VERSION 5.8 ;
BUSBITCHARS "[]" ;
DIVIDERCHAR "/" ;
UNITS
    DATABASE MICRONS 1000 ;
END UNITS

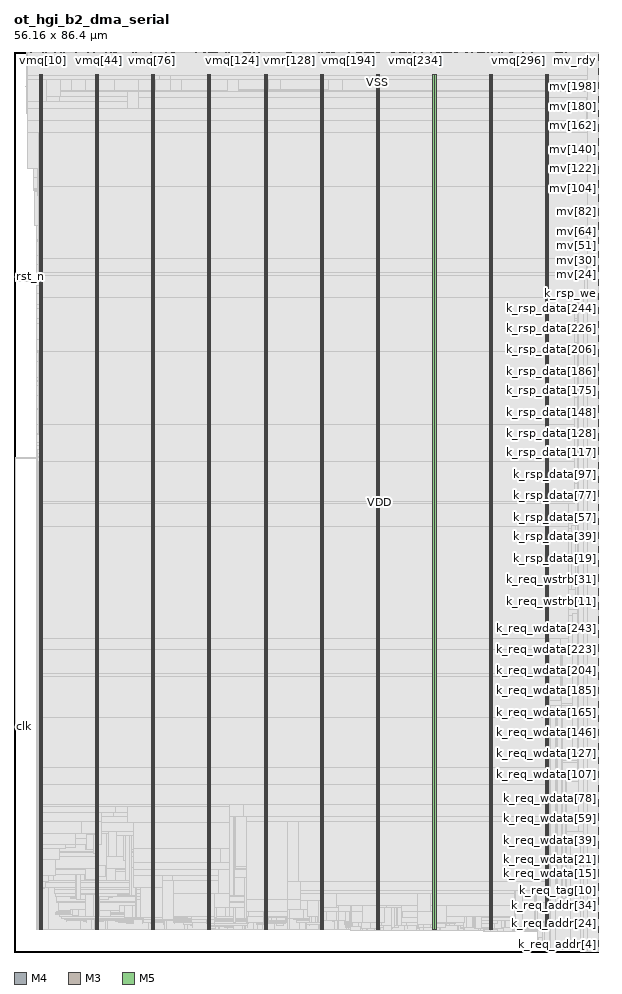
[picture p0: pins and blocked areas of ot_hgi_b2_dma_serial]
MACRO ot_hgi_b2_dma_serial
  FOREIGN ot_hgi_b2_dma_serial 0 0 ;
  CLASS BLOCK ;
  SIZE 56.16 BY 86.4 ;
  PIN clk
    DIRECTION INPUT ;
    USE SIGNAL ;
    PORT
      LAYER M4 ;
        RECT  0 21.6 0.084 21.624 ;
    END
    PORT
      LAYER M4 ;
        RECT  0.06 21.6 0.179 21.624 ;
    END
  END clk
  PIN fence_rdy
    DIRECTION OUTPUT ;
    USE SIGNAL ;
    PORT
      LAYER M4 ;
        RECT  56.076 0.048 56.16 0.072 ;
    END
  END fence_rdy
  PIN k_fault
    DIRECTION INPUT ;
    USE SIGNAL ;
    PORT
      LAYER M4 ;
        RECT  56.076 0.144 56.16 0.168 ;
    END
  END k_fault
  PIN k_req_addr[0]
    DIRECTION OUTPUT ;
    USE SIGNAL ;
    PORT
      LAYER M4 ;
        RECT  56.076 0.24 56.16 0.264 ;
    END
  END k_req_addr[0]
  PIN k_req_addr[10]
    DIRECTION OUTPUT ;
    USE SIGNAL ;
    PORT
      LAYER M4 ;
        RECT  56.076 1.296 56.16 1.32 ;
    END
  END k_req_addr[10]
  PIN k_req_addr[11]
    DIRECTION OUTPUT ;
    USE SIGNAL ;
    PORT
      LAYER M4 ;
        RECT  56.076 1.392 56.16 1.416 ;
    END
  END k_req_addr[11]
  PIN k_req_addr[12]
    DIRECTION OUTPUT ;
    USE SIGNAL ;
    PORT
      LAYER M4 ;
        RECT  56.076 1.488 56.16 1.512 ;
    END
  END k_req_addr[12]
  PIN k_req_addr[13]
    DIRECTION OUTPUT ;
    USE SIGNAL ;
    PORT
      LAYER M4 ;
        RECT  56.076 1.584 56.16 1.608 ;
    END
  END k_req_addr[13]
  PIN k_req_addr[14]
    DIRECTION OUTPUT ;
    USE SIGNAL ;
    PORT
      LAYER M4 ;
        RECT  56.076 1.68 56.16 1.704 ;
    END
  END k_req_addr[14]
  PIN k_req_addr[15]
    DIRECTION OUTPUT ;
    USE SIGNAL ;
    PORT
      LAYER M4 ;
        RECT  56.076 1.776 56.16 1.8 ;
    END
  END k_req_addr[15]
  PIN k_req_addr[16]
    DIRECTION OUTPUT ;
    USE SIGNAL ;
    PORT
      LAYER M4 ;
        RECT  56.076 1.92 56.16 1.944 ;
    END
  END k_req_addr[16]
  PIN k_req_addr[17]
    DIRECTION OUTPUT ;
    USE SIGNAL ;
    PORT
      LAYER M4 ;
        RECT  56.076 2.016 56.16 2.04 ;
    END
  END k_req_addr[17]
  PIN k_req_addr[18]
    DIRECTION OUTPUT ;
    USE SIGNAL ;
    PORT
      LAYER M4 ;
        RECT  56.076 2.112 56.16 2.136 ;
    END
  END k_req_addr[18]
  PIN k_req_addr[19]
    DIRECTION OUTPUT ;
    USE SIGNAL ;
    PORT
      LAYER M4 ;
        RECT  56.076 2.208 56.16 2.232 ;
    END
  END k_req_addr[19]
  PIN k_req_addr[1]
    DIRECTION OUTPUT ;
    USE SIGNAL ;
    PORT
      LAYER M4 ;
        RECT  56.076 0.336 56.16 0.36 ;
    END
  END k_req_addr[1]
  PIN k_req_addr[20]
    DIRECTION OUTPUT ;
    USE SIGNAL ;
    PORT
      LAYER M4 ;
        RECT  56.076 2.304 56.16 2.328 ;
    END
  END k_req_addr[20]
  PIN k_req_addr[21]
    DIRECTION OUTPUT ;
    USE SIGNAL ;
    PORT
      LAYER M4 ;
        RECT  56.076 2.4 56.16 2.424 ;
    END
  END k_req_addr[21]
  PIN k_req_addr[22]
    DIRECTION OUTPUT ;
    USE SIGNAL ;
    PORT
      LAYER M4 ;
        RECT  56.076 2.544 56.16 2.568 ;
    END
  END k_req_addr[22]
  PIN k_req_addr[23]
    DIRECTION OUTPUT ;
    USE SIGNAL ;
    PORT
      LAYER M4 ;
        RECT  56.076 2.64 56.16 2.664 ;
    END
  END k_req_addr[23]
  PIN k_req_addr[24]
    DIRECTION OUTPUT ;
    USE SIGNAL ;
    PORT
      LAYER M4 ;
        RECT  56.076 2.736 56.16 2.76 ;
    END
  END k_req_addr[24]
  PIN k_req_addr[25]
    DIRECTION OUTPUT ;
    USE SIGNAL ;
    PORT
      LAYER M4 ;
        RECT  56.076 2.832 56.16 2.856 ;
    END
  END k_req_addr[25]
  PIN k_req_addr[26]
    DIRECTION OUTPUT ;
    USE SIGNAL ;
    PORT
      LAYER M4 ;
        RECT  56.076 2.928 56.16 2.952 ;
    END
  END k_req_addr[26]
  PIN k_req_addr[27]
    DIRECTION OUTPUT ;
    USE SIGNAL ;
    PORT
      LAYER M4 ;
        RECT  56.076 3.024 56.16 3.048 ;
    END
  END k_req_addr[27]
  PIN k_req_addr[28]
    DIRECTION OUTPUT ;
    USE SIGNAL ;
    PORT
      LAYER M4 ;
        RECT  56.076 3.12 56.16 3.144 ;
    END
  END k_req_addr[28]
  PIN k_req_addr[29]
    DIRECTION OUTPUT ;
    USE SIGNAL ;
    PORT
      LAYER M4 ;
        RECT  56.076 3.264 56.16 3.288 ;
    END
  END k_req_addr[29]
  PIN k_req_addr[2]
    DIRECTION OUTPUT ;
    USE SIGNAL ;
    PORT
      LAYER M4 ;
        RECT  56.076 0.432 56.16 0.456 ;
    END
  END k_req_addr[2]
  PIN k_req_addr[30]
    DIRECTION OUTPUT ;
    USE SIGNAL ;
    PORT
      LAYER M4 ;
        RECT  56.076 3.36 56.16 3.384 ;
    END
  END k_req_addr[30]
  PIN k_req_addr[31]
    DIRECTION OUTPUT ;
    USE SIGNAL ;
    PORT
      LAYER M4 ;
        RECT  56.076 3.456 56.16 3.48 ;
    END
  END k_req_addr[31]
  PIN k_req_addr[32]
    DIRECTION OUTPUT ;
    USE SIGNAL ;
    PORT
      LAYER M4 ;
        RECT  56.076 3.552 56.16 3.576 ;
    END
  END k_req_addr[32]
  PIN k_req_addr[33]
    DIRECTION OUTPUT ;
    USE SIGNAL ;
    PORT
      LAYER M4 ;
        RECT  56.076 3.648 56.16 3.672 ;
    END
  END k_req_addr[33]
  PIN k_req_addr[34]
    DIRECTION OUTPUT ;
    USE SIGNAL ;
    PORT
      LAYER M4 ;
        RECT  56.076 3.744 56.16 3.768 ;
    END
  END k_req_addr[34]
  PIN k_req_addr[35]
    DIRECTION OUTPUT ;
    USE SIGNAL ;
    PORT
      LAYER M4 ;
        RECT  56.076 3.888 56.16 3.912 ;
    END
  END k_req_addr[35]
  PIN k_req_addr[36]
    DIRECTION OUTPUT ;
    USE SIGNAL ;
    PORT
      LAYER M4 ;
        RECT  56.076 3.984 56.16 4.008 ;
    END
  END k_req_addr[36]
  PIN k_req_addr[3]
    DIRECTION OUTPUT ;
    USE SIGNAL ;
    PORT
      LAYER M4 ;
        RECT  56.076 0.576 56.16 0.6 ;
    END
  END k_req_addr[3]
  PIN k_req_addr[4]
    DIRECTION OUTPUT ;
    USE SIGNAL ;
    PORT
      LAYER M4 ;
        RECT  56.076 0.672 56.16 0.696 ;
    END
  END k_req_addr[4]
  PIN k_req_addr[5]
    DIRECTION OUTPUT ;
    USE SIGNAL ;
    PORT
      LAYER M4 ;
        RECT  56.076 0.768 56.16 0.792 ;
    END
  END k_req_addr[5]
  PIN k_req_addr[6]
    DIRECTION OUTPUT ;
    USE SIGNAL ;
    PORT
      LAYER M4 ;
        RECT  56.076 0.864 56.16 0.888 ;
    END
  END k_req_addr[6]
  PIN k_req_addr[7]
    DIRECTION OUTPUT ;
    USE SIGNAL ;
    PORT
      LAYER M4 ;
        RECT  56.076 0.96 56.16 0.984 ;
    END
  END k_req_addr[7]
  PIN k_req_addr[8]
    DIRECTION OUTPUT ;
    USE SIGNAL ;
    PORT
      LAYER M4 ;
        RECT  56.076 1.056 56.16 1.08 ;
    END
  END k_req_addr[8]
  PIN k_req_addr[9]
    DIRECTION OUTPUT ;
    USE SIGNAL ;
    PORT
      LAYER M4 ;
        RECT  56.076 1.2 56.16 1.224 ;
    END
  END k_req_addr[9]
  PIN k_req_rdy
    DIRECTION INPUT ;
    USE SIGNAL ;
    PORT
      LAYER M4 ;
        RECT  56.076 4.08 56.16 4.104 ;
    END
  END k_req_rdy
  PIN k_req_tag[0]
    DIRECTION OUTPUT ;
    USE SIGNAL ;
    PORT
      LAYER M4 ;
        RECT  56.076 4.176 56.16 4.2 ;
    END
  END k_req_tag[0]
  PIN k_req_tag[10]
    DIRECTION OUTPUT ;
    USE SIGNAL ;
    PORT
      LAYER M4 ;
        RECT  56.076 5.184 56.16 5.208 ;
    END
  END k_req_tag[10]
  PIN k_req_tag[11]
    DIRECTION OUTPUT ;
    USE SIGNAL ;
    PORT
      LAYER M4 ;
        RECT  56.076 5.328 56.16 5.352 ;
    END
  END k_req_tag[11]
  PIN k_req_tag[12]
    DIRECTION OUTPUT ;
    USE SIGNAL ;
    PORT
      LAYER M4 ;
        RECT  56.076 5.424 56.16 5.448 ;
    END
  END k_req_tag[12]
  PIN k_req_tag[13]
    DIRECTION OUTPUT ;
    USE SIGNAL ;
    PORT
      LAYER M4 ;
        RECT  56.076 5.52 56.16 5.544 ;
    END
  END k_req_tag[13]
  PIN k_req_tag[14]
    DIRECTION OUTPUT ;
    USE SIGNAL ;
    PORT
      LAYER M4 ;
        RECT  56.076 5.616 56.16 5.64 ;
    END
  END k_req_tag[14]
  PIN k_req_tag[15]
    DIRECTION OUTPUT ;
    USE SIGNAL ;
    PORT
      LAYER M4 ;
        RECT  56.076 5.712 56.16 5.736 ;
    END
  END k_req_tag[15]
  PIN k_req_tag[1]
    DIRECTION OUTPUT ;
    USE SIGNAL ;
    PORT
      LAYER M4 ;
        RECT  56.076 4.272 56.16 4.296 ;
    END
  END k_req_tag[1]
  PIN k_req_tag[2]
    DIRECTION OUTPUT ;
    USE SIGNAL ;
    PORT
      LAYER M4 ;
        RECT  56.076 4.368 56.16 4.392 ;
    END
  END k_req_tag[2]
  PIN k_req_tag[3]
    DIRECTION OUTPUT ;
    USE SIGNAL ;
    PORT
      LAYER M4 ;
        RECT  56.076 4.464 56.16 4.488 ;
    END
  END k_req_tag[3]
  PIN k_req_tag[4]
    DIRECTION OUTPUT ;
    USE SIGNAL ;
    PORT
      LAYER M4 ;
        RECT  56.076 4.608 56.16 4.632 ;
    END
  END k_req_tag[4]
  PIN k_req_tag[5]
    DIRECTION OUTPUT ;
    USE SIGNAL ;
    PORT
      LAYER M4 ;
        RECT  56.076 4.704 56.16 4.728 ;
    END
  END k_req_tag[5]
  PIN k_req_tag[6]
    DIRECTION OUTPUT ;
    USE SIGNAL ;
    PORT
      LAYER M4 ;
        RECT  56.076 4.8 56.16 4.824 ;
    END
  END k_req_tag[6]
  PIN k_req_tag[7]
    DIRECTION OUTPUT ;
    USE SIGNAL ;
    PORT
      LAYER M4 ;
        RECT  56.076 4.896 56.16 4.92 ;
    END
  END k_req_tag[7]
  PIN k_req_tag[8]
    DIRECTION OUTPUT ;
    USE SIGNAL ;
    PORT
      LAYER M4 ;
        RECT  56.076 4.992 56.16 5.016 ;
    END
  END k_req_tag[8]
  PIN k_req_tag[9]
    DIRECTION OUTPUT ;
    USE SIGNAL ;
    PORT
      LAYER M4 ;
        RECT  56.076 5.088 56.16 5.112 ;
    END
  END k_req_tag[9]
  PIN k_req_v
    DIRECTION OUTPUT ;
    USE SIGNAL ;
    PORT
      LAYER M4 ;
        RECT  56.076 5.808 56.16 5.832 ;
    END
  END k_req_v
  PIN k_req_wdata[0]
    DIRECTION OUTPUT ;
    USE SIGNAL ;
    PORT
      LAYER M4 ;
        RECT  56.076 5.952 56.16 5.976 ;
    END
  END k_req_wdata[0]
  PIN k_req_wdata[100]
    DIRECTION OUTPUT ;
    USE SIGNAL ;
    PORT
      LAYER M4 ;
        RECT  56.076 16.272 56.16 16.296 ;
    END
  END k_req_wdata[100]
  PIN k_req_wdata[101]
    DIRECTION OUTPUT ;
    USE SIGNAL ;
    PORT
      LAYER M4 ;
        RECT  56.076 16.368 56.16 16.392 ;
    END
  END k_req_wdata[101]
  PIN k_req_wdata[102]
    DIRECTION OUTPUT ;
    USE SIGNAL ;
    PORT
      LAYER M4 ;
        RECT  56.076 16.464 56.16 16.488 ;
    END
  END k_req_wdata[102]
  PIN k_req_wdata[103]
    DIRECTION OUTPUT ;
    USE SIGNAL ;
    PORT
      LAYER M4 ;
        RECT  56.076 16.56 56.16 16.584 ;
    END
  END k_req_wdata[103]
  PIN k_req_wdata[104]
    DIRECTION OUTPUT ;
    USE SIGNAL ;
    PORT
      LAYER M4 ;
        RECT  56.076 16.656 56.16 16.68 ;
    END
  END k_req_wdata[104]
  PIN k_req_wdata[105]
    DIRECTION OUTPUT ;
    USE SIGNAL ;
    PORT
      LAYER M4 ;
        RECT  56.076 16.8 56.16 16.824 ;
    END
  END k_req_wdata[105]
  PIN k_req_wdata[106]
    DIRECTION OUTPUT ;
    USE SIGNAL ;
    PORT
      LAYER M4 ;
        RECT  56.076 16.896 56.16 16.92 ;
    END
  END k_req_wdata[106]
  PIN k_req_wdata[107]
    DIRECTION OUTPUT ;
    USE SIGNAL ;
    PORT
      LAYER M4 ;
        RECT  56.076 16.992 56.16 17.016 ;
    END
  END k_req_wdata[107]
  PIN k_req_wdata[108]
    DIRECTION OUTPUT ;
    USE SIGNAL ;
    PORT
      LAYER M4 ;
        RECT  56.076 17.088 56.16 17.112 ;
    END
  END k_req_wdata[108]
  PIN k_req_wdata[109]
    DIRECTION OUTPUT ;
    USE SIGNAL ;
    PORT
      LAYER M4 ;
        RECT  56.076 17.184 56.16 17.208 ;
    END
  END k_req_wdata[109]
  PIN k_req_wdata[10]
    DIRECTION OUTPUT ;
    USE SIGNAL ;
    PORT
      LAYER M4 ;
        RECT  56.076 6.96 56.16 6.984 ;
    END
  END k_req_wdata[10]
  PIN k_req_wdata[110]
    DIRECTION OUTPUT ;
    USE SIGNAL ;
    PORT
      LAYER M4 ;
        RECT  56.076 17.28 56.16 17.304 ;
    END
  END k_req_wdata[110]
  PIN k_req_wdata[111]
    DIRECTION OUTPUT ;
    USE SIGNAL ;
    PORT
      LAYER M4 ;
        RECT  56.076 17.424 56.16 17.448 ;
    END
  END k_req_wdata[111]
  PIN k_req_wdata[112]
    DIRECTION OUTPUT ;
    USE SIGNAL ;
    PORT
      LAYER M4 ;
        RECT  56.076 17.52 56.16 17.544 ;
    END
  END k_req_wdata[112]
  PIN k_req_wdata[113]
    DIRECTION OUTPUT ;
    USE SIGNAL ;
    PORT
      LAYER M4 ;
        RECT  56.076 17.616 56.16 17.64 ;
    END
  END k_req_wdata[113]
  PIN k_req_wdata[114]
    DIRECTION OUTPUT ;
    USE SIGNAL ;
    PORT
      LAYER M4 ;
        RECT  56.076 17.712 56.16 17.736 ;
    END
  END k_req_wdata[114]
  PIN k_req_wdata[115]
    DIRECTION OUTPUT ;
    USE SIGNAL ;
    PORT
      LAYER M4 ;
        RECT  56.076 17.808 56.16 17.832 ;
    END
  END k_req_wdata[115]
  PIN k_req_wdata[116]
    DIRECTION OUTPUT ;
    USE SIGNAL ;
    PORT
      LAYER M4 ;
        RECT  56.076 17.904 56.16 17.928 ;
    END
  END k_req_wdata[116]
  PIN k_req_wdata[117]
    DIRECTION OUTPUT ;
    USE SIGNAL ;
    PORT
      LAYER M4 ;
        RECT  56.076 18 56.16 18.024 ;
    END
  END k_req_wdata[117]
  PIN k_req_wdata[118]
    DIRECTION OUTPUT ;
    USE SIGNAL ;
    PORT
      LAYER M4 ;
        RECT  56.076 18.144 56.16 18.168 ;
    END
  END k_req_wdata[118]
  PIN k_req_wdata[119]
    DIRECTION OUTPUT ;
    USE SIGNAL ;
    PORT
      LAYER M4 ;
        RECT  56.076 18.24 56.16 18.264 ;
    END
  END k_req_wdata[119]
  PIN k_req_wdata[11]
    DIRECTION OUTPUT ;
    USE SIGNAL ;
    PORT
      LAYER M4 ;
        RECT  56.076 7.056 56.16 7.08 ;
    END
  END k_req_wdata[11]
  PIN k_req_wdata[120]
    DIRECTION OUTPUT ;
    USE SIGNAL ;
    PORT
      LAYER M4 ;
        RECT  56.076 18.336 56.16 18.36 ;
    END
  END k_req_wdata[120]
  PIN k_req_wdata[121]
    DIRECTION OUTPUT ;
    USE SIGNAL ;
    PORT
      LAYER M4 ;
        RECT  56.076 18.432 56.16 18.456 ;
    END
  END k_req_wdata[121]
  PIN k_req_wdata[122]
    DIRECTION OUTPUT ;
    USE SIGNAL ;
    PORT
      LAYER M4 ;
        RECT  56.076 18.528 56.16 18.552 ;
    END
  END k_req_wdata[122]
  PIN k_req_wdata[123]
    DIRECTION OUTPUT ;
    USE SIGNAL ;
    PORT
      LAYER M4 ;
        RECT  56.076 18.624 56.16 18.648 ;
    END
  END k_req_wdata[123]
  PIN k_req_wdata[124]
    DIRECTION OUTPUT ;
    USE SIGNAL ;
    PORT
      LAYER M4 ;
        RECT  56.076 18.768 56.16 18.792 ;
    END
  END k_req_wdata[124]
  PIN k_req_wdata[125]
    DIRECTION OUTPUT ;
    USE SIGNAL ;
    PORT
      LAYER M4 ;
        RECT  56.076 18.864 56.16 18.888 ;
    END
  END k_req_wdata[125]
  PIN k_req_wdata[126]
    DIRECTION OUTPUT ;
    USE SIGNAL ;
    PORT
      LAYER M4 ;
        RECT  56.076 18.96 56.16 18.984 ;
    END
  END k_req_wdata[126]
  PIN k_req_wdata[127]
    DIRECTION OUTPUT ;
    USE SIGNAL ;
    PORT
      LAYER M4 ;
        RECT  56.076 19.056 56.16 19.08 ;
    END
  END k_req_wdata[127]
  PIN k_req_wdata[128]
    DIRECTION OUTPUT ;
    USE SIGNAL ;
    PORT
      LAYER M4 ;
        RECT  56.076 19.152 56.16 19.176 ;
    END
  END k_req_wdata[128]
  PIN k_req_wdata[129]
    DIRECTION OUTPUT ;
    USE SIGNAL ;
    PORT
      LAYER M4 ;
        RECT  56.076 19.248 56.16 19.272 ;
    END
  END k_req_wdata[129]
  PIN k_req_wdata[12]
    DIRECTION OUTPUT ;
    USE SIGNAL ;
    PORT
      LAYER M4 ;
        RECT  56.076 7.152 56.16 7.176 ;
    END
  END k_req_wdata[12]
  PIN k_req_wdata[130]
    DIRECTION OUTPUT ;
    USE SIGNAL ;
    PORT
      LAYER M4 ;
        RECT  56.076 19.344 56.16 19.368 ;
    END
  END k_req_wdata[130]
  PIN k_req_wdata[131]
    DIRECTION OUTPUT ;
    USE SIGNAL ;
    PORT
      LAYER M4 ;
        RECT  56.076 19.488 56.16 19.512 ;
    END
  END k_req_wdata[131]
  PIN k_req_wdata[132]
    DIRECTION OUTPUT ;
    USE SIGNAL ;
    PORT
      LAYER M4 ;
        RECT  56.076 19.584 56.16 19.608 ;
    END
  END k_req_wdata[132]
  PIN k_req_wdata[133]
    DIRECTION OUTPUT ;
    USE SIGNAL ;
    PORT
      LAYER M4 ;
        RECT  56.076 19.68 56.16 19.704 ;
    END
  END k_req_wdata[133]
  PIN k_req_wdata[134]
    DIRECTION OUTPUT ;
    USE SIGNAL ;
    PORT
      LAYER M4 ;
        RECT  56.076 19.776 56.16 19.8 ;
    END
  END k_req_wdata[134]
  PIN k_req_wdata[135]
    DIRECTION OUTPUT ;
    USE SIGNAL ;
    PORT
      LAYER M4 ;
        RECT  56.076 19.872 56.16 19.896 ;
    END
  END k_req_wdata[135]
  PIN k_req_wdata[136]
    DIRECTION OUTPUT ;
    USE SIGNAL ;
    PORT
      LAYER M4 ;
        RECT  56.076 19.968 56.16 19.992 ;
    END
  END k_req_wdata[136]
  PIN k_req_wdata[137]
    DIRECTION OUTPUT ;
    USE SIGNAL ;
    PORT
      LAYER M4 ;
        RECT  56.076 20.112 56.16 20.136 ;
    END
  END k_req_wdata[137]
  PIN k_req_wdata[138]
    DIRECTION OUTPUT ;
    USE SIGNAL ;
    PORT
      LAYER M4 ;
        RECT  56.076 20.208 56.16 20.232 ;
    END
  END k_req_wdata[138]
  PIN k_req_wdata[139]
    DIRECTION OUTPUT ;
    USE SIGNAL ;
    PORT
      LAYER M4 ;
        RECT  56.076 20.304 56.16 20.328 ;
    END
  END k_req_wdata[139]
  PIN k_req_wdata[13]
    DIRECTION OUTPUT ;
    USE SIGNAL ;
    PORT
      LAYER M4 ;
        RECT  56.076 7.296 56.16 7.32 ;
    END
  END k_req_wdata[13]
  PIN k_req_wdata[140]
    DIRECTION OUTPUT ;
    USE SIGNAL ;
    PORT
      LAYER M4 ;
        RECT  56.076 20.4 56.16 20.424 ;
    END
  END k_req_wdata[140]
  PIN k_req_wdata[141]
    DIRECTION OUTPUT ;
    USE SIGNAL ;
    PORT
      LAYER M4 ;
        RECT  56.076 20.496 56.16 20.52 ;
    END
  END k_req_wdata[141]
  PIN k_req_wdata[142]
    DIRECTION OUTPUT ;
    USE SIGNAL ;
    PORT
      LAYER M4 ;
        RECT  56.076 20.592 56.16 20.616 ;
    END
  END k_req_wdata[142]
  PIN k_req_wdata[143]
    DIRECTION OUTPUT ;
    USE SIGNAL ;
    PORT
      LAYER M4 ;
        RECT  56.076 20.688 56.16 20.712 ;
    END
  END k_req_wdata[143]
  PIN k_req_wdata[144]
    DIRECTION OUTPUT ;
    USE SIGNAL ;
    PORT
      LAYER M4 ;
        RECT  56.076 20.832 56.16 20.856 ;
    END
  END k_req_wdata[144]
  PIN k_req_wdata[145]
    DIRECTION OUTPUT ;
    USE SIGNAL ;
    PORT
      LAYER M4 ;
        RECT  56.076 20.928 56.16 20.952 ;
    END
  END k_req_wdata[145]
  PIN k_req_wdata[146]
    DIRECTION OUTPUT ;
    USE SIGNAL ;
    PORT
      LAYER M4 ;
        RECT  56.076 21.024 56.16 21.048 ;
    END
  END k_req_wdata[146]
  PIN k_req_wdata[147]
    DIRECTION OUTPUT ;
    USE SIGNAL ;
    PORT
      LAYER M4 ;
        RECT  56.076 21.12 56.16 21.144 ;
    END
  END k_req_wdata[147]
  PIN k_req_wdata[148]
    DIRECTION OUTPUT ;
    USE SIGNAL ;
    PORT
      LAYER M4 ;
        RECT  56.076 21.216 56.16 21.24 ;
    END
  END k_req_wdata[148]
  PIN k_req_wdata[149]
    DIRECTION OUTPUT ;
    USE SIGNAL ;
    PORT
      LAYER M4 ;
        RECT  56.076 21.312 56.16 21.336 ;
    END
  END k_req_wdata[149]
  PIN k_req_wdata[14]
    DIRECTION OUTPUT ;
    USE SIGNAL ;
    PORT
      LAYER M4 ;
        RECT  56.076 7.392 56.16 7.416 ;
    END
  END k_req_wdata[14]
  PIN k_req_wdata[150]
    DIRECTION OUTPUT ;
    USE SIGNAL ;
    PORT
      LAYER M4 ;
        RECT  56.076 21.456 56.16 21.48 ;
    END
  END k_req_wdata[150]
  PIN k_req_wdata[151]
    DIRECTION OUTPUT ;
    USE SIGNAL ;
    PORT
      LAYER M4 ;
        RECT  56.076 21.552 56.16 21.576 ;
    END
  END k_req_wdata[151]
  PIN k_req_wdata[152]
    DIRECTION OUTPUT ;
    USE SIGNAL ;
    PORT
      LAYER M4 ;
        RECT  56.076 21.648 56.16 21.672 ;
    END
  END k_req_wdata[152]
  PIN k_req_wdata[153]
    DIRECTION OUTPUT ;
    USE SIGNAL ;
    PORT
      LAYER M4 ;
        RECT  56.076 21.744 56.16 21.768 ;
    END
  END k_req_wdata[153]
  PIN k_req_wdata[154]
    DIRECTION OUTPUT ;
    USE SIGNAL ;
    PORT
      LAYER M4 ;
        RECT  56.076 21.84 56.16 21.864 ;
    END
  END k_req_wdata[154]
  PIN k_req_wdata[155]
    DIRECTION OUTPUT ;
    USE SIGNAL ;
    PORT
      LAYER M4 ;
        RECT  56.076 21.936 56.16 21.96 ;
    END
  END k_req_wdata[155]
  PIN k_req_wdata[156]
    DIRECTION OUTPUT ;
    USE SIGNAL ;
    PORT
      LAYER M4 ;
        RECT  56.076 22.032 56.16 22.056 ;
    END
  END k_req_wdata[156]
  PIN k_req_wdata[157]
    DIRECTION OUTPUT ;
    USE SIGNAL ;
    PORT
      LAYER M4 ;
        RECT  56.076 22.176 56.16 22.2 ;
    END
  END k_req_wdata[157]
  PIN k_req_wdata[158]
    DIRECTION OUTPUT ;
    USE SIGNAL ;
    PORT
      LAYER M4 ;
        RECT  56.076 22.272 56.16 22.296 ;
    END
  END k_req_wdata[158]
  PIN k_req_wdata[159]
    DIRECTION OUTPUT ;
    USE SIGNAL ;
    PORT
      LAYER M4 ;
        RECT  56.076 22.368 56.16 22.392 ;
    END
  END k_req_wdata[159]
  PIN k_req_wdata[15]
    DIRECTION OUTPUT ;
    USE SIGNAL ;
    PORT
      LAYER M4 ;
        RECT  56.076 7.488 56.16 7.512 ;
    END
  END k_req_wdata[15]
  PIN k_req_wdata[160]
    DIRECTION OUTPUT ;
    USE SIGNAL ;
    PORT
      LAYER M4 ;
        RECT  56.076 22.464 56.16 22.488 ;
    END
  END k_req_wdata[160]
  PIN k_req_wdata[161]
    DIRECTION OUTPUT ;
    USE SIGNAL ;
    PORT
      LAYER M4 ;
        RECT  56.076 22.56 56.16 22.584 ;
    END
  END k_req_wdata[161]
  PIN k_req_wdata[162]
    DIRECTION OUTPUT ;
    USE SIGNAL ;
    PORT
      LAYER M4 ;
        RECT  56.076 22.656 56.16 22.68 ;
    END
  END k_req_wdata[162]
  PIN k_req_wdata[163]
    DIRECTION OUTPUT ;
    USE SIGNAL ;
    PORT
      LAYER M4 ;
        RECT  56.076 22.8 56.16 22.824 ;
    END
  END k_req_wdata[163]
  PIN k_req_wdata[164]
    DIRECTION OUTPUT ;
    USE SIGNAL ;
    PORT
      LAYER M4 ;
        RECT  56.076 22.896 56.16 22.92 ;
    END
  END k_req_wdata[164]
  PIN k_req_wdata[165]
    DIRECTION OUTPUT ;
    USE SIGNAL ;
    PORT
      LAYER M4 ;
        RECT  56.076 22.992 56.16 23.016 ;
    END
  END k_req_wdata[165]
  PIN k_req_wdata[166]
    DIRECTION OUTPUT ;
    USE SIGNAL ;
    PORT
      LAYER M4 ;
        RECT  56.076 23.088 56.16 23.112 ;
    END
  END k_req_wdata[166]
  PIN k_req_wdata[167]
    DIRECTION OUTPUT ;
    USE SIGNAL ;
    PORT
      LAYER M4 ;
        RECT  56.076 23.184 56.16 23.208 ;
    END
  END k_req_wdata[167]
  PIN k_req_wdata[168]
    DIRECTION OUTPUT ;
    USE SIGNAL ;
    PORT
      LAYER M4 ;
        RECT  56.076 23.28 56.16 23.304 ;
    END
  END k_req_wdata[168]
  PIN k_req_wdata[169]
    DIRECTION OUTPUT ;
    USE SIGNAL ;
    PORT
      LAYER M4 ;
        RECT  56.076 23.376 56.16 23.4 ;
    END
  END k_req_wdata[169]
  PIN k_req_wdata[16]
    DIRECTION OUTPUT ;
    USE SIGNAL ;
    PORT
      LAYER M4 ;
        RECT  56.076 7.584 56.16 7.608 ;
    END
  END k_req_wdata[16]
  PIN k_req_wdata[170]
    DIRECTION OUTPUT ;
    USE SIGNAL ;
    PORT
      LAYER M4 ;
        RECT  56.076 23.52 56.16 23.544 ;
    END
  END k_req_wdata[170]
  PIN k_req_wdata[171]
    DIRECTION OUTPUT ;
    USE SIGNAL ;
    PORT
      LAYER M4 ;
        RECT  56.076 23.616 56.16 23.64 ;
    END
  END k_req_wdata[171]
  PIN k_req_wdata[172]
    DIRECTION OUTPUT ;
    USE SIGNAL ;
    PORT
      LAYER M4 ;
        RECT  56.076 23.712 56.16 23.736 ;
    END
  END k_req_wdata[172]
  PIN k_req_wdata[173]
    DIRECTION OUTPUT ;
    USE SIGNAL ;
    PORT
      LAYER M4 ;
        RECT  56.076 23.808 56.16 23.832 ;
    END
  END k_req_wdata[173]
  PIN k_req_wdata[174]
    DIRECTION OUTPUT ;
    USE SIGNAL ;
    PORT
      LAYER M4 ;
        RECT  56.076 23.904 56.16 23.928 ;
    END
  END k_req_wdata[174]
  PIN k_req_wdata[175]
    DIRECTION OUTPUT ;
    USE SIGNAL ;
    PORT
      LAYER M4 ;
        RECT  56.076 24 56.16 24.024 ;
    END
  END k_req_wdata[175]
  PIN k_req_wdata[176]
    DIRECTION OUTPUT ;
    USE SIGNAL ;
    PORT
      LAYER M4 ;
        RECT  56.076 24.144 56.16 24.168 ;
    END
  END k_req_wdata[176]
  PIN k_req_wdata[177]
    DIRECTION OUTPUT ;
    USE SIGNAL ;
    PORT
      LAYER M4 ;
        RECT  56.076 24.24 56.16 24.264 ;
    END
  END k_req_wdata[177]
  PIN k_req_wdata[178]
    DIRECTION OUTPUT ;
    USE SIGNAL ;
    PORT
      LAYER M4 ;
        RECT  56.076 24.336 56.16 24.36 ;
    END
  END k_req_wdata[178]
  PIN k_req_wdata[179]
    DIRECTION OUTPUT ;
    USE SIGNAL ;
    PORT
      LAYER M4 ;
        RECT  56.076 24.432 56.16 24.456 ;
    END
  END k_req_wdata[179]
  PIN k_req_wdata[17]
    DIRECTION OUTPUT ;
    USE SIGNAL ;
    PORT
      LAYER M4 ;
        RECT  56.076 7.68 56.16 7.704 ;
    END
  END k_req_wdata[17]
  PIN k_req_wdata[180]
    DIRECTION OUTPUT ;
    USE SIGNAL ;
    PORT
      LAYER M4 ;
        RECT  56.076 24.528 56.16 24.552 ;
    END
  END k_req_wdata[180]
  PIN k_req_wdata[181]
    DIRECTION OUTPUT ;
    USE SIGNAL ;
    PORT
      LAYER M4 ;
        RECT  56.076 24.624 56.16 24.648 ;
    END
  END k_req_wdata[181]
  PIN k_req_wdata[182]
    DIRECTION OUTPUT ;
    USE SIGNAL ;
    PORT
      LAYER M4 ;
        RECT  56.076 24.72 56.16 24.744 ;
    END
  END k_req_wdata[182]
  PIN k_req_wdata[183]
    DIRECTION OUTPUT ;
    USE SIGNAL ;
    PORT
      LAYER M4 ;
        RECT  56.076 24.864 56.16 24.888 ;
    END
  END k_req_wdata[183]
  PIN k_req_wdata[184]
    DIRECTION OUTPUT ;
    USE SIGNAL ;
    PORT
      LAYER M4 ;
        RECT  56.076 24.96 56.16 24.984 ;
    END
  END k_req_wdata[184]
  PIN k_req_wdata[185]
    DIRECTION OUTPUT ;
    USE SIGNAL ;
    PORT
      LAYER M4 ;
        RECT  56.076 25.056 56.16 25.08 ;
    END
  END k_req_wdata[185]
  PIN k_req_wdata[186]
    DIRECTION OUTPUT ;
    USE SIGNAL ;
    PORT
      LAYER M4 ;
        RECT  56.076 25.152 56.16 25.176 ;
    END
  END k_req_wdata[186]
  PIN k_req_wdata[187]
    DIRECTION OUTPUT ;
    USE SIGNAL ;
    PORT
      LAYER M4 ;
        RECT  56.076 25.248 56.16 25.272 ;
    END
  END k_req_wdata[187]
  PIN k_req_wdata[188]
    DIRECTION OUTPUT ;
    USE SIGNAL ;
    PORT
      LAYER M4 ;
        RECT  56.076 25.344 56.16 25.368 ;
    END
  END k_req_wdata[188]
  PIN k_req_wdata[189]
    DIRECTION OUTPUT ;
    USE SIGNAL ;
    PORT
      LAYER M4 ;
        RECT  56.076 25.488 56.16 25.512 ;
    END
  END k_req_wdata[189]
  PIN k_req_wdata[18]
    DIRECTION OUTPUT ;
    USE SIGNAL ;
    PORT
      LAYER M4 ;
        RECT  56.076 7.776 56.16 7.8 ;
    END
  END k_req_wdata[18]
  PIN k_req_wdata[190]
    DIRECTION OUTPUT ;
    USE SIGNAL ;
    PORT
      LAYER M4 ;
        RECT  56.076 25.584 56.16 25.608 ;
    END
  END k_req_wdata[190]
  PIN k_req_wdata[191]
    DIRECTION OUTPUT ;
    USE SIGNAL ;
    PORT
      LAYER M4 ;
        RECT  56.076 25.68 56.16 25.704 ;
    END
  END k_req_wdata[191]
  PIN k_req_wdata[192]
    DIRECTION OUTPUT ;
    USE SIGNAL ;
    PORT
      LAYER M4 ;
        RECT  56.076 25.776 56.16 25.8 ;
    END
  END k_req_wdata[192]
  PIN k_req_wdata[193]
    DIRECTION OUTPUT ;
    USE SIGNAL ;
    PORT
      LAYER M4 ;
        RECT  56.076 25.872 56.16 25.896 ;
    END
  END k_req_wdata[193]
  PIN k_req_wdata[194]
    DIRECTION OUTPUT ;
    USE SIGNAL ;
    PORT
      LAYER M4 ;
        RECT  56.076 25.968 56.16 25.992 ;
    END
  END k_req_wdata[194]
  PIN k_req_wdata[195]
    DIRECTION OUTPUT ;
    USE SIGNAL ;
    PORT
      LAYER M4 ;
        RECT  56.076 26.064 56.16 26.088 ;
    END
  END k_req_wdata[195]
  PIN k_req_wdata[196]
    DIRECTION OUTPUT ;
    USE SIGNAL ;
    PORT
      LAYER M4 ;
        RECT  56.076 26.208 56.16 26.232 ;
    END
  END k_req_wdata[196]
  PIN k_req_wdata[197]
    DIRECTION OUTPUT ;
    USE SIGNAL ;
    PORT
      LAYER M4 ;
        RECT  56.076 26.304 56.16 26.328 ;
    END
  END k_req_wdata[197]
  PIN k_req_wdata[198]
    DIRECTION OUTPUT ;
    USE SIGNAL ;
    PORT
      LAYER M4 ;
        RECT  56.076 26.4 56.16 26.424 ;
    END
  END k_req_wdata[198]
  PIN k_req_wdata[199]
    DIRECTION OUTPUT ;
    USE SIGNAL ;
    PORT
      LAYER M4 ;
        RECT  56.076 26.496 56.16 26.52 ;
    END
  END k_req_wdata[199]
  PIN k_req_wdata[19]
    DIRECTION OUTPUT ;
    USE SIGNAL ;
    PORT
      LAYER M4 ;
        RECT  56.076 7.872 56.16 7.896 ;
    END
  END k_req_wdata[19]
  PIN k_req_wdata[1]
    DIRECTION OUTPUT ;
    USE SIGNAL ;
    PORT
      LAYER M4 ;
        RECT  56.076 6.048 56.16 6.072 ;
    END
  END k_req_wdata[1]
  PIN k_req_wdata[200]
    DIRECTION OUTPUT ;
    USE SIGNAL ;
    PORT
      LAYER M4 ;
        RECT  56.076 26.592 56.16 26.616 ;
    END
  END k_req_wdata[200]
  PIN k_req_wdata[201]
    DIRECTION OUTPUT ;
    USE SIGNAL ;
    PORT
      LAYER M4 ;
        RECT  56.076 26.688 56.16 26.712 ;
    END
  END k_req_wdata[201]
  PIN k_req_wdata[202]
    DIRECTION OUTPUT ;
    USE SIGNAL ;
    PORT
      LAYER M4 ;
        RECT  56.076 26.784 56.16 26.808 ;
    END
  END k_req_wdata[202]
  PIN k_req_wdata[203]
    DIRECTION OUTPUT ;
    USE SIGNAL ;
    PORT
      LAYER M4 ;
        RECT  56.076 26.928 56.16 26.952 ;
    END
  END k_req_wdata[203]
  PIN k_req_wdata[204]
    DIRECTION OUTPUT ;
    USE SIGNAL ;
    PORT
      LAYER M4 ;
        RECT  56.076 27.024 56.16 27.048 ;
    END
  END k_req_wdata[204]
  PIN k_req_wdata[205]
    DIRECTION OUTPUT ;
    USE SIGNAL ;
    PORT
      LAYER M4 ;
        RECT  56.076 27.12 56.16 27.144 ;
    END
  END k_req_wdata[205]
  PIN k_req_wdata[206]
    DIRECTION OUTPUT ;
    USE SIGNAL ;
    PORT
      LAYER M4 ;
        RECT  56.076 27.216 56.16 27.24 ;
    END
  END k_req_wdata[206]
  PIN k_req_wdata[207]
    DIRECTION OUTPUT ;
    USE SIGNAL ;
    PORT
      LAYER M4 ;
        RECT  56.076 27.312 56.16 27.336 ;
    END
  END k_req_wdata[207]
  PIN k_req_wdata[208]
    DIRECTION OUTPUT ;
    USE SIGNAL ;
    PORT
      LAYER M4 ;
        RECT  56.076 27.408 56.16 27.432 ;
    END
  END k_req_wdata[208]
  PIN k_req_wdata[209]
    DIRECTION OUTPUT ;
    USE SIGNAL ;
    PORT
      LAYER M4 ;
        RECT  56.076 27.552 56.16 27.576 ;
    END
  END k_req_wdata[209]
  PIN k_req_wdata[20]
    DIRECTION OUTPUT ;
    USE SIGNAL ;
    PORT
      LAYER M4 ;
        RECT  56.076 8.016 56.16 8.04 ;
    END
  END k_req_wdata[20]
  PIN k_req_wdata[210]
    DIRECTION OUTPUT ;
    USE SIGNAL ;
    PORT
      LAYER M4 ;
        RECT  56.076 27.648 56.16 27.672 ;
    END
  END k_req_wdata[210]
  PIN k_req_wdata[211]
    DIRECTION OUTPUT ;
    USE SIGNAL ;
    PORT
      LAYER M4 ;
        RECT  56.076 27.744 56.16 27.768 ;
    END
  END k_req_wdata[211]
  PIN k_req_wdata[212]
    DIRECTION OUTPUT ;
    USE SIGNAL ;
    PORT
      LAYER M4 ;
        RECT  56.076 27.84 56.16 27.864 ;
    END
  END k_req_wdata[212]
  PIN k_req_wdata[213]
    DIRECTION OUTPUT ;
    USE SIGNAL ;
    PORT
      LAYER M4 ;
        RECT  56.076 27.936 56.16 27.96 ;
    END
  END k_req_wdata[213]
  PIN k_req_wdata[214]
    DIRECTION OUTPUT ;
    USE SIGNAL ;
    PORT
      LAYER M4 ;
        RECT  56.076 28.032 56.16 28.056 ;
    END
  END k_req_wdata[214]
  PIN k_req_wdata[215]
    DIRECTION OUTPUT ;
    USE SIGNAL ;
    PORT
      LAYER M4 ;
        RECT  56.076 28.128 56.16 28.152 ;
    END
  END k_req_wdata[215]
  PIN k_req_wdata[216]
    DIRECTION OUTPUT ;
    USE SIGNAL ;
    PORT
      LAYER M4 ;
        RECT  56.076 28.272 56.16 28.296 ;
    END
  END k_req_wdata[216]
  PIN k_req_wdata[217]
    DIRECTION OUTPUT ;
    USE SIGNAL ;
    PORT
      LAYER M4 ;
        RECT  56.076 28.368 56.16 28.392 ;
    END
  END k_req_wdata[217]
  PIN k_req_wdata[218]
    DIRECTION OUTPUT ;
    USE SIGNAL ;
    PORT
      LAYER M4 ;
        RECT  56.076 28.464 56.16 28.488 ;
    END
  END k_req_wdata[218]
  PIN k_req_wdata[219]
    DIRECTION OUTPUT ;
    USE SIGNAL ;
    PORT
      LAYER M4 ;
        RECT  56.076 28.56 56.16 28.584 ;
    END
  END k_req_wdata[219]
  PIN k_req_wdata[21]
    DIRECTION OUTPUT ;
    USE SIGNAL ;
    PORT
      LAYER M4 ;
        RECT  56.076 8.112 56.16 8.136 ;
    END
  END k_req_wdata[21]
  PIN k_req_wdata[220]
    DIRECTION OUTPUT ;
    USE SIGNAL ;
    PORT
      LAYER M4 ;
        RECT  56.076 28.656 56.16 28.68 ;
    END
  END k_req_wdata[220]
  PIN k_req_wdata[221]
    DIRECTION OUTPUT ;
    USE SIGNAL ;
    PORT
      LAYER M4 ;
        RECT  56.076 28.752 56.16 28.776 ;
    END
  END k_req_wdata[221]
  PIN k_req_wdata[222]
    DIRECTION OUTPUT ;
    USE SIGNAL ;
    PORT
      LAYER M4 ;
        RECT  56.076 28.896 56.16 28.92 ;
    END
  END k_req_wdata[222]
  PIN k_req_wdata[223]
    DIRECTION OUTPUT ;
    USE SIGNAL ;
    PORT
      LAYER M4 ;
        RECT  56.076 28.992 56.16 29.016 ;
    END
  END k_req_wdata[223]
  PIN k_req_wdata[224]
    DIRECTION OUTPUT ;
    USE SIGNAL ;
    PORT
      LAYER M4 ;
        RECT  56.076 29.088 56.16 29.112 ;
    END
  END k_req_wdata[224]
  PIN k_req_wdata[225]
    DIRECTION OUTPUT ;
    USE SIGNAL ;
    PORT
      LAYER M4 ;
        RECT  56.076 29.184 56.16 29.208 ;
    END
  END k_req_wdata[225]
  PIN k_req_wdata[226]
    DIRECTION OUTPUT ;
    USE SIGNAL ;
    PORT
      LAYER M4 ;
        RECT  56.076 29.28 56.16 29.304 ;
    END
  END k_req_wdata[226]
  PIN k_req_wdata[227]
    DIRECTION OUTPUT ;
    USE SIGNAL ;
    PORT
      LAYER M4 ;
        RECT  56.076 29.376 56.16 29.4 ;
    END
  END k_req_wdata[227]
  PIN k_req_wdata[228]
    DIRECTION OUTPUT ;
    USE SIGNAL ;
    PORT
      LAYER M4 ;
        RECT  56.076 29.472 56.16 29.496 ;
    END
  END k_req_wdata[228]
  PIN k_req_wdata[229]
    DIRECTION OUTPUT ;
    USE SIGNAL ;
    PORT
      LAYER M4 ;
        RECT  56.076 29.616 56.16 29.64 ;
    END
  END k_req_wdata[229]
  PIN k_req_wdata[22]
    DIRECTION OUTPUT ;
    USE SIGNAL ;
    PORT
      LAYER M4 ;
        RECT  56.076 8.208 56.16 8.232 ;
    END
  END k_req_wdata[22]
  PIN k_req_wdata[230]
    DIRECTION OUTPUT ;
    USE SIGNAL ;
    PORT
      LAYER M4 ;
        RECT  56.076 29.712 56.16 29.736 ;
    END
  END k_req_wdata[230]
  PIN k_req_wdata[231]
    DIRECTION OUTPUT ;
    USE SIGNAL ;
    PORT
      LAYER M4 ;
        RECT  56.076 29.808 56.16 29.832 ;
    END
  END k_req_wdata[231]
  PIN k_req_wdata[232]
    DIRECTION OUTPUT ;
    USE SIGNAL ;
    PORT
      LAYER M4 ;
        RECT  56.076 29.904 56.16 29.928 ;
    END
  END k_req_wdata[232]
  PIN k_req_wdata[233]
    DIRECTION OUTPUT ;
    USE SIGNAL ;
    PORT
      LAYER M4 ;
        RECT  56.076 30 56.16 30.024 ;
    END
  END k_req_wdata[233]
  PIN k_req_wdata[234]
    DIRECTION OUTPUT ;
    USE SIGNAL ;
    PORT
      LAYER M4 ;
        RECT  56.076 30.096 56.16 30.12 ;
    END
  END k_req_wdata[234]
  PIN k_req_wdata[235]
    DIRECTION OUTPUT ;
    USE SIGNAL ;
    PORT
      LAYER M4 ;
        RECT  56.076 30.24 56.16 30.264 ;
    END
  END k_req_wdata[235]
  PIN k_req_wdata[236]
    DIRECTION OUTPUT ;
    USE SIGNAL ;
    PORT
      LAYER M4 ;
        RECT  56.076 30.336 56.16 30.36 ;
    END
  END k_req_wdata[236]
  PIN k_req_wdata[237]
    DIRECTION OUTPUT ;
    USE SIGNAL ;
    PORT
      LAYER M4 ;
        RECT  56.076 30.432 56.16 30.456 ;
    END
  END k_req_wdata[237]
  PIN k_req_wdata[238]
    DIRECTION OUTPUT ;
    USE SIGNAL ;
    PORT
      LAYER M4 ;
        RECT  56.076 30.528 56.16 30.552 ;
    END
  END k_req_wdata[238]
  PIN k_req_wdata[239]
    DIRECTION OUTPUT ;
    USE SIGNAL ;
    PORT
      LAYER M4 ;
        RECT  56.076 30.624 56.16 30.648 ;
    END
  END k_req_wdata[239]
  PIN k_req_wdata[23]
    DIRECTION OUTPUT ;
    USE SIGNAL ;
    PORT
      LAYER M4 ;
        RECT  56.076 8.304 56.16 8.328 ;
    END
  END k_req_wdata[23]
  PIN k_req_wdata[240]
    DIRECTION OUTPUT ;
    USE SIGNAL ;
    PORT
      LAYER M4 ;
        RECT  56.076 30.72 56.16 30.744 ;
    END
  END k_req_wdata[240]
  PIN k_req_wdata[241]
    DIRECTION OUTPUT ;
    USE SIGNAL ;
    PORT
      LAYER M4 ;
        RECT  56.076 30.816 56.16 30.84 ;
    END
  END k_req_wdata[241]
  PIN k_req_wdata[242]
    DIRECTION OUTPUT ;
    USE SIGNAL ;
    PORT
      LAYER M4 ;
        RECT  56.076 30.96 56.16 30.984 ;
    END
  END k_req_wdata[242]
  PIN k_req_wdata[243]
    DIRECTION OUTPUT ;
    USE SIGNAL ;
    PORT
      LAYER M4 ;
        RECT  56.076 31.056 56.16 31.08 ;
    END
  END k_req_wdata[243]
  PIN k_req_wdata[244]
    DIRECTION OUTPUT ;
    USE SIGNAL ;
    PORT
      LAYER M4 ;
        RECT  56.076 31.152 56.16 31.176 ;
    END
  END k_req_wdata[244]
  PIN k_req_wdata[245]
    DIRECTION OUTPUT ;
    USE SIGNAL ;
    PORT
      LAYER M4 ;
        RECT  56.076 31.248 56.16 31.272 ;
    END
  END k_req_wdata[245]
  PIN k_req_wdata[246]
    DIRECTION OUTPUT ;
    USE SIGNAL ;
    PORT
      LAYER M4 ;
        RECT  56.076 31.344 56.16 31.368 ;
    END
  END k_req_wdata[246]
  PIN k_req_wdata[247]
    DIRECTION OUTPUT ;
    USE SIGNAL ;
    PORT
      LAYER M4 ;
        RECT  56.076 31.44 56.16 31.464 ;
    END
  END k_req_wdata[247]
  PIN k_req_wdata[248]
    DIRECTION OUTPUT ;
    USE SIGNAL ;
    PORT
      LAYER M4 ;
        RECT  56.076 31.584 56.16 31.608 ;
    END
  END k_req_wdata[248]
  PIN k_req_wdata[249]
    DIRECTION OUTPUT ;
    USE SIGNAL ;
    PORT
      LAYER M4 ;
        RECT  56.076 31.68 56.16 31.704 ;
    END
  END k_req_wdata[249]
  PIN k_req_wdata[24]
    DIRECTION OUTPUT ;
    USE SIGNAL ;
    PORT
      LAYER M4 ;
        RECT  56.076 8.4 56.16 8.424 ;
    END
  END k_req_wdata[24]
  PIN k_req_wdata[250]
    DIRECTION OUTPUT ;
    USE SIGNAL ;
    PORT
      LAYER M4 ;
        RECT  56.076 31.776 56.16 31.8 ;
    END
  END k_req_wdata[250]
  PIN k_req_wdata[251]
    DIRECTION OUTPUT ;
    USE SIGNAL ;
    PORT
      LAYER M4 ;
        RECT  56.076 31.872 56.16 31.896 ;
    END
  END k_req_wdata[251]
  PIN k_req_wdata[252]
    DIRECTION OUTPUT ;
    USE SIGNAL ;
    PORT
      LAYER M4 ;
        RECT  56.076 31.968 56.16 31.992 ;
    END
  END k_req_wdata[252]
  PIN k_req_wdata[253]
    DIRECTION OUTPUT ;
    USE SIGNAL ;
    PORT
      LAYER M4 ;
        RECT  56.076 32.064 56.16 32.088 ;
    END
  END k_req_wdata[253]
  PIN k_req_wdata[254]
    DIRECTION OUTPUT ;
    USE SIGNAL ;
    PORT
      LAYER M4 ;
        RECT  56.076 32.16 56.16 32.184 ;
    END
  END k_req_wdata[254]
  PIN k_req_wdata[255]
    DIRECTION OUTPUT ;
    USE SIGNAL ;
    PORT
      LAYER M4 ;
        RECT  56.076 32.304 56.16 32.328 ;
    END
  END k_req_wdata[255]
  PIN k_req_wdata[25]
    DIRECTION OUTPUT ;
    USE SIGNAL ;
    PORT
      LAYER M4 ;
        RECT  56.076 8.496 56.16 8.52 ;
    END
  END k_req_wdata[25]
  PIN k_req_wdata[26]
    DIRECTION OUTPUT ;
    USE SIGNAL ;
    PORT
      LAYER M4 ;
        RECT  56.076 8.64 56.16 8.664 ;
    END
  END k_req_wdata[26]
  PIN k_req_wdata[27]
    DIRECTION OUTPUT ;
    USE SIGNAL ;
    PORT
      LAYER M4 ;
        RECT  56.076 8.736 56.16 8.76 ;
    END
  END k_req_wdata[27]
  PIN k_req_wdata[28]
    DIRECTION OUTPUT ;
    USE SIGNAL ;
    PORT
      LAYER M4 ;
        RECT  56.076 8.832 56.16 8.856 ;
    END
  END k_req_wdata[28]
  PIN k_req_wdata[29]
    DIRECTION OUTPUT ;
    USE SIGNAL ;
    PORT
      LAYER M4 ;
        RECT  56.076 8.928 56.16 8.952 ;
    END
  END k_req_wdata[29]
  PIN k_req_wdata[2]
    DIRECTION OUTPUT ;
    USE SIGNAL ;
    PORT
      LAYER M4 ;
        RECT  56.076 6.144 56.16 6.168 ;
    END
  END k_req_wdata[2]
  PIN k_req_wdata[30]
    DIRECTION OUTPUT ;
    USE SIGNAL ;
    PORT
      LAYER M4 ;
        RECT  56.076 9.024 56.16 9.048 ;
    END
  END k_req_wdata[30]
  PIN k_req_wdata[31]
    DIRECTION OUTPUT ;
    USE SIGNAL ;
    PORT
      LAYER M4 ;
        RECT  56.076 9.12 56.16 9.144 ;
    END
  END k_req_wdata[31]
  PIN k_req_wdata[32]
    DIRECTION OUTPUT ;
    USE SIGNAL ;
    PORT
      LAYER M4 ;
        RECT  56.076 9.216 56.16 9.24 ;
    END
  END k_req_wdata[32]
  PIN k_req_wdata[33]
    DIRECTION OUTPUT ;
    USE SIGNAL ;
    PORT
      LAYER M4 ;
        RECT  56.076 9.36 56.16 9.384 ;
    END
  END k_req_wdata[33]
  PIN k_req_wdata[34]
    DIRECTION OUTPUT ;
    USE SIGNAL ;
    PORT
      LAYER M4 ;
        RECT  56.076 9.456 56.16 9.48 ;
    END
  END k_req_wdata[34]
  PIN k_req_wdata[35]
    DIRECTION OUTPUT ;
    USE SIGNAL ;
    PORT
      LAYER M4 ;
        RECT  56.076 9.552 56.16 9.576 ;
    END
  END k_req_wdata[35]
  PIN k_req_wdata[36]
    DIRECTION OUTPUT ;
    USE SIGNAL ;
    PORT
      LAYER M4 ;
        RECT  56.076 9.648 56.16 9.672 ;
    END
  END k_req_wdata[36]
  PIN k_req_wdata[37]
    DIRECTION OUTPUT ;
    USE SIGNAL ;
    PORT
      LAYER M4 ;
        RECT  56.076 9.744 56.16 9.768 ;
    END
  END k_req_wdata[37]
  PIN k_req_wdata[38]
    DIRECTION OUTPUT ;
    USE SIGNAL ;
    PORT
      LAYER M4 ;
        RECT  56.076 9.84 56.16 9.864 ;
    END
  END k_req_wdata[38]
  PIN k_req_wdata[39]
    DIRECTION OUTPUT ;
    USE SIGNAL ;
    PORT
      LAYER M4 ;
        RECT  56.076 9.984 56.16 10.008 ;
    END
  END k_req_wdata[39]
  PIN k_req_wdata[3]
    DIRECTION OUTPUT ;
    USE SIGNAL ;
    PORT
      LAYER M4 ;
        RECT  56.076 6.24 56.16 6.264 ;
    END
  END k_req_wdata[3]
  PIN k_req_wdata[40]
    DIRECTION OUTPUT ;
    USE SIGNAL ;
    PORT
      LAYER M4 ;
        RECT  56.076 10.08 56.16 10.104 ;
    END
  END k_req_wdata[40]
  PIN k_req_wdata[41]
    DIRECTION OUTPUT ;
    USE SIGNAL ;
    PORT
      LAYER M4 ;
        RECT  56.076 10.176 56.16 10.2 ;
    END
  END k_req_wdata[41]
  PIN k_req_wdata[42]
    DIRECTION OUTPUT ;
    USE SIGNAL ;
    PORT
      LAYER M4 ;
        RECT  56.076 10.272 56.16 10.296 ;
    END
  END k_req_wdata[42]
  PIN k_req_wdata[43]
    DIRECTION OUTPUT ;
    USE SIGNAL ;
    PORT
      LAYER M4 ;
        RECT  56.076 10.368 56.16 10.392 ;
    END
  END k_req_wdata[43]
  PIN k_req_wdata[44]
    DIRECTION OUTPUT ;
    USE SIGNAL ;
    PORT
      LAYER M4 ;
        RECT  56.076 10.464 56.16 10.488 ;
    END
  END k_req_wdata[44]
  PIN k_req_wdata[45]
    DIRECTION OUTPUT ;
    USE SIGNAL ;
    PORT
      LAYER M4 ;
        RECT  56.076 10.56 56.16 10.584 ;
    END
  END k_req_wdata[45]
  PIN k_req_wdata[46]
    DIRECTION OUTPUT ;
    USE SIGNAL ;
    PORT
      LAYER M4 ;
        RECT  56.076 10.704 56.16 10.728 ;
    END
  END k_req_wdata[46]
  PIN k_req_wdata[47]
    DIRECTION OUTPUT ;
    USE SIGNAL ;
    PORT
      LAYER M4 ;
        RECT  56.076 10.8 56.16 10.824 ;
    END
  END k_req_wdata[47]
  PIN k_req_wdata[48]
    DIRECTION OUTPUT ;
    USE SIGNAL ;
    PORT
      LAYER M4 ;
        RECT  56.076 10.896 56.16 10.92 ;
    END
  END k_req_wdata[48]
  PIN k_req_wdata[49]
    DIRECTION OUTPUT ;
    USE SIGNAL ;
    PORT
      LAYER M4 ;
        RECT  56.076 10.992 56.16 11.016 ;
    END
  END k_req_wdata[49]
  PIN k_req_wdata[4]
    DIRECTION OUTPUT ;
    USE SIGNAL ;
    PORT
      LAYER M4 ;
        RECT  56.076 6.336 56.16 6.36 ;
    END
  END k_req_wdata[4]
  PIN k_req_wdata[50]
    DIRECTION OUTPUT ;
    USE SIGNAL ;
    PORT
      LAYER M4 ;
        RECT  56.076 11.088 56.16 11.112 ;
    END
  END k_req_wdata[50]
  PIN k_req_wdata[51]
    DIRECTION OUTPUT ;
    USE SIGNAL ;
    PORT
      LAYER M4 ;
        RECT  56.076 11.184 56.16 11.208 ;
    END
  END k_req_wdata[51]
  PIN k_req_wdata[52]
    DIRECTION OUTPUT ;
    USE SIGNAL ;
    PORT
      LAYER M4 ;
        RECT  56.076 11.328 56.16 11.352 ;
    END
  END k_req_wdata[52]
  PIN k_req_wdata[53]
    DIRECTION OUTPUT ;
    USE SIGNAL ;
    PORT
      LAYER M4 ;
        RECT  56.076 11.424 56.16 11.448 ;
    END
  END k_req_wdata[53]
  PIN k_req_wdata[54]
    DIRECTION OUTPUT ;
    USE SIGNAL ;
    PORT
      LAYER M4 ;
        RECT  56.076 11.52 56.16 11.544 ;
    END
  END k_req_wdata[54]
  PIN k_req_wdata[55]
    DIRECTION OUTPUT ;
    USE SIGNAL ;
    PORT
      LAYER M4 ;
        RECT  56.076 11.616 56.16 11.64 ;
    END
  END k_req_wdata[55]
  PIN k_req_wdata[56]
    DIRECTION OUTPUT ;
    USE SIGNAL ;
    PORT
      LAYER M4 ;
        RECT  56.076 11.712 56.16 11.736 ;
    END
  END k_req_wdata[56]
  PIN k_req_wdata[57]
    DIRECTION OUTPUT ;
    USE SIGNAL ;
    PORT
      LAYER M4 ;
        RECT  56.076 11.808 56.16 11.832 ;
    END
  END k_req_wdata[57]
  PIN k_req_wdata[58]
    DIRECTION OUTPUT ;
    USE SIGNAL ;
    PORT
      LAYER M4 ;
        RECT  56.076 11.904 56.16 11.928 ;
    END
  END k_req_wdata[58]
  PIN k_req_wdata[59]
    DIRECTION OUTPUT ;
    USE SIGNAL ;
    PORT
      LAYER M4 ;
        RECT  56.076 12.048 56.16 12.072 ;
    END
  END k_req_wdata[59]
  PIN k_req_wdata[5]
    DIRECTION OUTPUT ;
    USE SIGNAL ;
    PORT
      LAYER M4 ;
        RECT  56.076 6.432 56.16 6.456 ;
    END
  END k_req_wdata[5]
  PIN k_req_wdata[60]
    DIRECTION OUTPUT ;
    USE SIGNAL ;
    PORT
      LAYER M4 ;
        RECT  56.076 12.144 56.16 12.168 ;
    END
  END k_req_wdata[60]
  PIN k_req_wdata[61]
    DIRECTION OUTPUT ;
    USE SIGNAL ;
    PORT
      LAYER M4 ;
        RECT  56.076 12.24 56.16 12.264 ;
    END
  END k_req_wdata[61]
  PIN k_req_wdata[62]
    DIRECTION OUTPUT ;
    USE SIGNAL ;
    PORT
      LAYER M4 ;
        RECT  56.076 12.336 56.16 12.36 ;
    END
  END k_req_wdata[62]
  PIN k_req_wdata[63]
    DIRECTION OUTPUT ;
    USE SIGNAL ;
    PORT
      LAYER M4 ;
        RECT  56.076 12.432 56.16 12.456 ;
    END
  END k_req_wdata[63]
  PIN k_req_wdata[64]
    DIRECTION OUTPUT ;
    USE SIGNAL ;
    PORT
      LAYER M4 ;
        RECT  56.076 12.528 56.16 12.552 ;
    END
  END k_req_wdata[64]
  PIN k_req_wdata[65]
    DIRECTION OUTPUT ;
    USE SIGNAL ;
    PORT
      LAYER M4 ;
        RECT  56.076 12.672 56.16 12.696 ;
    END
  END k_req_wdata[65]
  PIN k_req_wdata[66]
    DIRECTION OUTPUT ;
    USE SIGNAL ;
    PORT
      LAYER M4 ;
        RECT  56.076 12.768 56.16 12.792 ;
    END
  END k_req_wdata[66]
  PIN k_req_wdata[67]
    DIRECTION OUTPUT ;
    USE SIGNAL ;
    PORT
      LAYER M4 ;
        RECT  56.076 12.864 56.16 12.888 ;
    END
  END k_req_wdata[67]
  PIN k_req_wdata[68]
    DIRECTION OUTPUT ;
    USE SIGNAL ;
    PORT
      LAYER M4 ;
        RECT  56.076 12.96 56.16 12.984 ;
    END
  END k_req_wdata[68]
  PIN k_req_wdata[69]
    DIRECTION OUTPUT ;
    USE SIGNAL ;
    PORT
      LAYER M4 ;
        RECT  56.076 13.056 56.16 13.08 ;
    END
  END k_req_wdata[69]
  PIN k_req_wdata[6]
    DIRECTION OUTPUT ;
    USE SIGNAL ;
    PORT
      LAYER M4 ;
        RECT  56.076 6.528 56.16 6.552 ;
    END
  END k_req_wdata[6]
  PIN k_req_wdata[70]
    DIRECTION OUTPUT ;
    USE SIGNAL ;
    PORT
      LAYER M4 ;
        RECT  56.076 13.152 56.16 13.176 ;
    END
  END k_req_wdata[70]
  PIN k_req_wdata[71]
    DIRECTION OUTPUT ;
    USE SIGNAL ;
    PORT
      LAYER M4 ;
        RECT  56.076 13.248 56.16 13.272 ;
    END
  END k_req_wdata[71]
  PIN k_req_wdata[72]
    DIRECTION OUTPUT ;
    USE SIGNAL ;
    PORT
      LAYER M4 ;
        RECT  56.076 13.392 56.16 13.416 ;
    END
  END k_req_wdata[72]
  PIN k_req_wdata[73]
    DIRECTION OUTPUT ;
    USE SIGNAL ;
    PORT
      LAYER M4 ;
        RECT  56.076 13.488 56.16 13.512 ;
    END
  END k_req_wdata[73]
  PIN k_req_wdata[74]
    DIRECTION OUTPUT ;
    USE SIGNAL ;
    PORT
      LAYER M4 ;
        RECT  56.076 13.584 56.16 13.608 ;
    END
  END k_req_wdata[74]
  PIN k_req_wdata[75]
    DIRECTION OUTPUT ;
    USE SIGNAL ;
    PORT
      LAYER M4 ;
        RECT  56.076 13.68 56.16 13.704 ;
    END
  END k_req_wdata[75]
  PIN k_req_wdata[76]
    DIRECTION OUTPUT ;
    USE SIGNAL ;
    PORT
      LAYER M4 ;
        RECT  56.076 13.776 56.16 13.8 ;
    END
  END k_req_wdata[76]
  PIN k_req_wdata[77]
    DIRECTION OUTPUT ;
    USE SIGNAL ;
    PORT
      LAYER M4 ;
        RECT  56.076 13.872 56.16 13.896 ;
    END
  END k_req_wdata[77]
  PIN k_req_wdata[78]
    DIRECTION OUTPUT ;
    USE SIGNAL ;
    PORT
      LAYER M4 ;
        RECT  56.076 14.016 56.16 14.04 ;
    END
  END k_req_wdata[78]
  PIN k_req_wdata[79]
    DIRECTION OUTPUT ;
    USE SIGNAL ;
    PORT
      LAYER M4 ;
        RECT  56.076 14.112 56.16 14.136 ;
    END
  END k_req_wdata[79]
  PIN k_req_wdata[7]
    DIRECTION OUTPUT ;
    USE SIGNAL ;
    PORT
      LAYER M4 ;
        RECT  56.076 6.672 56.16 6.696 ;
    END
  END k_req_wdata[7]
  PIN k_req_wdata[80]
    DIRECTION OUTPUT ;
    USE SIGNAL ;
    PORT
      LAYER M4 ;
        RECT  56.076 14.208 56.16 14.232 ;
    END
  END k_req_wdata[80]
  PIN k_req_wdata[81]
    DIRECTION OUTPUT ;
    USE SIGNAL ;
    PORT
      LAYER M4 ;
        RECT  56.076 14.304 56.16 14.328 ;
    END
  END k_req_wdata[81]
  PIN k_req_wdata[82]
    DIRECTION OUTPUT ;
    USE SIGNAL ;
    PORT
      LAYER M4 ;
        RECT  56.076 14.4 56.16 14.424 ;
    END
  END k_req_wdata[82]
  PIN k_req_wdata[83]
    DIRECTION OUTPUT ;
    USE SIGNAL ;
    PORT
      LAYER M4 ;
        RECT  56.076 14.496 56.16 14.52 ;
    END
  END k_req_wdata[83]
  PIN k_req_wdata[84]
    DIRECTION OUTPUT ;
    USE SIGNAL ;
    PORT
      LAYER M4 ;
        RECT  56.076 14.592 56.16 14.616 ;
    END
  END k_req_wdata[84]
  PIN k_req_wdata[85]
    DIRECTION OUTPUT ;
    USE SIGNAL ;
    PORT
      LAYER M4 ;
        RECT  56.076 14.736 56.16 14.76 ;
    END
  END k_req_wdata[85]
  PIN k_req_wdata[86]
    DIRECTION OUTPUT ;
    USE SIGNAL ;
    PORT
      LAYER M4 ;
        RECT  56.076 14.832 56.16 14.856 ;
    END
  END k_req_wdata[86]
  PIN k_req_wdata[87]
    DIRECTION OUTPUT ;
    USE SIGNAL ;
    PORT
      LAYER M4 ;
        RECT  56.076 14.928 56.16 14.952 ;
    END
  END k_req_wdata[87]
  PIN k_req_wdata[88]
    DIRECTION OUTPUT ;
    USE SIGNAL ;
    PORT
      LAYER M4 ;
        RECT  56.076 15.024 56.16 15.048 ;
    END
  END k_req_wdata[88]
  PIN k_req_wdata[89]
    DIRECTION OUTPUT ;
    USE SIGNAL ;
    PORT
      LAYER M4 ;
        RECT  56.076 15.12 56.16 15.144 ;
    END
  END k_req_wdata[89]
  PIN k_req_wdata[8]
    DIRECTION OUTPUT ;
    USE SIGNAL ;
    PORT
      LAYER M4 ;
        RECT  56.076 6.768 56.16 6.792 ;
    END
  END k_req_wdata[8]
  PIN k_req_wdata[90]
    DIRECTION OUTPUT ;
    USE SIGNAL ;
    PORT
      LAYER M4 ;
        RECT  56.076 15.216 56.16 15.24 ;
    END
  END k_req_wdata[90]
  PIN k_req_wdata[91]
    DIRECTION OUTPUT ;
    USE SIGNAL ;
    PORT
      LAYER M4 ;
        RECT  56.076 15.312 56.16 15.336 ;
    END
  END k_req_wdata[91]
  PIN k_req_wdata[92]
    DIRECTION OUTPUT ;
    USE SIGNAL ;
    PORT
      LAYER M4 ;
        RECT  56.076 15.456 56.16 15.48 ;
    END
  END k_req_wdata[92]
  PIN k_req_wdata[93]
    DIRECTION OUTPUT ;
    USE SIGNAL ;
    PORT
      LAYER M4 ;
        RECT  56.076 15.552 56.16 15.576 ;
    END
  END k_req_wdata[93]
  PIN k_req_wdata[94]
    DIRECTION OUTPUT ;
    USE SIGNAL ;
    PORT
      LAYER M4 ;
        RECT  56.076 15.648 56.16 15.672 ;
    END
  END k_req_wdata[94]
  PIN k_req_wdata[95]
    DIRECTION OUTPUT ;
    USE SIGNAL ;
    PORT
      LAYER M4 ;
        RECT  56.076 15.744 56.16 15.768 ;
    END
  END k_req_wdata[95]
  PIN k_req_wdata[96]
    DIRECTION OUTPUT ;
    USE SIGNAL ;
    PORT
      LAYER M4 ;
        RECT  56.076 15.84 56.16 15.864 ;
    END
  END k_req_wdata[96]
  PIN k_req_wdata[97]
    DIRECTION OUTPUT ;
    USE SIGNAL ;
    PORT
      LAYER M4 ;
        RECT  56.076 15.936 56.16 15.96 ;
    END
  END k_req_wdata[97]
  PIN k_req_wdata[98]
    DIRECTION OUTPUT ;
    USE SIGNAL ;
    PORT
      LAYER M4 ;
        RECT  56.076 16.08 56.16 16.104 ;
    END
  END k_req_wdata[98]
  PIN k_req_wdata[99]
    DIRECTION OUTPUT ;
    USE SIGNAL ;
    PORT
      LAYER M4 ;
        RECT  56.076 16.176 56.16 16.2 ;
    END
  END k_req_wdata[99]
  PIN k_req_wdata[9]
    DIRECTION OUTPUT ;
    USE SIGNAL ;
    PORT
      LAYER M4 ;
        RECT  56.076 6.864 56.16 6.888 ;
    END
  END k_req_wdata[9]
  PIN k_req_we
    DIRECTION OUTPUT ;
    USE SIGNAL ;
    PORT
      LAYER M4 ;
        RECT  56.076 32.4 56.16 32.424 ;
    END
  END k_req_we
  PIN k_req_wstrb[0]
    DIRECTION OUTPUT ;
    USE SIGNAL ;
    PORT
      LAYER M4 ;
        RECT  56.076 32.496 56.16 32.52 ;
    END
  END k_req_wstrb[0]
  PIN k_req_wstrb[10]
    DIRECTION OUTPUT ;
    USE SIGNAL ;
    PORT
      LAYER M4 ;
        RECT  56.076 33.504 56.16 33.528 ;
    END
  END k_req_wstrb[10]
  PIN k_req_wstrb[11]
    DIRECTION OUTPUT ;
    USE SIGNAL ;
    PORT
      LAYER M4 ;
        RECT  56.076 33.648 56.16 33.672 ;
    END
  END k_req_wstrb[11]
  PIN k_req_wstrb[12]
    DIRECTION OUTPUT ;
    USE SIGNAL ;
    PORT
      LAYER M4 ;
        RECT  56.076 33.744 56.16 33.768 ;
    END
  END k_req_wstrb[12]
  PIN k_req_wstrb[13]
    DIRECTION OUTPUT ;
    USE SIGNAL ;
    PORT
      LAYER M4 ;
        RECT  56.076 33.84 56.16 33.864 ;
    END
  END k_req_wstrb[13]
  PIN k_req_wstrb[14]
    DIRECTION OUTPUT ;
    USE SIGNAL ;
    PORT
      LAYER M4 ;
        RECT  56.076 33.936 56.16 33.96 ;
    END
  END k_req_wstrb[14]
  PIN k_req_wstrb[15]
    DIRECTION OUTPUT ;
    USE SIGNAL ;
    PORT
      LAYER M4 ;
        RECT  56.076 34.032 56.16 34.056 ;
    END
  END k_req_wstrb[15]
  PIN k_req_wstrb[16]
    DIRECTION OUTPUT ;
    USE SIGNAL ;
    PORT
      LAYER M4 ;
        RECT  56.076 34.128 56.16 34.152 ;
    END
  END k_req_wstrb[16]
  PIN k_req_wstrb[17]
    DIRECTION OUTPUT ;
    USE SIGNAL ;
    PORT
      LAYER M4 ;
        RECT  56.076 34.272 56.16 34.296 ;
    END
  END k_req_wstrb[17]
  PIN k_req_wstrb[18]
    DIRECTION OUTPUT ;
    USE SIGNAL ;
    PORT
      LAYER M4 ;
        RECT  56.076 34.368 56.16 34.392 ;
    END
  END k_req_wstrb[18]
  PIN k_req_wstrb[19]
    DIRECTION OUTPUT ;
    USE SIGNAL ;
    PORT
      LAYER M4 ;
        RECT  56.076 34.464 56.16 34.488 ;
    END
  END k_req_wstrb[19]
  PIN k_req_wstrb[1]
    DIRECTION OUTPUT ;
    USE SIGNAL ;
    PORT
      LAYER M4 ;
        RECT  56.076 32.592 56.16 32.616 ;
    END
  END k_req_wstrb[1]
  PIN k_req_wstrb[20]
    DIRECTION OUTPUT ;
    USE SIGNAL ;
    PORT
      LAYER M4 ;
        RECT  56.076 34.56 56.16 34.584 ;
    END
  END k_req_wstrb[20]
  PIN k_req_wstrb[21]
    DIRECTION OUTPUT ;
    USE SIGNAL ;
    PORT
      LAYER M4 ;
        RECT  56.076 34.656 56.16 34.68 ;
    END
  END k_req_wstrb[21]
  PIN k_req_wstrb[22]
    DIRECTION OUTPUT ;
    USE SIGNAL ;
    PORT
      LAYER M4 ;
        RECT  56.076 34.752 56.16 34.776 ;
    END
  END k_req_wstrb[22]
  PIN k_req_wstrb[23]
    DIRECTION OUTPUT ;
    USE SIGNAL ;
    PORT
      LAYER M4 ;
        RECT  56.076 34.848 56.16 34.872 ;
    END
  END k_req_wstrb[23]
  PIN k_req_wstrb[24]
    DIRECTION OUTPUT ;
    USE SIGNAL ;
    PORT
      LAYER M4 ;
        RECT  56.076 34.992 56.16 35.016 ;
    END
  END k_req_wstrb[24]
  PIN k_req_wstrb[25]
    DIRECTION OUTPUT ;
    USE SIGNAL ;
    PORT
      LAYER M4 ;
        RECT  56.076 35.088 56.16 35.112 ;
    END
  END k_req_wstrb[25]
  PIN k_req_wstrb[26]
    DIRECTION OUTPUT ;
    USE SIGNAL ;
    PORT
      LAYER M4 ;
        RECT  56.076 35.184 56.16 35.208 ;
    END
  END k_req_wstrb[26]
  PIN k_req_wstrb[27]
    DIRECTION OUTPUT ;
    USE SIGNAL ;
    PORT
      LAYER M4 ;
        RECT  56.076 35.28 56.16 35.304 ;
    END
  END k_req_wstrb[27]
  PIN k_req_wstrb[28]
    DIRECTION OUTPUT ;
    USE SIGNAL ;
    PORT
      LAYER M4 ;
        RECT  56.076 35.376 56.16 35.4 ;
    END
  END k_req_wstrb[28]
  PIN k_req_wstrb[29]
    DIRECTION OUTPUT ;
    USE SIGNAL ;
    PORT
      LAYER M4 ;
        RECT  56.076 35.472 56.16 35.496 ;
    END
  END k_req_wstrb[29]
  PIN k_req_wstrb[2]
    DIRECTION OUTPUT ;
    USE SIGNAL ;
    PORT
      LAYER M4 ;
        RECT  56.076 32.688 56.16 32.712 ;
    END
  END k_req_wstrb[2]
  PIN k_req_wstrb[30]
    DIRECTION OUTPUT ;
    USE SIGNAL ;
    PORT
      LAYER M4 ;
        RECT  56.076 35.616 56.16 35.64 ;
    END
  END k_req_wstrb[30]
  PIN k_req_wstrb[31]
    DIRECTION OUTPUT ;
    USE SIGNAL ;
    PORT
      LAYER M4 ;
        RECT  56.076 35.712 56.16 35.736 ;
    END
  END k_req_wstrb[31]
  PIN k_req_wstrb[3]
    DIRECTION OUTPUT ;
    USE SIGNAL ;
    PORT
      LAYER M4 ;
        RECT  56.076 32.784 56.16 32.808 ;
    END
  END k_req_wstrb[3]
  PIN k_req_wstrb[4]
    DIRECTION OUTPUT ;
    USE SIGNAL ;
    PORT
      LAYER M4 ;
        RECT  56.076 32.928 56.16 32.952 ;
    END
  END k_req_wstrb[4]
  PIN k_req_wstrb[5]
    DIRECTION OUTPUT ;
    USE SIGNAL ;
    PORT
      LAYER M4 ;
        RECT  56.076 33.024 56.16 33.048 ;
    END
  END k_req_wstrb[5]
  PIN k_req_wstrb[6]
    DIRECTION OUTPUT ;
    USE SIGNAL ;
    PORT
      LAYER M4 ;
        RECT  56.076 33.12 56.16 33.144 ;
    END
  END k_req_wstrb[6]
  PIN k_req_wstrb[7]
    DIRECTION OUTPUT ;
    USE SIGNAL ;
    PORT
      LAYER M4 ;
        RECT  56.076 33.216 56.16 33.24 ;
    END
  END k_req_wstrb[7]
  PIN k_req_wstrb[8]
    DIRECTION OUTPUT ;
    USE SIGNAL ;
    PORT
      LAYER M4 ;
        RECT  56.076 33.312 56.16 33.336 ;
    END
  END k_req_wstrb[8]
  PIN k_req_wstrb[9]
    DIRECTION OUTPUT ;
    USE SIGNAL ;
    PORT
      LAYER M4 ;
        RECT  56.076 33.408 56.16 33.432 ;
    END
  END k_req_wstrb[9]
  PIN k_rsp_data[0]
    DIRECTION INPUT ;
    USE SIGNAL ;
    PORT
      LAYER M4 ;
        RECT  56.076 35.808 56.16 35.832 ;
    END
  END k_rsp_data[0]
  PIN k_rsp_data[100]
    DIRECTION INPUT ;
    USE SIGNAL ;
    PORT
      LAYER M4 ;
        RECT  56.076 46.128 56.16 46.152 ;
    END
  END k_rsp_data[100]
  PIN k_rsp_data[101]
    DIRECTION INPUT ;
    USE SIGNAL ;
    PORT
      LAYER M4 ;
        RECT  56.076 46.224 56.16 46.248 ;
    END
  END k_rsp_data[101]
  PIN k_rsp_data[102]
    DIRECTION INPUT ;
    USE SIGNAL ;
    PORT
      LAYER M4 ;
        RECT  56.076 46.32 56.16 46.344 ;
    END
  END k_rsp_data[102]
  PIN k_rsp_data[103]
    DIRECTION INPUT ;
    USE SIGNAL ;
    PORT
      LAYER M4 ;
        RECT  56.076 46.464 56.16 46.488 ;
    END
  END k_rsp_data[103]
  PIN k_rsp_data[104]
    DIRECTION INPUT ;
    USE SIGNAL ;
    PORT
      LAYER M4 ;
        RECT  56.076 46.56 56.16 46.584 ;
    END
  END k_rsp_data[104]
  PIN k_rsp_data[105]
    DIRECTION INPUT ;
    USE SIGNAL ;
    PORT
      LAYER M4 ;
        RECT  56.076 46.656 56.16 46.68 ;
    END
  END k_rsp_data[105]
  PIN k_rsp_data[106]
    DIRECTION INPUT ;
    USE SIGNAL ;
    PORT
      LAYER M4 ;
        RECT  56.076 46.752 56.16 46.776 ;
    END
  END k_rsp_data[106]
  PIN k_rsp_data[107]
    DIRECTION INPUT ;
    USE SIGNAL ;
    PORT
      LAYER M4 ;
        RECT  56.076 46.848 56.16 46.872 ;
    END
  END k_rsp_data[107]
  PIN k_rsp_data[108]
    DIRECTION INPUT ;
    USE SIGNAL ;
    PORT
      LAYER M4 ;
        RECT  56.076 46.944 56.16 46.968 ;
    END
  END k_rsp_data[108]
  PIN k_rsp_data[109]
    DIRECTION INPUT ;
    USE SIGNAL ;
    PORT
      LAYER M4 ;
        RECT  56.076 47.088 56.16 47.112 ;
    END
  END k_rsp_data[109]
  PIN k_rsp_data[10]
    DIRECTION INPUT ;
    USE SIGNAL ;
    PORT
      LAYER M4 ;
        RECT  56.076 36.816 56.16 36.84 ;
    END
  END k_rsp_data[10]
  PIN k_rsp_data[110]
    DIRECTION INPUT ;
    USE SIGNAL ;
    PORT
      LAYER M4 ;
        RECT  56.076 47.184 56.16 47.208 ;
    END
  END k_rsp_data[110]
  PIN k_rsp_data[111]
    DIRECTION INPUT ;
    USE SIGNAL ;
    PORT
      LAYER M4 ;
        RECT  56.076 47.28 56.16 47.304 ;
    END
  END k_rsp_data[111]
  PIN k_rsp_data[112]
    DIRECTION INPUT ;
    USE SIGNAL ;
    PORT
      LAYER M4 ;
        RECT  56.076 47.376 56.16 47.4 ;
    END
  END k_rsp_data[112]
  PIN k_rsp_data[113]
    DIRECTION INPUT ;
    USE SIGNAL ;
    PORT
      LAYER M4 ;
        RECT  56.076 47.472 56.16 47.496 ;
    END
  END k_rsp_data[113]
  PIN k_rsp_data[114]
    DIRECTION INPUT ;
    USE SIGNAL ;
    PORT
      LAYER M4 ;
        RECT  56.076 47.568 56.16 47.592 ;
    END
  END k_rsp_data[114]
  PIN k_rsp_data[115]
    DIRECTION INPUT ;
    USE SIGNAL ;
    PORT
      LAYER M4 ;
        RECT  56.076 47.664 56.16 47.688 ;
    END
  END k_rsp_data[115]
  PIN k_rsp_data[116]
    DIRECTION INPUT ;
    USE SIGNAL ;
    PORT
      LAYER M4 ;
        RECT  56.076 47.808 56.16 47.832 ;
    END
  END k_rsp_data[116]
  PIN k_rsp_data[117]
    DIRECTION INPUT ;
    USE SIGNAL ;
    PORT
      LAYER M4 ;
        RECT  56.076 47.904 56.16 47.928 ;
    END
  END k_rsp_data[117]
  PIN k_rsp_data[118]
    DIRECTION INPUT ;
    USE SIGNAL ;
    PORT
      LAYER M4 ;
        RECT  56.076 48 56.16 48.024 ;
    END
  END k_rsp_data[118]
  PIN k_rsp_data[119]
    DIRECTION INPUT ;
    USE SIGNAL ;
    PORT
      LAYER M4 ;
        RECT  56.076 48.096 56.16 48.12 ;
    END
  END k_rsp_data[119]
  PIN k_rsp_data[11]
    DIRECTION INPUT ;
    USE SIGNAL ;
    PORT
      LAYER M4 ;
        RECT  56.076 36.912 56.16 36.936 ;
    END
  END k_rsp_data[11]
  PIN k_rsp_data[120]
    DIRECTION INPUT ;
    USE SIGNAL ;
    PORT
      LAYER M4 ;
        RECT  56.076 48.192 56.16 48.216 ;
    END
  END k_rsp_data[120]
  PIN k_rsp_data[121]
    DIRECTION INPUT ;
    USE SIGNAL ;
    PORT
      LAYER M4 ;
        RECT  56.076 48.288 56.16 48.312 ;
    END
  END k_rsp_data[121]
  PIN k_rsp_data[122]
    DIRECTION INPUT ;
    USE SIGNAL ;
    PORT
      LAYER M4 ;
        RECT  56.076 48.384 56.16 48.408 ;
    END
  END k_rsp_data[122]
  PIN k_rsp_data[123]
    DIRECTION INPUT ;
    USE SIGNAL ;
    PORT
      LAYER M4 ;
        RECT  56.076 48.528 56.16 48.552 ;
    END
  END k_rsp_data[123]
  PIN k_rsp_data[124]
    DIRECTION INPUT ;
    USE SIGNAL ;
    PORT
      LAYER M4 ;
        RECT  56.076 48.624 56.16 48.648 ;
    END
  END k_rsp_data[124]
  PIN k_rsp_data[125]
    DIRECTION INPUT ;
    USE SIGNAL ;
    PORT
      LAYER M4 ;
        RECT  56.076 48.72 56.16 48.744 ;
    END
  END k_rsp_data[125]
  PIN k_rsp_data[126]
    DIRECTION INPUT ;
    USE SIGNAL ;
    PORT
      LAYER M4 ;
        RECT  56.076 48.816 56.16 48.84 ;
    END
  END k_rsp_data[126]
  PIN k_rsp_data[127]
    DIRECTION INPUT ;
    USE SIGNAL ;
    PORT
      LAYER M4 ;
        RECT  56.076 48.912 56.16 48.936 ;
    END
  END k_rsp_data[127]
  PIN k_rsp_data[128]
    DIRECTION INPUT ;
    USE SIGNAL ;
    PORT
      LAYER M4 ;
        RECT  56.076 49.008 56.16 49.032 ;
    END
  END k_rsp_data[128]
  PIN k_rsp_data[129]
    DIRECTION INPUT ;
    USE SIGNAL ;
    PORT
      LAYER M4 ;
        RECT  56.076 49.152 56.16 49.176 ;
    END
  END k_rsp_data[129]
  PIN k_rsp_data[12]
    DIRECTION INPUT ;
    USE SIGNAL ;
    PORT
      LAYER M4 ;
        RECT  56.076 37.056 56.16 37.08 ;
    END
  END k_rsp_data[12]
  PIN k_rsp_data[130]
    DIRECTION INPUT ;
    USE SIGNAL ;
    PORT
      LAYER M4 ;
        RECT  56.076 49.248 56.16 49.272 ;
    END
  END k_rsp_data[130]
  PIN k_rsp_data[131]
    DIRECTION INPUT ;
    USE SIGNAL ;
    PORT
      LAYER M4 ;
        RECT  56.076 49.344 56.16 49.368 ;
    END
  END k_rsp_data[131]
  PIN k_rsp_data[132]
    DIRECTION INPUT ;
    USE SIGNAL ;
    PORT
      LAYER M4 ;
        RECT  56.076 49.44 56.16 49.464 ;
    END
  END k_rsp_data[132]
  PIN k_rsp_data[133]
    DIRECTION INPUT ;
    USE SIGNAL ;
    PORT
      LAYER M4 ;
        RECT  56.076 49.536 56.16 49.56 ;
    END
  END k_rsp_data[133]
  PIN k_rsp_data[134]
    DIRECTION INPUT ;
    USE SIGNAL ;
    PORT
      LAYER M4 ;
        RECT  56.076 49.632 56.16 49.656 ;
    END
  END k_rsp_data[134]
  PIN k_rsp_data[135]
    DIRECTION INPUT ;
    USE SIGNAL ;
    PORT
      LAYER M4 ;
        RECT  56.076 49.728 56.16 49.752 ;
    END
  END k_rsp_data[135]
  PIN k_rsp_data[136]
    DIRECTION INPUT ;
    USE SIGNAL ;
    PORT
      LAYER M4 ;
        RECT  56.076 49.872 56.16 49.896 ;
    END
  END k_rsp_data[136]
  PIN k_rsp_data[137]
    DIRECTION INPUT ;
    USE SIGNAL ;
    PORT
      LAYER M4 ;
        RECT  56.076 49.968 56.16 49.992 ;
    END
  END k_rsp_data[137]
  PIN k_rsp_data[138]
    DIRECTION INPUT ;
    USE SIGNAL ;
    PORT
      LAYER M4 ;
        RECT  56.076 50.064 56.16 50.088 ;
    END
  END k_rsp_data[138]
  PIN k_rsp_data[139]
    DIRECTION INPUT ;
    USE SIGNAL ;
    PORT
      LAYER M4 ;
        RECT  56.076 50.16 56.16 50.184 ;
    END
  END k_rsp_data[139]
  PIN k_rsp_data[13]
    DIRECTION INPUT ;
    USE SIGNAL ;
    PORT
      LAYER M4 ;
        RECT  56.076 37.152 56.16 37.176 ;
    END
  END k_rsp_data[13]
  PIN k_rsp_data[140]
    DIRECTION INPUT ;
    USE SIGNAL ;
    PORT
      LAYER M4 ;
        RECT  56.076 50.256 56.16 50.28 ;
    END
  END k_rsp_data[140]
  PIN k_rsp_data[141]
    DIRECTION INPUT ;
    USE SIGNAL ;
    PORT
      LAYER M4 ;
        RECT  56.076 50.352 56.16 50.376 ;
    END
  END k_rsp_data[141]
  PIN k_rsp_data[142]
    DIRECTION INPUT ;
    USE SIGNAL ;
    PORT
      LAYER M4 ;
        RECT  56.076 50.496 56.16 50.52 ;
    END
  END k_rsp_data[142]
  PIN k_rsp_data[143]
    DIRECTION INPUT ;
    USE SIGNAL ;
    PORT
      LAYER M4 ;
        RECT  56.076 50.592 56.16 50.616 ;
    END
  END k_rsp_data[143]
  PIN k_rsp_data[144]
    DIRECTION INPUT ;
    USE SIGNAL ;
    PORT
      LAYER M4 ;
        RECT  56.076 50.688 56.16 50.712 ;
    END
  END k_rsp_data[144]
  PIN k_rsp_data[145]
    DIRECTION INPUT ;
    USE SIGNAL ;
    PORT
      LAYER M4 ;
        RECT  56.076 50.784 56.16 50.808 ;
    END
  END k_rsp_data[145]
  PIN k_rsp_data[146]
    DIRECTION INPUT ;
    USE SIGNAL ;
    PORT
      LAYER M4 ;
        RECT  56.076 50.88 56.16 50.904 ;
    END
  END k_rsp_data[146]
  PIN k_rsp_data[147]
    DIRECTION INPUT ;
    USE SIGNAL ;
    PORT
      LAYER M4 ;
        RECT  56.076 50.976 56.16 51 ;
    END
  END k_rsp_data[147]
  PIN k_rsp_data[148]
    DIRECTION INPUT ;
    USE SIGNAL ;
    PORT
      LAYER M4 ;
        RECT  56.076 51.072 56.16 51.096 ;
    END
  END k_rsp_data[148]
  PIN k_rsp_data[149]
    DIRECTION INPUT ;
    USE SIGNAL ;
    PORT
      LAYER M4 ;
        RECT  56.076 51.216 56.16 51.24 ;
    END
  END k_rsp_data[149]
  PIN k_rsp_data[14]
    DIRECTION INPUT ;
    USE SIGNAL ;
    PORT
      LAYER M4 ;
        RECT  56.076 37.248 56.16 37.272 ;
    END
  END k_rsp_data[14]
  PIN k_rsp_data[150]
    DIRECTION INPUT ;
    USE SIGNAL ;
    PORT
      LAYER M4 ;
        RECT  56.076 51.312 56.16 51.336 ;
    END
  END k_rsp_data[150]
  PIN k_rsp_data[151]
    DIRECTION INPUT ;
    USE SIGNAL ;
    PORT
      LAYER M4 ;
        RECT  56.076 51.408 56.16 51.432 ;
    END
  END k_rsp_data[151]
  PIN k_rsp_data[152]
    DIRECTION INPUT ;
    USE SIGNAL ;
    PORT
      LAYER M4 ;
        RECT  56.076 51.504 56.16 51.528 ;
    END
  END k_rsp_data[152]
  PIN k_rsp_data[153]
    DIRECTION INPUT ;
    USE SIGNAL ;
    PORT
      LAYER M4 ;
        RECT  56.076 51.6 56.16 51.624 ;
    END
  END k_rsp_data[153]
  PIN k_rsp_data[154]
    DIRECTION INPUT ;
    USE SIGNAL ;
    PORT
      LAYER M4 ;
        RECT  56.076 51.696 56.16 51.72 ;
    END
  END k_rsp_data[154]
  PIN k_rsp_data[155]
    DIRECTION INPUT ;
    USE SIGNAL ;
    PORT
      LAYER M4 ;
        RECT  56.076 51.84 56.16 51.864 ;
    END
  END k_rsp_data[155]
  PIN k_rsp_data[156]
    DIRECTION INPUT ;
    USE SIGNAL ;
    PORT
      LAYER M4 ;
        RECT  56.076 51.936 56.16 51.96 ;
    END
  END k_rsp_data[156]
  PIN k_rsp_data[157]
    DIRECTION INPUT ;
    USE SIGNAL ;
    PORT
      LAYER M4 ;
        RECT  56.076 52.032 56.16 52.056 ;
    END
  END k_rsp_data[157]
  PIN k_rsp_data[158]
    DIRECTION INPUT ;
    USE SIGNAL ;
    PORT
      LAYER M4 ;
        RECT  56.076 52.128 56.16 52.152 ;
    END
  END k_rsp_data[158]
  PIN k_rsp_data[159]
    DIRECTION INPUT ;
    USE SIGNAL ;
    PORT
      LAYER M4 ;
        RECT  56.076 52.224 56.16 52.248 ;
    END
  END k_rsp_data[159]
  PIN k_rsp_data[15]
    DIRECTION INPUT ;
    USE SIGNAL ;
    PORT
      LAYER M4 ;
        RECT  56.076 37.344 56.16 37.368 ;
    END
  END k_rsp_data[15]
  PIN k_rsp_data[160]
    DIRECTION INPUT ;
    USE SIGNAL ;
    PORT
      LAYER M4 ;
        RECT  56.076 52.32 56.16 52.344 ;
    END
  END k_rsp_data[160]
  PIN k_rsp_data[161]
    DIRECTION INPUT ;
    USE SIGNAL ;
    PORT
      LAYER M4 ;
        RECT  56.076 52.416 56.16 52.44 ;
    END
  END k_rsp_data[161]
  PIN k_rsp_data[162]
    DIRECTION INPUT ;
    USE SIGNAL ;
    PORT
      LAYER M4 ;
        RECT  56.076 52.56 56.16 52.584 ;
    END
  END k_rsp_data[162]
  PIN k_rsp_data[163]
    DIRECTION INPUT ;
    USE SIGNAL ;
    PORT
      LAYER M4 ;
        RECT  56.076 52.656 56.16 52.68 ;
    END
  END k_rsp_data[163]
  PIN k_rsp_data[164]
    DIRECTION INPUT ;
    USE SIGNAL ;
    PORT
      LAYER M4 ;
        RECT  56.076 52.752 56.16 52.776 ;
    END
  END k_rsp_data[164]
  PIN k_rsp_data[165]
    DIRECTION INPUT ;
    USE SIGNAL ;
    PORT
      LAYER M4 ;
        RECT  56.076 52.848 56.16 52.872 ;
    END
  END k_rsp_data[165]
  PIN k_rsp_data[166]
    DIRECTION INPUT ;
    USE SIGNAL ;
    PORT
      LAYER M4 ;
        RECT  56.076 52.944 56.16 52.968 ;
    END
  END k_rsp_data[166]
  PIN k_rsp_data[167]
    DIRECTION INPUT ;
    USE SIGNAL ;
    PORT
      LAYER M4 ;
        RECT  56.076 53.04 56.16 53.064 ;
    END
  END k_rsp_data[167]
  PIN k_rsp_data[168]
    DIRECTION INPUT ;
    USE SIGNAL ;
    PORT
      LAYER M4 ;
        RECT  56.076 53.184 56.16 53.208 ;
    END
  END k_rsp_data[168]
  PIN k_rsp_data[169]
    DIRECTION INPUT ;
    USE SIGNAL ;
    PORT
      LAYER M4 ;
        RECT  56.076 53.28 56.16 53.304 ;
    END
  END k_rsp_data[169]
  PIN k_rsp_data[16]
    DIRECTION INPUT ;
    USE SIGNAL ;
    PORT
      LAYER M4 ;
        RECT  56.076 37.44 56.16 37.464 ;
    END
  END k_rsp_data[16]
  PIN k_rsp_data[170]
    DIRECTION INPUT ;
    USE SIGNAL ;
    PORT
      LAYER M4 ;
        RECT  56.076 53.376 56.16 53.4 ;
    END
  END k_rsp_data[170]
  PIN k_rsp_data[171]
    DIRECTION INPUT ;
    USE SIGNAL ;
    PORT
      LAYER M4 ;
        RECT  56.076 53.472 56.16 53.496 ;
    END
  END k_rsp_data[171]
  PIN k_rsp_data[172]
    DIRECTION INPUT ;
    USE SIGNAL ;
    PORT
      LAYER M4 ;
        RECT  56.076 53.568 56.16 53.592 ;
    END
  END k_rsp_data[172]
  PIN k_rsp_data[173]
    DIRECTION INPUT ;
    USE SIGNAL ;
    PORT
      LAYER M4 ;
        RECT  56.076 53.664 56.16 53.688 ;
    END
  END k_rsp_data[173]
  PIN k_rsp_data[174]
    DIRECTION INPUT ;
    USE SIGNAL ;
    PORT
      LAYER M4 ;
        RECT  56.076 53.76 56.16 53.784 ;
    END
  END k_rsp_data[174]
  PIN k_rsp_data[175]
    DIRECTION INPUT ;
    USE SIGNAL ;
    PORT
      LAYER M4 ;
        RECT  56.076 53.904 56.16 53.928 ;
    END
  END k_rsp_data[175]
  PIN k_rsp_data[176]
    DIRECTION INPUT ;
    USE SIGNAL ;
    PORT
      LAYER M4 ;
        RECT  56.076 54 56.16 54.024 ;
    END
  END k_rsp_data[176]
  PIN k_rsp_data[177]
    DIRECTION INPUT ;
    USE SIGNAL ;
    PORT
      LAYER M4 ;
        RECT  56.076 54.096 56.16 54.12 ;
    END
  END k_rsp_data[177]
  PIN k_rsp_data[178]
    DIRECTION INPUT ;
    USE SIGNAL ;
    PORT
      LAYER M4 ;
        RECT  56.076 54.192 56.16 54.216 ;
    END
  END k_rsp_data[178]
  PIN k_rsp_data[179]
    DIRECTION INPUT ;
    USE SIGNAL ;
    PORT
      LAYER M4 ;
        RECT  56.076 54.288 56.16 54.312 ;
    END
  END k_rsp_data[179]
  PIN k_rsp_data[17]
    DIRECTION INPUT ;
    USE SIGNAL ;
    PORT
      LAYER M4 ;
        RECT  56.076 37.536 56.16 37.56 ;
    END
  END k_rsp_data[17]
  PIN k_rsp_data[180]
    DIRECTION INPUT ;
    USE SIGNAL ;
    PORT
      LAYER M4 ;
        RECT  56.076 54.384 56.16 54.408 ;
    END
  END k_rsp_data[180]
  PIN k_rsp_data[181]
    DIRECTION INPUT ;
    USE SIGNAL ;
    PORT
      LAYER M4 ;
        RECT  56.076 54.528 56.16 54.552 ;
    END
  END k_rsp_data[181]
  PIN k_rsp_data[182]
    DIRECTION INPUT ;
    USE SIGNAL ;
    PORT
      LAYER M4 ;
        RECT  56.076 54.624 56.16 54.648 ;
    END
  END k_rsp_data[182]
  PIN k_rsp_data[183]
    DIRECTION INPUT ;
    USE SIGNAL ;
    PORT
      LAYER M4 ;
        RECT  56.076 54.72 56.16 54.744 ;
    END
  END k_rsp_data[183]
  PIN k_rsp_data[184]
    DIRECTION INPUT ;
    USE SIGNAL ;
    PORT
      LAYER M4 ;
        RECT  56.076 54.816 56.16 54.84 ;
    END
  END k_rsp_data[184]
  PIN k_rsp_data[185]
    DIRECTION INPUT ;
    USE SIGNAL ;
    PORT
      LAYER M4 ;
        RECT  56.076 54.912 56.16 54.936 ;
    END
  END k_rsp_data[185]
  PIN k_rsp_data[186]
    DIRECTION INPUT ;
    USE SIGNAL ;
    PORT
      LAYER M4 ;
        RECT  56.076 55.008 56.16 55.032 ;
    END
  END k_rsp_data[186]
  PIN k_rsp_data[187]
    DIRECTION INPUT ;
    USE SIGNAL ;
    PORT
      LAYER M4 ;
        RECT  56.076 55.104 56.16 55.128 ;
    END
  END k_rsp_data[187]
  PIN k_rsp_data[188]
    DIRECTION INPUT ;
    USE SIGNAL ;
    PORT
      LAYER M4 ;
        RECT  56.076 55.248 56.16 55.272 ;
    END
  END k_rsp_data[188]
  PIN k_rsp_data[189]
    DIRECTION INPUT ;
    USE SIGNAL ;
    PORT
      LAYER M4 ;
        RECT  56.076 55.344 56.16 55.368 ;
    END
  END k_rsp_data[189]
  PIN k_rsp_data[18]
    DIRECTION INPUT ;
    USE SIGNAL ;
    PORT
      LAYER M4 ;
        RECT  56.076 37.68 56.16 37.704 ;
    END
  END k_rsp_data[18]
  PIN k_rsp_data[190]
    DIRECTION INPUT ;
    USE SIGNAL ;
    PORT
      LAYER M4 ;
        RECT  56.076 55.44 56.16 55.464 ;
    END
  END k_rsp_data[190]
  PIN k_rsp_data[191]
    DIRECTION INPUT ;
    USE SIGNAL ;
    PORT
      LAYER M4 ;
        RECT  56.076 55.536 56.16 55.56 ;
    END
  END k_rsp_data[191]
  PIN k_rsp_data[192]
    DIRECTION INPUT ;
    USE SIGNAL ;
    PORT
      LAYER M4 ;
        RECT  56.076 55.632 56.16 55.656 ;
    END
  END k_rsp_data[192]
  PIN k_rsp_data[193]
    DIRECTION INPUT ;
    USE SIGNAL ;
    PORT
      LAYER M4 ;
        RECT  56.076 55.728 56.16 55.752 ;
    END
  END k_rsp_data[193]
  PIN k_rsp_data[194]
    DIRECTION INPUT ;
    USE SIGNAL ;
    PORT
      LAYER M4 ;
        RECT  56.076 55.872 56.16 55.896 ;
    END
  END k_rsp_data[194]
  PIN k_rsp_data[195]
    DIRECTION INPUT ;
    USE SIGNAL ;
    PORT
      LAYER M4 ;
        RECT  56.076 55.968 56.16 55.992 ;
    END
  END k_rsp_data[195]
  PIN k_rsp_data[196]
    DIRECTION INPUT ;
    USE SIGNAL ;
    PORT
      LAYER M4 ;
        RECT  56.076 56.064 56.16 56.088 ;
    END
  END k_rsp_data[196]
  PIN k_rsp_data[197]
    DIRECTION INPUT ;
    USE SIGNAL ;
    PORT
      LAYER M4 ;
        RECT  56.076 56.16 56.16 56.184 ;
    END
  END k_rsp_data[197]
  PIN k_rsp_data[198]
    DIRECTION INPUT ;
    USE SIGNAL ;
    PORT
      LAYER M4 ;
        RECT  56.076 56.256 56.16 56.28 ;
    END
  END k_rsp_data[198]
  PIN k_rsp_data[199]
    DIRECTION INPUT ;
    USE SIGNAL ;
    PORT
      LAYER M4 ;
        RECT  56.076 56.352 56.16 56.376 ;
    END
  END k_rsp_data[199]
  PIN k_rsp_data[19]
    DIRECTION INPUT ;
    USE SIGNAL ;
    PORT
      LAYER M4 ;
        RECT  56.076 37.776 56.16 37.8 ;
    END
  END k_rsp_data[19]
  PIN k_rsp_data[1]
    DIRECTION INPUT ;
    USE SIGNAL ;
    PORT
      LAYER M4 ;
        RECT  56.076 35.904 56.16 35.928 ;
    END
  END k_rsp_data[1]
  PIN k_rsp_data[200]
    DIRECTION INPUT ;
    USE SIGNAL ;
    PORT
      LAYER M4 ;
        RECT  56.076 56.448 56.16 56.472 ;
    END
  END k_rsp_data[200]
  PIN k_rsp_data[201]
    DIRECTION INPUT ;
    USE SIGNAL ;
    PORT
      LAYER M4 ;
        RECT  56.076 56.592 56.16 56.616 ;
    END
  END k_rsp_data[201]
  PIN k_rsp_data[202]
    DIRECTION INPUT ;
    USE SIGNAL ;
    PORT
      LAYER M4 ;
        RECT  56.076 56.688 56.16 56.712 ;
    END
  END k_rsp_data[202]
  PIN k_rsp_data[203]
    DIRECTION INPUT ;
    USE SIGNAL ;
    PORT
      LAYER M4 ;
        RECT  56.076 56.784 56.16 56.808 ;
    END
  END k_rsp_data[203]
  PIN k_rsp_data[204]
    DIRECTION INPUT ;
    USE SIGNAL ;
    PORT
      LAYER M4 ;
        RECT  56.076 56.88 56.16 56.904 ;
    END
  END k_rsp_data[204]
  PIN k_rsp_data[205]
    DIRECTION INPUT ;
    USE SIGNAL ;
    PORT
      LAYER M4 ;
        RECT  56.076 56.976 56.16 57 ;
    END
  END k_rsp_data[205]
  PIN k_rsp_data[206]
    DIRECTION INPUT ;
    USE SIGNAL ;
    PORT
      LAYER M4 ;
        RECT  56.076 57.072 56.16 57.096 ;
    END
  END k_rsp_data[206]
  PIN k_rsp_data[207]
    DIRECTION INPUT ;
    USE SIGNAL ;
    PORT
      LAYER M4 ;
        RECT  56.076 57.216 56.16 57.24 ;
    END
  END k_rsp_data[207]
  PIN k_rsp_data[208]
    DIRECTION INPUT ;
    USE SIGNAL ;
    PORT
      LAYER M4 ;
        RECT  56.076 57.312 56.16 57.336 ;
    END
  END k_rsp_data[208]
  PIN k_rsp_data[209]
    DIRECTION INPUT ;
    USE SIGNAL ;
    PORT
      LAYER M4 ;
        RECT  56.076 57.408 56.16 57.432 ;
    END
  END k_rsp_data[209]
  PIN k_rsp_data[20]
    DIRECTION INPUT ;
    USE SIGNAL ;
    PORT
      LAYER M4 ;
        RECT  56.076 37.872 56.16 37.896 ;
    END
  END k_rsp_data[20]
  PIN k_rsp_data[210]
    DIRECTION INPUT ;
    USE SIGNAL ;
    PORT
      LAYER M4 ;
        RECT  56.076 57.504 56.16 57.528 ;
    END
  END k_rsp_data[210]
  PIN k_rsp_data[211]
    DIRECTION INPUT ;
    USE SIGNAL ;
    PORT
      LAYER M4 ;
        RECT  56.076 57.6 56.16 57.624 ;
    END
  END k_rsp_data[211]
  PIN k_rsp_data[212]
    DIRECTION INPUT ;
    USE SIGNAL ;
    PORT
      LAYER M4 ;
        RECT  56.076 57.696 56.16 57.72 ;
    END
  END k_rsp_data[212]
  PIN k_rsp_data[213]
    DIRECTION INPUT ;
    USE SIGNAL ;
    PORT
      LAYER M4 ;
        RECT  56.076 57.792 56.16 57.816 ;
    END
  END k_rsp_data[213]
  PIN k_rsp_data[214]
    DIRECTION INPUT ;
    USE SIGNAL ;
    PORT
      LAYER M4 ;
        RECT  56.076 57.936 56.16 57.96 ;
    END
  END k_rsp_data[214]
  PIN k_rsp_data[215]
    DIRECTION INPUT ;
    USE SIGNAL ;
    PORT
      LAYER M4 ;
        RECT  56.076 58.032 56.16 58.056 ;
    END
  END k_rsp_data[215]
  PIN k_rsp_data[216]
    DIRECTION INPUT ;
    USE SIGNAL ;
    PORT
      LAYER M4 ;
        RECT  56.076 58.128 56.16 58.152 ;
    END
  END k_rsp_data[216]
  PIN k_rsp_data[217]
    DIRECTION INPUT ;
    USE SIGNAL ;
    PORT
      LAYER M4 ;
        RECT  56.076 58.224 56.16 58.248 ;
    END
  END k_rsp_data[217]
  PIN k_rsp_data[218]
    DIRECTION INPUT ;
    USE SIGNAL ;
    PORT
      LAYER M4 ;
        RECT  56.076 58.32 56.16 58.344 ;
    END
  END k_rsp_data[218]
  PIN k_rsp_data[219]
    DIRECTION INPUT ;
    USE SIGNAL ;
    PORT
      LAYER M4 ;
        RECT  56.076 58.416 56.16 58.44 ;
    END
  END k_rsp_data[219]
  PIN k_rsp_data[21]
    DIRECTION INPUT ;
    USE SIGNAL ;
    PORT
      LAYER M4 ;
        RECT  56.076 37.968 56.16 37.992 ;
    END
  END k_rsp_data[21]
  PIN k_rsp_data[220]
    DIRECTION INPUT ;
    USE SIGNAL ;
    PORT
      LAYER M4 ;
        RECT  56.076 58.512 56.16 58.536 ;
    END
  END k_rsp_data[220]
  PIN k_rsp_data[221]
    DIRECTION INPUT ;
    USE SIGNAL ;
    PORT
      LAYER M4 ;
        RECT  56.076 58.656 56.16 58.68 ;
    END
  END k_rsp_data[221]
  PIN k_rsp_data[222]
    DIRECTION INPUT ;
    USE SIGNAL ;
    PORT
      LAYER M4 ;
        RECT  56.076 58.752 56.16 58.776 ;
    END
  END k_rsp_data[222]
  PIN k_rsp_data[223]
    DIRECTION INPUT ;
    USE SIGNAL ;
    PORT
      LAYER M4 ;
        RECT  56.076 58.848 56.16 58.872 ;
    END
  END k_rsp_data[223]
  PIN k_rsp_data[224]
    DIRECTION INPUT ;
    USE SIGNAL ;
    PORT
      LAYER M4 ;
        RECT  56.076 58.944 56.16 58.968 ;
    END
  END k_rsp_data[224]
  PIN k_rsp_data[225]
    DIRECTION INPUT ;
    USE SIGNAL ;
    PORT
      LAYER M4 ;
        RECT  56.076 59.04 56.16 59.064 ;
    END
  END k_rsp_data[225]
  PIN k_rsp_data[226]
    DIRECTION INPUT ;
    USE SIGNAL ;
    PORT
      LAYER M4 ;
        RECT  56.076 59.136 56.16 59.16 ;
    END
  END k_rsp_data[226]
  PIN k_rsp_data[227]
    DIRECTION INPUT ;
    USE SIGNAL ;
    PORT
      LAYER M4 ;
        RECT  56.076 59.28 56.16 59.304 ;
    END
  END k_rsp_data[227]
  PIN k_rsp_data[228]
    DIRECTION INPUT ;
    USE SIGNAL ;
    PORT
      LAYER M4 ;
        RECT  56.076 59.376 56.16 59.4 ;
    END
  END k_rsp_data[228]
  PIN k_rsp_data[229]
    DIRECTION INPUT ;
    USE SIGNAL ;
    PORT
      LAYER M4 ;
        RECT  56.076 59.472 56.16 59.496 ;
    END
  END k_rsp_data[229]
  PIN k_rsp_data[22]
    DIRECTION INPUT ;
    USE SIGNAL ;
    PORT
      LAYER M4 ;
        RECT  56.076 38.064 56.16 38.088 ;
    END
  END k_rsp_data[22]
  PIN k_rsp_data[230]
    DIRECTION INPUT ;
    USE SIGNAL ;
    PORT
      LAYER M4 ;
        RECT  56.076 59.568 56.16 59.592 ;
    END
  END k_rsp_data[230]
  PIN k_rsp_data[231]
    DIRECTION INPUT ;
    USE SIGNAL ;
    PORT
      LAYER M4 ;
        RECT  56.076 59.664 56.16 59.688 ;
    END
  END k_rsp_data[231]
  PIN k_rsp_data[232]
    DIRECTION INPUT ;
    USE SIGNAL ;
    PORT
      LAYER M4 ;
        RECT  56.076 59.76 56.16 59.784 ;
    END
  END k_rsp_data[232]
  PIN k_rsp_data[233]
    DIRECTION INPUT ;
    USE SIGNAL ;
    PORT
      LAYER M4 ;
        RECT  56.076 59.856 56.16 59.88 ;
    END
  END k_rsp_data[233]
  PIN k_rsp_data[234]
    DIRECTION INPUT ;
    USE SIGNAL ;
    PORT
      LAYER M4 ;
        RECT  56.076 60 56.16 60.024 ;
    END
  END k_rsp_data[234]
  PIN k_rsp_data[235]
    DIRECTION INPUT ;
    USE SIGNAL ;
    PORT
      LAYER M4 ;
        RECT  56.076 60.096 56.16 60.12 ;
    END
  END k_rsp_data[235]
  PIN k_rsp_data[236]
    DIRECTION INPUT ;
    USE SIGNAL ;
    PORT
      LAYER M4 ;
        RECT  56.076 60.192 56.16 60.216 ;
    END
  END k_rsp_data[236]
  PIN k_rsp_data[237]
    DIRECTION INPUT ;
    USE SIGNAL ;
    PORT
      LAYER M4 ;
        RECT  56.076 60.288 56.16 60.312 ;
    END
  END k_rsp_data[237]
  PIN k_rsp_data[238]
    DIRECTION INPUT ;
    USE SIGNAL ;
    PORT
      LAYER M4 ;
        RECT  56.076 60.384 56.16 60.408 ;
    END
  END k_rsp_data[238]
  PIN k_rsp_data[239]
    DIRECTION INPUT ;
    USE SIGNAL ;
    PORT
      LAYER M4 ;
        RECT  56.076 60.48 56.16 60.504 ;
    END
  END k_rsp_data[239]
  PIN k_rsp_data[23]
    DIRECTION INPUT ;
    USE SIGNAL ;
    PORT
      LAYER M4 ;
        RECT  56.076 38.16 56.16 38.184 ;
    END
  END k_rsp_data[23]
  PIN k_rsp_data[240]
    DIRECTION INPUT ;
    USE SIGNAL ;
    PORT
      LAYER M4 ;
        RECT  56.076 60.624 56.16 60.648 ;
    END
  END k_rsp_data[240]
  PIN k_rsp_data[241]
    DIRECTION INPUT ;
    USE SIGNAL ;
    PORT
      LAYER M4 ;
        RECT  56.076 60.72 56.16 60.744 ;
    END
  END k_rsp_data[241]
  PIN k_rsp_data[242]
    DIRECTION INPUT ;
    USE SIGNAL ;
    PORT
      LAYER M4 ;
        RECT  56.076 60.816 56.16 60.84 ;
    END
  END k_rsp_data[242]
  PIN k_rsp_data[243]
    DIRECTION INPUT ;
    USE SIGNAL ;
    PORT
      LAYER M4 ;
        RECT  56.076 60.912 56.16 60.936 ;
    END
  END k_rsp_data[243]
  PIN k_rsp_data[244]
    DIRECTION INPUT ;
    USE SIGNAL ;
    PORT
      LAYER M4 ;
        RECT  56.076 61.008 56.16 61.032 ;
    END
  END k_rsp_data[244]
  PIN k_rsp_data[245]
    DIRECTION INPUT ;
    USE SIGNAL ;
    PORT
      LAYER M4 ;
        RECT  56.076 61.104 56.16 61.128 ;
    END
  END k_rsp_data[245]
  PIN k_rsp_data[246]
    DIRECTION INPUT ;
    USE SIGNAL ;
    PORT
      LAYER M4 ;
        RECT  56.076 61.2 56.16 61.224 ;
    END
  END k_rsp_data[246]
  PIN k_rsp_data[247]
    DIRECTION INPUT ;
    USE SIGNAL ;
    PORT
      LAYER M4 ;
        RECT  56.076 61.344 56.16 61.368 ;
    END
  END k_rsp_data[247]
  PIN k_rsp_data[248]
    DIRECTION INPUT ;
    USE SIGNAL ;
    PORT
      LAYER M4 ;
        RECT  56.076 61.44 56.16 61.464 ;
    END
  END k_rsp_data[248]
  PIN k_rsp_data[249]
    DIRECTION INPUT ;
    USE SIGNAL ;
    PORT
      LAYER M4 ;
        RECT  56.076 61.536 56.16 61.56 ;
    END
  END k_rsp_data[249]
  PIN k_rsp_data[24]
    DIRECTION INPUT ;
    USE SIGNAL ;
    PORT
      LAYER M4 ;
        RECT  56.076 38.256 56.16 38.28 ;
    END
  END k_rsp_data[24]
  PIN k_rsp_data[250]
    DIRECTION INPUT ;
    USE SIGNAL ;
    PORT
      LAYER M4 ;
        RECT  56.076 61.632 56.16 61.656 ;
    END
  END k_rsp_data[250]
  PIN k_rsp_data[251]
    DIRECTION INPUT ;
    USE SIGNAL ;
    PORT
      LAYER M4 ;
        RECT  56.076 61.728 56.16 61.752 ;
    END
  END k_rsp_data[251]
  PIN k_rsp_data[252]
    DIRECTION INPUT ;
    USE SIGNAL ;
    PORT
      LAYER M4 ;
        RECT  56.076 61.824 56.16 61.848 ;
    END
  END k_rsp_data[252]
  PIN k_rsp_data[253]
    DIRECTION INPUT ;
    USE SIGNAL ;
    PORT
      LAYER M4 ;
        RECT  56.076 61.968 56.16 61.992 ;
    END
  END k_rsp_data[253]
  PIN k_rsp_data[254]
    DIRECTION INPUT ;
    USE SIGNAL ;
    PORT
      LAYER M4 ;
        RECT  56.076 62.064 56.16 62.088 ;
    END
  END k_rsp_data[254]
  PIN k_rsp_data[255]
    DIRECTION INPUT ;
    USE SIGNAL ;
    PORT
      LAYER M4 ;
        RECT  56.076 62.16 56.16 62.184 ;
    END
  END k_rsp_data[255]
  PIN k_rsp_data[25]
    DIRECTION INPUT ;
    USE SIGNAL ;
    PORT
      LAYER M4 ;
        RECT  56.076 38.4 56.16 38.424 ;
    END
  END k_rsp_data[25]
  PIN k_rsp_data[26]
    DIRECTION INPUT ;
    USE SIGNAL ;
    PORT
      LAYER M4 ;
        RECT  56.076 38.496 56.16 38.52 ;
    END
  END k_rsp_data[26]
  PIN k_rsp_data[27]
    DIRECTION INPUT ;
    USE SIGNAL ;
    PORT
      LAYER M4 ;
        RECT  56.076 38.592 56.16 38.616 ;
    END
  END k_rsp_data[27]
  PIN k_rsp_data[28]
    DIRECTION INPUT ;
    USE SIGNAL ;
    PORT
      LAYER M4 ;
        RECT  56.076 38.688 56.16 38.712 ;
    END
  END k_rsp_data[28]
  PIN k_rsp_data[29]
    DIRECTION INPUT ;
    USE SIGNAL ;
    PORT
      LAYER M4 ;
        RECT  56.076 38.784 56.16 38.808 ;
    END
  END k_rsp_data[29]
  PIN k_rsp_data[2]
    DIRECTION INPUT ;
    USE SIGNAL ;
    PORT
      LAYER M4 ;
        RECT  56.076 36 56.16 36.024 ;
    END
  END k_rsp_data[2]
  PIN k_rsp_data[30]
    DIRECTION INPUT ;
    USE SIGNAL ;
    PORT
      LAYER M4 ;
        RECT  56.076 38.88 56.16 38.904 ;
    END
  END k_rsp_data[30]
  PIN k_rsp_data[31]
    DIRECTION INPUT ;
    USE SIGNAL ;
    PORT
      LAYER M4 ;
        RECT  56.076 39.024 56.16 39.048 ;
    END
  END k_rsp_data[31]
  PIN k_rsp_data[32]
    DIRECTION INPUT ;
    USE SIGNAL ;
    PORT
      LAYER M4 ;
        RECT  56.076 39.12 56.16 39.144 ;
    END
  END k_rsp_data[32]
  PIN k_rsp_data[33]
    DIRECTION INPUT ;
    USE SIGNAL ;
    PORT
      LAYER M4 ;
        RECT  56.076 39.216 56.16 39.24 ;
    END
  END k_rsp_data[33]
  PIN k_rsp_data[34]
    DIRECTION INPUT ;
    USE SIGNAL ;
    PORT
      LAYER M4 ;
        RECT  56.076 39.312 56.16 39.336 ;
    END
  END k_rsp_data[34]
  PIN k_rsp_data[35]
    DIRECTION INPUT ;
    USE SIGNAL ;
    PORT
      LAYER M4 ;
        RECT  56.076 39.408 56.16 39.432 ;
    END
  END k_rsp_data[35]
  PIN k_rsp_data[36]
    DIRECTION INPUT ;
    USE SIGNAL ;
    PORT
      LAYER M4 ;
        RECT  56.076 39.504 56.16 39.528 ;
    END
  END k_rsp_data[36]
  PIN k_rsp_data[37]
    DIRECTION INPUT ;
    USE SIGNAL ;
    PORT
      LAYER M4 ;
        RECT  56.076 39.6 56.16 39.624 ;
    END
  END k_rsp_data[37]
  PIN k_rsp_data[38]
    DIRECTION INPUT ;
    USE SIGNAL ;
    PORT
      LAYER M4 ;
        RECT  56.076 39.744 56.16 39.768 ;
    END
  END k_rsp_data[38]
  PIN k_rsp_data[39]
    DIRECTION INPUT ;
    USE SIGNAL ;
    PORT
      LAYER M4 ;
        RECT  56.076 39.84 56.16 39.864 ;
    END
  END k_rsp_data[39]
  PIN k_rsp_data[3]
    DIRECTION INPUT ;
    USE SIGNAL ;
    PORT
      LAYER M4 ;
        RECT  56.076 36.096 56.16 36.12 ;
    END
  END k_rsp_data[3]
  PIN k_rsp_data[40]
    DIRECTION INPUT ;
    USE SIGNAL ;
    PORT
      LAYER M4 ;
        RECT  56.076 39.936 56.16 39.96 ;
    END
  END k_rsp_data[40]
  PIN k_rsp_data[41]
    DIRECTION INPUT ;
    USE SIGNAL ;
    PORT
      LAYER M4 ;
        RECT  56.076 40.032 56.16 40.056 ;
    END
  END k_rsp_data[41]
  PIN k_rsp_data[42]
    DIRECTION INPUT ;
    USE SIGNAL ;
    PORT
      LAYER M4 ;
        RECT  56.076 40.128 56.16 40.152 ;
    END
  END k_rsp_data[42]
  PIN k_rsp_data[43]
    DIRECTION INPUT ;
    USE SIGNAL ;
    PORT
      LAYER M4 ;
        RECT  56.076 40.224 56.16 40.248 ;
    END
  END k_rsp_data[43]
  PIN k_rsp_data[44]
    DIRECTION INPUT ;
    USE SIGNAL ;
    PORT
      LAYER M4 ;
        RECT  56.076 40.368 56.16 40.392 ;
    END
  END k_rsp_data[44]
  PIN k_rsp_data[45]
    DIRECTION INPUT ;
    USE SIGNAL ;
    PORT
      LAYER M4 ;
        RECT  56.076 40.464 56.16 40.488 ;
    END
  END k_rsp_data[45]
  PIN k_rsp_data[46]
    DIRECTION INPUT ;
    USE SIGNAL ;
    PORT
      LAYER M4 ;
        RECT  56.076 40.56 56.16 40.584 ;
    END
  END k_rsp_data[46]
  PIN k_rsp_data[47]
    DIRECTION INPUT ;
    USE SIGNAL ;
    PORT
      LAYER M4 ;
        RECT  56.076 40.656 56.16 40.68 ;
    END
  END k_rsp_data[47]
  PIN k_rsp_data[48]
    DIRECTION INPUT ;
    USE SIGNAL ;
    PORT
      LAYER M4 ;
        RECT  56.076 40.752 56.16 40.776 ;
    END
  END k_rsp_data[48]
  PIN k_rsp_data[49]
    DIRECTION INPUT ;
    USE SIGNAL ;
    PORT
      LAYER M4 ;
        RECT  56.076 40.848 56.16 40.872 ;
    END
  END k_rsp_data[49]
  PIN k_rsp_data[4]
    DIRECTION INPUT ;
    USE SIGNAL ;
    PORT
      LAYER M4 ;
        RECT  56.076 36.192 56.16 36.216 ;
    END
  END k_rsp_data[4]
  PIN k_rsp_data[50]
    DIRECTION INPUT ;
    USE SIGNAL ;
    PORT
      LAYER M4 ;
        RECT  56.076 40.944 56.16 40.968 ;
    END
  END k_rsp_data[50]
  PIN k_rsp_data[51]
    DIRECTION INPUT ;
    USE SIGNAL ;
    PORT
      LAYER M4 ;
        RECT  56.076 41.088 56.16 41.112 ;
    END
  END k_rsp_data[51]
  PIN k_rsp_data[52]
    DIRECTION INPUT ;
    USE SIGNAL ;
    PORT
      LAYER M4 ;
        RECT  56.076 41.184 56.16 41.208 ;
    END
  END k_rsp_data[52]
  PIN k_rsp_data[53]
    DIRECTION INPUT ;
    USE SIGNAL ;
    PORT
      LAYER M4 ;
        RECT  56.076 41.28 56.16 41.304 ;
    END
  END k_rsp_data[53]
  PIN k_rsp_data[54]
    DIRECTION INPUT ;
    USE SIGNAL ;
    PORT
      LAYER M4 ;
        RECT  56.076 41.376 56.16 41.4 ;
    END
  END k_rsp_data[54]
  PIN k_rsp_data[55]
    DIRECTION INPUT ;
    USE SIGNAL ;
    PORT
      LAYER M4 ;
        RECT  56.076 41.472 56.16 41.496 ;
    END
  END k_rsp_data[55]
  PIN k_rsp_data[56]
    DIRECTION INPUT ;
    USE SIGNAL ;
    PORT
      LAYER M4 ;
        RECT  56.076 41.568 56.16 41.592 ;
    END
  END k_rsp_data[56]
  PIN k_rsp_data[57]
    DIRECTION INPUT ;
    USE SIGNAL ;
    PORT
      LAYER M4 ;
        RECT  56.076 41.712 56.16 41.736 ;
    END
  END k_rsp_data[57]
  PIN k_rsp_data[58]
    DIRECTION INPUT ;
    USE SIGNAL ;
    PORT
      LAYER M4 ;
        RECT  56.076 41.808 56.16 41.832 ;
    END
  END k_rsp_data[58]
  PIN k_rsp_data[59]
    DIRECTION INPUT ;
    USE SIGNAL ;
    PORT
      LAYER M4 ;
        RECT  56.076 41.904 56.16 41.928 ;
    END
  END k_rsp_data[59]
  PIN k_rsp_data[5]
    DIRECTION INPUT ;
    USE SIGNAL ;
    PORT
      LAYER M4 ;
        RECT  56.076 36.336 56.16 36.36 ;
    END
  END k_rsp_data[5]
  PIN k_rsp_data[60]
    DIRECTION INPUT ;
    USE SIGNAL ;
    PORT
      LAYER M4 ;
        RECT  56.076 42 56.16 42.024 ;
    END
  END k_rsp_data[60]
  PIN k_rsp_data[61]
    DIRECTION INPUT ;
    USE SIGNAL ;
    PORT
      LAYER M4 ;
        RECT  56.076 42.096 56.16 42.12 ;
    END
  END k_rsp_data[61]
  PIN k_rsp_data[62]
    DIRECTION INPUT ;
    USE SIGNAL ;
    PORT
      LAYER M4 ;
        RECT  56.076 42.192 56.16 42.216 ;
    END
  END k_rsp_data[62]
  PIN k_rsp_data[63]
    DIRECTION INPUT ;
    USE SIGNAL ;
    PORT
      LAYER M4 ;
        RECT  56.076 42.288 56.16 42.312 ;
    END
  END k_rsp_data[63]
  PIN k_rsp_data[64]
    DIRECTION INPUT ;
    USE SIGNAL ;
    PORT
      LAYER M4 ;
        RECT  56.076 42.432 56.16 42.456 ;
    END
  END k_rsp_data[64]
  PIN k_rsp_data[65]
    DIRECTION INPUT ;
    USE SIGNAL ;
    PORT
      LAYER M4 ;
        RECT  56.076 42.528 56.16 42.552 ;
    END
  END k_rsp_data[65]
  PIN k_rsp_data[66]
    DIRECTION INPUT ;
    USE SIGNAL ;
    PORT
      LAYER M4 ;
        RECT  56.076 42.624 56.16 42.648 ;
    END
  END k_rsp_data[66]
  PIN k_rsp_data[67]
    DIRECTION INPUT ;
    USE SIGNAL ;
    PORT
      LAYER M4 ;
        RECT  56.076 42.72 56.16 42.744 ;
    END
  END k_rsp_data[67]
  PIN k_rsp_data[68]
    DIRECTION INPUT ;
    USE SIGNAL ;
    PORT
      LAYER M4 ;
        RECT  56.076 42.816 56.16 42.84 ;
    END
  END k_rsp_data[68]
  PIN k_rsp_data[69]
    DIRECTION INPUT ;
    USE SIGNAL ;
    PORT
      LAYER M4 ;
        RECT  56.076 42.912 56.16 42.936 ;
    END
  END k_rsp_data[69]
  PIN k_rsp_data[6]
    DIRECTION INPUT ;
    USE SIGNAL ;
    PORT
      LAYER M4 ;
        RECT  56.076 36.432 56.16 36.456 ;
    END
  END k_rsp_data[6]
  PIN k_rsp_data[70]
    DIRECTION INPUT ;
    USE SIGNAL ;
    PORT
      LAYER M4 ;
        RECT  56.076 43.056 56.16 43.08 ;
    END
  END k_rsp_data[70]
  PIN k_rsp_data[71]
    DIRECTION INPUT ;
    USE SIGNAL ;
    PORT
      LAYER M4 ;
        RECT  56.076 43.152 56.16 43.176 ;
    END
  END k_rsp_data[71]
  PIN k_rsp_data[72]
    DIRECTION INPUT ;
    USE SIGNAL ;
    PORT
      LAYER M4 ;
        RECT  56.076 43.248 56.16 43.272 ;
    END
  END k_rsp_data[72]
  PIN k_rsp_data[73]
    DIRECTION INPUT ;
    USE SIGNAL ;
    PORT
      LAYER M4 ;
        RECT  56.076 43.344 56.16 43.368 ;
    END
  END k_rsp_data[73]
  PIN k_rsp_data[74]
    DIRECTION INPUT ;
    USE SIGNAL ;
    PORT
      LAYER M4 ;
        RECT  56.076 43.44 56.16 43.464 ;
    END
  END k_rsp_data[74]
  PIN k_rsp_data[75]
    DIRECTION INPUT ;
    USE SIGNAL ;
    PORT
      LAYER M4 ;
        RECT  56.076 43.536 56.16 43.56 ;
    END
  END k_rsp_data[75]
  PIN k_rsp_data[76]
    DIRECTION INPUT ;
    USE SIGNAL ;
    PORT
      LAYER M4 ;
        RECT  56.076 43.632 56.16 43.656 ;
    END
  END k_rsp_data[76]
  PIN k_rsp_data[77]
    DIRECTION INPUT ;
    USE SIGNAL ;
    PORT
      LAYER M4 ;
        RECT  56.076 43.776 56.16 43.8 ;
    END
  END k_rsp_data[77]
  PIN k_rsp_data[78]
    DIRECTION INPUT ;
    USE SIGNAL ;
    PORT
      LAYER M4 ;
        RECT  56.076 43.872 56.16 43.896 ;
    END
  END k_rsp_data[78]
  PIN k_rsp_data[79]
    DIRECTION INPUT ;
    USE SIGNAL ;
    PORT
      LAYER M4 ;
        RECT  56.076 43.968 56.16 43.992 ;
    END
  END k_rsp_data[79]
  PIN k_rsp_data[7]
    DIRECTION INPUT ;
    USE SIGNAL ;
    PORT
      LAYER M4 ;
        RECT  56.076 36.528 56.16 36.552 ;
    END
  END k_rsp_data[7]
  PIN k_rsp_data[80]
    DIRECTION INPUT ;
    USE SIGNAL ;
    PORT
      LAYER M4 ;
        RECT  56.076 44.064 56.16 44.088 ;
    END
  END k_rsp_data[80]
  PIN k_rsp_data[81]
    DIRECTION INPUT ;
    USE SIGNAL ;
    PORT
      LAYER M4 ;
        RECT  56.076 44.16 56.16 44.184 ;
    END
  END k_rsp_data[81]
  PIN k_rsp_data[82]
    DIRECTION INPUT ;
    USE SIGNAL ;
    PORT
      LAYER M4 ;
        RECT  56.076 44.256 56.16 44.28 ;
    END
  END k_rsp_data[82]
  PIN k_rsp_data[83]
    DIRECTION INPUT ;
    USE SIGNAL ;
    PORT
      LAYER M4 ;
        RECT  56.076 44.4 56.16 44.424 ;
    END
  END k_rsp_data[83]
  PIN k_rsp_data[84]
    DIRECTION INPUT ;
    USE SIGNAL ;
    PORT
      LAYER M4 ;
        RECT  56.076 44.496 56.16 44.52 ;
    END
  END k_rsp_data[84]
  PIN k_rsp_data[85]
    DIRECTION INPUT ;
    USE SIGNAL ;
    PORT
      LAYER M4 ;
        RECT  56.076 44.592 56.16 44.616 ;
    END
  END k_rsp_data[85]
  PIN k_rsp_data[86]
    DIRECTION INPUT ;
    USE SIGNAL ;
    PORT
      LAYER M4 ;
        RECT  56.076 44.688 56.16 44.712 ;
    END
  END k_rsp_data[86]
  PIN k_rsp_data[87]
    DIRECTION INPUT ;
    USE SIGNAL ;
    PORT
      LAYER M4 ;
        RECT  56.076 44.784 56.16 44.808 ;
    END
  END k_rsp_data[87]
  PIN k_rsp_data[88]
    DIRECTION INPUT ;
    USE SIGNAL ;
    PORT
      LAYER M4 ;
        RECT  56.076 44.88 56.16 44.904 ;
    END
  END k_rsp_data[88]
  PIN k_rsp_data[89]
    DIRECTION INPUT ;
    USE SIGNAL ;
    PORT
      LAYER M4 ;
        RECT  56.076 44.976 56.16 45 ;
    END
  END k_rsp_data[89]
  PIN k_rsp_data[8]
    DIRECTION INPUT ;
    USE SIGNAL ;
    PORT
      LAYER M4 ;
        RECT  56.076 36.624 56.16 36.648 ;
    END
  END k_rsp_data[8]
  PIN k_rsp_data[90]
    DIRECTION INPUT ;
    USE SIGNAL ;
    PORT
      LAYER M4 ;
        RECT  56.076 45.12 56.16 45.144 ;
    END
  END k_rsp_data[90]
  PIN k_rsp_data[91]
    DIRECTION INPUT ;
    USE SIGNAL ;
    PORT
      LAYER M4 ;
        RECT  56.076 45.216 56.16 45.24 ;
    END
  END k_rsp_data[91]
  PIN k_rsp_data[92]
    DIRECTION INPUT ;
    USE SIGNAL ;
    PORT
      LAYER M4 ;
        RECT  56.076 45.312 56.16 45.336 ;
    END
  END k_rsp_data[92]
  PIN k_rsp_data[93]
    DIRECTION INPUT ;
    USE SIGNAL ;
    PORT
      LAYER M4 ;
        RECT  56.076 45.408 56.16 45.432 ;
    END
  END k_rsp_data[93]
  PIN k_rsp_data[94]
    DIRECTION INPUT ;
    USE SIGNAL ;
    PORT
      LAYER M4 ;
        RECT  56.076 45.504 56.16 45.528 ;
    END
  END k_rsp_data[94]
  PIN k_rsp_data[95]
    DIRECTION INPUT ;
    USE SIGNAL ;
    PORT
      LAYER M4 ;
        RECT  56.076 45.6 56.16 45.624 ;
    END
  END k_rsp_data[95]
  PIN k_rsp_data[96]
    DIRECTION INPUT ;
    USE SIGNAL ;
    PORT
      LAYER M4 ;
        RECT  56.076 45.744 56.16 45.768 ;
    END
  END k_rsp_data[96]
  PIN k_rsp_data[97]
    DIRECTION INPUT ;
    USE SIGNAL ;
    PORT
      LAYER M4 ;
        RECT  56.076 45.84 56.16 45.864 ;
    END
  END k_rsp_data[97]
  PIN k_rsp_data[98]
    DIRECTION INPUT ;
    USE SIGNAL ;
    PORT
      LAYER M4 ;
        RECT  56.076 45.936 56.16 45.96 ;
    END
  END k_rsp_data[98]
  PIN k_rsp_data[99]
    DIRECTION INPUT ;
    USE SIGNAL ;
    PORT
      LAYER M4 ;
        RECT  56.076 46.032 56.16 46.056 ;
    END
  END k_rsp_data[99]
  PIN k_rsp_data[9]
    DIRECTION INPUT ;
    USE SIGNAL ;
    PORT
      LAYER M4 ;
        RECT  56.076 36.72 56.16 36.744 ;
    END
  END k_rsp_data[9]
  PIN k_rsp_rdy
    DIRECTION OUTPUT ;
    USE SIGNAL ;
    PORT
      LAYER M4 ;
        RECT  56.076 62.256 56.16 62.28 ;
    END
  END k_rsp_rdy
  PIN k_rsp_v
    DIRECTION INPUT ;
    USE SIGNAL ;
    PORT
      LAYER M4 ;
        RECT  56.076 62.352 56.16 62.376 ;
    END
  END k_rsp_v
  PIN k_rsp_we
    DIRECTION INPUT ;
    USE SIGNAL ;
    PORT
      LAYER M4 ;
        RECT  56.076 62.448 56.16 62.472 ;
    END
  END k_rsp_we
  PIN mv[0]
    DIRECTION INPUT ;
    USE SIGNAL ;
    PORT
      LAYER M4 ;
        RECT  56.076 62.544 56.16 62.568 ;
    END
  END mv[0]
  PIN mv[100]
    DIRECTION INPUT ;
    USE SIGNAL ;
    PORT
      LAYER M4 ;
        RECT  56.076 72.912 56.16 72.936 ;
    END
  END mv[100]
  PIN mv[101]
    DIRECTION INPUT ;
    USE SIGNAL ;
    PORT
      LAYER M4 ;
        RECT  56.076 73.008 56.16 73.032 ;
    END
  END mv[101]
  PIN mv[102]
    DIRECTION INPUT ;
    USE SIGNAL ;
    PORT
      LAYER M4 ;
        RECT  56.076 73.104 56.16 73.128 ;
    END
  END mv[102]
  PIN mv[103]
    DIRECTION INPUT ;
    USE SIGNAL ;
    PORT
      LAYER M4 ;
        RECT  56.076 73.2 56.16 73.224 ;
    END
  END mv[103]
  PIN mv[104]
    DIRECTION INPUT ;
    USE SIGNAL ;
    PORT
      LAYER M4 ;
        RECT  56.076 73.296 56.16 73.32 ;
    END
  END mv[104]
  PIN mv[105]
    DIRECTION INPUT ;
    USE SIGNAL ;
    PORT
      LAYER M4 ;
        RECT  56.076 73.44 56.16 73.464 ;
    END
  END mv[105]
  PIN mv[106]
    DIRECTION INPUT ;
    USE SIGNAL ;
    PORT
      LAYER M4 ;
        RECT  56.076 73.536 56.16 73.56 ;
    END
  END mv[106]
  PIN mv[107]
    DIRECTION INPUT ;
    USE SIGNAL ;
    PORT
      LAYER M4 ;
        RECT  56.076 73.632 56.16 73.656 ;
    END
  END mv[107]
  PIN mv[108]
    DIRECTION INPUT ;
    USE SIGNAL ;
    PORT
      LAYER M4 ;
        RECT  56.076 73.728 56.16 73.752 ;
    END
  END mv[108]
  PIN mv[109]
    DIRECTION INPUT ;
    USE SIGNAL ;
    PORT
      LAYER M4 ;
        RECT  56.076 73.824 56.16 73.848 ;
    END
  END mv[109]
  PIN mv[10]
    DIRECTION INPUT ;
    USE SIGNAL ;
    PORT
      LAYER M4 ;
        RECT  56.076 63.6 56.16 63.624 ;
    END
  END mv[10]
  PIN mv[110]
    DIRECTION INPUT ;
    USE SIGNAL ;
    PORT
      LAYER M4 ;
        RECT  56.076 73.92 56.16 73.944 ;
    END
  END mv[110]
  PIN mv[111]
    DIRECTION INPUT ;
    USE SIGNAL ;
    PORT
      LAYER M4 ;
        RECT  56.076 74.016 56.16 74.04 ;
    END
  END mv[111]
  PIN mv[112]
    DIRECTION INPUT ;
    USE SIGNAL ;
    PORT
      LAYER M4 ;
        RECT  56.076 74.16 56.16 74.184 ;
    END
  END mv[112]
  PIN mv[113]
    DIRECTION INPUT ;
    USE SIGNAL ;
    PORT
      LAYER M4 ;
        RECT  56.076 74.256 56.16 74.28 ;
    END
  END mv[113]
  PIN mv[114]
    DIRECTION INPUT ;
    USE SIGNAL ;
    PORT
      LAYER M4 ;
        RECT  56.076 74.352 56.16 74.376 ;
    END
  END mv[114]
  PIN mv[115]
    DIRECTION INPUT ;
    USE SIGNAL ;
    PORT
      LAYER M4 ;
        RECT  56.076 74.448 56.16 74.472 ;
    END
  END mv[115]
  PIN mv[116]
    DIRECTION INPUT ;
    USE SIGNAL ;
    PORT
      LAYER M4 ;
        RECT  56.076 74.544 56.16 74.568 ;
    END
  END mv[116]
  PIN mv[117]
    DIRECTION INPUT ;
    USE SIGNAL ;
    PORT
      LAYER M4 ;
        RECT  56.076 74.64 56.16 74.664 ;
    END
  END mv[117]
  PIN mv[118]
    DIRECTION INPUT ;
    USE SIGNAL ;
    PORT
      LAYER M4 ;
        RECT  56.076 74.784 56.16 74.808 ;
    END
  END mv[118]
  PIN mv[119]
    DIRECTION INPUT ;
    USE SIGNAL ;
    PORT
      LAYER M4 ;
        RECT  56.076 74.88 56.16 74.904 ;
    END
  END mv[119]
  PIN mv[11]
    DIRECTION INPUT ;
    USE SIGNAL ;
    PORT
      LAYER M4 ;
        RECT  56.076 63.696 56.16 63.72 ;
    END
  END mv[11]
  PIN mv[120]
    DIRECTION INPUT ;
    USE SIGNAL ;
    PORT
      LAYER M4 ;
        RECT  56.076 74.976 56.16 75 ;
    END
  END mv[120]
  PIN mv[121]
    DIRECTION INPUT ;
    USE SIGNAL ;
    PORT
      LAYER M4 ;
        RECT  56.076 75.072 56.16 75.096 ;
    END
  END mv[121]
  PIN mv[122]
    DIRECTION INPUT ;
    USE SIGNAL ;
    PORT
      LAYER M4 ;
        RECT  56.076 75.168 56.16 75.192 ;
    END
  END mv[122]
  PIN mv[123]
    DIRECTION INPUT ;
    USE SIGNAL ;
    PORT
      LAYER M4 ;
        RECT  56.076 75.264 56.16 75.288 ;
    END
  END mv[123]
  PIN mv[124]
    DIRECTION INPUT ;
    USE SIGNAL ;
    PORT
      LAYER M4 ;
        RECT  56.076 75.36 56.16 75.384 ;
    END
  END mv[124]
  PIN mv[125]
    DIRECTION INPUT ;
    USE SIGNAL ;
    PORT
      LAYER M4 ;
        RECT  56.076 75.504 56.16 75.528 ;
    END
  END mv[125]
  PIN mv[126]
    DIRECTION INPUT ;
    USE SIGNAL ;
    PORT
      LAYER M4 ;
        RECT  56.076 75.6 56.16 75.624 ;
    END
  END mv[126]
  PIN mv[127]
    DIRECTION INPUT ;
    USE SIGNAL ;
    PORT
      LAYER M4 ;
        RECT  56.076 75.696 56.16 75.72 ;
    END
  END mv[127]
  PIN mv[128]
    DIRECTION INPUT ;
    USE SIGNAL ;
    PORT
      LAYER M4 ;
        RECT  56.076 75.792 56.16 75.816 ;
    END
  END mv[128]
  PIN mv[129]
    DIRECTION INPUT ;
    USE SIGNAL ;
    PORT
      LAYER M4 ;
        RECT  56.076 75.888 56.16 75.912 ;
    END
  END mv[129]
  PIN mv[12]
    DIRECTION INPUT ;
    USE SIGNAL ;
    PORT
      LAYER M4 ;
        RECT  56.076 63.792 56.16 63.816 ;
    END
  END mv[12]
  PIN mv[130]
    DIRECTION INPUT ;
    USE SIGNAL ;
    PORT
      LAYER M4 ;
        RECT  56.076 75.984 56.16 76.008 ;
    END
  END mv[130]
  PIN mv[131]
    DIRECTION INPUT ;
    USE SIGNAL ;
    PORT
      LAYER M4 ;
        RECT  56.076 76.128 56.16 76.152 ;
    END
  END mv[131]
  PIN mv[132]
    DIRECTION INPUT ;
    USE SIGNAL ;
    PORT
      LAYER M4 ;
        RECT  56.076 76.224 56.16 76.248 ;
    END
  END mv[132]
  PIN mv[133]
    DIRECTION INPUT ;
    USE SIGNAL ;
    PORT
      LAYER M4 ;
        RECT  56.076 76.32 56.16 76.344 ;
    END
  END mv[133]
  PIN mv[134]
    DIRECTION INPUT ;
    USE SIGNAL ;
    PORT
      LAYER M4 ;
        RECT  56.076 76.416 56.16 76.44 ;
    END
  END mv[134]
  PIN mv[135]
    DIRECTION INPUT ;
    USE SIGNAL ;
    PORT
      LAYER M4 ;
        RECT  56.076 76.512 56.16 76.536 ;
    END
  END mv[135]
  PIN mv[136]
    DIRECTION INPUT ;
    USE SIGNAL ;
    PORT
      LAYER M4 ;
        RECT  56.076 76.608 56.16 76.632 ;
    END
  END mv[136]
  PIN mv[137]
    DIRECTION INPUT ;
    USE SIGNAL ;
    PORT
      LAYER M4 ;
        RECT  56.076 76.704 56.16 76.728 ;
    END
  END mv[137]
  PIN mv[138]
    DIRECTION INPUT ;
    USE SIGNAL ;
    PORT
      LAYER M4 ;
        RECT  56.076 76.848 56.16 76.872 ;
    END
  END mv[138]
  PIN mv[139]
    DIRECTION INPUT ;
    USE SIGNAL ;
    PORT
      LAYER M4 ;
        RECT  56.076 76.944 56.16 76.968 ;
    END
  END mv[139]
  PIN mv[13]
    DIRECTION INPUT ;
    USE SIGNAL ;
    PORT
      LAYER M4 ;
        RECT  56.076 63.888 56.16 63.912 ;
    END
  END mv[13]
  PIN mv[140]
    DIRECTION INPUT ;
    USE SIGNAL ;
    PORT
      LAYER M4 ;
        RECT  56.076 77.04 56.16 77.064 ;
    END
  END mv[140]
  PIN mv[141]
    DIRECTION INPUT ;
    USE SIGNAL ;
    PORT
      LAYER M4 ;
        RECT  56.076 77.136 56.16 77.16 ;
    END
  END mv[141]
  PIN mv[142]
    DIRECTION INPUT ;
    USE SIGNAL ;
    PORT
      LAYER M4 ;
        RECT  56.076 77.232 56.16 77.256 ;
    END
  END mv[142]
  PIN mv[143]
    DIRECTION INPUT ;
    USE SIGNAL ;
    PORT
      LAYER M4 ;
        RECT  56.076 77.328 56.16 77.352 ;
    END
  END mv[143]
  PIN mv[144]
    DIRECTION INPUT ;
    USE SIGNAL ;
    PORT
      LAYER M4 ;
        RECT  56.076 77.472 56.16 77.496 ;
    END
  END mv[144]
  PIN mv[145]
    DIRECTION INPUT ;
    USE SIGNAL ;
    PORT
      LAYER M4 ;
        RECT  56.076 77.568 56.16 77.592 ;
    END
  END mv[145]
  PIN mv[146]
    DIRECTION INPUT ;
    USE SIGNAL ;
    PORT
      LAYER M4 ;
        RECT  56.076 77.664 56.16 77.688 ;
    END
  END mv[146]
  PIN mv[147]
    DIRECTION INPUT ;
    USE SIGNAL ;
    PORT
      LAYER M4 ;
        RECT  56.076 77.76 56.16 77.784 ;
    END
  END mv[147]
  PIN mv[148]
    DIRECTION INPUT ;
    USE SIGNAL ;
    PORT
      LAYER M4 ;
        RECT  56.076 77.856 56.16 77.88 ;
    END
  END mv[148]
  PIN mv[149]
    DIRECTION INPUT ;
    USE SIGNAL ;
    PORT
      LAYER M4 ;
        RECT  56.076 77.952 56.16 77.976 ;
    END
  END mv[149]
  PIN mv[14]
    DIRECTION INPUT ;
    USE SIGNAL ;
    PORT
      LAYER M4 ;
        RECT  56.076 64.032 56.16 64.056 ;
    END
  END mv[14]
  PIN mv[150]
    DIRECTION INPUT ;
    USE SIGNAL ;
    PORT
      LAYER M4 ;
        RECT  56.076 78.048 56.16 78.072 ;
    END
  END mv[150]
  PIN mv[151]
    DIRECTION INPUT ;
    USE SIGNAL ;
    PORT
      LAYER M4 ;
        RECT  56.076 78.192 56.16 78.216 ;
    END
  END mv[151]
  PIN mv[152]
    DIRECTION INPUT ;
    USE SIGNAL ;
    PORT
      LAYER M4 ;
        RECT  56.076 78.288 56.16 78.312 ;
    END
  END mv[152]
  PIN mv[153]
    DIRECTION INPUT ;
    USE SIGNAL ;
    PORT
      LAYER M4 ;
        RECT  56.076 78.384 56.16 78.408 ;
    END
  END mv[153]
  PIN mv[154]
    DIRECTION INPUT ;
    USE SIGNAL ;
    PORT
      LAYER M4 ;
        RECT  56.076 78.48 56.16 78.504 ;
    END
  END mv[154]
  PIN mv[155]
    DIRECTION INPUT ;
    USE SIGNAL ;
    PORT
      LAYER M4 ;
        RECT  56.076 78.576 56.16 78.6 ;
    END
  END mv[155]
  PIN mv[156]
    DIRECTION INPUT ;
    USE SIGNAL ;
    PORT
      LAYER M4 ;
        RECT  56.076 78.672 56.16 78.696 ;
    END
  END mv[156]
  PIN mv[157]
    DIRECTION INPUT ;
    USE SIGNAL ;
    PORT
      LAYER M4 ;
        RECT  56.076 78.816 56.16 78.84 ;
    END
  END mv[157]
  PIN mv[158]
    DIRECTION INPUT ;
    USE SIGNAL ;
    PORT
      LAYER M4 ;
        RECT  56.076 78.912 56.16 78.936 ;
    END
  END mv[158]
  PIN mv[159]
    DIRECTION INPUT ;
    USE SIGNAL ;
    PORT
      LAYER M4 ;
        RECT  56.076 79.008 56.16 79.032 ;
    END
  END mv[159]
  PIN mv[15]
    DIRECTION INPUT ;
    USE SIGNAL ;
    PORT
      LAYER M4 ;
        RECT  56.076 64.128 56.16 64.152 ;
    END
  END mv[15]
  PIN mv[160]
    DIRECTION INPUT ;
    USE SIGNAL ;
    PORT
      LAYER M4 ;
        RECT  56.076 79.104 56.16 79.128 ;
    END
  END mv[160]
  PIN mv[161]
    DIRECTION INPUT ;
    USE SIGNAL ;
    PORT
      LAYER M4 ;
        RECT  56.076 79.2 56.16 79.224 ;
    END
  END mv[161]
  PIN mv[162]
    DIRECTION INPUT ;
    USE SIGNAL ;
    PORT
      LAYER M4 ;
        RECT  56.076 79.296 56.16 79.32 ;
    END
  END mv[162]
  PIN mv[163]
    DIRECTION INPUT ;
    USE SIGNAL ;
    PORT
      LAYER M4 ;
        RECT  56.076 79.392 56.16 79.416 ;
    END
  END mv[163]
  PIN mv[164]
    DIRECTION INPUT ;
    USE SIGNAL ;
    PORT
      LAYER M4 ;
        RECT  56.076 79.536 56.16 79.56 ;
    END
  END mv[164]
  PIN mv[165]
    DIRECTION INPUT ;
    USE SIGNAL ;
    PORT
      LAYER M4 ;
        RECT  56.076 79.632 56.16 79.656 ;
    END
  END mv[165]
  PIN mv[166]
    DIRECTION INPUT ;
    USE SIGNAL ;
    PORT
      LAYER M4 ;
        RECT  56.076 79.728 56.16 79.752 ;
    END
  END mv[166]
  PIN mv[167]
    DIRECTION INPUT ;
    USE SIGNAL ;
    PORT
      LAYER M4 ;
        RECT  56.076 79.824 56.16 79.848 ;
    END
  END mv[167]
  PIN mv[168]
    DIRECTION INPUT ;
    USE SIGNAL ;
    PORT
      LAYER M4 ;
        RECT  56.076 79.92 56.16 79.944 ;
    END
  END mv[168]
  PIN mv[169]
    DIRECTION INPUT ;
    USE SIGNAL ;
    PORT
      LAYER M4 ;
        RECT  56.076 80.016 56.16 80.04 ;
    END
  END mv[169]
  PIN mv[16]
    DIRECTION INPUT ;
    USE SIGNAL ;
    PORT
      LAYER M4 ;
        RECT  56.076 64.224 56.16 64.248 ;
    END
  END mv[16]
  PIN mv[170]
    DIRECTION INPUT ;
    USE SIGNAL ;
    PORT
      LAYER M4 ;
        RECT  56.076 80.112 56.16 80.136 ;
    END
  END mv[170]
  PIN mv[171]
    DIRECTION INPUT ;
    USE SIGNAL ;
    PORT
      LAYER M4 ;
        RECT  56.076 80.256 56.16 80.28 ;
    END
  END mv[171]
  PIN mv[172]
    DIRECTION INPUT ;
    USE SIGNAL ;
    PORT
      LAYER M4 ;
        RECT  56.076 80.352 56.16 80.376 ;
    END
  END mv[172]
  PIN mv[173]
    DIRECTION INPUT ;
    USE SIGNAL ;
    PORT
      LAYER M4 ;
        RECT  56.076 80.448 56.16 80.472 ;
    END
  END mv[173]
  PIN mv[174]
    DIRECTION INPUT ;
    USE SIGNAL ;
    PORT
      LAYER M4 ;
        RECT  56.076 80.544 56.16 80.568 ;
    END
  END mv[174]
  PIN mv[175]
    DIRECTION INPUT ;
    USE SIGNAL ;
    PORT
      LAYER M4 ;
        RECT  56.076 80.64 56.16 80.664 ;
    END
  END mv[175]
  PIN mv[176]
    DIRECTION INPUT ;
    USE SIGNAL ;
    PORT
      LAYER M4 ;
        RECT  56.076 80.736 56.16 80.76 ;
    END
  END mv[176]
  PIN mv[177]
    DIRECTION INPUT ;
    USE SIGNAL ;
    PORT
      LAYER M4 ;
        RECT  56.076 80.88 56.16 80.904 ;
    END
  END mv[177]
  PIN mv[178]
    DIRECTION INPUT ;
    USE SIGNAL ;
    PORT
      LAYER M4 ;
        RECT  56.076 80.976 56.16 81 ;
    END
  END mv[178]
  PIN mv[179]
    DIRECTION INPUT ;
    USE SIGNAL ;
    PORT
      LAYER M4 ;
        RECT  56.076 81.072 56.16 81.096 ;
    END
  END mv[179]
  PIN mv[17]
    DIRECTION INPUT ;
    USE SIGNAL ;
    PORT
      LAYER M4 ;
        RECT  56.076 64.32 56.16 64.344 ;
    END
  END mv[17]
  PIN mv[180]
    DIRECTION INPUT ;
    USE SIGNAL ;
    PORT
      LAYER M4 ;
        RECT  56.076 81.168 56.16 81.192 ;
    END
  END mv[180]
  PIN mv[181]
    DIRECTION INPUT ;
    USE SIGNAL ;
    PORT
      LAYER M4 ;
        RECT  56.076 81.264 56.16 81.288 ;
    END
  END mv[181]
  PIN mv[182]
    DIRECTION INPUT ;
    USE SIGNAL ;
    PORT
      LAYER M4 ;
        RECT  56.076 81.36 56.16 81.384 ;
    END
  END mv[182]
  PIN mv[183]
    DIRECTION INPUT ;
    USE SIGNAL ;
    PORT
      LAYER M4 ;
        RECT  56.076 81.456 56.16 81.48 ;
    END
  END mv[183]
  PIN mv[184]
    DIRECTION INPUT ;
    USE SIGNAL ;
    PORT
      LAYER M4 ;
        RECT  56.076 81.6 56.16 81.624 ;
    END
  END mv[184]
  PIN mv[185]
    DIRECTION INPUT ;
    USE SIGNAL ;
    PORT
      LAYER M4 ;
        RECT  56.076 81.696 56.16 81.72 ;
    END
  END mv[185]
  PIN mv[186]
    DIRECTION INPUT ;
    USE SIGNAL ;
    PORT
      LAYER M4 ;
        RECT  56.076 81.792 56.16 81.816 ;
    END
  END mv[186]
  PIN mv[187]
    DIRECTION INPUT ;
    USE SIGNAL ;
    PORT
      LAYER M4 ;
        RECT  56.076 81.888 56.16 81.912 ;
    END
  END mv[187]
  PIN mv[188]
    DIRECTION INPUT ;
    USE SIGNAL ;
    PORT
      LAYER M4 ;
        RECT  56.076 81.984 56.16 82.008 ;
    END
  END mv[188]
  PIN mv[189]
    DIRECTION INPUT ;
    USE SIGNAL ;
    PORT
      LAYER M4 ;
        RECT  56.076 82.08 56.16 82.104 ;
    END
  END mv[189]
  PIN mv[18]
    DIRECTION INPUT ;
    USE SIGNAL ;
    PORT
      LAYER M4 ;
        RECT  56.076 64.416 56.16 64.44 ;
    END
  END mv[18]
  PIN mv[190]
    DIRECTION INPUT ;
    USE SIGNAL ;
    PORT
      LAYER M4 ;
        RECT  56.076 82.224 56.16 82.248 ;
    END
  END mv[190]
  PIN mv[191]
    DIRECTION INPUT ;
    USE SIGNAL ;
    PORT
      LAYER M4 ;
        RECT  56.076 82.32 56.16 82.344 ;
    END
  END mv[191]
  PIN mv[192]
    DIRECTION INPUT ;
    USE SIGNAL ;
    PORT
      LAYER M4 ;
        RECT  56.076 82.416 56.16 82.44 ;
    END
  END mv[192]
  PIN mv[193]
    DIRECTION INPUT ;
    USE SIGNAL ;
    PORT
      LAYER M4 ;
        RECT  56.076 82.512 56.16 82.536 ;
    END
  END mv[193]
  PIN mv[194]
    DIRECTION INPUT ;
    USE SIGNAL ;
    PORT
      LAYER M4 ;
        RECT  56.076 82.608 56.16 82.632 ;
    END
  END mv[194]
  PIN mv[195]
    DIRECTION INPUT ;
    USE SIGNAL ;
    PORT
      LAYER M4 ;
        RECT  56.076 82.704 56.16 82.728 ;
    END
  END mv[195]
  PIN mv[196]
    DIRECTION INPUT ;
    USE SIGNAL ;
    PORT
      LAYER M4 ;
        RECT  56.076 82.8 56.16 82.824 ;
    END
  END mv[196]
  PIN mv[197]
    DIRECTION INPUT ;
    USE SIGNAL ;
    PORT
      LAYER M4 ;
        RECT  56.076 82.944 56.16 82.968 ;
    END
  END mv[197]
  PIN mv[198]
    DIRECTION INPUT ;
    USE SIGNAL ;
    PORT
      LAYER M4 ;
        RECT  56.076 83.04 56.16 83.064 ;
    END
  END mv[198]
  PIN mv[199]
    DIRECTION INPUT ;
    USE SIGNAL ;
    PORT
      LAYER M4 ;
        RECT  56.076 83.136 56.16 83.16 ;
    END
  END mv[199]
  PIN mv[19]
    DIRECTION INPUT ;
    USE SIGNAL ;
    PORT
      LAYER M4 ;
        RECT  56.076 64.512 56.16 64.536 ;
    END
  END mv[19]
  PIN mv[1]
    DIRECTION INPUT ;
    USE SIGNAL ;
    PORT
      LAYER M4 ;
        RECT  56.076 62.688 56.16 62.712 ;
    END
  END mv[1]
  PIN mv[200]
    DIRECTION INPUT ;
    USE SIGNAL ;
    PORT
      LAYER M4 ;
        RECT  56.076 83.232 56.16 83.256 ;
    END
  END mv[200]
  PIN mv[201]
    DIRECTION INPUT ;
    USE SIGNAL ;
    PORT
      LAYER M4 ;
        RECT  56.076 83.328 56.16 83.352 ;
    END
  END mv[201]
  PIN mv[202]
    DIRECTION INPUT ;
    USE SIGNAL ;
    PORT
      LAYER M4 ;
        RECT  56.076 83.424 56.16 83.448 ;
    END
  END mv[202]
  PIN mv[203]
    DIRECTION INPUT ;
    USE SIGNAL ;
    PORT
      LAYER M4 ;
        RECT  56.076 83.568 56.16 83.592 ;
    END
  END mv[203]
  PIN mv[204]
    DIRECTION INPUT ;
    USE SIGNAL ;
    PORT
      LAYER M4 ;
        RECT  56.076 83.664 56.16 83.688 ;
    END
  END mv[204]
  PIN mv[205]
    DIRECTION INPUT ;
    USE SIGNAL ;
    PORT
      LAYER M4 ;
        RECT  56.076 83.76 56.16 83.784 ;
    END
  END mv[205]
  PIN mv[206]
    DIRECTION INPUT ;
    USE SIGNAL ;
    PORT
      LAYER M4 ;
        RECT  56.076 83.856 56.16 83.88 ;
    END
  END mv[206]
  PIN mv[207]
    DIRECTION INPUT ;
    USE SIGNAL ;
    PORT
      LAYER M4 ;
        RECT  56.076 83.952 56.16 83.976 ;
    END
  END mv[207]
  PIN mv[208]
    DIRECTION INPUT ;
    USE SIGNAL ;
    PORT
      LAYER M4 ;
        RECT  56.076 84.048 56.16 84.072 ;
    END
  END mv[208]
  PIN mv[209]
    DIRECTION INPUT ;
    USE SIGNAL ;
    PORT
      LAYER M4 ;
        RECT  56.076 84.144 56.16 84.168 ;
    END
  END mv[209]
  PIN mv[20]
    DIRECTION INPUT ;
    USE SIGNAL ;
    PORT
      LAYER M4 ;
        RECT  56.076 64.656 56.16 64.68 ;
    END
  END mv[20]
  PIN mv[210]
    DIRECTION INPUT ;
    USE SIGNAL ;
    PORT
      LAYER M4 ;
        RECT  56.076 84.288 56.16 84.312 ;
    END
  END mv[210]
  PIN mv[211]
    DIRECTION INPUT ;
    USE SIGNAL ;
    PORT
      LAYER M4 ;
        RECT  56.076 84.384 56.16 84.408 ;
    END
  END mv[211]
  PIN mv[212]
    DIRECTION INPUT ;
    USE SIGNAL ;
    PORT
      LAYER M4 ;
        RECT  56.076 84.48 56.16 84.504 ;
    END
  END mv[212]
  PIN mv[213]
    DIRECTION INPUT ;
    USE SIGNAL ;
    PORT
      LAYER M4 ;
        RECT  56.076 84.576 56.16 84.6 ;
    END
  END mv[213]
  PIN mv[214]
    DIRECTION INPUT ;
    USE SIGNAL ;
    PORT
      LAYER M4 ;
        RECT  56.076 84.672 56.16 84.696 ;
    END
  END mv[214]
  PIN mv[215]
    DIRECTION INPUT ;
    USE SIGNAL ;
    PORT
      LAYER M4 ;
        RECT  56.076 84.768 56.16 84.792 ;
    END
  END mv[215]
  PIN mv[216]
    DIRECTION INPUT ;
    USE SIGNAL ;
    PORT
      LAYER M4 ;
        RECT  56.076 84.912 56.16 84.936 ;
    END
  END mv[216]
  PIN mv[217]
    DIRECTION INPUT ;
    USE SIGNAL ;
    PORT
      LAYER M4 ;
        RECT  56.076 85.008 56.16 85.032 ;
    END
  END mv[217]
  PIN mv[218]
    DIRECTION INPUT ;
    USE SIGNAL ;
    PORT
      LAYER M4 ;
        RECT  56.076 85.104 56.16 85.128 ;
    END
  END mv[218]
  PIN mv[219]
    DIRECTION INPUT ;
    USE SIGNAL ;
    PORT
      LAYER M4 ;
        RECT  56.076 85.2 56.16 85.224 ;
    END
  END mv[219]
  PIN mv[21]
    DIRECTION INPUT ;
    USE SIGNAL ;
    PORT
      LAYER M4 ;
        RECT  56.076 64.752 56.16 64.776 ;
    END
  END mv[21]
  PIN mv[220]
    DIRECTION INPUT ;
    USE SIGNAL ;
    PORT
      LAYER M4 ;
        RECT  56.076 85.296 56.16 85.32 ;
    END
  END mv[220]
  PIN mv[221]
    DIRECTION INPUT ;
    USE SIGNAL ;
    PORT
      LAYER M4 ;
        RECT  56.076 85.392 56.16 85.416 ;
    END
  END mv[221]
  PIN mv[222]
    DIRECTION INPUT ;
    USE SIGNAL ;
    PORT
      LAYER M4 ;
        RECT  56.076 85.488 56.16 85.512 ;
    END
  END mv[222]
  PIN mv[223]
    DIRECTION INPUT ;
    USE SIGNAL ;
    PORT
      LAYER M4 ;
        RECT  56.076 85.632 56.16 85.656 ;
    END
  END mv[223]
  PIN mv[224]
    DIRECTION INPUT ;
    USE SIGNAL ;
    PORT
      LAYER M4 ;
        RECT  56.076 85.728 56.16 85.752 ;
    END
  END mv[224]
  PIN mv[225]
    DIRECTION INPUT ;
    USE SIGNAL ;
    PORT
      LAYER M4 ;
        RECT  56.076 85.824 56.16 85.848 ;
    END
  END mv[225]
  PIN mv[226]
    DIRECTION INPUT ;
    USE SIGNAL ;
    PORT
      LAYER M4 ;
        RECT  56.076 85.92 56.16 85.944 ;
    END
  END mv[226]
  PIN mv[22]
    DIRECTION INPUT ;
    USE SIGNAL ;
    PORT
      LAYER M4 ;
        RECT  56.076 64.848 56.16 64.872 ;
    END
  END mv[22]
  PIN mv[23]
    DIRECTION INPUT ;
    USE SIGNAL ;
    PORT
      LAYER M4 ;
        RECT  56.076 64.944 56.16 64.968 ;
    END
  END mv[23]
  PIN mv[24]
    DIRECTION INPUT ;
    USE SIGNAL ;
    PORT
      LAYER M4 ;
        RECT  56.076 65.04 56.16 65.064 ;
    END
  END mv[24]
  PIN mv[25]
    DIRECTION INPUT ;
    USE SIGNAL ;
    PORT
      LAYER M4 ;
        RECT  56.076 65.136 56.16 65.16 ;
    END
  END mv[25]
  PIN mv[26]
    DIRECTION INPUT ;
    USE SIGNAL ;
    PORT
      LAYER M4 ;
        RECT  56.076 65.232 56.16 65.256 ;
    END
  END mv[26]
  PIN mv[27]
    DIRECTION INPUT ;
    USE SIGNAL ;
    PORT
      LAYER M4 ;
        RECT  56.076 65.376 56.16 65.4 ;
    END
  END mv[27]
  PIN mv[28]
    DIRECTION INPUT ;
    USE SIGNAL ;
    PORT
      LAYER M4 ;
        RECT  56.076 65.472 56.16 65.496 ;
    END
  END mv[28]
  PIN mv[29]
    DIRECTION INPUT ;
    USE SIGNAL ;
    PORT
      LAYER M4 ;
        RECT  56.076 65.568 56.16 65.592 ;
    END
  END mv[29]
  PIN mv[2]
    DIRECTION INPUT ;
    USE SIGNAL ;
    PORT
      LAYER M4 ;
        RECT  56.076 62.784 56.16 62.808 ;
    END
  END mv[2]
  PIN mv[30]
    DIRECTION INPUT ;
    USE SIGNAL ;
    PORT
      LAYER M4 ;
        RECT  56.076 65.664 56.16 65.688 ;
    END
  END mv[30]
  PIN mv[31]
    DIRECTION INPUT ;
    USE SIGNAL ;
    PORT
      LAYER M4 ;
        RECT  56.076 65.76 56.16 65.784 ;
    END
  END mv[31]
  PIN mv[32]
    DIRECTION INPUT ;
    USE SIGNAL ;
    PORT
      LAYER M4 ;
        RECT  56.076 65.856 56.16 65.88 ;
    END
  END mv[32]
  PIN mv[33]
    DIRECTION INPUT ;
    USE SIGNAL ;
    PORT
      LAYER M4 ;
        RECT  56.076 66 56.16 66.024 ;
    END
  END mv[33]
  PIN mv[34]
    DIRECTION INPUT ;
    USE SIGNAL ;
    PORT
      LAYER M4 ;
        RECT  56.076 66.096 56.16 66.12 ;
    END
  END mv[34]
  PIN mv[35]
    DIRECTION INPUT ;
    USE SIGNAL ;
    PORT
      LAYER M4 ;
        RECT  56.076 66.192 56.16 66.216 ;
    END
  END mv[35]
  PIN mv[36]
    DIRECTION INPUT ;
    USE SIGNAL ;
    PORT
      LAYER M4 ;
        RECT  56.076 66.288 56.16 66.312 ;
    END
  END mv[36]
  PIN mv[37]
    DIRECTION INPUT ;
    USE SIGNAL ;
    PORT
      LAYER M4 ;
        RECT  56.076 66.384 56.16 66.408 ;
    END
  END mv[37]
  PIN mv[38]
    DIRECTION INPUT ;
    USE SIGNAL ;
    PORT
      LAYER M4 ;
        RECT  56.076 66.48 56.16 66.504 ;
    END
  END mv[38]
  PIN mv[39]
    DIRECTION INPUT ;
    USE SIGNAL ;
    PORT
      LAYER M4 ;
        RECT  56.076 66.576 56.16 66.6 ;
    END
  END mv[39]
  PIN mv[3]
    DIRECTION INPUT ;
    USE SIGNAL ;
    PORT
      LAYER M4 ;
        RECT  56.076 62.88 56.16 62.904 ;
    END
  END mv[3]
  PIN mv[40]
    DIRECTION INPUT ;
    USE SIGNAL ;
    PORT
      LAYER M4 ;
        RECT  56.076 66.72 56.16 66.744 ;
    END
  END mv[40]
  PIN mv[41]
    DIRECTION INPUT ;
    USE SIGNAL ;
    PORT
      LAYER M4 ;
        RECT  56.076 66.816 56.16 66.84 ;
    END
  END mv[41]
  PIN mv[42]
    DIRECTION INPUT ;
    USE SIGNAL ;
    PORT
      LAYER M4 ;
        RECT  56.076 66.912 56.16 66.936 ;
    END
  END mv[42]
  PIN mv[43]
    DIRECTION INPUT ;
    USE SIGNAL ;
    PORT
      LAYER M4 ;
        RECT  56.076 67.008 56.16 67.032 ;
    END
  END mv[43]
  PIN mv[44]
    DIRECTION INPUT ;
    USE SIGNAL ;
    PORT
      LAYER M4 ;
        RECT  56.076 67.104 56.16 67.128 ;
    END
  END mv[44]
  PIN mv[45]
    DIRECTION INPUT ;
    USE SIGNAL ;
    PORT
      LAYER M4 ;
        RECT  56.076 67.2 56.16 67.224 ;
    END
  END mv[45]
  PIN mv[46]
    DIRECTION INPUT ;
    USE SIGNAL ;
    PORT
      LAYER M4 ;
        RECT  56.076 67.344 56.16 67.368 ;
    END
  END mv[46]
  PIN mv[47]
    DIRECTION INPUT ;
    USE SIGNAL ;
    PORT
      LAYER M4 ;
        RECT  56.076 67.44 56.16 67.464 ;
    END
  END mv[47]
  PIN mv[48]
    DIRECTION INPUT ;
    USE SIGNAL ;
    PORT
      LAYER M4 ;
        RECT  56.076 67.536 56.16 67.56 ;
    END
  END mv[48]
  PIN mv[49]
    DIRECTION INPUT ;
    USE SIGNAL ;
    PORT
      LAYER M4 ;
        RECT  56.076 67.632 56.16 67.656 ;
    END
  END mv[49]
  PIN mv[4]
    DIRECTION INPUT ;
    USE SIGNAL ;
    PORT
      LAYER M4 ;
        RECT  56.076 62.976 56.16 63 ;
    END
  END mv[4]
  PIN mv[50]
    DIRECTION INPUT ;
    USE SIGNAL ;
    PORT
      LAYER M4 ;
        RECT  56.076 67.728 56.16 67.752 ;
    END
  END mv[50]
  PIN mv[51]
    DIRECTION INPUT ;
    USE SIGNAL ;
    PORT
      LAYER M4 ;
        RECT  56.076 67.824 56.16 67.848 ;
    END
  END mv[51]
  PIN mv[52]
    DIRECTION INPUT ;
    USE SIGNAL ;
    PORT
      LAYER M4 ;
        RECT  56.076 67.92 56.16 67.944 ;
    END
  END mv[52]
  PIN mv[53]
    DIRECTION INPUT ;
    USE SIGNAL ;
    PORT
      LAYER M4 ;
        RECT  56.076 68.064 56.16 68.088 ;
    END
  END mv[53]
  PIN mv[54]
    DIRECTION INPUT ;
    USE SIGNAL ;
    PORT
      LAYER M4 ;
        RECT  56.076 68.16 56.16 68.184 ;
    END
  END mv[54]
  PIN mv[55]
    DIRECTION INPUT ;
    USE SIGNAL ;
    PORT
      LAYER M4 ;
        RECT  56.076 68.256 56.16 68.28 ;
    END
  END mv[55]
  PIN mv[56]
    DIRECTION INPUT ;
    USE SIGNAL ;
    PORT
      LAYER M4 ;
        RECT  56.076 68.352 56.16 68.376 ;
    END
  END mv[56]
  PIN mv[57]
    DIRECTION INPUT ;
    USE SIGNAL ;
    PORT
      LAYER M4 ;
        RECT  56.076 68.448 56.16 68.472 ;
    END
  END mv[57]
  PIN mv[58]
    DIRECTION INPUT ;
    USE SIGNAL ;
    PORT
      LAYER M4 ;
        RECT  56.076 68.544 56.16 68.568 ;
    END
  END mv[58]
  PIN mv[59]
    DIRECTION INPUT ;
    USE SIGNAL ;
    PORT
      LAYER M4 ;
        RECT  56.076 68.688 56.16 68.712 ;
    END
  END mv[59]
  PIN mv[5]
    DIRECTION INPUT ;
    USE SIGNAL ;
    PORT
      LAYER M4 ;
        RECT  56.076 63.072 56.16 63.096 ;
    END
  END mv[5]
  PIN mv[60]
    DIRECTION INPUT ;
    USE SIGNAL ;
    PORT
      LAYER M4 ;
        RECT  56.076 68.784 56.16 68.808 ;
    END
  END mv[60]
  PIN mv[61]
    DIRECTION INPUT ;
    USE SIGNAL ;
    PORT
      LAYER M4 ;
        RECT  56.076 68.88 56.16 68.904 ;
    END
  END mv[61]
  PIN mv[62]
    DIRECTION INPUT ;
    USE SIGNAL ;
    PORT
      LAYER M4 ;
        RECT  56.076 68.976 56.16 69 ;
    END
  END mv[62]
  PIN mv[63]
    DIRECTION INPUT ;
    USE SIGNAL ;
    PORT
      LAYER M4 ;
        RECT  56.076 69.072 56.16 69.096 ;
    END
  END mv[63]
  PIN mv[64]
    DIRECTION INPUT ;
    USE SIGNAL ;
    PORT
      LAYER M4 ;
        RECT  56.076 69.168 56.16 69.192 ;
    END
  END mv[64]
  PIN mv[65]
    DIRECTION INPUT ;
    USE SIGNAL ;
    PORT
      LAYER M4 ;
        RECT  56.076 69.264 56.16 69.288 ;
    END
  END mv[65]
  PIN mv[66]
    DIRECTION INPUT ;
    USE SIGNAL ;
    PORT
      LAYER M4 ;
        RECT  56.076 69.408 56.16 69.432 ;
    END
  END mv[66]
  PIN mv[67]
    DIRECTION INPUT ;
    USE SIGNAL ;
    PORT
      LAYER M4 ;
        RECT  56.076 69.504 56.16 69.528 ;
    END
  END mv[67]
  PIN mv[68]
    DIRECTION INPUT ;
    USE SIGNAL ;
    PORT
      LAYER M4 ;
        RECT  56.076 69.6 56.16 69.624 ;
    END
  END mv[68]
  PIN mv[69]
    DIRECTION INPUT ;
    USE SIGNAL ;
    PORT
      LAYER M4 ;
        RECT  56.076 69.696 56.16 69.72 ;
    END
  END mv[69]
  PIN mv[6]
    DIRECTION INPUT ;
    USE SIGNAL ;
    PORT
      LAYER M4 ;
        RECT  56.076 63.168 56.16 63.192 ;
    END
  END mv[6]
  PIN mv[70]
    DIRECTION INPUT ;
    USE SIGNAL ;
    PORT
      LAYER M4 ;
        RECT  56.076 69.792 56.16 69.816 ;
    END
  END mv[70]
  PIN mv[71]
    DIRECTION INPUT ;
    USE SIGNAL ;
    PORT
      LAYER M4 ;
        RECT  56.076 69.888 56.16 69.912 ;
    END
  END mv[71]
  PIN mv[72]
    DIRECTION INPUT ;
    USE SIGNAL ;
    PORT
      LAYER M4 ;
        RECT  56.076 69.984 56.16 70.008 ;
    END
  END mv[72]
  PIN mv[73]
    DIRECTION INPUT ;
    USE SIGNAL ;
    PORT
      LAYER M4 ;
        RECT  56.076 70.128 56.16 70.152 ;
    END
  END mv[73]
  PIN mv[74]
    DIRECTION INPUT ;
    USE SIGNAL ;
    PORT
      LAYER M4 ;
        RECT  56.076 70.224 56.16 70.248 ;
    END
  END mv[74]
  PIN mv[75]
    DIRECTION INPUT ;
    USE SIGNAL ;
    PORT
      LAYER M4 ;
        RECT  56.076 70.32 56.16 70.344 ;
    END
  END mv[75]
  PIN mv[76]
    DIRECTION INPUT ;
    USE SIGNAL ;
    PORT
      LAYER M4 ;
        RECT  56.076 70.416 56.16 70.44 ;
    END
  END mv[76]
  PIN mv[77]
    DIRECTION INPUT ;
    USE SIGNAL ;
    PORT
      LAYER M4 ;
        RECT  56.076 70.512 56.16 70.536 ;
    END
  END mv[77]
  PIN mv[78]
    DIRECTION INPUT ;
    USE SIGNAL ;
    PORT
      LAYER M4 ;
        RECT  56.076 70.608 56.16 70.632 ;
    END
  END mv[78]
  PIN mv[79]
    DIRECTION INPUT ;
    USE SIGNAL ;
    PORT
      LAYER M4 ;
        RECT  56.076 70.752 56.16 70.776 ;
    END
  END mv[79]
  PIN mv[7]
    DIRECTION INPUT ;
    USE SIGNAL ;
    PORT
      LAYER M4 ;
        RECT  56.076 63.312 56.16 63.336 ;
    END
  END mv[7]
  PIN mv[80]
    DIRECTION INPUT ;
    USE SIGNAL ;
    PORT
      LAYER M4 ;
        RECT  56.076 70.848 56.16 70.872 ;
    END
  END mv[80]
  PIN mv[81]
    DIRECTION INPUT ;
    USE SIGNAL ;
    PORT
      LAYER M4 ;
        RECT  56.076 70.944 56.16 70.968 ;
    END
  END mv[81]
  PIN mv[82]
    DIRECTION INPUT ;
    USE SIGNAL ;
    PORT
      LAYER M4 ;
        RECT  56.076 71.04 56.16 71.064 ;
    END
  END mv[82]
  PIN mv[83]
    DIRECTION INPUT ;
    USE SIGNAL ;
    PORT
      LAYER M4 ;
        RECT  56.076 71.136 56.16 71.16 ;
    END
  END mv[83]
  PIN mv[84]
    DIRECTION INPUT ;
    USE SIGNAL ;
    PORT
      LAYER M4 ;
        RECT  56.076 71.232 56.16 71.256 ;
    END
  END mv[84]
  PIN mv[85]
    DIRECTION INPUT ;
    USE SIGNAL ;
    PORT
      LAYER M4 ;
        RECT  56.076 71.328 56.16 71.352 ;
    END
  END mv[85]
  PIN mv[86]
    DIRECTION INPUT ;
    USE SIGNAL ;
    PORT
      LAYER M4 ;
        RECT  56.076 71.472 56.16 71.496 ;
    END
  END mv[86]
  PIN mv[87]
    DIRECTION INPUT ;
    USE SIGNAL ;
    PORT
      LAYER M4 ;
        RECT  56.076 71.568 56.16 71.592 ;
    END
  END mv[87]
  PIN mv[88]
    DIRECTION INPUT ;
    USE SIGNAL ;
    PORT
      LAYER M4 ;
        RECT  56.076 71.664 56.16 71.688 ;
    END
  END mv[88]
  PIN mv[89]
    DIRECTION INPUT ;
    USE SIGNAL ;
    PORT
      LAYER M4 ;
        RECT  56.076 71.76 56.16 71.784 ;
    END
  END mv[89]
  PIN mv[8]
    DIRECTION INPUT ;
    USE SIGNAL ;
    PORT
      LAYER M4 ;
        RECT  56.076 63.408 56.16 63.432 ;
    END
  END mv[8]
  PIN mv[90]
    DIRECTION INPUT ;
    USE SIGNAL ;
    PORT
      LAYER M4 ;
        RECT  56.076 71.856 56.16 71.88 ;
    END
  END mv[90]
  PIN mv[91]
    DIRECTION INPUT ;
    USE SIGNAL ;
    PORT
      LAYER M4 ;
        RECT  56.076 71.952 56.16 71.976 ;
    END
  END mv[91]
  PIN mv[92]
    DIRECTION INPUT ;
    USE SIGNAL ;
    PORT
      LAYER M4 ;
        RECT  56.076 72.096 56.16 72.12 ;
    END
  END mv[92]
  PIN mv[93]
    DIRECTION INPUT ;
    USE SIGNAL ;
    PORT
      LAYER M4 ;
        RECT  56.076 72.192 56.16 72.216 ;
    END
  END mv[93]
  PIN mv[94]
    DIRECTION INPUT ;
    USE SIGNAL ;
    PORT
      LAYER M4 ;
        RECT  56.076 72.288 56.16 72.312 ;
    END
  END mv[94]
  PIN mv[95]
    DIRECTION INPUT ;
    USE SIGNAL ;
    PORT
      LAYER M4 ;
        RECT  56.076 72.384 56.16 72.408 ;
    END
  END mv[95]
  PIN mv[96]
    DIRECTION INPUT ;
    USE SIGNAL ;
    PORT
      LAYER M4 ;
        RECT  56.076 72.48 56.16 72.504 ;
    END
  END mv[96]
  PIN mv[97]
    DIRECTION INPUT ;
    USE SIGNAL ;
    PORT
      LAYER M4 ;
        RECT  56.076 72.576 56.16 72.6 ;
    END
  END mv[97]
  PIN mv[98]
    DIRECTION INPUT ;
    USE SIGNAL ;
    PORT
      LAYER M4 ;
        RECT  56.076 72.672 56.16 72.696 ;
    END
  END mv[98]
  PIN mv[99]
    DIRECTION INPUT ;
    USE SIGNAL ;
    PORT
      LAYER M4 ;
        RECT  56.076 72.816 56.16 72.84 ;
    END
  END mv[99]
  PIN mv[9]
    DIRECTION INPUT ;
    USE SIGNAL ;
    PORT
      LAYER M4 ;
        RECT  56.076 63.504 56.16 63.528 ;
    END
  END mv[9]
  PIN mv_done
    DIRECTION OUTPUT ;
    USE SIGNAL ;
    PORT
      LAYER M4 ;
        RECT  56.076 86.016 56.16 86.04 ;
    END
  END mv_done
  PIN mv_fault
    DIRECTION OUTPUT ;
    USE SIGNAL ;
    PORT
      LAYER M4 ;
        RECT  56.076 86.112 56.16 86.136 ;
    END
  END mv_fault
  PIN mv_rdy
    DIRECTION OUTPUT ;
    USE SIGNAL ;
    PORT
      LAYER M4 ;
        RECT  56.076 86.256 56.16 86.28 ;
    END
  END mv_rdy
  PIN mv_v
    DIRECTION INPUT ;
    USE SIGNAL ;
    PORT
      LAYER M4 ;
        RECT  56.076 86.352 56.16 86.376 ;
    END
  END mv_v
  PIN rst_n
    DIRECTION INPUT ;
    USE SIGNAL ;
    PORT
      LAYER M4 ;
        RECT  0 64.8 0.084 64.824 ;
    END
    PORT
      LAYER M4 ;
        RECT  0.06 64.8 0.137 64.824 ;
    END
  END rst_n
  PIN vmq[0]
    DIRECTION OUTPUT ;
    USE SIGNAL ;
    PORT
      LAYER M3 ;
        RECT  1.152 86.362 1.17 86.4 ;
    END
  END vmq[0]
  PIN vmq[100]
    DIRECTION OUTPUT ;
    USE SIGNAL ;
    PORT
      LAYER M3 ;
        RECT  17.136 86.362 17.154 86.4 ;
    END
  END vmq[100]
  PIN vmq[101]
    DIRECTION OUTPUT ;
    USE SIGNAL ;
    PORT
      LAYER M5 ;
        RECT  17.28 86.316 17.304 86.4 ;
    END
  END vmq[101]
  PIN vmq[102]
    DIRECTION OUTPUT ;
    USE SIGNAL ;
    PORT
      LAYER M3 ;
        RECT  17.46 86.362 17.478 86.4 ;
    END
  END vmq[102]
  PIN vmq[103]
    DIRECTION OUTPUT ;
    USE SIGNAL ;
    PORT
      LAYER M5 ;
        RECT  17.616 86.316 17.64 86.4 ;
    END
  END vmq[103]
  PIN vmq[104]
    DIRECTION OUTPUT ;
    USE SIGNAL ;
    PORT
      LAYER M3 ;
        RECT  17.784 86.362 17.802 86.4 ;
    END
  END vmq[104]
  PIN vmq[105]
    DIRECTION OUTPUT ;
    USE SIGNAL ;
    PORT
      LAYER M5 ;
        RECT  17.904 86.316 17.928 86.4 ;
    END
  END vmq[105]
  PIN vmq[106]
    DIRECTION OUTPUT ;
    USE SIGNAL ;
    PORT
      LAYER M3 ;
        RECT  18.072 86.362 18.09 86.4 ;
    END
  END vmq[106]
  PIN vmq[107]
    DIRECTION OUTPUT ;
    USE SIGNAL ;
    PORT
      LAYER M5 ;
        RECT  18.24 86.316 18.264 86.4 ;
    END
  END vmq[107]
  PIN vmq[108]
    DIRECTION OUTPUT ;
    USE SIGNAL ;
    PORT
      LAYER M3 ;
        RECT  18.396 86.362 18.414 86.4 ;
    END
  END vmq[108]
  PIN vmq[109]
    DIRECTION OUTPUT ;
    USE SIGNAL ;
    PORT
      LAYER M5 ;
        RECT  18.576 86.316 18.6 86.4 ;
    END
  END vmq[109]
  PIN vmq[10]
    DIRECTION OUTPUT ;
    USE SIGNAL ;
    PORT
      LAYER M3 ;
        RECT  2.736 86.362 2.754 86.4 ;
    END
  END vmq[10]
  PIN vmq[110]
    DIRECTION OUTPUT ;
    USE SIGNAL ;
    PORT
      LAYER M3 ;
        RECT  18.72 86.362 18.738 86.4 ;
    END
  END vmq[110]
  PIN vmq[111]
    DIRECTION OUTPUT ;
    USE SIGNAL ;
    PORT
      LAYER M5 ;
        RECT  18.864 86.316 18.888 86.4 ;
    END
  END vmq[111]
  PIN vmq[112]
    DIRECTION OUTPUT ;
    USE SIGNAL ;
    PORT
      LAYER M3 ;
        RECT  19.044 86.362 19.062 86.4 ;
    END
  END vmq[112]
  PIN vmq[113]
    DIRECTION OUTPUT ;
    USE SIGNAL ;
    PORT
      LAYER M5 ;
        RECT  19.2 86.316 19.224 86.4 ;
    END
  END vmq[113]
  PIN vmq[114]
    DIRECTION OUTPUT ;
    USE SIGNAL ;
    PORT
      LAYER M3 ;
        RECT  19.368 86.362 19.386 86.4 ;
    END
  END vmq[114]
  PIN vmq[115]
    DIRECTION OUTPUT ;
    USE SIGNAL ;
    PORT
      LAYER M5 ;
        RECT  19.536 86.316 19.56 86.4 ;
    END
  END vmq[115]
  PIN vmq[116]
    DIRECTION OUTPUT ;
    USE SIGNAL ;
    PORT
      LAYER M3 ;
        RECT  19.692 86.362 19.71 86.4 ;
    END
  END vmq[116]
  PIN vmq[117]
    DIRECTION OUTPUT ;
    USE SIGNAL ;
    PORT
      LAYER M5 ;
        RECT  19.824 86.316 19.848 86.4 ;
    END
  END vmq[117]
  PIN vmq[118]
    DIRECTION OUTPUT ;
    USE SIGNAL ;
    PORT
      LAYER M3 ;
        RECT  20.016 86.362 20.034 86.4 ;
    END
  END vmq[118]
  PIN vmq[119]
    DIRECTION OUTPUT ;
    USE SIGNAL ;
    PORT
      LAYER M5 ;
        RECT  20.16 86.316 20.184 86.4 ;
    END
  END vmq[119]
  PIN vmq[11]
    DIRECTION OUTPUT ;
    USE SIGNAL ;
    PORT
      LAYER M5 ;
        RECT  2.928 86.316 2.952 86.4 ;
    END
  END vmq[11]
  PIN vmq[120]
    DIRECTION OUTPUT ;
    USE SIGNAL ;
    PORT
      LAYER M3 ;
        RECT  20.34 86.362 20.358 86.4 ;
    END
  END vmq[120]
  PIN vmq[121]
    DIRECTION OUTPUT ;
    USE SIGNAL ;
    PORT
      LAYER M5 ;
        RECT  20.496 86.316 20.52 86.4 ;
    END
  END vmq[121]
  PIN vmq[122]
    DIRECTION OUTPUT ;
    USE SIGNAL ;
    PORT
      LAYER M3 ;
        RECT  20.628 86.362 20.646 86.4 ;
    END
  END vmq[122]
  PIN vmq[123]
    DIRECTION OUTPUT ;
    USE SIGNAL ;
    PORT
      LAYER M5 ;
        RECT  20.784 86.316 20.808 86.4 ;
    END
  END vmq[123]
  PIN vmq[124]
    DIRECTION OUTPUT ;
    USE SIGNAL ;
    PORT
      LAYER M3 ;
        RECT  20.952 86.362 20.97 86.4 ;
    END
  END vmq[124]
  PIN vmq[125]
    DIRECTION OUTPUT ;
    USE SIGNAL ;
    PORT
      LAYER M5 ;
        RECT  21.12 86.316 21.144 86.4 ;
    END
  END vmq[125]
  PIN vmq[126]
    DIRECTION OUTPUT ;
    USE SIGNAL ;
    PORT
      LAYER M3 ;
        RECT  21.276 86.362 21.294 86.4 ;
    END
  END vmq[126]
  PIN vmq[127]
    DIRECTION OUTPUT ;
    USE SIGNAL ;
    PORT
      LAYER M5 ;
        RECT  21.456 86.316 21.48 86.4 ;
    END
  END vmq[127]
  PIN vmq[128]
    DIRECTION OUTPUT ;
    USE SIGNAL ;
    PORT
      LAYER M3 ;
        RECT  21.6 86.362 21.618 86.4 ;
    END
  END vmq[128]
  PIN vmq[129]
    DIRECTION OUTPUT ;
    USE SIGNAL ;
    PORT
      LAYER M5 ;
        RECT  21.744 86.316 21.768 86.4 ;
    END
  END vmq[129]
  PIN vmq[12]
    DIRECTION OUTPUT ;
    USE SIGNAL ;
    PORT
      LAYER M3 ;
        RECT  3.06 86.362 3.078 86.4 ;
    END
  END vmq[12]
  PIN vmq[130]
    DIRECTION OUTPUT ;
    USE SIGNAL ;
    PORT
      LAYER M3 ;
        RECT  21.924 86.362 21.942 86.4 ;
    END
  END vmq[130]
  PIN vmq[131]
    DIRECTION OUTPUT ;
    USE SIGNAL ;
    PORT
      LAYER M5 ;
        RECT  22.08 86.316 22.104 86.4 ;
    END
  END vmq[131]
  PIN vmq[132]
    DIRECTION OUTPUT ;
    USE SIGNAL ;
    PORT
      LAYER M3 ;
        RECT  22.248 86.362 22.266 86.4 ;
    END
  END vmq[132]
  PIN vmq[133]
    DIRECTION OUTPUT ;
    USE SIGNAL ;
    PORT
      LAYER M5 ;
        RECT  22.416 86.316 22.44 86.4 ;
    END
  END vmq[133]
  PIN vmq[134]
    DIRECTION OUTPUT ;
    USE SIGNAL ;
    PORT
      LAYER M3 ;
        RECT  22.572 86.362 22.59 86.4 ;
    END
  END vmq[134]
  PIN vmq[135]
    DIRECTION OUTPUT ;
    USE SIGNAL ;
    PORT
      LAYER M5 ;
        RECT  22.704 86.316 22.728 86.4 ;
    END
  END vmq[135]
  PIN vmq[136]
    DIRECTION OUTPUT ;
    USE SIGNAL ;
    PORT
      LAYER M3 ;
        RECT  22.896 86.362 22.914 86.4 ;
    END
  END vmq[136]
  PIN vmq[137]
    DIRECTION OUTPUT ;
    USE SIGNAL ;
    PORT
      LAYER M5 ;
        RECT  23.04 86.316 23.064 86.4 ;
    END
  END vmq[137]
  PIN vmq[138]
    DIRECTION OUTPUT ;
    USE SIGNAL ;
    PORT
      LAYER M3 ;
        RECT  23.184 86.362 23.202 86.4 ;
    END
  END vmq[138]
  PIN vmq[139]
    DIRECTION OUTPUT ;
    USE SIGNAL ;
    PORT
      LAYER M5 ;
        RECT  23.376 86.316 23.4 86.4 ;
    END
  END vmq[139]
  PIN vmq[13]
    DIRECTION OUTPUT ;
    USE SIGNAL ;
    PORT
      LAYER M5 ;
        RECT  3.216 86.316 3.24 86.4 ;
    END
  END vmq[13]
  PIN vmq[140]
    DIRECTION OUTPUT ;
    USE SIGNAL ;
    PORT
      LAYER M3 ;
        RECT  23.508 86.362 23.526 86.4 ;
    END
  END vmq[140]
  PIN vmq[141]
    DIRECTION OUTPUT ;
    USE SIGNAL ;
    PORT
      LAYER M5 ;
        RECT  23.664 86.316 23.688 86.4 ;
    END
  END vmq[141]
  PIN vmq[142]
    DIRECTION OUTPUT ;
    USE SIGNAL ;
    PORT
      LAYER M3 ;
        RECT  23.832 86.362 23.85 86.4 ;
    END
  END vmq[142]
  PIN vmq[143]
    DIRECTION OUTPUT ;
    USE SIGNAL ;
    PORT
      LAYER M5 ;
        RECT  24 86.316 24.024 86.4 ;
    END
  END vmq[143]
  PIN vmq[144]
    DIRECTION OUTPUT ;
    USE SIGNAL ;
    PORT
      LAYER M3 ;
        RECT  24.156 86.362 24.174 86.4 ;
    END
  END vmq[144]
  PIN vmq[145]
    DIRECTION OUTPUT ;
    USE SIGNAL ;
    PORT
      LAYER M5 ;
        RECT  24.336 86.316 24.36 86.4 ;
    END
  END vmq[145]
  PIN vmq[146]
    DIRECTION OUTPUT ;
    USE SIGNAL ;
    PORT
      LAYER M3 ;
        RECT  24.48 86.362 24.498 86.4 ;
    END
  END vmq[146]
  PIN vmq[147]
    DIRECTION OUTPUT ;
    USE SIGNAL ;
    PORT
      LAYER M5 ;
        RECT  24.624 86.316 24.648 86.4 ;
    END
  END vmq[147]
  PIN vmq[148]
    DIRECTION OUTPUT ;
    USE SIGNAL ;
    PORT
      LAYER M3 ;
        RECT  24.804 86.362 24.822 86.4 ;
    END
  END vmq[148]
  PIN vmq[149]
    DIRECTION OUTPUT ;
    USE SIGNAL ;
    PORT
      LAYER M5 ;
        RECT  24.96 86.316 24.984 86.4 ;
    END
  END vmq[149]
  PIN vmq[14]
    DIRECTION OUTPUT ;
    USE SIGNAL ;
    PORT
      LAYER M3 ;
        RECT  3.384 86.362 3.402 86.4 ;
    END
  END vmq[14]
  PIN vmq[150]
    DIRECTION OUTPUT ;
    USE SIGNAL ;
    PORT
      LAYER M3 ;
        RECT  25.128 86.362 25.146 86.4 ;
    END
  END vmq[150]
  PIN vmq[151]
    DIRECTION OUTPUT ;
    USE SIGNAL ;
    PORT
      LAYER M5 ;
        RECT  25.296 86.316 25.32 86.4 ;
    END
  END vmq[151]
  PIN vmq[152]
    DIRECTION OUTPUT ;
    USE SIGNAL ;
    PORT
      LAYER M3 ;
        RECT  25.452 86.362 25.47 86.4 ;
    END
  END vmq[152]
  PIN vmq[153]
    DIRECTION OUTPUT ;
    USE SIGNAL ;
    PORT
      LAYER M5 ;
        RECT  25.584 86.316 25.608 86.4 ;
    END
  END vmq[153]
  PIN vmq[154]
    DIRECTION OUTPUT ;
    USE SIGNAL ;
    PORT
      LAYER M3 ;
        RECT  25.74 86.362 25.758 86.4 ;
    END
  END vmq[154]
  PIN vmq[155]
    DIRECTION OUTPUT ;
    USE SIGNAL ;
    PORT
      LAYER M5 ;
        RECT  25.92 86.316 25.944 86.4 ;
    END
  END vmq[155]
  PIN vmq[156]
    DIRECTION OUTPUT ;
    USE SIGNAL ;
    PORT
      LAYER M3 ;
        RECT  26.064 86.362 26.082 86.4 ;
    END
  END vmq[156]
  PIN vmq[157]
    DIRECTION OUTPUT ;
    USE SIGNAL ;
    PORT
      LAYER M5 ;
        RECT  26.208 86.316 26.232 86.4 ;
    END
  END vmq[157]
  PIN vmq[158]
    DIRECTION OUTPUT ;
    USE SIGNAL ;
    PORT
      LAYER M3 ;
        RECT  26.388 86.362 26.406 86.4 ;
    END
  END vmq[158]
  PIN vmq[159]
    DIRECTION OUTPUT ;
    USE SIGNAL ;
    PORT
      LAYER M5 ;
        RECT  26.544 86.316 26.568 86.4 ;
    END
  END vmq[159]
  PIN vmq[15]
    DIRECTION OUTPUT ;
    USE SIGNAL ;
    PORT
      LAYER M5 ;
        RECT  3.552 86.316 3.576 86.4 ;
    END
  END vmq[15]
  PIN vmq[160]
    DIRECTION OUTPUT ;
    USE SIGNAL ;
    PORT
      LAYER M3 ;
        RECT  26.712 86.362 26.73 86.4 ;
    END
  END vmq[160]
  PIN vmq[161]
    DIRECTION OUTPUT ;
    USE SIGNAL ;
    PORT
      LAYER M5 ;
        RECT  26.88 86.316 26.904 86.4 ;
    END
  END vmq[161]
  PIN vmq[162]
    DIRECTION OUTPUT ;
    USE SIGNAL ;
    PORT
      LAYER M3 ;
        RECT  27.036 86.362 27.054 86.4 ;
    END
  END vmq[162]
  PIN vmq[163]
    DIRECTION OUTPUT ;
    USE SIGNAL ;
    PORT
      LAYER M5 ;
        RECT  27.168 86.316 27.192 86.4 ;
    END
  END vmq[163]
  PIN vmq[164]
    DIRECTION OUTPUT ;
    USE SIGNAL ;
    PORT
      LAYER M3 ;
        RECT  27.36 86.362 27.378 86.4 ;
    END
  END vmq[164]
  PIN vmq[165]
    DIRECTION OUTPUT ;
    USE SIGNAL ;
    PORT
      LAYER M5 ;
        RECT  27.504 86.316 27.528 86.4 ;
    END
  END vmq[165]
  PIN vmq[166]
    DIRECTION OUTPUT ;
    USE SIGNAL ;
    PORT
      LAYER M3 ;
        RECT  27.684 86.362 27.702 86.4 ;
    END
  END vmq[166]
  PIN vmq[167]
    DIRECTION OUTPUT ;
    USE SIGNAL ;
    PORT
      LAYER M5 ;
        RECT  27.84 86.316 27.864 86.4 ;
    END
  END vmq[167]
  PIN vmq[168]
    DIRECTION OUTPUT ;
    USE SIGNAL ;
    PORT
      LAYER M3 ;
        RECT  28.008 86.362 28.026 86.4 ;
    END
  END vmq[168]
  PIN vmq[169]
    DIRECTION OUTPUT ;
    USE SIGNAL ;
    PORT
      LAYER M5 ;
        RECT  28.128 86.316 28.152 86.4 ;
    END
  END vmq[169]
  PIN vmq[16]
    DIRECTION OUTPUT ;
    USE SIGNAL ;
    PORT
      LAYER M3 ;
        RECT  3.708 86.362 3.726 86.4 ;
    END
  END vmq[16]
  PIN vmq[170]
    DIRECTION OUTPUT ;
    USE SIGNAL ;
    PORT
      LAYER M3 ;
        RECT  28.296 86.362 28.314 86.4 ;
    END
  END vmq[170]
  PIN vmq[171]
    DIRECTION OUTPUT ;
    USE SIGNAL ;
    PORT
      LAYER M5 ;
        RECT  28.464 86.316 28.488 86.4 ;
    END
  END vmq[171]
  PIN vmq[172]
    DIRECTION OUTPUT ;
    USE SIGNAL ;
    PORT
      LAYER M3 ;
        RECT  28.62 86.362 28.638 86.4 ;
    END
  END vmq[172]
  PIN vmq[173]
    DIRECTION OUTPUT ;
    USE SIGNAL ;
    PORT
      LAYER M5 ;
        RECT  28.8 86.316 28.824 86.4 ;
    END
  END vmq[173]
  PIN vmq[174]
    DIRECTION OUTPUT ;
    USE SIGNAL ;
    PORT
      LAYER M3 ;
        RECT  28.944 86.362 28.962 86.4 ;
    END
  END vmq[174]
  PIN vmq[175]
    DIRECTION OUTPUT ;
    USE SIGNAL ;
    PORT
      LAYER M5 ;
        RECT  29.088 86.316 29.112 86.4 ;
    END
  END vmq[175]
  PIN vmq[176]
    DIRECTION OUTPUT ;
    USE SIGNAL ;
    PORT
      LAYER M3 ;
        RECT  29.268 86.362 29.286 86.4 ;
    END
  END vmq[176]
  PIN vmq[177]
    DIRECTION OUTPUT ;
    USE SIGNAL ;
    PORT
      LAYER M5 ;
        RECT  29.424 86.316 29.448 86.4 ;
    END
  END vmq[177]
  PIN vmq[178]
    DIRECTION OUTPUT ;
    USE SIGNAL ;
    PORT
      LAYER M3 ;
        RECT  29.592 86.362 29.61 86.4 ;
    END
  END vmq[178]
  PIN vmq[179]
    DIRECTION OUTPUT ;
    USE SIGNAL ;
    PORT
      LAYER M5 ;
        RECT  29.76 86.316 29.784 86.4 ;
    END
  END vmq[179]
  PIN vmq[17]
    DIRECTION OUTPUT ;
    USE SIGNAL ;
    PORT
      LAYER M5 ;
        RECT  3.888 86.316 3.912 86.4 ;
    END
  END vmq[17]
  PIN vmq[180]
    DIRECTION OUTPUT ;
    USE SIGNAL ;
    PORT
      LAYER M3 ;
        RECT  29.916 86.362 29.934 86.4 ;
    END
  END vmq[180]
  PIN vmq[181]
    DIRECTION OUTPUT ;
    USE SIGNAL ;
    PORT
      LAYER M5 ;
        RECT  30.048 86.316 30.072 86.4 ;
    END
  END vmq[181]
  PIN vmq[182]
    DIRECTION OUTPUT ;
    USE SIGNAL ;
    PORT
      LAYER M3 ;
        RECT  30.24 86.362 30.258 86.4 ;
    END
  END vmq[182]
  PIN vmq[183]
    DIRECTION OUTPUT ;
    USE SIGNAL ;
    PORT
      LAYER M5 ;
        RECT  30.384 86.316 30.408 86.4 ;
    END
  END vmq[183]
  PIN vmq[184]
    DIRECTION OUTPUT ;
    USE SIGNAL ;
    PORT
      LAYER M3 ;
        RECT  30.564 86.362 30.582 86.4 ;
    END
  END vmq[184]
  PIN vmq[185]
    DIRECTION OUTPUT ;
    USE SIGNAL ;
    PORT
      LAYER M5 ;
        RECT  30.72 86.316 30.744 86.4 ;
    END
  END vmq[185]
  PIN vmq[186]
    DIRECTION OUTPUT ;
    USE SIGNAL ;
    PORT
      LAYER M3 ;
        RECT  30.852 86.362 30.87 86.4 ;
    END
  END vmq[186]
  PIN vmq[187]
    DIRECTION OUTPUT ;
    USE SIGNAL ;
    PORT
      LAYER M5 ;
        RECT  31.008 86.316 31.032 86.4 ;
    END
  END vmq[187]
  PIN vmq[188]
    DIRECTION OUTPUT ;
    USE SIGNAL ;
    PORT
      LAYER M3 ;
        RECT  31.176 86.362 31.194 86.4 ;
    END
  END vmq[188]
  PIN vmq[189]
    DIRECTION OUTPUT ;
    USE SIGNAL ;
    PORT
      LAYER M5 ;
        RECT  31.344 86.316 31.368 86.4 ;
    END
  END vmq[189]
  PIN vmq[18]
    DIRECTION OUTPUT ;
    USE SIGNAL ;
    PORT
      LAYER M3 ;
        RECT  4.032 86.362 4.05 86.4 ;
    END
  END vmq[18]
  PIN vmq[190]
    DIRECTION OUTPUT ;
    USE SIGNAL ;
    PORT
      LAYER M3 ;
        RECT  31.5 86.362 31.518 86.4 ;
    END
  END vmq[190]
  PIN vmq[191]
    DIRECTION OUTPUT ;
    USE SIGNAL ;
    PORT
      LAYER M5 ;
        RECT  31.68 86.316 31.704 86.4 ;
    END
  END vmq[191]
  PIN vmq[192]
    DIRECTION OUTPUT ;
    USE SIGNAL ;
    PORT
      LAYER M3 ;
        RECT  31.824 86.362 31.842 86.4 ;
    END
  END vmq[192]
  PIN vmq[193]
    DIRECTION OUTPUT ;
    USE SIGNAL ;
    PORT
      LAYER M5 ;
        RECT  31.968 86.316 31.992 86.4 ;
    END
  END vmq[193]
  PIN vmq[194]
    DIRECTION OUTPUT ;
    USE SIGNAL ;
    PORT
      LAYER M3 ;
        RECT  32.148 86.362 32.166 86.4 ;
    END
  END vmq[194]
  PIN vmq[195]
    DIRECTION OUTPUT ;
    USE SIGNAL ;
    PORT
      LAYER M5 ;
        RECT  32.304 86.316 32.328 86.4 ;
    END
  END vmq[195]
  PIN vmq[196]
    DIRECTION OUTPUT ;
    USE SIGNAL ;
    PORT
      LAYER M3 ;
        RECT  32.472 86.362 32.49 86.4 ;
    END
  END vmq[196]
  PIN vmq[197]
    DIRECTION OUTPUT ;
    USE SIGNAL ;
    PORT
      LAYER M5 ;
        RECT  32.64 86.316 32.664 86.4 ;
    END
  END vmq[197]
  PIN vmq[198]
    DIRECTION OUTPUT ;
    USE SIGNAL ;
    PORT
      LAYER M3 ;
        RECT  32.796 86.362 32.814 86.4 ;
    END
  END vmq[198]
  PIN vmq[199]
    DIRECTION OUTPUT ;
    USE SIGNAL ;
    PORT
      LAYER M5 ;
        RECT  32.928 86.316 32.952 86.4 ;
    END
  END vmq[199]
  PIN vmq[19]
    DIRECTION OUTPUT ;
    USE SIGNAL ;
    PORT
      LAYER M5 ;
        RECT  4.176 86.316 4.2 86.4 ;
    END
  END vmq[19]
  PIN vmq[1]
    DIRECTION OUTPUT ;
    USE SIGNAL ;
    PORT
      LAYER M5 ;
        RECT  1.296 86.316 1.32 86.4 ;
    END
  END vmq[1]
  PIN vmq[200]
    DIRECTION OUTPUT ;
    USE SIGNAL ;
    PORT
      LAYER M3 ;
        RECT  33.12 86.362 33.138 86.4 ;
    END
  END vmq[200]
  PIN vmq[201]
    DIRECTION OUTPUT ;
    USE SIGNAL ;
    PORT
      LAYER M5 ;
        RECT  33.264 86.316 33.288 86.4 ;
    END
  END vmq[201]
  PIN vmq[202]
    DIRECTION OUTPUT ;
    USE SIGNAL ;
    PORT
      LAYER M3 ;
        RECT  33.408 86.362 33.426 86.4 ;
    END
  END vmq[202]
  PIN vmq[203]
    DIRECTION OUTPUT ;
    USE SIGNAL ;
    PORT
      LAYER M5 ;
        RECT  33.6 86.316 33.624 86.4 ;
    END
  END vmq[203]
  PIN vmq[204]
    DIRECTION OUTPUT ;
    USE SIGNAL ;
    PORT
      LAYER M3 ;
        RECT  33.732 86.362 33.75 86.4 ;
    END
  END vmq[204]
  PIN vmq[205]
    DIRECTION OUTPUT ;
    USE SIGNAL ;
    PORT
      LAYER M5 ;
        RECT  33.888 86.316 33.912 86.4 ;
    END
  END vmq[205]
  PIN vmq[206]
    DIRECTION OUTPUT ;
    USE SIGNAL ;
    PORT
      LAYER M3 ;
        RECT  34.056 86.362 34.074 86.4 ;
    END
  END vmq[206]
  PIN vmq[207]
    DIRECTION OUTPUT ;
    USE SIGNAL ;
    PORT
      LAYER M5 ;
        RECT  34.224 86.316 34.248 86.4 ;
    END
  END vmq[207]
  PIN vmq[208]
    DIRECTION OUTPUT ;
    USE SIGNAL ;
    PORT
      LAYER M3 ;
        RECT  34.38 86.362 34.398 86.4 ;
    END
  END vmq[208]
  PIN vmq[209]
    DIRECTION OUTPUT ;
    USE SIGNAL ;
    PORT
      LAYER M5 ;
        RECT  34.56 86.316 34.584 86.4 ;
    END
  END vmq[209]
  PIN vmq[20]
    DIRECTION OUTPUT ;
    USE SIGNAL ;
    PORT
      LAYER M3 ;
        RECT  4.356 86.362 4.374 86.4 ;
    END
  END vmq[20]
  PIN vmq[210]
    DIRECTION OUTPUT ;
    USE SIGNAL ;
    PORT
      LAYER M3 ;
        RECT  34.704 86.362 34.722 86.4 ;
    END
  END vmq[210]
  PIN vmq[211]
    DIRECTION OUTPUT ;
    USE SIGNAL ;
    PORT
      LAYER M5 ;
        RECT  34.848 86.316 34.872 86.4 ;
    END
  END vmq[211]
  PIN vmq[212]
    DIRECTION OUTPUT ;
    USE SIGNAL ;
    PORT
      LAYER M3 ;
        RECT  35.028 86.362 35.046 86.4 ;
    END
  END vmq[212]
  PIN vmq[213]
    DIRECTION OUTPUT ;
    USE SIGNAL ;
    PORT
      LAYER M5 ;
        RECT  35.184 86.316 35.208 86.4 ;
    END
  END vmq[213]
  PIN vmq[214]
    DIRECTION OUTPUT ;
    USE SIGNAL ;
    PORT
      LAYER M3 ;
        RECT  35.352 86.362 35.37 86.4 ;
    END
  END vmq[214]
  PIN vmq[215]
    DIRECTION OUTPUT ;
    USE SIGNAL ;
    PORT
      LAYER M5 ;
        RECT  35.52 86.316 35.544 86.4 ;
    END
  END vmq[215]
  PIN vmq[216]
    DIRECTION OUTPUT ;
    USE SIGNAL ;
    PORT
      LAYER M3 ;
        RECT  35.676 86.362 35.694 86.4 ;
    END
  END vmq[216]
  PIN vmq[217]
    DIRECTION OUTPUT ;
    USE SIGNAL ;
    PORT
      LAYER M5 ;
        RECT  35.808 86.316 35.832 86.4 ;
    END
  END vmq[217]
  PIN vmq[218]
    DIRECTION OUTPUT ;
    USE SIGNAL ;
    PORT
      LAYER M3 ;
        RECT  35.964 86.362 35.982 86.4 ;
    END
  END vmq[218]
  PIN vmq[219]
    DIRECTION OUTPUT ;
    USE SIGNAL ;
    PORT
      LAYER M5 ;
        RECT  36.144 86.316 36.168 86.4 ;
    END
  END vmq[219]
  PIN vmq[21]
    DIRECTION OUTPUT ;
    USE SIGNAL ;
    PORT
      LAYER M5 ;
        RECT  4.512 86.316 4.536 86.4 ;
    END
  END vmq[21]
  PIN vmq[220]
    DIRECTION OUTPUT ;
    USE SIGNAL ;
    PORT
      LAYER M3 ;
        RECT  36.288 86.362 36.306 86.4 ;
    END
  END vmq[220]
  PIN vmq[221]
    DIRECTION OUTPUT ;
    USE SIGNAL ;
    PORT
      LAYER M5 ;
        RECT  36.48 86.316 36.504 86.4 ;
    END
  END vmq[221]
  PIN vmq[222]
    DIRECTION OUTPUT ;
    USE SIGNAL ;
    PORT
      LAYER M3 ;
        RECT  36.612 86.362 36.63 86.4 ;
    END
  END vmq[222]
  PIN vmq[223]
    DIRECTION OUTPUT ;
    USE SIGNAL ;
    PORT
      LAYER M5 ;
        RECT  36.768 86.316 36.792 86.4 ;
    END
  END vmq[223]
  PIN vmq[224]
    DIRECTION OUTPUT ;
    USE SIGNAL ;
    PORT
      LAYER M3 ;
        RECT  36.936 86.362 36.954 86.4 ;
    END
  END vmq[224]
  PIN vmq[225]
    DIRECTION OUTPUT ;
    USE SIGNAL ;
    PORT
      LAYER M5 ;
        RECT  37.104 86.316 37.128 86.4 ;
    END
  END vmq[225]
  PIN vmq[226]
    DIRECTION OUTPUT ;
    USE SIGNAL ;
    PORT
      LAYER M3 ;
        RECT  37.26 86.362 37.278 86.4 ;
    END
  END vmq[226]
  PIN vmq[227]
    DIRECTION OUTPUT ;
    USE SIGNAL ;
    PORT
      LAYER M5 ;
        RECT  37.392 86.316 37.416 86.4 ;
    END
  END vmq[227]
  PIN vmq[228]
    DIRECTION OUTPUT ;
    USE SIGNAL ;
    PORT
      LAYER M3 ;
        RECT  37.584 86.362 37.602 86.4 ;
    END
  END vmq[228]
  PIN vmq[229]
    DIRECTION OUTPUT ;
    USE SIGNAL ;
    PORT
      LAYER M5 ;
        RECT  37.728 86.316 37.752 86.4 ;
    END
  END vmq[229]
  PIN vmq[22]
    DIRECTION OUTPUT ;
    USE SIGNAL ;
    PORT
      LAYER M3 ;
        RECT  4.68 86.362 4.698 86.4 ;
    END
  END vmq[22]
  PIN vmq[230]
    DIRECTION OUTPUT ;
    USE SIGNAL ;
    PORT
      LAYER M3 ;
        RECT  37.908 86.362 37.926 86.4 ;
    END
  END vmq[230]
  PIN vmq[231]
    DIRECTION OUTPUT ;
    USE SIGNAL ;
    PORT
      LAYER M5 ;
        RECT  38.064 86.316 38.088 86.4 ;
    END
  END vmq[231]
  PIN vmq[232]
    DIRECTION OUTPUT ;
    USE SIGNAL ;
    PORT
      LAYER M3 ;
        RECT  38.232 86.362 38.25 86.4 ;
    END
  END vmq[232]
  PIN vmq[233]
    DIRECTION OUTPUT ;
    USE SIGNAL ;
    PORT
      LAYER M5 ;
        RECT  38.352 86.316 38.376 86.4 ;
    END
  END vmq[233]
  PIN vmq[234]
    DIRECTION OUTPUT ;
    USE SIGNAL ;
    PORT
      LAYER M3 ;
        RECT  38.52 86.362 38.538 86.4 ;
    END
  END vmq[234]
  PIN vmq[235]
    DIRECTION OUTPUT ;
    USE SIGNAL ;
    PORT
      LAYER M5 ;
        RECT  38.688 86.316 38.712 86.4 ;
    END
  END vmq[235]
  PIN vmq[236]
    DIRECTION OUTPUT ;
    USE SIGNAL ;
    PORT
      LAYER M3 ;
        RECT  38.844 86.362 38.862 86.4 ;
    END
  END vmq[236]
  PIN vmq[237]
    DIRECTION OUTPUT ;
    USE SIGNAL ;
    PORT
      LAYER M5 ;
        RECT  39.024 86.316 39.048 86.4 ;
    END
  END vmq[237]
  PIN vmq[238]
    DIRECTION OUTPUT ;
    USE SIGNAL ;
    PORT
      LAYER M3 ;
        RECT  39.168 86.362 39.186 86.4 ;
    END
  END vmq[238]
  PIN vmq[239]
    DIRECTION OUTPUT ;
    USE SIGNAL ;
    PORT
      LAYER M5 ;
        RECT  39.312 86.316 39.336 86.4 ;
    END
  END vmq[239]
  PIN vmq[23]
    DIRECTION OUTPUT ;
    USE SIGNAL ;
    PORT
      LAYER M5 ;
        RECT  4.8 86.316 4.824 86.4 ;
    END
  END vmq[23]
  PIN vmq[240]
    DIRECTION OUTPUT ;
    USE SIGNAL ;
    PORT
      LAYER M3 ;
        RECT  39.492 86.362 39.51 86.4 ;
    END
  END vmq[240]
  PIN vmq[241]
    DIRECTION OUTPUT ;
    USE SIGNAL ;
    PORT
      LAYER M5 ;
        RECT  39.648 86.316 39.672 86.4 ;
    END
  END vmq[241]
  PIN vmq[242]
    DIRECTION OUTPUT ;
    USE SIGNAL ;
    PORT
      LAYER M3 ;
        RECT  39.816 86.362 39.834 86.4 ;
    END
  END vmq[242]
  PIN vmq[243]
    DIRECTION OUTPUT ;
    USE SIGNAL ;
    PORT
      LAYER M5 ;
        RECT  39.984 86.316 40.008 86.4 ;
    END
  END vmq[243]
  PIN vmq[244]
    DIRECTION OUTPUT ;
    USE SIGNAL ;
    PORT
      LAYER M3 ;
        RECT  40.14 86.362 40.158 86.4 ;
    END
  END vmq[244]
  PIN vmq[245]
    DIRECTION OUTPUT ;
    USE SIGNAL ;
    PORT
      LAYER M5 ;
        RECT  40.272 86.316 40.296 86.4 ;
    END
  END vmq[245]
  PIN vmq[246]
    DIRECTION OUTPUT ;
    USE SIGNAL ;
    PORT
      LAYER M3 ;
        RECT  40.464 86.362 40.482 86.4 ;
    END
  END vmq[246]
  PIN vmq[247]
    DIRECTION OUTPUT ;
    USE SIGNAL ;
    PORT
      LAYER M5 ;
        RECT  40.608 86.316 40.632 86.4 ;
    END
  END vmq[247]
  PIN vmq[248]
    DIRECTION OUTPUT ;
    USE SIGNAL ;
    PORT
      LAYER M3 ;
        RECT  40.788 86.362 40.806 86.4 ;
    END
  END vmq[248]
  PIN vmq[249]
    DIRECTION OUTPUT ;
    USE SIGNAL ;
    PORT
      LAYER M5 ;
        RECT  40.944 86.316 40.968 86.4 ;
    END
  END vmq[249]
  PIN vmq[24]
    DIRECTION OUTPUT ;
    USE SIGNAL ;
    PORT
      LAYER M3 ;
        RECT  4.968 86.362 4.986 86.4 ;
    END
  END vmq[24]
  PIN vmq[250]
    DIRECTION OUTPUT ;
    USE SIGNAL ;
    PORT
      LAYER M3 ;
        RECT  41.076 86.362 41.094 86.4 ;
    END
  END vmq[250]
  PIN vmq[251]
    DIRECTION OUTPUT ;
    USE SIGNAL ;
    PORT
      LAYER M5 ;
        RECT  41.232 86.316 41.256 86.4 ;
    END
  END vmq[251]
  PIN vmq[252]
    DIRECTION OUTPUT ;
    USE SIGNAL ;
    PORT
      LAYER M3 ;
        RECT  41.4 86.362 41.418 86.4 ;
    END
  END vmq[252]
  PIN vmq[253]
    DIRECTION OUTPUT ;
    USE SIGNAL ;
    PORT
      LAYER M5 ;
        RECT  41.568 86.316 41.592 86.4 ;
    END
  END vmq[253]
  PIN vmq[254]
    DIRECTION OUTPUT ;
    USE SIGNAL ;
    PORT
      LAYER M3 ;
        RECT  41.724 86.362 41.742 86.4 ;
    END
  END vmq[254]
  PIN vmq[255]
    DIRECTION OUTPUT ;
    USE SIGNAL ;
    PORT
      LAYER M5 ;
        RECT  41.904 86.316 41.928 86.4 ;
    END
  END vmq[255]
  PIN vmq[256]
    DIRECTION OUTPUT ;
    USE SIGNAL ;
    PORT
      LAYER M3 ;
        RECT  42.048 86.362 42.066 86.4 ;
    END
  END vmq[256]
  PIN vmq[257]
    DIRECTION OUTPUT ;
    USE SIGNAL ;
    PORT
      LAYER M5 ;
        RECT  42.192 86.316 42.216 86.4 ;
    END
  END vmq[257]
  PIN vmq[258]
    DIRECTION OUTPUT ;
    USE SIGNAL ;
    PORT
      LAYER M3 ;
        RECT  42.372 86.362 42.39 86.4 ;
    END
  END vmq[258]
  PIN vmq[259]
    DIRECTION OUTPUT ;
    USE SIGNAL ;
    PORT
      LAYER M5 ;
        RECT  42.528 86.316 42.552 86.4 ;
    END
  END vmq[259]
  PIN vmq[25]
    DIRECTION OUTPUT ;
    USE SIGNAL ;
    PORT
      LAYER M5 ;
        RECT  5.136 86.316 5.16 86.4 ;
    END
  END vmq[25]
  PIN vmq[260]
    DIRECTION OUTPUT ;
    USE SIGNAL ;
    PORT
      LAYER M3 ;
        RECT  42.696 86.362 42.714 86.4 ;
    END
  END vmq[260]
  PIN vmq[261]
    DIRECTION OUTPUT ;
    USE SIGNAL ;
    PORT
      LAYER M5 ;
        RECT  42.864 86.316 42.888 86.4 ;
    END
  END vmq[261]
  PIN vmq[262]
    DIRECTION OUTPUT ;
    USE SIGNAL ;
    PORT
      LAYER M3 ;
        RECT  43.02 86.362 43.038 86.4 ;
    END
  END vmq[262]
  PIN vmq[263]
    DIRECTION OUTPUT ;
    USE SIGNAL ;
    PORT
      LAYER M5 ;
        RECT  43.152 86.316 43.176 86.4 ;
    END
  END vmq[263]
  PIN vmq[264]
    DIRECTION OUTPUT ;
    USE SIGNAL ;
    PORT
      LAYER M3 ;
        RECT  43.344 86.362 43.362 86.4 ;
    END
  END vmq[264]
  PIN vmq[265]
    DIRECTION OUTPUT ;
    USE SIGNAL ;
    PORT
      LAYER M5 ;
        RECT  43.488 86.316 43.512 86.4 ;
    END
  END vmq[265]
  PIN vmq[266]
    DIRECTION OUTPUT ;
    USE SIGNAL ;
    PORT
      LAYER M3 ;
        RECT  43.632 86.362 43.65 86.4 ;
    END
  END vmq[266]
  PIN vmq[267]
    DIRECTION OUTPUT ;
    USE SIGNAL ;
    PORT
      LAYER M5 ;
        RECT  43.824 86.316 43.848 86.4 ;
    END
  END vmq[267]
  PIN vmq[268]
    DIRECTION OUTPUT ;
    USE SIGNAL ;
    PORT
      LAYER M3 ;
        RECT  43.956 86.362 43.974 86.4 ;
    END
  END vmq[268]
  PIN vmq[269]
    DIRECTION OUTPUT ;
    USE SIGNAL ;
    PORT
      LAYER M5 ;
        RECT  44.112 86.316 44.136 86.4 ;
    END
  END vmq[269]
  PIN vmq[26]
    DIRECTION OUTPUT ;
    USE SIGNAL ;
    PORT
      LAYER M3 ;
        RECT  5.292 86.362 5.31 86.4 ;
    END
  END vmq[26]
  PIN vmq[270]
    DIRECTION OUTPUT ;
    USE SIGNAL ;
    PORT
      LAYER M3 ;
        RECT  44.28 86.362 44.298 86.4 ;
    END
  END vmq[270]
  PIN vmq[271]
    DIRECTION OUTPUT ;
    USE SIGNAL ;
    PORT
      LAYER M5 ;
        RECT  44.448 86.316 44.472 86.4 ;
    END
  END vmq[271]
  PIN vmq[272]
    DIRECTION OUTPUT ;
    USE SIGNAL ;
    PORT
      LAYER M3 ;
        RECT  44.604 86.362 44.622 86.4 ;
    END
  END vmq[272]
  PIN vmq[273]
    DIRECTION OUTPUT ;
    USE SIGNAL ;
    PORT
      LAYER M5 ;
        RECT  44.784 86.316 44.808 86.4 ;
    END
  END vmq[273]
  PIN vmq[274]
    DIRECTION OUTPUT ;
    USE SIGNAL ;
    PORT
      LAYER M3 ;
        RECT  44.928 86.362 44.946 86.4 ;
    END
  END vmq[274]
  PIN vmq[275]
    DIRECTION OUTPUT ;
    USE SIGNAL ;
    PORT
      LAYER M5 ;
        RECT  45.072 86.316 45.096 86.4 ;
    END
  END vmq[275]
  PIN vmq[276]
    DIRECTION OUTPUT ;
    USE SIGNAL ;
    PORT
      LAYER M3 ;
        RECT  45.252 86.362 45.27 86.4 ;
    END
  END vmq[276]
  PIN vmq[277]
    DIRECTION OUTPUT ;
    USE SIGNAL ;
    PORT
      LAYER M5 ;
        RECT  45.408 86.316 45.432 86.4 ;
    END
  END vmq[277]
  PIN vmq[278]
    DIRECTION OUTPUT ;
    USE SIGNAL ;
    PORT
      LAYER M3 ;
        RECT  45.576 86.362 45.594 86.4 ;
    END
  END vmq[278]
  PIN vmq[279]
    DIRECTION OUTPUT ;
    USE SIGNAL ;
    PORT
      LAYER M5 ;
        RECT  45.744 86.316 45.768 86.4 ;
    END
  END vmq[279]
  PIN vmq[27]
    DIRECTION OUTPUT ;
    USE SIGNAL ;
    PORT
      LAYER M5 ;
        RECT  5.472 86.316 5.496 86.4 ;
    END
  END vmq[27]
  PIN vmq[280]
    DIRECTION OUTPUT ;
    USE SIGNAL ;
    PORT
      LAYER M3 ;
        RECT  45.9 86.362 45.918 86.4 ;
    END
  END vmq[280]
  PIN vmq[281]
    DIRECTION OUTPUT ;
    USE SIGNAL ;
    PORT
      LAYER M5 ;
        RECT  46.032 86.316 46.056 86.4 ;
    END
  END vmq[281]
  PIN vmq[282]
    DIRECTION OUTPUT ;
    USE SIGNAL ;
    PORT
      LAYER M3 ;
        RECT  46.188 86.362 46.206 86.4 ;
    END
  END vmq[282]
  PIN vmq[283]
    DIRECTION OUTPUT ;
    USE SIGNAL ;
    PORT
      LAYER M5 ;
        RECT  46.368 86.316 46.392 86.4 ;
    END
  END vmq[283]
  PIN vmq[284]
    DIRECTION OUTPUT ;
    USE SIGNAL ;
    PORT
      LAYER M3 ;
        RECT  46.512 86.362 46.53 86.4 ;
    END
  END vmq[284]
  PIN vmq[285]
    DIRECTION OUTPUT ;
    USE SIGNAL ;
    PORT
      LAYER M5 ;
        RECT  46.704 86.316 46.728 86.4 ;
    END
  END vmq[285]
  PIN vmq[286]
    DIRECTION OUTPUT ;
    USE SIGNAL ;
    PORT
      LAYER M3 ;
        RECT  46.836 86.362 46.854 86.4 ;
    END
  END vmq[286]
  PIN vmq[287]
    DIRECTION OUTPUT ;
    USE SIGNAL ;
    PORT
      LAYER M5 ;
        RECT  46.992 86.316 47.016 86.4 ;
    END
  END vmq[287]
  PIN vmq[288]
    DIRECTION OUTPUT ;
    USE SIGNAL ;
    PORT
      LAYER M3 ;
        RECT  47.16 86.362 47.178 86.4 ;
    END
  END vmq[288]
  PIN vmq[289]
    DIRECTION OUTPUT ;
    USE SIGNAL ;
    PORT
      LAYER M5 ;
        RECT  47.328 86.316 47.352 86.4 ;
    END
  END vmq[289]
  PIN vmq[28]
    DIRECTION OUTPUT ;
    USE SIGNAL ;
    PORT
      LAYER M3 ;
        RECT  5.616 86.362 5.634 86.4 ;
    END
  END vmq[28]
  PIN vmq[290]
    DIRECTION OUTPUT ;
    USE SIGNAL ;
    PORT
      LAYER M3 ;
        RECT  47.484 86.362 47.502 86.4 ;
    END
  END vmq[290]
  PIN vmq[291]
    DIRECTION OUTPUT ;
    USE SIGNAL ;
    PORT
      LAYER M5 ;
        RECT  47.616 86.316 47.64 86.4 ;
    END
  END vmq[291]
  PIN vmq[292]
    DIRECTION OUTPUT ;
    USE SIGNAL ;
    PORT
      LAYER M3 ;
        RECT  47.808 86.362 47.826 86.4 ;
    END
  END vmq[292]
  PIN vmq[293]
    DIRECTION OUTPUT ;
    USE SIGNAL ;
    PORT
      LAYER M5 ;
        RECT  47.952 86.316 47.976 86.4 ;
    END
  END vmq[293]
  PIN vmq[294]
    DIRECTION OUTPUT ;
    USE SIGNAL ;
    PORT
      LAYER M3 ;
        RECT  48.132 86.362 48.15 86.4 ;
    END
  END vmq[294]
  PIN vmq[295]
    DIRECTION OUTPUT ;
    USE SIGNAL ;
    PORT
      LAYER M5 ;
        RECT  48.288 86.316 48.312 86.4 ;
    END
  END vmq[295]
  PIN vmq[296]
    DIRECTION OUTPUT ;
    USE SIGNAL ;
    PORT
      LAYER M3 ;
        RECT  48.456 86.362 48.474 86.4 ;
    END
  END vmq[296]
  PIN vmq[297]
    DIRECTION OUTPUT ;
    USE SIGNAL ;
    PORT
      LAYER M5 ;
        RECT  48.576 86.316 48.6 86.4 ;
    END
  END vmq[297]
  PIN vmq[298]
    DIRECTION OUTPUT ;
    USE SIGNAL ;
    PORT
      LAYER M3 ;
        RECT  48.744 86.362 48.762 86.4 ;
    END
  END vmq[298]
  PIN vmq[299]
    DIRECTION OUTPUT ;
    USE SIGNAL ;
    PORT
      LAYER M5 ;
        RECT  48.912 86.316 48.936 86.4 ;
    END
  END vmq[299]
  PIN vmq[29]
    DIRECTION OUTPUT ;
    USE SIGNAL ;
    PORT
      LAYER M5 ;
        RECT  5.76 86.316 5.784 86.4 ;
    END
  END vmq[29]
  PIN vmq[2]
    DIRECTION OUTPUT ;
    USE SIGNAL ;
    PORT
      LAYER M3 ;
        RECT  1.476 86.362 1.494 86.4 ;
    END
  END vmq[2]
  PIN vmq[300]
    DIRECTION OUTPUT ;
    USE SIGNAL ;
    PORT
      LAYER M3 ;
        RECT  49.068 86.362 49.086 86.4 ;
    END
  END vmq[300]
  PIN vmq[301]
    DIRECTION OUTPUT ;
    USE SIGNAL ;
    PORT
      LAYER M5 ;
        RECT  49.248 86.316 49.272 86.4 ;
    END
  END vmq[301]
  PIN vmq[302]
    DIRECTION OUTPUT ;
    USE SIGNAL ;
    PORT
      LAYER M3 ;
        RECT  49.392 86.362 49.41 86.4 ;
    END
  END vmq[302]
  PIN vmq[303]
    DIRECTION OUTPUT ;
    USE SIGNAL ;
    PORT
      LAYER M5 ;
        RECT  49.536 86.316 49.56 86.4 ;
    END
  END vmq[303]
  PIN vmq[304]
    DIRECTION OUTPUT ;
    USE SIGNAL ;
    PORT
      LAYER M3 ;
        RECT  49.716 86.362 49.734 86.4 ;
    END
  END vmq[304]
  PIN vmq[305]
    DIRECTION OUTPUT ;
    USE SIGNAL ;
    PORT
      LAYER M5 ;
        RECT  49.872 86.316 49.896 86.4 ;
    END
  END vmq[305]
  PIN vmq[306]
    DIRECTION OUTPUT ;
    USE SIGNAL ;
    PORT
      LAYER M3 ;
        RECT  50.04 86.362 50.058 86.4 ;
    END
  END vmq[306]
  PIN vmq[307]
    DIRECTION OUTPUT ;
    USE SIGNAL ;
    PORT
      LAYER M5 ;
        RECT  50.208 86.316 50.232 86.4 ;
    END
  END vmq[307]
  PIN vmq[308]
    DIRECTION OUTPUT ;
    USE SIGNAL ;
    PORT
      LAYER M3 ;
        RECT  50.364 86.362 50.382 86.4 ;
    END
  END vmq[308]
  PIN vmq[309]
    DIRECTION OUTPUT ;
    USE SIGNAL ;
    PORT
      LAYER M5 ;
        RECT  50.496 86.316 50.52 86.4 ;
    END
  END vmq[309]
  PIN vmq[30]
    DIRECTION OUTPUT ;
    USE SIGNAL ;
    PORT
      LAYER M3 ;
        RECT  5.94 86.362 5.958 86.4 ;
    END
  END vmq[30]
  PIN vmq[310]
    DIRECTION OUTPUT ;
    USE SIGNAL ;
    PORT
      LAYER M3 ;
        RECT  50.688 86.362 50.706 86.4 ;
    END
  END vmq[310]
  PIN vmq[311]
    DIRECTION OUTPUT ;
    USE SIGNAL ;
    PORT
      LAYER M5 ;
        RECT  50.832 86.316 50.856 86.4 ;
    END
  END vmq[311]
  PIN vmq[312]
    DIRECTION OUTPUT ;
    USE SIGNAL ;
    PORT
      LAYER M3 ;
        RECT  51.012 86.362 51.03 86.4 ;
    END
  END vmq[312]
  PIN vmq[313]
    DIRECTION OUTPUT ;
    USE SIGNAL ;
    PORT
      LAYER M5 ;
        RECT  51.168 86.316 51.192 86.4 ;
    END
  END vmq[313]
  PIN vmq[314]
    DIRECTION OUTPUT ;
    USE SIGNAL ;
    PORT
      LAYER M3 ;
        RECT  51.3 86.362 51.318 86.4 ;
    END
  END vmq[314]
  PIN vmq[315]
    DIRECTION OUTPUT ;
    USE SIGNAL ;
    PORT
      LAYER M5 ;
        RECT  51.456 86.316 51.48 86.4 ;
    END
  END vmq[315]
  PIN vmq[316]
    DIRECTION OUTPUT ;
    USE SIGNAL ;
    PORT
      LAYER M3 ;
        RECT  51.624 86.362 51.642 86.4 ;
    END
  END vmq[316]
  PIN vmq[317]
    DIRECTION OUTPUT ;
    USE SIGNAL ;
    PORT
      LAYER M5 ;
        RECT  51.792 86.316 51.816 86.4 ;
    END
  END vmq[317]
  PIN vmq[318]
    DIRECTION OUTPUT ;
    USE SIGNAL ;
    PORT
      LAYER M3 ;
        RECT  51.948 86.362 51.966 86.4 ;
    END
  END vmq[318]
  PIN vmq[319]
    DIRECTION OUTPUT ;
    USE SIGNAL ;
    PORT
      LAYER M5 ;
        RECT  52.128 86.316 52.152 86.4 ;
    END
  END vmq[319]
  PIN vmq[31]
    DIRECTION OUTPUT ;
    USE SIGNAL ;
    PORT
      LAYER M5 ;
        RECT  6.096 86.316 6.12 86.4 ;
    END
  END vmq[31]
  PIN vmq[320]
    DIRECTION OUTPUT ;
    USE SIGNAL ;
    PORT
      LAYER M3 ;
        RECT  52.272 86.362 52.29 86.4 ;
    END
  END vmq[320]
  PIN vmq[321]
    DIRECTION OUTPUT ;
    USE SIGNAL ;
    PORT
      LAYER M5 ;
        RECT  52.416 86.316 52.44 86.4 ;
    END
  END vmq[321]
  PIN vmq[322]
    DIRECTION OUTPUT ;
    USE SIGNAL ;
    PORT
      LAYER M3 ;
        RECT  52.596 86.362 52.614 86.4 ;
    END
  END vmq[322]
  PIN vmq[323]
    DIRECTION OUTPUT ;
    USE SIGNAL ;
    PORT
      LAYER M5 ;
        RECT  52.752 86.316 52.776 86.4 ;
    END
  END vmq[323]
  PIN vmq[324]
    DIRECTION OUTPUT ;
    USE SIGNAL ;
    PORT
      LAYER M3 ;
        RECT  52.92 86.362 52.938 86.4 ;
    END
  END vmq[324]
  PIN vmq[325]
    DIRECTION OUTPUT ;
    USE SIGNAL ;
    PORT
      LAYER M5 ;
        RECT  53.088 86.316 53.112 86.4 ;
    END
  END vmq[325]
  PIN vmq[326]
    DIRECTION OUTPUT ;
    USE SIGNAL ;
    PORT
      LAYER M3 ;
        RECT  53.244 86.362 53.262 86.4 ;
    END
  END vmq[326]
  PIN vmq[327]
    DIRECTION OUTPUT ;
    USE SIGNAL ;
    PORT
      LAYER M5 ;
        RECT  53.376 86.316 53.4 86.4 ;
    END
  END vmq[327]
  PIN vmq[328]
    DIRECTION OUTPUT ;
    USE SIGNAL ;
    PORT
      LAYER M3 ;
        RECT  53.568 86.362 53.586 86.4 ;
    END
  END vmq[328]
  PIN vmq[329]
    DIRECTION OUTPUT ;
    USE SIGNAL ;
    PORT
      LAYER M5 ;
        RECT  53.712 86.316 53.736 86.4 ;
    END
  END vmq[329]
  PIN vmq[32]
    DIRECTION OUTPUT ;
    USE SIGNAL ;
    PORT
      LAYER M3 ;
        RECT  6.264 86.362 6.282 86.4 ;
    END
  END vmq[32]
  PIN vmq[330]
    DIRECTION OUTPUT ;
    USE SIGNAL ;
    PORT
      LAYER M3 ;
        RECT  53.856 86.362 53.874 86.4 ;
    END
  END vmq[330]
  PIN vmq[331]
    DIRECTION OUTPUT ;
    USE SIGNAL ;
    PORT
      LAYER M5 ;
        RECT  54.048 86.316 54.072 86.4 ;
    END
  END vmq[331]
  PIN vmq[332]
    DIRECTION OUTPUT ;
    USE SIGNAL ;
    PORT
      LAYER M3 ;
        RECT  54.18 86.362 54.198 86.4 ;
    END
  END vmq[332]
  PIN vmq[333]
    DIRECTION OUTPUT ;
    USE SIGNAL ;
    PORT
      LAYER M5 ;
        RECT  54.336 86.316 54.36 86.4 ;
    END
  END vmq[333]
  PIN vmq[334]
    DIRECTION OUTPUT ;
    USE SIGNAL ;
    PORT
      LAYER M3 ;
        RECT  54.504 86.362 54.522 86.4 ;
    END
  END vmq[334]
  PIN vmq[335]
    DIRECTION OUTPUT ;
    USE SIGNAL ;
    PORT
      LAYER M5 ;
        RECT  54.672 86.316 54.696 86.4 ;
    END
  END vmq[335]
  PIN vmq[336]
    DIRECTION OUTPUT ;
    USE SIGNAL ;
    PORT
      LAYER M3 ;
        RECT  54.828 86.362 54.846 86.4 ;
    END
  END vmq[336]
  PIN vmq[337]
    DIRECTION OUTPUT ;
    USE SIGNAL ;
    PORT
      LAYER M5 ;
        RECT  55.008 86.316 55.032 86.4 ;
    END
  END vmq[337]
  PIN vmq[33]
    DIRECTION OUTPUT ;
    USE SIGNAL ;
    PORT
      LAYER M5 ;
        RECT  6.432 86.316 6.456 86.4 ;
    END
  END vmq[33]
  PIN vmq[34]
    DIRECTION OUTPUT ;
    USE SIGNAL ;
    PORT
      LAYER M3 ;
        RECT  6.588 86.362 6.606 86.4 ;
    END
  END vmq[34]
  PIN vmq[35]
    DIRECTION OUTPUT ;
    USE SIGNAL ;
    PORT
      LAYER M5 ;
        RECT  6.72 86.316 6.744 86.4 ;
    END
  END vmq[35]
  PIN vmq[36]
    DIRECTION OUTPUT ;
    USE SIGNAL ;
    PORT
      LAYER M3 ;
        RECT  6.912 86.362 6.93 86.4 ;
    END
  END vmq[36]
  PIN vmq[37]
    DIRECTION OUTPUT ;
    USE SIGNAL ;
    PORT
      LAYER M5 ;
        RECT  7.056 86.316 7.08 86.4 ;
    END
  END vmq[37]
  PIN vmq[38]
    DIRECTION OUTPUT ;
    USE SIGNAL ;
    PORT
      LAYER M3 ;
        RECT  7.236 86.362 7.254 86.4 ;
    END
  END vmq[38]
  PIN vmq[39]
    DIRECTION OUTPUT ;
    USE SIGNAL ;
    PORT
      LAYER M5 ;
        RECT  7.392 86.316 7.416 86.4 ;
    END
  END vmq[39]
  PIN vmq[3]
    DIRECTION OUTPUT ;
    USE SIGNAL ;
    PORT
      LAYER M5 ;
        RECT  1.632 86.316 1.656 86.4 ;
    END
  END vmq[3]
  PIN vmq[40]
    DIRECTION OUTPUT ;
    USE SIGNAL ;
    PORT
      LAYER M3 ;
        RECT  7.524 86.362 7.542 86.4 ;
    END
  END vmq[40]
  PIN vmq[41]
    DIRECTION OUTPUT ;
    USE SIGNAL ;
    PORT
      LAYER M5 ;
        RECT  7.68 86.316 7.704 86.4 ;
    END
  END vmq[41]
  PIN vmq[42]
    DIRECTION OUTPUT ;
    USE SIGNAL ;
    PORT
      LAYER M3 ;
        RECT  7.848 86.362 7.866 86.4 ;
    END
  END vmq[42]
  PIN vmq[43]
    DIRECTION OUTPUT ;
    USE SIGNAL ;
    PORT
      LAYER M5 ;
        RECT  8.016 86.316 8.04 86.4 ;
    END
  END vmq[43]
  PIN vmq[44]
    DIRECTION OUTPUT ;
    USE SIGNAL ;
    PORT
      LAYER M3 ;
        RECT  8.172 86.362 8.19 86.4 ;
    END
  END vmq[44]
  PIN vmq[45]
    DIRECTION OUTPUT ;
    USE SIGNAL ;
    PORT
      LAYER M5 ;
        RECT  8.352 86.316 8.376 86.4 ;
    END
  END vmq[45]
  PIN vmq[46]
    DIRECTION OUTPUT ;
    USE SIGNAL ;
    PORT
      LAYER M3 ;
        RECT  8.496 86.362 8.514 86.4 ;
    END
  END vmq[46]
  PIN vmq[47]
    DIRECTION OUTPUT ;
    USE SIGNAL ;
    PORT
      LAYER M5 ;
        RECT  8.64 86.316 8.664 86.4 ;
    END
  END vmq[47]
  PIN vmq[48]
    DIRECTION OUTPUT ;
    USE SIGNAL ;
    PORT
      LAYER M3 ;
        RECT  8.82 86.362 8.838 86.4 ;
    END
  END vmq[48]
  PIN vmq[49]
    DIRECTION OUTPUT ;
    USE SIGNAL ;
    PORT
      LAYER M5 ;
        RECT  8.976 86.316 9 86.4 ;
    END
  END vmq[49]
  PIN vmq[4]
    DIRECTION OUTPUT ;
    USE SIGNAL ;
    PORT
      LAYER M3 ;
        RECT  1.8 86.362 1.818 86.4 ;
    END
  END vmq[4]
  PIN vmq[50]
    DIRECTION OUTPUT ;
    USE SIGNAL ;
    PORT
      LAYER M3 ;
        RECT  9.144 86.362 9.162 86.4 ;
    END
  END vmq[50]
  PIN vmq[51]
    DIRECTION OUTPUT ;
    USE SIGNAL ;
    PORT
      LAYER M5 ;
        RECT  9.312 86.316 9.336 86.4 ;
    END
  END vmq[51]
  PIN vmq[52]
    DIRECTION OUTPUT ;
    USE SIGNAL ;
    PORT
      LAYER M3 ;
        RECT  9.468 86.362 9.486 86.4 ;
    END
  END vmq[52]
  PIN vmq[53]
    DIRECTION OUTPUT ;
    USE SIGNAL ;
    PORT
      LAYER M5 ;
        RECT  9.6 86.316 9.624 86.4 ;
    END
  END vmq[53]
  PIN vmq[54]
    DIRECTION OUTPUT ;
    USE SIGNAL ;
    PORT
      LAYER M3 ;
        RECT  9.792 86.362 9.81 86.4 ;
    END
  END vmq[54]
  PIN vmq[55]
    DIRECTION OUTPUT ;
    USE SIGNAL ;
    PORT
      LAYER M5 ;
        RECT  9.936 86.316 9.96 86.4 ;
    END
  END vmq[55]
  PIN vmq[56]
    DIRECTION OUTPUT ;
    USE SIGNAL ;
    PORT
      LAYER M3 ;
        RECT  10.116 86.362 10.134 86.4 ;
    END
  END vmq[56]
  PIN vmq[57]
    DIRECTION OUTPUT ;
    USE SIGNAL ;
    PORT
      LAYER M5 ;
        RECT  10.272 86.316 10.296 86.4 ;
    END
  END vmq[57]
  PIN vmq[58]
    DIRECTION OUTPUT ;
    USE SIGNAL ;
    PORT
      LAYER M3 ;
        RECT  10.404 86.362 10.422 86.4 ;
    END
  END vmq[58]
  PIN vmq[59]
    DIRECTION OUTPUT ;
    USE SIGNAL ;
    PORT
      LAYER M5 ;
        RECT  10.56 86.316 10.584 86.4 ;
    END
  END vmq[59]
  PIN vmq[5]
    DIRECTION OUTPUT ;
    USE SIGNAL ;
    PORT
      LAYER M5 ;
        RECT  1.968 86.316 1.992 86.4 ;
    END
  END vmq[5]
  PIN vmq[60]
    DIRECTION OUTPUT ;
    USE SIGNAL ;
    PORT
      LAYER M3 ;
        RECT  10.728 86.362 10.746 86.4 ;
    END
  END vmq[60]
  PIN vmq[61]
    DIRECTION OUTPUT ;
    USE SIGNAL ;
    PORT
      LAYER M5 ;
        RECT  10.896 86.316 10.92 86.4 ;
    END
  END vmq[61]
  PIN vmq[62]
    DIRECTION OUTPUT ;
    USE SIGNAL ;
    PORT
      LAYER M3 ;
        RECT  11.052 86.362 11.07 86.4 ;
    END
  END vmq[62]
  PIN vmq[63]
    DIRECTION OUTPUT ;
    USE SIGNAL ;
    PORT
      LAYER M5 ;
        RECT  11.232 86.316 11.256 86.4 ;
    END
  END vmq[63]
  PIN vmq[64]
    DIRECTION OUTPUT ;
    USE SIGNAL ;
    PORT
      LAYER M3 ;
        RECT  11.376 86.362 11.394 86.4 ;
    END
  END vmq[64]
  PIN vmq[65]
    DIRECTION OUTPUT ;
    USE SIGNAL ;
    PORT
      LAYER M5 ;
        RECT  11.52 86.316 11.544 86.4 ;
    END
  END vmq[65]
  PIN vmq[66]
    DIRECTION OUTPUT ;
    USE SIGNAL ;
    PORT
      LAYER M3 ;
        RECT  11.7 86.362 11.718 86.4 ;
    END
  END vmq[66]
  PIN vmq[67]
    DIRECTION OUTPUT ;
    USE SIGNAL ;
    PORT
      LAYER M5 ;
        RECT  11.856 86.316 11.88 86.4 ;
    END
  END vmq[67]
  PIN vmq[68]
    DIRECTION OUTPUT ;
    USE SIGNAL ;
    PORT
      LAYER M3 ;
        RECT  12.024 86.362 12.042 86.4 ;
    END
  END vmq[68]
  PIN vmq[69]
    DIRECTION OUTPUT ;
    USE SIGNAL ;
    PORT
      LAYER M5 ;
        RECT  12.192 86.316 12.216 86.4 ;
    END
  END vmq[69]
  PIN vmq[6]
    DIRECTION OUTPUT ;
    USE SIGNAL ;
    PORT
      LAYER M3 ;
        RECT  2.124 86.362 2.142 86.4 ;
    END
  END vmq[6]
  PIN vmq[70]
    DIRECTION OUTPUT ;
    USE SIGNAL ;
    PORT
      LAYER M3 ;
        RECT  12.348 86.362 12.366 86.4 ;
    END
  END vmq[70]
  PIN vmq[71]
    DIRECTION OUTPUT ;
    USE SIGNAL ;
    PORT
      LAYER M5 ;
        RECT  12.48 86.316 12.504 86.4 ;
    END
  END vmq[71]
  PIN vmq[72]
    DIRECTION OUTPUT ;
    USE SIGNAL ;
    PORT
      LAYER M3 ;
        RECT  12.672 86.362 12.69 86.4 ;
    END
  END vmq[72]
  PIN vmq[73]
    DIRECTION OUTPUT ;
    USE SIGNAL ;
    PORT
      LAYER M5 ;
        RECT  12.816 86.316 12.84 86.4 ;
    END
  END vmq[73]
  PIN vmq[74]
    DIRECTION OUTPUT ;
    USE SIGNAL ;
    PORT
      LAYER M3 ;
        RECT  12.96 86.362 12.978 86.4 ;
    END
  END vmq[74]
  PIN vmq[75]
    DIRECTION OUTPUT ;
    USE SIGNAL ;
    PORT
      LAYER M5 ;
        RECT  13.152 86.316 13.176 86.4 ;
    END
  END vmq[75]
  PIN vmq[76]
    DIRECTION OUTPUT ;
    USE SIGNAL ;
    PORT
      LAYER M3 ;
        RECT  13.284 86.362 13.302 86.4 ;
    END
  END vmq[76]
  PIN vmq[77]
    DIRECTION OUTPUT ;
    USE SIGNAL ;
    PORT
      LAYER M5 ;
        RECT  13.44 86.316 13.464 86.4 ;
    END
  END vmq[77]
  PIN vmq[78]
    DIRECTION OUTPUT ;
    USE SIGNAL ;
    PORT
      LAYER M3 ;
        RECT  13.608 86.362 13.626 86.4 ;
    END
  END vmq[78]
  PIN vmq[79]
    DIRECTION OUTPUT ;
    USE SIGNAL ;
    PORT
      LAYER M5 ;
        RECT  13.776 86.316 13.8 86.4 ;
    END
  END vmq[79]
  PIN vmq[7]
    DIRECTION OUTPUT ;
    USE SIGNAL ;
    PORT
      LAYER M5 ;
        RECT  2.256 86.316 2.28 86.4 ;
    END
  END vmq[7]
  PIN vmq[80]
    DIRECTION OUTPUT ;
    USE SIGNAL ;
    PORT
      LAYER M3 ;
        RECT  13.932 86.362 13.95 86.4 ;
    END
  END vmq[80]
  PIN vmq[81]
    DIRECTION OUTPUT ;
    USE SIGNAL ;
    PORT
      LAYER M5 ;
        RECT  14.112 86.316 14.136 86.4 ;
    END
  END vmq[81]
  PIN vmq[82]
    DIRECTION OUTPUT ;
    USE SIGNAL ;
    PORT
      LAYER M3 ;
        RECT  14.256 86.362 14.274 86.4 ;
    END
  END vmq[82]
  PIN vmq[83]
    DIRECTION OUTPUT ;
    USE SIGNAL ;
    PORT
      LAYER M5 ;
        RECT  14.4 86.316 14.424 86.4 ;
    END
  END vmq[83]
  PIN vmq[84]
    DIRECTION OUTPUT ;
    USE SIGNAL ;
    PORT
      LAYER M3 ;
        RECT  14.58 86.362 14.598 86.4 ;
    END
  END vmq[84]
  PIN vmq[85]
    DIRECTION OUTPUT ;
    USE SIGNAL ;
    PORT
      LAYER M5 ;
        RECT  14.736 86.316 14.76 86.4 ;
    END
  END vmq[85]
  PIN vmq[86]
    DIRECTION OUTPUT ;
    USE SIGNAL ;
    PORT
      LAYER M3 ;
        RECT  14.904 86.362 14.922 86.4 ;
    END
  END vmq[86]
  PIN vmq[87]
    DIRECTION OUTPUT ;
    USE SIGNAL ;
    PORT
      LAYER M5 ;
        RECT  15.024 86.316 15.048 86.4 ;
    END
  END vmq[87]
  PIN vmq[88]
    DIRECTION OUTPUT ;
    USE SIGNAL ;
    PORT
      LAYER M3 ;
        RECT  15.228 86.362 15.246 86.4 ;
    END
  END vmq[88]
  PIN vmq[89]
    DIRECTION OUTPUT ;
    USE SIGNAL ;
    PORT
      LAYER M5 ;
        RECT  15.36 86.316 15.384 86.4 ;
    END
  END vmq[89]
  PIN vmq[8]
    DIRECTION OUTPUT ;
    USE SIGNAL ;
    PORT
      LAYER M3 ;
        RECT  2.412 86.362 2.43 86.4 ;
    END
  END vmq[8]
  PIN vmq[90]
    DIRECTION OUTPUT ;
    USE SIGNAL ;
    PORT
      LAYER M3 ;
        RECT  15.516 86.362 15.534 86.4 ;
    END
  END vmq[90]
  PIN vmq[91]
    DIRECTION OUTPUT ;
    USE SIGNAL ;
    PORT
      LAYER M5 ;
        RECT  15.696 86.316 15.72 86.4 ;
    END
  END vmq[91]
  PIN vmq[92]
    DIRECTION OUTPUT ;
    USE SIGNAL ;
    PORT
      LAYER M3 ;
        RECT  15.84 86.362 15.858 86.4 ;
    END
  END vmq[92]
  PIN vmq[93]
    DIRECTION OUTPUT ;
    USE SIGNAL ;
    PORT
      LAYER M5 ;
        RECT  15.984 86.316 16.008 86.4 ;
    END
  END vmq[93]
  PIN vmq[94]
    DIRECTION OUTPUT ;
    USE SIGNAL ;
    PORT
      LAYER M3 ;
        RECT  16.164 86.362 16.182 86.4 ;
    END
  END vmq[94]
  PIN vmq[95]
    DIRECTION OUTPUT ;
    USE SIGNAL ;
    PORT
      LAYER M5 ;
        RECT  16.32 86.316 16.344 86.4 ;
    END
  END vmq[95]
  PIN vmq[96]
    DIRECTION OUTPUT ;
    USE SIGNAL ;
    PORT
      LAYER M3 ;
        RECT  16.488 86.362 16.506 86.4 ;
    END
  END vmq[96]
  PIN vmq[97]
    DIRECTION OUTPUT ;
    USE SIGNAL ;
    PORT
      LAYER M5 ;
        RECT  16.656 86.316 16.68 86.4 ;
    END
  END vmq[97]
  PIN vmq[98]
    DIRECTION OUTPUT ;
    USE SIGNAL ;
    PORT
      LAYER M3 ;
        RECT  16.812 86.362 16.83 86.4 ;
    END
  END vmq[98]
  PIN vmq[99]
    DIRECTION OUTPUT ;
    USE SIGNAL ;
    PORT
      LAYER M5 ;
        RECT  16.944 86.316 16.968 86.4 ;
    END
  END vmq[99]
  PIN vmq[9]
    DIRECTION OUTPUT ;
    USE SIGNAL ;
    PORT
      LAYER M5 ;
        RECT  2.592 86.316 2.616 86.4 ;
    END
  END vmq[9]
  PIN vmr[0]
    DIRECTION INPUT ;
    USE SIGNAL ;
    PORT
      LAYER M3 ;
        RECT  1.188 86.362 1.206 86.4 ;
    END
  END vmr[0]
  PIN vmr[100]
    DIRECTION INPUT ;
    USE SIGNAL ;
    PORT
      LAYER M3 ;
        RECT  20.88 86.362 20.898 86.4 ;
    END
  END vmr[100]
  PIN vmr[101]
    DIRECTION INPUT ;
    USE SIGNAL ;
    PORT
      LAYER M5 ;
        RECT  21.072 86.316 21.096 86.4 ;
    END
  END vmr[101]
  PIN vmr[102]
    DIRECTION INPUT ;
    USE SIGNAL ;
    PORT
      LAYER M3 ;
        RECT  21.312 86.362 21.33 86.4 ;
    END
  END vmr[102]
  PIN vmr[103]
    DIRECTION INPUT ;
    USE SIGNAL ;
    PORT
      LAYER M5 ;
        RECT  21.504 86.316 21.528 86.4 ;
    END
  END vmr[103]
  PIN vmr[104]
    DIRECTION INPUT ;
    USE SIGNAL ;
    PORT
      LAYER M3 ;
        RECT  21.672 86.362 21.69 86.4 ;
    END
  END vmr[104]
  PIN vmr[105]
    DIRECTION INPUT ;
    USE SIGNAL ;
    PORT
      LAYER M5 ;
        RECT  21.84 86.316 21.864 86.4 ;
    END
  END vmr[105]
  PIN vmr[106]
    DIRECTION INPUT ;
    USE SIGNAL ;
    PORT
      LAYER M3 ;
        RECT  22.068 86.362 22.086 86.4 ;
    END
  END vmr[106]
  PIN vmr[107]
    DIRECTION INPUT ;
    USE SIGNAL ;
    PORT
      LAYER M5 ;
        RECT  22.272 86.316 22.296 86.4 ;
    END
  END vmr[107]
  PIN vmr[108]
    DIRECTION INPUT ;
    USE SIGNAL ;
    PORT
      LAYER M3 ;
        RECT  22.464 86.362 22.482 86.4 ;
    END
  END vmr[108]
  PIN vmr[109]
    DIRECTION INPUT ;
    USE SIGNAL ;
    PORT
      LAYER M5 ;
        RECT  22.656 86.316 22.68 86.4 ;
    END
  END vmr[109]
  PIN vmr[10]
    DIRECTION INPUT ;
    USE SIGNAL ;
    PORT
      LAYER M3 ;
        RECT  3.132 86.362 3.15 86.4 ;
    END
  END vmr[10]
  PIN vmr[110]
    DIRECTION INPUT ;
    USE SIGNAL ;
    PORT
      LAYER M3 ;
        RECT  22.86 86.362 22.878 86.4 ;
    END
  END vmr[110]
  PIN vmr[111]
    DIRECTION INPUT ;
    USE SIGNAL ;
    PORT
      LAYER M5 ;
        RECT  23.088 86.316 23.112 86.4 ;
    END
  END vmr[111]
  PIN vmr[112]
    DIRECTION INPUT ;
    USE SIGNAL ;
    PORT
      LAYER M3 ;
        RECT  23.256 86.362 23.274 86.4 ;
    END
  END vmr[112]
  PIN vmr[113]
    DIRECTION INPUT ;
    USE SIGNAL ;
    PORT
      LAYER M5 ;
        RECT  23.424 86.316 23.448 86.4 ;
    END
  END vmr[113]
  PIN vmr[114]
    DIRECTION INPUT ;
    USE SIGNAL ;
    PORT
      LAYER M3 ;
        RECT  23.652 86.362 23.67 86.4 ;
    END
  END vmr[114]
  PIN vmr[115]
    DIRECTION INPUT ;
    USE SIGNAL ;
    PORT
      LAYER M5 ;
        RECT  23.808 86.316 23.832 86.4 ;
    END
  END vmr[115]
  PIN vmr[116]
    DIRECTION INPUT ;
    USE SIGNAL ;
    PORT
      LAYER M3 ;
        RECT  24.048 86.362 24.066 86.4 ;
    END
  END vmr[116]
  PIN vmr[117]
    DIRECTION INPUT ;
    USE SIGNAL ;
    PORT
      LAYER M5 ;
        RECT  24.24 86.316 24.264 86.4 ;
    END
  END vmr[117]
  PIN vmr[118]
    DIRECTION INPUT ;
    USE SIGNAL ;
    PORT
      LAYER M3 ;
        RECT  24.408 86.362 24.426 86.4 ;
    END
  END vmr[118]
  PIN vmr[119]
    DIRECTION INPUT ;
    USE SIGNAL ;
    PORT
      LAYER M5 ;
        RECT  24.672 86.316 24.696 86.4 ;
    END
  END vmr[119]
  PIN vmr[11]
    DIRECTION INPUT ;
    USE SIGNAL ;
    PORT
      LAYER M5 ;
        RECT  3.312 86.316 3.336 86.4 ;
    END
  END vmr[11]
  PIN vmr[120]
    DIRECTION INPUT ;
    USE SIGNAL ;
    PORT
      LAYER M3 ;
        RECT  24.84 86.362 24.858 86.4 ;
    END
  END vmr[120]
  PIN vmr[121]
    DIRECTION INPUT ;
    USE SIGNAL ;
    PORT
      LAYER M5 ;
        RECT  25.008 86.316 25.032 86.4 ;
    END
  END vmr[121]
  PIN vmr[122]
    DIRECTION INPUT ;
    USE SIGNAL ;
    PORT
      LAYER M3 ;
        RECT  25.2 86.362 25.218 86.4 ;
    END
  END vmr[122]
  PIN vmr[123]
    DIRECTION INPUT ;
    USE SIGNAL ;
    PORT
      LAYER M5 ;
        RECT  25.392 86.316 25.416 86.4 ;
    END
  END vmr[123]
  PIN vmr[124]
    DIRECTION INPUT ;
    USE SIGNAL ;
    PORT
      LAYER M3 ;
        RECT  25.596 86.362 25.614 86.4 ;
    END
  END vmr[124]
  PIN vmr[125]
    DIRECTION INPUT ;
    USE SIGNAL ;
    PORT
      LAYER M5 ;
        RECT  25.824 86.316 25.848 86.4 ;
    END
  END vmr[125]
  PIN vmr[126]
    DIRECTION INPUT ;
    USE SIGNAL ;
    PORT
      LAYER M3 ;
        RECT  25.992 86.362 26.01 86.4 ;
    END
  END vmr[126]
  PIN vmr[127]
    DIRECTION INPUT ;
    USE SIGNAL ;
    PORT
      LAYER M5 ;
        RECT  26.256 86.316 26.28 86.4 ;
    END
  END vmr[127]
  PIN vmr[128]
    DIRECTION INPUT ;
    USE SIGNAL ;
    PORT
      LAYER M3 ;
        RECT  26.424 86.362 26.442 86.4 ;
    END
  END vmr[128]
  PIN vmr[129]
    DIRECTION INPUT ;
    USE SIGNAL ;
    PORT
      LAYER M5 ;
        RECT  26.592 86.316 26.616 86.4 ;
    END
  END vmr[129]
  PIN vmr[12]
    DIRECTION INPUT ;
    USE SIGNAL ;
    PORT
      LAYER M3 ;
        RECT  3.528 86.362 3.546 86.4 ;
    END
  END vmr[12]
  PIN vmr[130]
    DIRECTION INPUT ;
    USE SIGNAL ;
    PORT
      LAYER M3 ;
        RECT  26.784 86.362 26.802 86.4 ;
    END
  END vmr[130]
  PIN vmr[131]
    DIRECTION INPUT ;
    USE SIGNAL ;
    PORT
      LAYER M5 ;
        RECT  26.976 86.316 27 86.4 ;
    END
  END vmr[131]
  PIN vmr[132]
    DIRECTION INPUT ;
    USE SIGNAL ;
    PORT
      LAYER M3 ;
        RECT  27.18 86.362 27.198 86.4 ;
    END
  END vmr[132]
  PIN vmr[133]
    DIRECTION INPUT ;
    USE SIGNAL ;
    PORT
      LAYER M5 ;
        RECT  27.36 86.316 27.384 86.4 ;
    END
  END vmr[133]
  PIN vmr[134]
    DIRECTION INPUT ;
    USE SIGNAL ;
    PORT
      LAYER M3 ;
        RECT  27.576 86.362 27.594 86.4 ;
    END
  END vmr[134]
  PIN vmr[135]
    DIRECTION INPUT ;
    USE SIGNAL ;
    PORT
      LAYER M5 ;
        RECT  27.792 86.316 27.816 86.4 ;
    END
  END vmr[135]
  PIN vmr[136]
    DIRECTION INPUT ;
    USE SIGNAL ;
    PORT
      LAYER M3 ;
        RECT  27.972 86.362 27.99 86.4 ;
    END
  END vmr[136]
  PIN vmr[137]
    DIRECTION INPUT ;
    USE SIGNAL ;
    PORT
      LAYER M5 ;
        RECT  28.176 86.316 28.2 86.4 ;
    END
  END vmr[137]
  PIN vmr[138]
    DIRECTION INPUT ;
    USE SIGNAL ;
    PORT
      LAYER M3 ;
        RECT  28.368 86.362 28.386 86.4 ;
    END
  END vmr[138]
  PIN vmr[139]
    DIRECTION INPUT ;
    USE SIGNAL ;
    PORT
      LAYER M5 ;
        RECT  28.56 86.316 28.584 86.4 ;
    END
  END vmr[139]
  PIN vmr[13]
    DIRECTION INPUT ;
    USE SIGNAL ;
    PORT
      LAYER M5 ;
        RECT  3.744 86.316 3.768 86.4 ;
    END
  END vmr[13]
  PIN vmr[140]
    DIRECTION INPUT ;
    USE SIGNAL ;
    PORT
      LAYER M3 ;
        RECT  28.764 86.362 28.782 86.4 ;
    END
  END vmr[140]
  PIN vmr[141]
    DIRECTION INPUT ;
    USE SIGNAL ;
    PORT
      LAYER M5 ;
        RECT  28.944 86.316 28.968 86.4 ;
    END
  END vmr[141]
  PIN vmr[142]
    DIRECTION INPUT ;
    USE SIGNAL ;
    PORT
      LAYER M3 ;
        RECT  29.16 86.362 29.178 86.4 ;
    END
  END vmr[142]
  PIN vmr[143]
    DIRECTION INPUT ;
    USE SIGNAL ;
    PORT
      LAYER M5 ;
        RECT  29.328 86.316 29.352 86.4 ;
    END
  END vmr[143]
  PIN vmr[144]
    DIRECTION INPUT ;
    USE SIGNAL ;
    PORT
      LAYER M3 ;
        RECT  29.556 86.362 29.574 86.4 ;
    END
  END vmr[144]
  PIN vmr[145]
    DIRECTION INPUT ;
    USE SIGNAL ;
    PORT
      LAYER M5 ;
        RECT  29.808 86.316 29.832 86.4 ;
    END
  END vmr[145]
  PIN vmr[146]
    DIRECTION INPUT ;
    USE SIGNAL ;
    PORT
      LAYER M3 ;
        RECT  29.952 86.362 29.97 86.4 ;
    END
  END vmr[146]
  PIN vmr[147]
    DIRECTION INPUT ;
    USE SIGNAL ;
    PORT
      LAYER M5 ;
        RECT  30.144 86.316 30.168 86.4 ;
    END
  END vmr[147]
  PIN vmr[148]
    DIRECTION INPUT ;
    USE SIGNAL ;
    PORT
      LAYER M3 ;
        RECT  30.348 86.362 30.366 86.4 ;
    END
  END vmr[148]
  PIN vmr[149]
    DIRECTION INPUT ;
    USE SIGNAL ;
    PORT
      LAYER M5 ;
        RECT  30.528 86.316 30.552 86.4 ;
    END
  END vmr[149]
  PIN vmr[14]
    DIRECTION INPUT ;
    USE SIGNAL ;
    PORT
      LAYER M3 ;
        RECT  3.924 86.362 3.942 86.4 ;
    END
  END vmr[14]
  PIN vmr[150]
    DIRECTION INPUT ;
    USE SIGNAL ;
    PORT
      LAYER M3 ;
        RECT  30.744 86.362 30.762 86.4 ;
    END
  END vmr[150]
  PIN vmr[151]
    DIRECTION INPUT ;
    USE SIGNAL ;
    PORT
      LAYER M5 ;
        RECT  30.912 86.316 30.936 86.4 ;
    END
  END vmr[151]
  PIN vmr[152]
    DIRECTION INPUT ;
    USE SIGNAL ;
    PORT
      LAYER M3 ;
        RECT  31.14 86.362 31.158 86.4 ;
    END
  END vmr[152]
  PIN vmr[153]
    DIRECTION INPUT ;
    USE SIGNAL ;
    PORT
      LAYER M5 ;
        RECT  31.392 86.316 31.416 86.4 ;
    END
  END vmr[153]
  PIN vmr[154]
    DIRECTION INPUT ;
    USE SIGNAL ;
    PORT
      LAYER M3 ;
        RECT  31.536 86.362 31.554 86.4 ;
    END
  END vmr[154]
  PIN vmr[155]
    DIRECTION INPUT ;
    USE SIGNAL ;
    PORT
      LAYER M5 ;
        RECT  31.728 86.316 31.752 86.4 ;
    END
  END vmr[155]
  PIN vmr[156]
    DIRECTION INPUT ;
    USE SIGNAL ;
    PORT
      LAYER M3 ;
        RECT  31.932 86.362 31.95 86.4 ;
    END
  END vmr[156]
  PIN vmr[157]
    DIRECTION INPUT ;
    USE SIGNAL ;
    PORT
      LAYER M5 ;
        RECT  32.112 86.316 32.136 86.4 ;
    END
  END vmr[157]
  PIN vmr[158]
    DIRECTION INPUT ;
    USE SIGNAL ;
    PORT
      LAYER M3 ;
        RECT  32.292 86.362 32.31 86.4 ;
    END
  END vmr[158]
  PIN vmr[159]
    DIRECTION INPUT ;
    USE SIGNAL ;
    PORT
      LAYER M5 ;
        RECT  32.496 86.316 32.52 86.4 ;
    END
  END vmr[159]
  PIN vmr[15]
    DIRECTION INPUT ;
    USE SIGNAL ;
    PORT
      LAYER M5 ;
        RECT  4.128 86.316 4.152 86.4 ;
    END
  END vmr[15]
  PIN vmr[160]
    DIRECTION INPUT ;
    USE SIGNAL ;
    PORT
      LAYER M3 ;
        RECT  32.688 86.362 32.706 86.4 ;
    END
  END vmr[160]
  PIN vmr[161]
    DIRECTION INPUT ;
    USE SIGNAL ;
    PORT
      LAYER M5 ;
        RECT  32.88 86.316 32.904 86.4 ;
    END
  END vmr[161]
  PIN vmr[162]
    DIRECTION INPUT ;
    USE SIGNAL ;
    PORT
      LAYER M3 ;
        RECT  33.084 86.362 33.102 86.4 ;
    END
  END vmr[162]
  PIN vmr[163]
    DIRECTION INPUT ;
    USE SIGNAL ;
    PORT
      LAYER M5 ;
        RECT  33.312 86.316 33.336 86.4 ;
    END
  END vmr[163]
  PIN vmr[164]
    DIRECTION INPUT ;
    USE SIGNAL ;
    PORT
      LAYER M3 ;
        RECT  33.48 86.362 33.498 86.4 ;
    END
  END vmr[164]
  PIN vmr[165]
    DIRECTION INPUT ;
    USE SIGNAL ;
    PORT
      LAYER M5 ;
        RECT  33.696 86.316 33.72 86.4 ;
    END
  END vmr[165]
  PIN vmr[166]
    DIRECTION INPUT ;
    USE SIGNAL ;
    PORT
      LAYER M3 ;
        RECT  33.876 86.362 33.894 86.4 ;
    END
  END vmr[166]
  PIN vmr[167]
    DIRECTION INPUT ;
    USE SIGNAL ;
    PORT
      LAYER M5 ;
        RECT  34.08 86.316 34.104 86.4 ;
    END
  END vmr[167]
  PIN vmr[168]
    DIRECTION INPUT ;
    USE SIGNAL ;
    PORT
      LAYER M3 ;
        RECT  34.272 86.362 34.29 86.4 ;
    END
  END vmr[168]
  PIN vmr[169]
    DIRECTION INPUT ;
    USE SIGNAL ;
    PORT
      LAYER M5 ;
        RECT  34.464 86.316 34.488 86.4 ;
    END
  END vmr[169]
  PIN vmr[16]
    DIRECTION INPUT ;
    USE SIGNAL ;
    PORT
      LAYER M3 ;
        RECT  4.32 86.362 4.338 86.4 ;
    END
  END vmr[16]
  PIN vmr[170]
    DIRECTION INPUT ;
    USE SIGNAL ;
    PORT
      LAYER M3 ;
        RECT  34.668 86.362 34.686 86.4 ;
    END
  END vmr[170]
  PIN vmr[171]
    DIRECTION INPUT ;
    USE SIGNAL ;
    PORT
      LAYER M5 ;
        RECT  34.896 86.316 34.92 86.4 ;
    END
  END vmr[171]
  PIN vmr[172]
    DIRECTION INPUT ;
    USE SIGNAL ;
    PORT
      LAYER M3 ;
        RECT  35.064 86.362 35.082 86.4 ;
    END
  END vmr[172]
  PIN vmr[173]
    DIRECTION INPUT ;
    USE SIGNAL ;
    PORT
      LAYER M5 ;
        RECT  35.28 86.316 35.304 86.4 ;
    END
  END vmr[173]
  PIN vmr[174]
    DIRECTION INPUT ;
    USE SIGNAL ;
    PORT
      LAYER M3 ;
        RECT  35.46 86.362 35.478 86.4 ;
    END
  END vmr[174]
  PIN vmr[175]
    DIRECTION INPUT ;
    USE SIGNAL ;
    PORT
      LAYER M5 ;
        RECT  35.664 86.316 35.688 86.4 ;
    END
  END vmr[175]
  PIN vmr[176]
    DIRECTION INPUT ;
    USE SIGNAL ;
    PORT
      LAYER M3 ;
        RECT  35.856 86.362 35.874 86.4 ;
    END
  END vmr[176]
  PIN vmr[177]
    DIRECTION INPUT ;
    USE SIGNAL ;
    PORT
      LAYER M5 ;
        RECT  36.048 86.316 36.072 86.4 ;
    END
  END vmr[177]
  PIN vmr[178]
    DIRECTION INPUT ;
    USE SIGNAL ;
    PORT
      LAYER M3 ;
        RECT  36.252 86.362 36.27 86.4 ;
    END
  END vmr[178]
  PIN vmr[179]
    DIRECTION INPUT ;
    USE SIGNAL ;
    PORT
      LAYER M5 ;
        RECT  36.432 86.316 36.456 86.4 ;
    END
  END vmr[179]
  PIN vmr[17]
    DIRECTION INPUT ;
    USE SIGNAL ;
    PORT
      LAYER M5 ;
        RECT  4.56 86.316 4.584 86.4 ;
    END
  END vmr[17]
  PIN vmr[180]
    DIRECTION INPUT ;
    USE SIGNAL ;
    PORT
      LAYER M3 ;
        RECT  36.648 86.362 36.666 86.4 ;
    END
  END vmr[180]
  PIN vmr[181]
    DIRECTION INPUT ;
    USE SIGNAL ;
    PORT
      LAYER M5 ;
        RECT  36.816 86.316 36.84 86.4 ;
    END
  END vmr[181]
  PIN vmr[182]
    DIRECTION INPUT ;
    USE SIGNAL ;
    PORT
      LAYER M3 ;
        RECT  37.044 86.362 37.062 86.4 ;
    END
  END vmr[182]
  PIN vmr[183]
    DIRECTION INPUT ;
    USE SIGNAL ;
    PORT
      LAYER M5 ;
        RECT  37.248 86.316 37.272 86.4 ;
    END
  END vmr[183]
  PIN vmr[184]
    DIRECTION INPUT ;
    USE SIGNAL ;
    PORT
      LAYER M3 ;
        RECT  37.44 86.362 37.458 86.4 ;
    END
  END vmr[184]
  PIN vmr[185]
    DIRECTION INPUT ;
    USE SIGNAL ;
    PORT
      LAYER M5 ;
        RECT  37.632 86.316 37.656 86.4 ;
    END
  END vmr[185]
  PIN vmr[186]
    DIRECTION INPUT ;
    USE SIGNAL ;
    PORT
      LAYER M3 ;
        RECT  37.836 86.362 37.854 86.4 ;
    END
  END vmr[186]
  PIN vmr[187]
    DIRECTION INPUT ;
    USE SIGNAL ;
    PORT
      LAYER M5 ;
        RECT  38.016 86.316 38.04 86.4 ;
    END
  END vmr[187]
  PIN vmr[188]
    DIRECTION INPUT ;
    USE SIGNAL ;
    PORT
      LAYER M3 ;
        RECT  38.268 86.362 38.286 86.4 ;
    END
  END vmr[188]
  PIN vmr[189]
    DIRECTION INPUT ;
    USE SIGNAL ;
    PORT
      LAYER M5 ;
        RECT  38.4 86.316 38.424 86.4 ;
    END
  END vmr[189]
  PIN vmr[18]
    DIRECTION INPUT ;
    USE SIGNAL ;
    PORT
      LAYER M3 ;
        RECT  4.716 86.362 4.734 86.4 ;
    END
  END vmr[18]
  PIN vmr[190]
    DIRECTION INPUT ;
    USE SIGNAL ;
    PORT
      LAYER M3 ;
        RECT  38.628 86.362 38.646 86.4 ;
    END
  END vmr[190]
  PIN vmr[191]
    DIRECTION INPUT ;
    USE SIGNAL ;
    PORT
      LAYER M5 ;
        RECT  38.832 86.316 38.856 86.4 ;
    END
  END vmr[191]
  PIN vmr[192]
    DIRECTION INPUT ;
    USE SIGNAL ;
    PORT
      LAYER M3 ;
        RECT  39.024 86.362 39.042 86.4 ;
    END
  END vmr[192]
  PIN vmr[193]
    DIRECTION INPUT ;
    USE SIGNAL ;
    PORT
      LAYER M5 ;
        RECT  39.216 86.316 39.24 86.4 ;
    END
  END vmr[193]
  PIN vmr[194]
    DIRECTION INPUT ;
    USE SIGNAL ;
    PORT
      LAYER M3 ;
        RECT  39.42 86.362 39.438 86.4 ;
    END
  END vmr[194]
  PIN vmr[195]
    DIRECTION INPUT ;
    USE SIGNAL ;
    PORT
      LAYER M5 ;
        RECT  39.6 86.316 39.624 86.4 ;
    END
  END vmr[195]
  PIN vmr[196]
    DIRECTION INPUT ;
    USE SIGNAL ;
    PORT
      LAYER M3 ;
        RECT  39.78 86.362 39.798 86.4 ;
    END
  END vmr[196]
  PIN vmr[197]
    DIRECTION INPUT ;
    USE SIGNAL ;
    PORT
      LAYER M5 ;
        RECT  40.032 86.316 40.056 86.4 ;
    END
  END vmr[197]
  PIN vmr[198]
    DIRECTION INPUT ;
    USE SIGNAL ;
    PORT
      LAYER M3 ;
        RECT  40.176 86.362 40.194 86.4 ;
    END
  END vmr[198]
  PIN vmr[199]
    DIRECTION INPUT ;
    USE SIGNAL ;
    PORT
      LAYER M5 ;
        RECT  40.368 86.316 40.392 86.4 ;
    END
  END vmr[199]
  PIN vmr[19]
    DIRECTION INPUT ;
    USE SIGNAL ;
    PORT
      LAYER M5 ;
        RECT  4.896 86.316 4.92 86.4 ;
    END
  END vmr[19]
  PIN vmr[1]
    DIRECTION INPUT ;
    USE SIGNAL ;
    PORT
      LAYER M5 ;
        RECT  1.344 86.316 1.368 86.4 ;
    END
  END vmr[1]
  PIN vmr[200]
    DIRECTION INPUT ;
    USE SIGNAL ;
    PORT
      LAYER M3 ;
        RECT  40.572 86.362 40.59 86.4 ;
    END
  END vmr[200]
  PIN vmr[201]
    DIRECTION INPUT ;
    USE SIGNAL ;
    PORT
      LAYER M5 ;
        RECT  40.8 86.316 40.824 86.4 ;
    END
  END vmr[201]
  PIN vmr[202]
    DIRECTION INPUT ;
    USE SIGNAL ;
    PORT
      LAYER M3 ;
        RECT  40.968 86.362 40.986 86.4 ;
    END
  END vmr[202]
  PIN vmr[203]
    DIRECTION INPUT ;
    USE SIGNAL ;
    PORT
      LAYER M5 ;
        RECT  41.184 86.316 41.208 86.4 ;
    END
  END vmr[203]
  PIN vmr[204]
    DIRECTION INPUT ;
    USE SIGNAL ;
    PORT
      LAYER M3 ;
        RECT  41.364 86.362 41.382 86.4 ;
    END
  END vmr[204]
  PIN vmr[205]
    DIRECTION INPUT ;
    USE SIGNAL ;
    PORT
      LAYER M5 ;
        RECT  41.616 86.316 41.64 86.4 ;
    END
  END vmr[205]
  PIN vmr[206]
    DIRECTION INPUT ;
    USE SIGNAL ;
    PORT
      LAYER M3 ;
        RECT  41.76 86.362 41.778 86.4 ;
    END
  END vmr[206]
  PIN vmr[207]
    DIRECTION INPUT ;
    USE SIGNAL ;
    PORT
      LAYER M5 ;
        RECT  41.952 86.316 41.976 86.4 ;
    END
  END vmr[207]
  PIN vmr[208]
    DIRECTION INPUT ;
    USE SIGNAL ;
    PORT
      LAYER M3 ;
        RECT  42.156 86.362 42.174 86.4 ;
    END
  END vmr[208]
  PIN vmr[209]
    DIRECTION INPUT ;
    USE SIGNAL ;
    PORT
      LAYER M5 ;
        RECT  42.336 86.316 42.36 86.4 ;
    END
  END vmr[209]
  PIN vmr[20]
    DIRECTION INPUT ;
    USE SIGNAL ;
    PORT
      LAYER M3 ;
        RECT  5.112 86.362 5.13 86.4 ;
    END
  END vmr[20]
  PIN vmr[210]
    DIRECTION INPUT ;
    USE SIGNAL ;
    PORT
      LAYER M3 ;
        RECT  42.552 86.362 42.57 86.4 ;
    END
  END vmr[210]
  PIN vmr[211]
    DIRECTION INPUT ;
    USE SIGNAL ;
    PORT
      LAYER M5 ;
        RECT  42.768 86.316 42.792 86.4 ;
    END
  END vmr[211]
  PIN vmr[212]
    DIRECTION INPUT ;
    USE SIGNAL ;
    PORT
      LAYER M3 ;
        RECT  42.948 86.362 42.966 86.4 ;
    END
  END vmr[212]
  PIN vmr[213]
    DIRECTION INPUT ;
    USE SIGNAL ;
    PORT
      LAYER M5 ;
        RECT  43.2 86.316 43.224 86.4 ;
    END
  END vmr[213]
  PIN vmr[214]
    DIRECTION INPUT ;
    USE SIGNAL ;
    PORT
      LAYER M3 ;
        RECT  43.38 86.362 43.398 86.4 ;
    END
  END vmr[214]
  PIN vmr[215]
    DIRECTION INPUT ;
    USE SIGNAL ;
    PORT
      LAYER M5 ;
        RECT  43.536 86.316 43.56 86.4 ;
    END
  END vmr[215]
  PIN vmr[216]
    DIRECTION INPUT ;
    USE SIGNAL ;
    PORT
      LAYER M3 ;
        RECT  43.74 86.362 43.758 86.4 ;
    END
  END vmr[216]
  PIN vmr[217]
    DIRECTION INPUT ;
    USE SIGNAL ;
    PORT
      LAYER M5 ;
        RECT  43.92 86.316 43.944 86.4 ;
    END
  END vmr[217]
  PIN vmr[218]
    DIRECTION INPUT ;
    USE SIGNAL ;
    PORT
      LAYER M3 ;
        RECT  44.136 86.362 44.154 86.4 ;
    END
  END vmr[218]
  PIN vmr[219]
    DIRECTION INPUT ;
    USE SIGNAL ;
    PORT
      LAYER M5 ;
        RECT  44.304 86.316 44.328 86.4 ;
    END
  END vmr[219]
  PIN vmr[21]
    DIRECTION INPUT ;
    USE SIGNAL ;
    PORT
      LAYER M5 ;
        RECT  5.328 86.316 5.352 86.4 ;
    END
  END vmr[21]
  PIN vmr[220]
    DIRECTION INPUT ;
    USE SIGNAL ;
    PORT
      LAYER M3 ;
        RECT  44.532 86.362 44.55 86.4 ;
    END
  END vmr[220]
  PIN vmr[221]
    DIRECTION INPUT ;
    USE SIGNAL ;
    PORT
      LAYER M5 ;
        RECT  44.736 86.316 44.76 86.4 ;
    END
  END vmr[221]
  PIN vmr[222]
    DIRECTION INPUT ;
    USE SIGNAL ;
    PORT
      LAYER M3 ;
        RECT  44.964 86.362 44.982 86.4 ;
    END
  END vmr[222]
  PIN vmr[223]
    DIRECTION INPUT ;
    USE SIGNAL ;
    PORT
      LAYER M5 ;
        RECT  45.12 86.316 45.144 86.4 ;
    END
  END vmr[223]
  PIN vmr[224]
    DIRECTION INPUT ;
    USE SIGNAL ;
    PORT
      LAYER M3 ;
        RECT  45.324 86.362 45.342 86.4 ;
    END
  END vmr[224]
  PIN vmr[225]
    DIRECTION INPUT ;
    USE SIGNAL ;
    PORT
      LAYER M5 ;
        RECT  45.504 86.316 45.528 86.4 ;
    END
  END vmr[225]
  PIN vmr[226]
    DIRECTION INPUT ;
    USE SIGNAL ;
    PORT
      LAYER M3 ;
        RECT  45.72 86.362 45.738 86.4 ;
    END
  END vmr[226]
  PIN vmr[227]
    DIRECTION INPUT ;
    USE SIGNAL ;
    PORT
      LAYER M5 ;
        RECT  45.888 86.316 45.912 86.4 ;
    END
  END vmr[227]
  PIN vmr[228]
    DIRECTION INPUT ;
    USE SIGNAL ;
    PORT
      LAYER M3 ;
        RECT  46.116 86.362 46.134 86.4 ;
    END
  END vmr[228]
  PIN vmr[229]
    DIRECTION INPUT ;
    USE SIGNAL ;
    PORT
      LAYER M5 ;
        RECT  46.32 86.316 46.344 86.4 ;
    END
  END vmr[229]
  PIN vmr[22]
    DIRECTION INPUT ;
    USE SIGNAL ;
    PORT
      LAYER M3 ;
        RECT  5.508 86.362 5.526 86.4 ;
    END
  END vmr[22]
  PIN vmr[230]
    DIRECTION INPUT ;
    USE SIGNAL ;
    PORT
      LAYER M3 ;
        RECT  46.548 86.362 46.566 86.4 ;
    END
  END vmr[230]
  PIN vmr[231]
    DIRECTION INPUT ;
    USE SIGNAL ;
    PORT
      LAYER M5 ;
        RECT  46.752 86.316 46.776 86.4 ;
    END
  END vmr[231]
  PIN vmr[232]
    DIRECTION INPUT ;
    USE SIGNAL ;
    PORT
      LAYER M3 ;
        RECT  46.908 86.362 46.926 86.4 ;
    END
  END vmr[232]
  PIN vmr[233]
    DIRECTION INPUT ;
    USE SIGNAL ;
    PORT
      LAYER M5 ;
        RECT  47.088 86.316 47.112 86.4 ;
    END
  END vmr[233]
  PIN vmr[234]
    DIRECTION INPUT ;
    USE SIGNAL ;
    PORT
      LAYER M3 ;
        RECT  47.304 86.362 47.322 86.4 ;
    END
  END vmr[234]
  PIN vmr[235]
    DIRECTION INPUT ;
    USE SIGNAL ;
    PORT
      LAYER M5 ;
        RECT  47.472 86.316 47.496 86.4 ;
    END
  END vmr[235]
  PIN vmr[236]
    DIRECTION INPUT ;
    USE SIGNAL ;
    PORT
      LAYER M3 ;
        RECT  47.664 86.362 47.682 86.4 ;
    END
  END vmr[236]
  PIN vmr[237]
    DIRECTION INPUT ;
    USE SIGNAL ;
    PORT
      LAYER M5 ;
        RECT  47.856 86.316 47.88 86.4 ;
    END
  END vmr[237]
  PIN vmr[238]
    DIRECTION INPUT ;
    USE SIGNAL ;
    PORT
      LAYER M3 ;
        RECT  48.06 86.362 48.078 86.4 ;
    END
  END vmr[238]
  PIN vmr[239]
    DIRECTION INPUT ;
    USE SIGNAL ;
    PORT
      LAYER M5 ;
        RECT  48.336 86.316 48.36 86.4 ;
    END
  END vmr[239]
  PIN vmr[23]
    DIRECTION INPUT ;
    USE SIGNAL ;
    PORT
      LAYER M5 ;
        RECT  5.712 86.316 5.736 86.4 ;
    END
  END vmr[23]
  PIN vmr[240]
    DIRECTION INPUT ;
    USE SIGNAL ;
    PORT
      LAYER M3 ;
        RECT  48.492 86.362 48.51 86.4 ;
    END
  END vmr[240]
  PIN vmr[241]
    DIRECTION INPUT ;
    USE SIGNAL ;
    PORT
      LAYER M5 ;
        RECT  48.672 86.316 48.696 86.4 ;
    END
  END vmr[241]
  PIN vmr[242]
    DIRECTION INPUT ;
    USE SIGNAL ;
    PORT
      LAYER M3 ;
        RECT  48.852 86.362 48.87 86.4 ;
    END
  END vmr[242]
  PIN vmr[243]
    DIRECTION INPUT ;
    USE SIGNAL ;
    PORT
      LAYER M5 ;
        RECT  49.056 86.316 49.08 86.4 ;
    END
  END vmr[243]
  PIN vmr[244]
    DIRECTION INPUT ;
    USE SIGNAL ;
    PORT
      LAYER M3 ;
        RECT  49.248 86.362 49.266 86.4 ;
    END
  END vmr[244]
  PIN vmr[245]
    DIRECTION INPUT ;
    USE SIGNAL ;
    PORT
      LAYER M5 ;
        RECT  49.44 86.316 49.464 86.4 ;
    END
  END vmr[245]
  PIN vmr[246]
    DIRECTION INPUT ;
    USE SIGNAL ;
    PORT
      LAYER M3 ;
        RECT  49.644 86.362 49.662 86.4 ;
    END
  END vmr[246]
  PIN vmr[247]
    DIRECTION INPUT ;
    USE SIGNAL ;
    PORT
      LAYER M5 ;
        RECT  49.824 86.316 49.848 86.4 ;
    END
  END vmr[247]
  PIN vmr[248]
    DIRECTION INPUT ;
    USE SIGNAL ;
    PORT
      LAYER M3 ;
        RECT  50.076 86.362 50.094 86.4 ;
    END
  END vmr[248]
  PIN vmr[249]
    DIRECTION INPUT ;
    USE SIGNAL ;
    PORT
      LAYER M5 ;
        RECT  50.256 86.316 50.28 86.4 ;
    END
  END vmr[249]
  PIN vmr[24]
    DIRECTION INPUT ;
    USE SIGNAL ;
    PORT
      LAYER M3 ;
        RECT  5.904 86.362 5.922 86.4 ;
    END
  END vmr[24]
  PIN vmr[250]
    DIRECTION INPUT ;
    USE SIGNAL ;
    PORT
      LAYER M3 ;
        RECT  50.436 86.362 50.454 86.4 ;
    END
  END vmr[250]
  PIN vmr[251]
    DIRECTION INPUT ;
    USE SIGNAL ;
    PORT
      LAYER M5 ;
        RECT  50.64 86.316 50.664 86.4 ;
    END
  END vmr[251]
  PIN vmr[252]
    DIRECTION INPUT ;
    USE SIGNAL ;
    PORT
      LAYER M3 ;
        RECT  50.832 86.362 50.85 86.4 ;
    END
  END vmr[252]
  PIN vmr[253]
    DIRECTION INPUT ;
    USE SIGNAL ;
    PORT
      LAYER M5 ;
        RECT  51.024 86.316 51.048 86.4 ;
    END
  END vmr[253]
  PIN vmr[254]
    DIRECTION INPUT ;
    USE SIGNAL ;
    PORT
      LAYER M3 ;
        RECT  51.228 86.362 51.246 86.4 ;
    END
  END vmr[254]
  PIN vmr[255]
    DIRECTION INPUT ;
    USE SIGNAL ;
    PORT
      LAYER M5 ;
        RECT  51.408 86.316 51.432 86.4 ;
    END
  END vmr[255]
  PIN vmr[256]
    DIRECTION INPUT ;
    USE SIGNAL ;
    PORT
      LAYER M3 ;
        RECT  51.66 86.362 51.678 86.4 ;
    END
  END vmr[256]
  PIN vmr[257]
    DIRECTION INPUT ;
    USE SIGNAL ;
    PORT
      LAYER M5 ;
        RECT  51.84 86.316 51.864 86.4 ;
    END
  END vmr[257]
  PIN vmr[258]
    DIRECTION INPUT ;
    USE SIGNAL ;
    PORT
      LAYER M3 ;
        RECT  52.02 86.362 52.038 86.4 ;
    END
  END vmr[258]
  PIN vmr[259]
    DIRECTION INPUT ;
    USE SIGNAL ;
    PORT
      LAYER M5 ;
        RECT  52.224 86.316 52.248 86.4 ;
    END
  END vmr[259]
  PIN vmr[25]
    DIRECTION INPUT ;
    USE SIGNAL ;
    PORT
      LAYER M5 ;
        RECT  6.144 86.316 6.168 86.4 ;
    END
  END vmr[25]
  PIN vmr[260]
    DIRECTION INPUT ;
    USE SIGNAL ;
    PORT
      LAYER M3 ;
        RECT  52.416 86.362 52.434 86.4 ;
    END
  END vmr[260]
  PIN vmr[261]
    DIRECTION INPUT ;
    USE SIGNAL ;
    PORT
      LAYER M5 ;
        RECT  52.608 86.316 52.632 86.4 ;
    END
  END vmr[261]
  PIN vmr[262]
    DIRECTION INPUT ;
    USE SIGNAL ;
    PORT
      LAYER M3 ;
        RECT  52.812 86.362 52.83 86.4 ;
    END
  END vmr[262]
  PIN vmr[263]
    DIRECTION INPUT ;
    USE SIGNAL ;
    PORT
      LAYER M5 ;
        RECT  52.992 86.316 53.016 86.4 ;
    END
  END vmr[263]
  PIN vmr[264]
    DIRECTION INPUT ;
    USE SIGNAL ;
    PORT
      LAYER M3 ;
        RECT  53.208 86.362 53.226 86.4 ;
    END
  END vmr[264]
  PIN vmr[265]
    DIRECTION INPUT ;
    USE SIGNAL ;
    PORT
      LAYER M5 ;
        RECT  53.424 86.316 53.448 86.4 ;
    END
  END vmr[265]
  PIN vmr[266]
    DIRECTION INPUT ;
    USE SIGNAL ;
    PORT
      LAYER M3 ;
        RECT  53.604 86.362 53.622 86.4 ;
    END
  END vmr[266]
  PIN vmr[267]
    DIRECTION INPUT ;
    USE SIGNAL ;
    PORT
      LAYER M5 ;
        RECT  53.808 86.316 53.832 86.4 ;
    END
  END vmr[267]
  PIN vmr[268]
    DIRECTION INPUT ;
    USE SIGNAL ;
    PORT
      LAYER M3 ;
        RECT  54 86.362 54.018 86.4 ;
    END
  END vmr[268]
  PIN vmr[269]
    DIRECTION INPUT ;
    USE SIGNAL ;
    PORT
      LAYER M5 ;
        RECT  54.192 86.316 54.216 86.4 ;
    END
  END vmr[269]
  PIN vmr[26]
    DIRECTION INPUT ;
    USE SIGNAL ;
    PORT
      LAYER M3 ;
        RECT  6.3 86.362 6.318 86.4 ;
    END
  END vmr[26]
  PIN vmr[270]
    DIRECTION INPUT ;
    USE SIGNAL ;
    PORT
      LAYER M3 ;
        RECT  54.396 86.362 54.414 86.4 ;
    END
  END vmr[270]
  PIN vmr[271]
    DIRECTION INPUT ;
    USE SIGNAL ;
    PORT
      LAYER M5 ;
        RECT  54.576 86.316 54.6 86.4 ;
    END
  END vmr[271]
  PIN vmr[272]
    DIRECTION INPUT ;
    USE SIGNAL ;
    PORT
      LAYER M3 ;
        RECT  54.792 86.362 54.81 86.4 ;
    END
  END vmr[272]
  PIN vmr[273]
    DIRECTION INPUT ;
    USE SIGNAL ;
    PORT
      LAYER M5 ;
        RECT  54.96 86.316 54.984 86.4 ;
    END
  END vmr[273]
  PIN vmr[27]
    DIRECTION INPUT ;
    USE SIGNAL ;
    PORT
      LAYER M5 ;
        RECT  6.48 86.316 6.504 86.4 ;
    END
  END vmr[27]
  PIN vmr[28]
    DIRECTION INPUT ;
    USE SIGNAL ;
    PORT
      LAYER M3 ;
        RECT  6.696 86.362 6.714 86.4 ;
    END
  END vmr[28]
  PIN vmr[29]
    DIRECTION INPUT ;
    USE SIGNAL ;
    PORT
      LAYER M5 ;
        RECT  6.864 86.316 6.888 86.4 ;
    END
  END vmr[29]
  PIN vmr[2]
    DIRECTION INPUT ;
    USE SIGNAL ;
    PORT
      LAYER M3 ;
        RECT  1.548 86.362 1.566 86.4 ;
    END
  END vmr[2]
  PIN vmr[30]
    DIRECTION INPUT ;
    USE SIGNAL ;
    PORT
      LAYER M3 ;
        RECT  7.092 86.362 7.11 86.4 ;
    END
  END vmr[30]
  PIN vmr[31]
    DIRECTION INPUT ;
    USE SIGNAL ;
    PORT
      LAYER M5 ;
        RECT  7.296 86.316 7.32 86.4 ;
    END
  END vmr[31]
  PIN vmr[32]
    DIRECTION INPUT ;
    USE SIGNAL ;
    PORT
      LAYER M3 ;
        RECT  7.488 86.362 7.506 86.4 ;
    END
  END vmr[32]
  PIN vmr[33]
    DIRECTION INPUT ;
    USE SIGNAL ;
    PORT
      LAYER M5 ;
        RECT  7.728 86.316 7.752 86.4 ;
    END
  END vmr[33]
  PIN vmr[34]
    DIRECTION INPUT ;
    USE SIGNAL ;
    PORT
      LAYER M3 ;
        RECT  7.884 86.362 7.902 86.4 ;
    END
  END vmr[34]
  PIN vmr[35]
    DIRECTION INPUT ;
    USE SIGNAL ;
    PORT
      LAYER M5 ;
        RECT  8.064 86.316 8.088 86.4 ;
    END
  END vmr[35]
  PIN vmr[36]
    DIRECTION INPUT ;
    USE SIGNAL ;
    PORT
      LAYER M3 ;
        RECT  8.28 86.362 8.298 86.4 ;
    END
  END vmr[36]
  PIN vmr[37]
    DIRECTION INPUT ;
    USE SIGNAL ;
    PORT
      LAYER M5 ;
        RECT  8.448 86.316 8.472 86.4 ;
    END
  END vmr[37]
  PIN vmr[38]
    DIRECTION INPUT ;
    USE SIGNAL ;
    PORT
      LAYER M3 ;
        RECT  8.676 86.362 8.694 86.4 ;
    END
  END vmr[38]
  PIN vmr[39]
    DIRECTION INPUT ;
    USE SIGNAL ;
    PORT
      LAYER M5 ;
        RECT  8.832 86.316 8.856 86.4 ;
    END
  END vmr[39]
  PIN vmr[3]
    DIRECTION INPUT ;
    USE SIGNAL ;
    PORT
      LAYER M5 ;
        RECT  1.776 86.316 1.8 86.4 ;
    END
  END vmr[3]
  PIN vmr[40]
    DIRECTION INPUT ;
    USE SIGNAL ;
    PORT
      LAYER M3 ;
        RECT  9.036 86.362 9.054 86.4 ;
    END
  END vmr[40]
  PIN vmr[41]
    DIRECTION INPUT ;
    USE SIGNAL ;
    PORT
      LAYER M5 ;
        RECT  9.264 86.316 9.288 86.4 ;
    END
  END vmr[41]
  PIN vmr[42]
    DIRECTION INPUT ;
    USE SIGNAL ;
    PORT
      LAYER M3 ;
        RECT  9.432 86.362 9.45 86.4 ;
    END
  END vmr[42]
  PIN vmr[43]
    DIRECTION INPUT ;
    USE SIGNAL ;
    PORT
      LAYER M5 ;
        RECT  9.648 86.316 9.672 86.4 ;
    END
  END vmr[43]
  PIN vmr[44]
    DIRECTION INPUT ;
    USE SIGNAL ;
    PORT
      LAYER M3 ;
        RECT  9.828 86.362 9.846 86.4 ;
    END
  END vmr[44]
  PIN vmr[45]
    DIRECTION INPUT ;
    USE SIGNAL ;
    PORT
      LAYER M5 ;
        RECT  10.032 86.316 10.056 86.4 ;
    END
  END vmr[45]
  PIN vmr[46]
    DIRECTION INPUT ;
    USE SIGNAL ;
    PORT
      LAYER M3 ;
        RECT  10.224 86.362 10.242 86.4 ;
    END
  END vmr[46]
  PIN vmr[47]
    DIRECTION INPUT ;
    USE SIGNAL ;
    PORT
      LAYER M5 ;
        RECT  10.416 86.316 10.44 86.4 ;
    END
  END vmr[47]
  PIN vmr[48]
    DIRECTION INPUT ;
    USE SIGNAL ;
    PORT
      LAYER M3 ;
        RECT  10.62 86.362 10.638 86.4 ;
    END
  END vmr[48]
  PIN vmr[49]
    DIRECTION INPUT ;
    USE SIGNAL ;
    PORT
      LAYER M5 ;
        RECT  10.8 86.316 10.824 86.4 ;
    END
  END vmr[49]
  PIN vmr[4]
    DIRECTION INPUT ;
    USE SIGNAL ;
    PORT
      LAYER M3 ;
        RECT  1.944 86.362 1.962 86.4 ;
    END
  END vmr[4]
  PIN vmr[50]
    DIRECTION INPUT ;
    USE SIGNAL ;
    PORT
      LAYER M3 ;
        RECT  11.016 86.362 11.034 86.4 ;
    END
  END vmr[50]
  PIN vmr[51]
    DIRECTION INPUT ;
    USE SIGNAL ;
    PORT
      LAYER M5 ;
        RECT  11.28 86.316 11.304 86.4 ;
    END
  END vmr[51]
  PIN vmr[52]
    DIRECTION INPUT ;
    USE SIGNAL ;
    PORT
      LAYER M3 ;
        RECT  11.412 86.362 11.43 86.4 ;
    END
  END vmr[52]
  PIN vmr[53]
    DIRECTION INPUT ;
    USE SIGNAL ;
    PORT
      LAYER M5 ;
        RECT  11.616 86.316 11.64 86.4 ;
    END
  END vmr[53]
  PIN vmr[54]
    DIRECTION INPUT ;
    USE SIGNAL ;
    PORT
      LAYER M3 ;
        RECT  11.808 86.362 11.826 86.4 ;
    END
  END vmr[54]
  PIN vmr[55]
    DIRECTION INPUT ;
    USE SIGNAL ;
    PORT
      LAYER M5 ;
        RECT  12 86.316 12.024 86.4 ;
    END
  END vmr[55]
  PIN vmr[56]
    DIRECTION INPUT ;
    USE SIGNAL ;
    PORT
      LAYER M3 ;
        RECT  12.204 86.362 12.222 86.4 ;
    END
  END vmr[56]
  PIN vmr[57]
    DIRECTION INPUT ;
    USE SIGNAL ;
    PORT
      LAYER M5 ;
        RECT  12.384 86.316 12.408 86.4 ;
    END
  END vmr[57]
  PIN vmr[58]
    DIRECTION INPUT ;
    USE SIGNAL ;
    PORT
      LAYER M3 ;
        RECT  12.6 86.362 12.618 86.4 ;
    END
  END vmr[58]
  PIN vmr[59]
    DIRECTION INPUT ;
    USE SIGNAL ;
    PORT
      LAYER M5 ;
        RECT  12.864 86.316 12.888 86.4 ;
    END
  END vmr[59]
  PIN vmr[5]
    DIRECTION INPUT ;
    USE SIGNAL ;
    PORT
      LAYER M5 ;
        RECT  2.16 86.316 2.184 86.4 ;
    END
  END vmr[5]
  PIN vmr[60]
    DIRECTION INPUT ;
    USE SIGNAL ;
    PORT
      LAYER M3 ;
        RECT  12.996 86.362 13.014 86.4 ;
    END
  END vmr[60]
  PIN vmr[61]
    DIRECTION INPUT ;
    USE SIGNAL ;
    PORT
      LAYER M5 ;
        RECT  13.2 86.316 13.224 86.4 ;
    END
  END vmr[61]
  PIN vmr[62]
    DIRECTION INPUT ;
    USE SIGNAL ;
    PORT
      LAYER M3 ;
        RECT  13.392 86.362 13.41 86.4 ;
    END
  END vmr[62]
  PIN vmr[63]
    DIRECTION INPUT ;
    USE SIGNAL ;
    PORT
      LAYER M5 ;
        RECT  13.584 86.316 13.608 86.4 ;
    END
  END vmr[63]
  PIN vmr[64]
    DIRECTION INPUT ;
    USE SIGNAL ;
    PORT
      LAYER M3 ;
        RECT  13.788 86.362 13.806 86.4 ;
    END
  END vmr[64]
  PIN vmr[65]
    DIRECTION INPUT ;
    USE SIGNAL ;
    PORT
      LAYER M5 ;
        RECT  13.968 86.316 13.992 86.4 ;
    END
  END vmr[65]
  PIN vmr[66]
    DIRECTION INPUT ;
    USE SIGNAL ;
    PORT
      LAYER M3 ;
        RECT  14.184 86.362 14.202 86.4 ;
    END
  END vmr[66]
  PIN vmr[67]
    DIRECTION INPUT ;
    USE SIGNAL ;
    PORT
      LAYER M5 ;
        RECT  14.352 86.316 14.376 86.4 ;
    END
  END vmr[67]
  PIN vmr[68]
    DIRECTION INPUT ;
    USE SIGNAL ;
    PORT
      LAYER M3 ;
        RECT  14.616 86.362 14.634 86.4 ;
    END
  END vmr[68]
  PIN vmr[69]
    DIRECTION INPUT ;
    USE SIGNAL ;
    PORT
      LAYER M5 ;
        RECT  14.784 86.316 14.808 86.4 ;
    END
  END vmr[69]
  PIN vmr[6]
    DIRECTION INPUT ;
    USE SIGNAL ;
    PORT
      LAYER M3 ;
        RECT  2.34 86.362 2.358 86.4 ;
    END
  END vmr[6]
  PIN vmr[70]
    DIRECTION INPUT ;
    USE SIGNAL ;
    PORT
      LAYER M3 ;
        RECT  14.976 86.362 14.994 86.4 ;
    END
  END vmr[70]
  PIN vmr[71]
    DIRECTION INPUT ;
    USE SIGNAL ;
    PORT
      LAYER M5 ;
        RECT  15.168 86.316 15.192 86.4 ;
    END
  END vmr[71]
  PIN vmr[72]
    DIRECTION INPUT ;
    USE SIGNAL ;
    PORT
      LAYER M3 ;
        RECT  15.372 86.362 15.39 86.4 ;
    END
  END vmr[72]
  PIN vmr[73]
    DIRECTION INPUT ;
    USE SIGNAL ;
    PORT
      LAYER M5 ;
        RECT  15.552 86.316 15.576 86.4 ;
    END
  END vmr[73]
  PIN vmr[74]
    DIRECTION INPUT ;
    USE SIGNAL ;
    PORT
      LAYER M3 ;
        RECT  15.768 86.362 15.786 86.4 ;
    END
  END vmr[74]
  PIN vmr[75]
    DIRECTION INPUT ;
    USE SIGNAL ;
    PORT
      LAYER M5 ;
        RECT  15.936 86.316 15.96 86.4 ;
    END
  END vmr[75]
  PIN vmr[76]
    DIRECTION INPUT ;
    USE SIGNAL ;
    PORT
      LAYER M3 ;
        RECT  16.2 86.362 16.218 86.4 ;
    END
  END vmr[76]
  PIN vmr[77]
    DIRECTION INPUT ;
    USE SIGNAL ;
    PORT
      LAYER M5 ;
        RECT  16.368 86.316 16.392 86.4 ;
    END
  END vmr[77]
  PIN vmr[78]
    DIRECTION INPUT ;
    USE SIGNAL ;
    PORT
      LAYER M3 ;
        RECT  16.56 86.362 16.578 86.4 ;
    END
  END vmr[78]
  PIN vmr[79]
    DIRECTION INPUT ;
    USE SIGNAL ;
    PORT
      LAYER M5 ;
        RECT  16.752 86.316 16.776 86.4 ;
    END
  END vmr[79]
  PIN vmr[7]
    DIRECTION INPUT ;
    USE SIGNAL ;
    PORT
      LAYER M5 ;
        RECT  2.544 86.316 2.568 86.4 ;
    END
  END vmr[7]
  PIN vmr[80]
    DIRECTION INPUT ;
    USE SIGNAL ;
    PORT
      LAYER M3 ;
        RECT  16.92 86.362 16.938 86.4 ;
    END
  END vmr[80]
  PIN vmr[81]
    DIRECTION INPUT ;
    USE SIGNAL ;
    PORT
      LAYER M5 ;
        RECT  17.136 86.316 17.16 86.4 ;
    END
  END vmr[81]
  PIN vmr[82]
    DIRECTION INPUT ;
    USE SIGNAL ;
    PORT
      LAYER M3 ;
        RECT  17.316 86.362 17.334 86.4 ;
    END
  END vmr[82]
  PIN vmr[83]
    DIRECTION INPUT ;
    USE SIGNAL ;
    PORT
      LAYER M5 ;
        RECT  17.52 86.316 17.544 86.4 ;
    END
  END vmr[83]
  PIN vmr[84]
    DIRECTION INPUT ;
    USE SIGNAL ;
    PORT
      LAYER M3 ;
        RECT  17.712 86.362 17.73 86.4 ;
    END
  END vmr[84]
  PIN vmr[85]
    DIRECTION INPUT ;
    USE SIGNAL ;
    PORT
      LAYER M5 ;
        RECT  17.952 86.316 17.976 86.4 ;
    END
  END vmr[85]
  PIN vmr[86]
    DIRECTION INPUT ;
    USE SIGNAL ;
    PORT
      LAYER M3 ;
        RECT  18.108 86.362 18.126 86.4 ;
    END
  END vmr[86]
  PIN vmr[87]
    DIRECTION INPUT ;
    USE SIGNAL ;
    PORT
      LAYER M5 ;
        RECT  18.336 86.316 18.36 86.4 ;
    END
  END vmr[87]
  PIN vmr[88]
    DIRECTION INPUT ;
    USE SIGNAL ;
    PORT
      LAYER M3 ;
        RECT  18.504 86.362 18.522 86.4 ;
    END
  END vmr[88]
  PIN vmr[89]
    DIRECTION INPUT ;
    USE SIGNAL ;
    PORT
      LAYER M5 ;
        RECT  18.72 86.316 18.744 86.4 ;
    END
  END vmr[89]
  PIN vmr[8]
    DIRECTION INPUT ;
    USE SIGNAL ;
    PORT
      LAYER M3 ;
        RECT  2.772 86.362 2.79 86.4 ;
    END
  END vmr[8]
  PIN vmr[90]
    DIRECTION INPUT ;
    USE SIGNAL ;
    PORT
      LAYER M3 ;
        RECT  18.9 86.362 18.918 86.4 ;
    END
  END vmr[90]
  PIN vmr[91]
    DIRECTION INPUT ;
    USE SIGNAL ;
    PORT
      LAYER M5 ;
        RECT  19.104 86.316 19.128 86.4 ;
    END
  END vmr[91]
  PIN vmr[92]
    DIRECTION INPUT ;
    USE SIGNAL ;
    PORT
      LAYER M3 ;
        RECT  19.296 86.362 19.314 86.4 ;
    END
  END vmr[92]
  PIN vmr[93]
    DIRECTION INPUT ;
    USE SIGNAL ;
    PORT
      LAYER M5 ;
        RECT  19.488 86.316 19.512 86.4 ;
    END
  END vmr[93]
  PIN vmr[94]
    DIRECTION INPUT ;
    USE SIGNAL ;
    PORT
      LAYER M3 ;
        RECT  19.728 86.362 19.746 86.4 ;
    END
  END vmr[94]
  PIN vmr[95]
    DIRECTION INPUT ;
    USE SIGNAL ;
    PORT
      LAYER M5 ;
        RECT  19.872 86.316 19.896 86.4 ;
    END
  END vmr[95]
  PIN vmr[96]
    DIRECTION INPUT ;
    USE SIGNAL ;
    PORT
      LAYER M3 ;
        RECT  20.088 86.362 20.106 86.4 ;
    END
  END vmr[96]
  PIN vmr[97]
    DIRECTION INPUT ;
    USE SIGNAL ;
    PORT
      LAYER M5 ;
        RECT  20.304 86.316 20.328 86.4 ;
    END
  END vmr[97]
  PIN vmr[98]
    DIRECTION INPUT ;
    USE SIGNAL ;
    PORT
      LAYER M3 ;
        RECT  20.484 86.362 20.502 86.4 ;
    END
  END vmr[98]
  PIN vmr[99]
    DIRECTION INPUT ;
    USE SIGNAL ;
    PORT
      LAYER M5 ;
        RECT  20.688 86.316 20.712 86.4 ;
    END
  END vmr[99]
  PIN vmr[9]
    DIRECTION INPUT ;
    USE SIGNAL ;
    PORT
      LAYER M5 ;
        RECT  2.976 86.316 3 86.4 ;
    END
  END vmr[9]
  PIN VDD
    DIRECTION INOUT ;
    USE POWER ;
    PORT
      LAYER M5 ;
        RECT  51.192 2.151 51.312 84.249 ;
        RECT  45.792 2.151 45.912 84.249 ;
        RECT  40.392 2.151 40.512 84.249 ;
        RECT  34.992 2.151 35.112 84.249 ;
        RECT  29.592 2.151 29.712 84.249 ;
        RECT  24.192 2.151 24.312 84.249 ;
        RECT  18.792 2.151 18.912 84.249 ;
        RECT  13.392 2.151 13.512 84.249 ;
        RECT  7.992 2.151 8.112 84.249 ;
        RECT  2.592 2.151 2.712 84.249 ;
    END
  END VDD
  PIN VSS
    DIRECTION INOUT ;
    USE GROUND ;
    PORT
      LAYER M5 ;
        RECT  51 2.137 51.12 84.263 ;
        RECT  45.6 2.137 45.72 84.263 ;
        RECT  40.2 2.137 40.32 84.263 ;
        RECT  34.8 2.137 34.92 84.263 ;
        RECT  29.4 2.137 29.52 84.263 ;
        RECT  24 2.137 24.12 84.263 ;
        RECT  18.6 2.137 18.72 84.263 ;
        RECT  13.2 2.137 13.32 84.263 ;
        RECT  7.8 2.137 7.92 84.263 ;
        RECT  2.4 2.137 2.52 84.263 ;
    END
  END VSS
  # OT_OBS_CLOSED layer=M5 d_um=1.536 added=54
  OBS
    LAYER RVTN ;
     RECT  2.16 2.16 54 2.295 ;
     RECT  2.16 2.565 54 2.835 ;
     RECT  2.16 3.105 54 3.375 ;
     RECT  2.16 3.645 54 3.915 ;
     RECT  2.16 4.185 54 4.455 ;
     RECT  2.16 4.725 54 4.995 ;
     RECT  2.16 5.265 54 5.535 ;
     RECT  2.16 5.805 54 6.075 ;
     RECT  2.16 6.345 54 6.615 ;
     RECT  2.16 6.885 54 7.155 ;
     RECT  2.16 7.425 54 7.695 ;
     RECT  2.16 7.965 54 8.235 ;
     RECT  2.16 8.505 54 8.775 ;
     RECT  2.16 9.045 54 9.315 ;
     RECT  2.16 9.585 54 9.855 ;
     RECT  2.16 10.125 54 10.395 ;
     RECT  2.16 10.665 54 10.935 ;
     RECT  2.16 11.205 54 11.475 ;
     RECT  2.16 11.745 54 12.015 ;
     RECT  2.16 12.285 54 12.555 ;
     RECT  2.16 12.825 54 13.095 ;
     RECT  2.16 13.365 54 13.635 ;
     RECT  2.16 13.905 54 14.175 ;
     RECT  2.16 14.445 54 14.715 ;
     RECT  2.16 14.985 54 15.255 ;
     RECT  2.16 15.525 54 15.795 ;
     RECT  2.16 16.065 54 16.335 ;
     RECT  2.16 16.605 54 16.875 ;
     RECT  2.16 17.145 54 17.415 ;
     RECT  2.16 17.685 54 17.955 ;
     RECT  2.16 18.225 54 18.495 ;
     RECT  2.16 18.765 54 19.035 ;
     RECT  2.16 19.305 54 19.575 ;
     RECT  2.16 19.845 54 20.115 ;
     RECT  2.16 20.385 54 20.655 ;
     RECT  2.16 20.925 54 21.195 ;
     RECT  2.16 21.465 54 21.735 ;
     RECT  2.16 22.005 54 22.275 ;
     RECT  2.16 22.545 54 22.815 ;
     RECT  2.16 23.085 54 23.355 ;
     RECT  2.16 23.625 54 23.895 ;
     RECT  2.16 24.165 54 24.435 ;
     RECT  2.16 24.705 54 24.975 ;
     RECT  2.16 25.245 54 25.515 ;
     RECT  2.16 25.785 54 26.055 ;
     RECT  2.16 26.325 54 26.595 ;
     RECT  2.16 26.865 54 27.135 ;
     RECT  2.16 27.405 54 27.675 ;
     RECT  2.16 27.945 54 28.215 ;
     RECT  2.16 28.485 54 28.755 ;
     RECT  2.16 29.025 54 29.295 ;
     RECT  2.16 29.565 54 29.835 ;
     RECT  2.16 30.105 54 30.375 ;
     RECT  2.16 30.645 54 30.915 ;
     RECT  2.16 31.185 54 31.455 ;
     RECT  2.16 31.725 54 31.995 ;
     RECT  2.16 32.265 54 32.535 ;
     RECT  2.16 32.805 54 33.075 ;
     RECT  2.16 33.345 54 33.615 ;
     RECT  2.16 33.885 54 34.155 ;
     RECT  2.16 34.425 54 34.695 ;
     RECT  2.16 34.965 54 35.235 ;
     RECT  2.16 35.505 54 35.775 ;
     RECT  2.16 36.045 54 36.315 ;
     RECT  2.16 36.585 54 36.855 ;
     RECT  2.16 37.125 54 37.395 ;
     RECT  2.16 37.665 54 37.935 ;
     RECT  2.16 38.205 54 38.475 ;
     RECT  2.16 38.745 54 39.015 ;
     RECT  2.16 39.285 54 39.555 ;
     RECT  2.16 39.825 54 40.095 ;
     RECT  2.16 40.365 54 40.635 ;
     RECT  2.16 40.905 54 41.175 ;
     RECT  2.16 41.445 54 41.715 ;
     RECT  2.16 41.985 54 42.255 ;
     RECT  2.16 42.525 54 42.795 ;
     RECT  2.16 43.065 54 43.335 ;
     RECT  2.16 43.605 54 43.875 ;
     RECT  2.16 44.145 54 44.415 ;
     RECT  2.16 44.685 54 44.955 ;
     RECT  2.16 45.225 54 45.495 ;
     RECT  2.16 45.765 54 46.035 ;
     RECT  2.16 46.305 54 46.575 ;
     RECT  2.16 46.845 54 47.115 ;
     RECT  2.16 47.385 54 47.655 ;
     RECT  2.16 47.925 54 48.195 ;
     RECT  2.16 48.465 54 48.735 ;
     RECT  2.16 49.005 54 49.275 ;
     RECT  2.16 49.545 54 49.815 ;
     RECT  2.16 50.085 54 50.355 ;
     RECT  2.16 50.625 54 50.895 ;
     RECT  2.16 51.165 54 51.435 ;
     RECT  2.16 51.705 54 51.975 ;
     RECT  2.16 52.245 54 52.515 ;
     RECT  2.16 52.785 54 53.055 ;
     RECT  2.16 53.325 54 53.595 ;
     RECT  2.16 53.865 54 54.135 ;
     RECT  2.16 54.405 54 54.675 ;
     RECT  2.16 54.945 54 55.215 ;
     RECT  2.16 55.485 54 55.755 ;
     RECT  2.16 56.025 54 56.295 ;
     RECT  2.16 56.565 54 56.835 ;
     RECT  2.16 57.105 54 57.375 ;
     RECT  2.16 57.645 54 57.915 ;
     RECT  2.16 58.185 54 58.455 ;
     RECT  2.16 58.725 54 58.995 ;
     RECT  2.16 59.265 54 59.535 ;
     RECT  2.16 59.805 54 60.075 ;
     RECT  2.16 60.345 54 60.615 ;
     RECT  2.16 60.885 54 61.155 ;
     RECT  2.16 61.425 54 61.695 ;
     RECT  2.16 61.965 54 62.235 ;
     RECT  2.16 62.505 54 62.775 ;
     RECT  2.16 63.045 54 63.315 ;
     RECT  2.16 63.585 54 63.855 ;
     RECT  2.16 64.125 54 64.395 ;
     RECT  2.16 64.665 54 64.935 ;
     RECT  2.16 65.205 54 65.475 ;
     RECT  2.16 65.745 54 66.015 ;
     RECT  2.16 66.285 54 66.555 ;
     RECT  2.16 66.825 54 67.095 ;
     RECT  2.16 67.365 54 67.635 ;
     RECT  2.16 67.905 54 68.175 ;
     RECT  2.16 68.445 54 68.715 ;
     RECT  2.16 68.985 54 69.255 ;
     RECT  2.16 69.525 54 69.795 ;
     RECT  2.16 70.065 54 70.335 ;
     RECT  2.16 70.605 54 70.875 ;
     RECT  2.16 71.145 54 71.415 ;
     RECT  2.16 71.685 54 71.955 ;
     RECT  2.16 72.225 54 72.495 ;
     RECT  2.16 72.765 54 73.035 ;
     RECT  2.16 73.305 54 73.575 ;
     RECT  2.16 73.845 54 74.115 ;
     RECT  2.16 74.385 54 74.655 ;
     RECT  2.16 74.925 54 75.195 ;
     RECT  2.16 75.465 54 75.735 ;
     RECT  2.16 76.005 54 76.275 ;
     RECT  2.16 76.545 54 76.815 ;
     RECT  2.16 77.085 54 77.355 ;
     RECT  2.16 77.625 54 77.895 ;
     RECT  2.16 78.165 54 78.435 ;
     RECT  2.16 78.705 54 78.975 ;
     RECT  2.16 79.245 54 79.515 ;
     RECT  2.16 79.785 54 80.055 ;
     RECT  2.16 80.325 54 80.595 ;
     RECT  2.16 80.865 54 81.135 ;
     RECT  2.16 81.405 54 81.675 ;
     RECT  2.16 81.945 54 82.215 ;
     RECT  2.16 82.485 54 82.755 ;
     RECT  2.16 83.025 54 83.295 ;
     RECT  2.16 83.565 54 83.835 ;
     RECT  2.16 84.105 54 84.24 ;
    LAYER RVTP ;
     RECT  2.16 2.295 54 2.565 ;
     RECT  2.16 2.835 54 3.105 ;
     RECT  2.16 3.375 54 3.645 ;
     RECT  2.16 3.915 54 4.185 ;
     RECT  2.16 4.455 54 4.725 ;
     RECT  2.16 4.995 54 5.265 ;
     RECT  2.16 5.535 54 5.805 ;
     RECT  2.16 6.075 54 6.345 ;
     RECT  2.16 6.615 54 6.885 ;
     RECT  2.16 7.155 54 7.425 ;
     RECT  2.16 7.695 54 7.965 ;
     RECT  2.16 8.235 54 8.505 ;
     RECT  2.16 8.775 54 9.045 ;
     RECT  2.16 9.315 54 9.585 ;
     RECT  2.16 9.855 54 10.125 ;
     RECT  2.16 10.395 54 10.665 ;
     RECT  2.16 10.935 54 11.205 ;
     RECT  2.16 11.475 54 11.745 ;
     RECT  2.16 12.015 54 12.285 ;
     RECT  2.16 12.555 54 12.825 ;
     RECT  2.16 13.095 54 13.365 ;
     RECT  2.16 13.635 54 13.905 ;
     RECT  2.16 14.175 54 14.445 ;
     RECT  2.16 14.715 54 14.985 ;
     RECT  2.16 15.255 54 15.525 ;
     RECT  2.16 15.795 54 16.065 ;
     RECT  2.16 16.335 54 16.605 ;
     RECT  2.16 16.875 54 17.145 ;
     RECT  2.16 17.415 54 17.685 ;
     RECT  2.16 17.955 54 18.225 ;
     RECT  2.16 18.495 54 18.765 ;
     RECT  2.16 19.035 54 19.305 ;
     RECT  2.16 19.575 54 19.845 ;
     RECT  2.16 20.115 54 20.385 ;
     RECT  2.16 20.655 54 20.925 ;
     RECT  2.16 21.195 54 21.465 ;
     RECT  2.16 21.735 54 22.005 ;
     RECT  2.16 22.275 54 22.545 ;
     RECT  2.16 22.815 54 23.085 ;
     RECT  2.16 23.355 54 23.625 ;
     RECT  2.16 23.895 54 24.165 ;
     RECT  2.16 24.435 54 24.705 ;
     RECT  2.16 24.975 54 25.245 ;
     RECT  2.16 25.515 54 25.785 ;
     RECT  2.16 26.055 54 26.325 ;
     RECT  2.16 26.595 54 26.865 ;
     RECT  2.16 27.135 54 27.405 ;
     RECT  2.16 27.675 54 27.945 ;
     RECT  2.16 28.215 54 28.485 ;
     RECT  2.16 28.755 54 29.025 ;
     RECT  2.16 29.295 54 29.565 ;
     RECT  2.16 29.835 54 30.105 ;
     RECT  2.16 30.375 54 30.645 ;
     RECT  2.16 30.915 54 31.185 ;
     RECT  2.16 31.455 54 31.725 ;
     RECT  2.16 31.995 54 32.265 ;
     RECT  2.16 32.535 54 32.805 ;
     RECT  2.16 33.075 54 33.345 ;
     RECT  2.16 33.615 54 33.885 ;
     RECT  2.16 34.155 54 34.425 ;
     RECT  2.16 34.695 54 34.965 ;
     RECT  2.16 35.235 54 35.505 ;
     RECT  2.16 35.775 54 36.045 ;
     RECT  2.16 36.315 54 36.585 ;
     RECT  2.16 36.855 54 37.125 ;
     RECT  2.16 37.395 54 37.665 ;
     RECT  2.16 37.935 54 38.205 ;
     RECT  2.16 38.475 54 38.745 ;
     RECT  2.16 39.015 54 39.285 ;
     RECT  2.16 39.555 54 39.825 ;
     RECT  2.16 40.095 54 40.365 ;
     RECT  2.16 40.635 54 40.905 ;
     RECT  2.16 41.175 54 41.445 ;
     RECT  2.16 41.715 54 41.985 ;
     RECT  2.16 42.255 54 42.525 ;
     RECT  2.16 42.795 54 43.065 ;
     RECT  2.16 43.335 54 43.605 ;
     RECT  2.16 43.875 54 44.145 ;
     RECT  2.16 44.415 54 44.685 ;
     RECT  2.16 44.955 54 45.225 ;
     RECT  2.16 45.495 54 45.765 ;
     RECT  2.16 46.035 54 46.305 ;
     RECT  2.16 46.575 54 46.845 ;
     RECT  2.16 47.115 54 47.385 ;
     RECT  2.16 47.655 54 47.925 ;
     RECT  2.16 48.195 54 48.465 ;
     RECT  2.16 48.735 54 49.005 ;
     RECT  2.16 49.275 54 49.545 ;
     RECT  2.16 49.815 54 50.085 ;
     RECT  2.16 50.355 54 50.625 ;
     RECT  2.16 50.895 54 51.165 ;
     RECT  2.16 51.435 54 51.705 ;
     RECT  2.16 51.975 54 52.245 ;
     RECT  2.16 52.515 54 52.785 ;
     RECT  2.16 53.055 54 53.325 ;
     RECT  2.16 53.595 54 53.865 ;
     RECT  2.16 54.135 54 54.405 ;
     RECT  2.16 54.675 54 54.945 ;
     RECT  2.16 55.215 54 55.485 ;
     RECT  2.16 55.755 54 56.025 ;
     RECT  2.16 56.295 54 56.565 ;
     RECT  2.16 56.835 54 57.105 ;
     RECT  2.16 57.375 54 57.645 ;
     RECT  2.16 57.915 54 58.185 ;
     RECT  2.16 58.455 54 58.725 ;
     RECT  2.16 58.995 54 59.265 ;
     RECT  2.16 59.535 54 59.805 ;
     RECT  2.16 60.075 54 60.345 ;
     RECT  2.16 60.615 54 60.885 ;
     RECT  2.16 61.155 54 61.425 ;
     RECT  2.16 61.695 54 61.965 ;
     RECT  2.16 62.235 54 62.505 ;
     RECT  2.16 62.775 54 63.045 ;
     RECT  2.16 63.315 54 63.585 ;
     RECT  2.16 63.855 54 64.125 ;
     RECT  2.16 64.395 54 64.665 ;
     RECT  2.16 64.935 54 65.205 ;
     RECT  2.16 65.475 54 65.745 ;
     RECT  2.16 66.015 54 66.285 ;
     RECT  2.16 66.555 54 66.825 ;
     RECT  2.16 67.095 54 67.365 ;
     RECT  2.16 67.635 54 67.905 ;
     RECT  2.16 68.175 54 68.445 ;
     RECT  2.16 68.715 54 68.985 ;
     RECT  2.16 69.255 54 69.525 ;
     RECT  2.16 69.795 54 70.065 ;
     RECT  2.16 70.335 54 70.605 ;
     RECT  2.16 70.875 54 71.145 ;
     RECT  2.16 71.415 54 71.685 ;
     RECT  2.16 71.955 54 72.225 ;
     RECT  2.16 72.495 54 72.765 ;
     RECT  2.16 73.035 54 73.305 ;
     RECT  2.16 73.575 54 73.845 ;
     RECT  2.16 74.115 54 74.385 ;
     RECT  2.16 74.655 54 74.925 ;
     RECT  2.16 75.195 54 75.465 ;
     RECT  2.16 75.735 54 76.005 ;
     RECT  2.16 76.275 54 76.545 ;
     RECT  2.16 76.815 54 77.085 ;
     RECT  2.16 77.355 54 77.625 ;
     RECT  2.16 77.895 54 78.165 ;
     RECT  2.16 78.435 54 78.705 ;
     RECT  2.16 78.975 54 79.245 ;
     RECT  2.16 79.515 54 79.785 ;
     RECT  2.16 80.055 54 80.325 ;
     RECT  2.16 80.595 54 80.865 ;
     RECT  2.16 81.135 54 81.405 ;
     RECT  2.16 81.675 54 81.945 ;
     RECT  2.16 82.215 54 82.485 ;
     RECT  2.16 82.755 54 83.025 ;
     RECT  2.16 83.295 54 83.565 ;
     RECT  2.16 83.835 54 84.105 ;
    LAYER M1 ;
     RECT  2.16 2.151 54 84.249 ;
    LAYER M2 ;
     RECT  1.147 83.106 1.471 83.124 ;
     RECT  1.183 80.532 1.543 80.55 ;
     RECT  1.471 82.458 1.687 83.124 ;
     RECT  1.687 78.642 1.759 78.66 ;
     RECT  1.687 82.458 1.759 83.322 ;
     RECT  1.759 82.458 1.831 83.592 ;
     RECT  1.831 73.116 1.867 73.134 ;
     RECT  1.759 78.246 1.867 78.66 ;
     RECT  1.903 75.132 2.011 75.15 ;
     RECT  1.543 79.992 2.047 80.55 ;
     RECT  1.831 81.756 2.047 83.592 ;
     RECT  1.939 77.256 2.083 77.274 ;
     RECT  2.047 79.992 2.083 83.592 ;
     RECT  2.011 75.096 2.119 75.15 ;
     RECT  1.867 78.246 2.155 79.074 ;
     RECT  2.083 79.992 2.155 84.06 ;
     RECT  2.155 48.276 2.16 48.294 ;
     RECT  0.103 64.332 2.16 64.35 ;
     RECT  1.939 69.768 2.16 69.786 ;
     RECT  1.975 71.964 2.16 71.982 ;
     RECT  1.867 73.116 2.16 73.404 ;
     RECT  2.119 75.096 2.16 75.222 ;
     RECT  2.083 76.896 2.16 77.274 ;
     RECT  2.155 78.21 2.16 84.06 ;
     RECT  2.16 2.151 2.299 84.249 ;
     RECT  2.299 2.151 2.335 84.33 ;
     RECT  2.371 86.346 2.795 86.364 ;
     RECT  2.335 2.151 3.307 84.402 ;
     RECT  3.847 86.346 3.947 86.364 ;
     RECT  4.963 86.346 5.531 86.364 ;
     RECT  3.307 2.151 6.395 84.906 ;
     RECT  6.907 86.274 7.159 86.292 ;
     RECT  7.159 86.274 7.259 86.364 ;
     RECT  6.395 2.151 7.483 84.249 ;
     RECT  7.483 2.151 7.763 84.906 ;
     RECT  7.763 2.151 7.907 84.834 ;
     RECT  7.259 86.346 8.167 86.364 ;
     RECT  8.167 86.274 8.303 86.364 ;
     RECT  8.303 86.346 8.447 86.364 ;
     RECT  7.907 2.151 8.815 84.33 ;
     RECT  8.815 2.151 8.951 84.906 ;
     RECT  10.147 86.346 12.227 86.364 ;
     RECT  8.951 2.151 12.883 84.249 ;
     RECT  12.883 2.151 13.171 84.438 ;
     RECT  13.171 2.151 13.415 84.474 ;
     RECT  13.415 2.151 14.467 84.294 ;
     RECT  14.467 2.151 14.639 84.87 ;
     RECT  13.711 86.346 14.819 86.364 ;
     RECT  14.639 2.151 16.411 84.249 ;
     RECT  16.411 2.151 16.655 84.906 ;
     RECT  16.655 2.151 16.691 84.834 ;
     RECT  16.159 86.346 16.979 86.364 ;
     RECT  18.355 85.581 18.527 85.599 ;
     RECT  16.691 2.151 18.715 84.249 ;
     RECT  18.715 2.151 18.895 84.33 ;
     RECT  18.895 2.151 19.615 84.942 ;
     RECT  19.615 2.151 19.751 85.599 ;
     RECT  19.751 2.151 20.507 84.942 ;
     RECT  20.507 2.151 21.919 84.249 ;
     RECT  21.919 2.151 21.955 84.294 ;
     RECT  21.955 85.581 22.091 85.599 ;
     RECT  21.955 2.151 22.163 84.33 ;
     RECT  22.163 2.151 22.235 84.294 ;
     RECT  22.235 2.151 22.963 84.249 ;
     RECT  22.963 2.151 23.359 84.294 ;
     RECT  23.359 2.151 23.855 84.906 ;
     RECT  23.503 86.346 24.935 86.364 ;
     RECT  23.855 2.151 25.015 84.402 ;
     RECT  25.015 2.151 26.239 84.519 ;
     RECT  26.239 2.151 26.411 84.906 ;
     RECT  26.411 2.151 27.427 84.366 ;
     RECT  27.427 2.151 28.003 84.906 ;
     RECT  28.003 2.151 28.103 84.942 ;
     RECT  28.103 2.151 29.227 84.249 ;
     RECT  29.227 2.151 29.327 84.906 ;
     RECT  29.327 2.151 30.811 84.249 ;
     RECT  30.811 2.151 31.099 84.834 ;
     RECT  31.099 2.151 31.199 84.906 ;
     RECT  31.171 86.346 31.307 86.364 ;
     RECT  31.199 2.151 31.927 84.249 ;
     RECT  31.927 2.151 32.135 84.906 ;
     RECT  32.135 2.151 32.287 84.249 ;
     RECT  32.287 2.106 33.295 84.249 ;
     RECT  33.295 2.106 33.431 84.906 ;
     RECT  33.431 2.106 33.871 84.249 ;
     RECT  33.871 2.07 34.591 84.249 ;
     RECT  33.259 86.346 34.691 86.364 ;
     RECT  34.591 2.07 35.231 84.906 ;
     RECT  35.231 2.07 35.447 84.366 ;
     RECT  35.347 86.166 35.483 86.184 ;
     RECT  35.447 2.07 36.247 84.249 ;
     RECT  36.247 86.346 36.347 86.364 ;
     RECT  36.247 2.07 37.463 84.906 ;
     RECT  37.463 2.07 38.623 84.249 ;
     RECT  38.623 2.07 38.939 84.906 ;
     RECT  39.019 86.346 39.263 86.364 ;
     RECT  38.939 2.07 39.335 84.294 ;
     RECT  39.307 85.5 39.443 85.518 ;
     RECT  39.335 2.07 40.819 84.249 ;
     RECT  40.459 86.346 40.847 86.364 ;
     RECT  40.819 2.07 40.955 84.294 ;
     RECT  41.359 86.274 41.459 86.292 ;
     RECT  40.955 2.07 42.547 84.249 ;
     RECT  42.259 84.996 42.547 85.014 ;
     RECT  42.547 2.07 42.575 85.014 ;
     RECT  42.575 2.07 42.719 84.942 ;
     RECT  42.719 2.07 43.195 84.249 ;
     RECT  43.195 2.034 44.599 84.249 ;
     RECT  44.599 2.034 44.771 84.294 ;
     RECT  44.771 2.034 45.103 84.249 ;
     RECT  45.103 1.998 45.715 84.249 ;
     RECT  45.895 86.346 45.995 86.364 ;
     RECT  46.831 86.346 47.003 86.364 ;
     RECT  45.715 1.998 47.039 84.906 ;
     RECT  47.039 1.998 48.451 84.87 ;
     RECT  48.451 1.998 48.775 84.906 ;
     RECT  48.775 1.926 48.839 84.906 ;
     RECT  49.819 85.581 50.099 85.599 ;
     RECT  48.839 1.926 50.467 84.294 ;
     RECT  50.467 1.836 50.719 84.294 ;
     RECT  50.719 1.836 51.295 84.366 ;
     RECT  51.295 1.836 51.431 84.942 ;
     RECT  51.431 1.836 51.655 84.249 ;
     RECT  51.655 1.116 51.899 84.249 ;
     RECT  51.899 1.836 52.591 84.249 ;
     RECT  52.591 1.836 52.871 84.906 ;
     RECT  52.871 1.836 53.339 84.249 ;
     RECT  53.339 2.034 54 84.249 ;
     RECT  54 2.034 54.167 84.168 ;
     RECT  54.167 53.568 54.203 84.168 ;
     RECT  54.167 2.034 54.707 52.776 ;
     RECT  54.203 53.568 54.707 83.214 ;
     RECT  54.707 2.034 54.743 35.154 ;
     RECT  54.707 38.016 54.743 45.288 ;
     RECT  54.707 46.278 54.743 52.344 ;
     RECT  54.707 55.458 54.743 83.214 ;
     RECT  54.203 84.078 54.743 84.168 ;
     RECT  54.743 2.034 54.779 3.834 ;
     RECT  54.743 48.708 54.779 52.344 ;
     RECT  54.743 56.646 54.779 57.636 ;
     RECT  54.743 84.078 54.779 84.096 ;
     RECT  54.743 58.428 54.815 83.214 ;
     RECT  54.743 4.77 55.031 25.164 ;
     RECT  54.815 58.464 55.175 83.214 ;
     RECT  54.743 25.956 55.211 31.644 ;
     RECT  55.211 27.486 55.247 31.644 ;
     RECT  54.743 32.616 55.247 35.154 ;
     RECT  54.743 55.458 55.247 55.818 ;
     RECT  55.175 65.754 55.247 83.214 ;
     RECT  55.031 5.274 55.283 25.164 ;
     RECT  55.211 25.956 55.283 26.694 ;
     RECT  55.247 27.486 55.283 30.474 ;
     RECT  55.247 31.626 55.283 31.644 ;
     RECT  55.247 32.706 55.283 34.074 ;
     RECT  55.247 35.046 55.283 35.154 ;
     RECT  54.707 36.486 55.283 37.188 ;
     RECT  54.743 43.686 55.283 44.982 ;
     RECT  54.743 46.278 55.283 47.718 ;
     RECT  54.779 48.708 55.283 49.806 ;
     RECT  55.247 55.458 55.283 55.746 ;
     RECT  54.779 2.268 55.319 3.834 ;
     RECT  55.283 6.048 55.319 6.984 ;
     RECT  55.283 11.754 55.319 13.392 ;
     RECT  55.283 14.184 55.319 16.254 ;
     RECT  55.283 17.316 55.319 22.23 ;
     RECT  55.283 23.166 55.319 23.184 ;
     RECT  55.283 24.984 55.319 25.002 ;
     RECT  55.283 25.956 55.319 26.154 ;
     RECT  55.283 28.224 55.319 30.474 ;
     RECT  55.283 35.046 55.319 35.064 ;
     RECT  55.283 46.386 55.319 47.718 ;
     RECT  54.779 51.714 55.319 52.344 ;
     RECT  54.707 53.676 55.319 54.549 ;
     RECT  54.779 56.646 55.319 57.366 ;
     RECT  55.175 58.464 55.319 64.962 ;
     RECT  55.247 65.754 55.319 69.318 ;
     RECT  55.247 70.074 55.319 83.214 ;
     RECT  54.535 84.924 55.319 84.942 ;
     RECT  55.319 2.376 55.355 3.834 ;
     RECT  55.319 6.696 55.355 6.714 ;
     RECT  55.283 10.296 55.355 10.422 ;
     RECT  55.319 16.074 55.355 16.209 ;
     RECT  55.319 17.316 55.355 21.96 ;
     RECT  54.743 38.016 55.355 42.858 ;
     RECT  55.319 46.386 55.355 46.638 ;
     RECT  55.319 53.676 55.355 54.198 ;
     RECT  55.319 70.074 55.355 80.739 ;
     RECT  55.355 3.312 55.391 3.834 ;
     RECT  55.283 9.522 55.391 9.54 ;
     RECT  55.355 21.096 55.391 21.96 ;
     RECT  55.319 58.464 55.391 60.876 ;
     RECT  55.355 70.074 55.391 75.996 ;
     RECT  55.319 81.486 55.391 83.214 ;
     RECT  55.355 38.286 55.427 42.858 ;
     RECT  55.355 53.91 55.427 54.198 ;
     RECT  55.391 60.858 55.427 60.876 ;
     RECT  55.319 64.134 55.427 64.926 ;
     RECT  55.319 65.79 55.427 69.318 ;
     RECT  55.391 70.074 55.427 71.604 ;
     RECT  55.355 76.824 55.427 79.704 ;
     RECT  55.391 72.468 55.463 75.996 ;
     RECT  55.427 70.074 55.499 71.514 ;
     RECT  55.463 72.54 55.571 75.996 ;
     RECT  55.571 75.438 55.643 75.996 ;
     RECT  55.427 76.941 55.679 79.704 ;
     RECT  55.643 75.438 55.715 75.798 ;
     RECT  55.355 80.568 55.715 80.739 ;
     RECT  55.715 75.438 55.787 75.726 ;
     RECT  55.571 72.54 55.823 74.376 ;
     RECT  55.679 76.941 55.823 78.732 ;
     RECT  55.715 80.568 55.823 80.586 ;
     RECT  55.823 73.116 55.859 74.376 ;
     RECT  55.823 76.941 55.859 77.616 ;
     RECT  55.391 81.486 55.895 81.504 ;
     RECT  55.499 70.074 55.931 70.866 ;
     RECT  55.679 79.686 55.931 79.704 ;
     RECT  55.283 36.63 55.967 37.188 ;
     RECT  55.427 64.791 55.967 64.926 ;
     RECT  55.823 78.561 55.967 78.732 ;
     RECT  55.319 28.836 56.003 29.664 ;
     RECT  55.319 30.456 56.003 30.474 ;
     RECT  55.283 32.706 56.003 32.904 ;
     RECT  55.967 36.63 56.003 36.846 ;
     RECT  55.427 39.456 56.003 42.858 ;
     RECT  55.391 58.464 56.003 59.832 ;
     RECT  55.319 61.74 56.003 63.189 ;
     RECT  55.427 65.79 56.003 66.816 ;
     RECT  55.427 68.22 56.003 69.318 ;
     RECT  55.931 70.308 56.003 70.866 ;
     RECT  55.355 2.376 56.039 2.52 ;
     RECT  55.319 13.104 56.039 13.392 ;
     RECT  55.355 17.316 56.039 19.944 ;
     RECT  55.283 23.94 56.039 23.994 ;
     RECT  56.003 29.34 56.039 29.664 ;
     RECT  56.003 32.706 56.039 32.724 ;
     RECT  55.427 38.286 56.039 38.574 ;
     RECT  56.003 39.456 56.039 40.626 ;
     RECT  55.319 51.714 56.039 52.002 ;
     RECT  56.003 65.79 56.039 66.744 ;
     RECT  56.003 70.308 56.039 70.794 ;
     RECT  55.859 73.161 56.039 74.376 ;
     RECT  56.039 2.502 56.075 2.52 ;
     RECT  55.391 3.816 56.075 3.834 ;
     RECT  55.283 7.866 56.075 7.884 ;
     RECT  55.355 10.296 56.075 10.314 ;
     RECT  55.319 12.096 56.075 12.204 ;
     RECT  56.039 13.104 56.075 13.122 ;
     RECT  55.319 14.346 56.075 15.012 ;
     RECT  55.355 16.191 56.075 16.209 ;
     RECT  56.039 17.316 56.075 18.594 ;
     RECT  56.039 19.854 56.075 19.872 ;
     RECT  55.391 21.096 56.075 21.654 ;
     RECT  56.039 23.94 56.075 23.958 ;
     RECT  55.319 25.956 56.075 25.974 ;
     RECT  56.039 29.34 56.075 29.358 ;
     RECT  55.283 34.056 56.075 34.074 ;
     RECT  56.003 36.828 56.075 36.846 ;
     RECT  56.039 38.286 56.075 38.304 ;
     RECT  56.039 39.456 56.075 39.582 ;
     RECT  56.003 41.418 56.075 42.858 ;
     RECT  55.283 44.388 56.075 44.982 ;
     RECT  55.355 46.62 56.075 46.638 ;
     RECT  55.319 47.43 56.075 47.448 ;
     RECT  55.283 48.708 56.075 48.726 ;
     RECT  55.283 49.554 56.075 49.572 ;
     RECT  56.039 51.984 56.075 52.002 ;
     RECT  55.427 54.108 56.075 54.126 ;
     RECT  56.003 58.5 56.075 59.832 ;
     RECT  56.003 62.208 56.075 63.189 ;
     RECT  56.039 66.366 56.075 66.744 ;
     RECT  56.039 73.161 56.075 73.332 ;
     RECT  55.787 75.546 56.075 75.726 ;
     RECT  55.859 76.941 56.075 76.959 ;
     RECT  55.967 78.561 56.075 78.696 ;
     RECT  55.391 82.53 56.075 82.629 ;
     RECT  55.967 64.791 56.111 64.809 ;
     RECT  56.075 66.726 56.111 66.744 ;
     RECT  56.003 68.22 56.111 68.778 ;
     RECT  56.039 70.776 56.111 70.794 ;
     RECT  56.039 74.358 56.111 74.376 ;
     RECT  56.075 78.678 56.111 78.696 ;
     RECT  56.047 9.126 56.147 9.144 ;
     RECT  56.075 12.186 56.147 12.204 ;
     RECT  56.047 35.406 56.147 35.424 ;
     RECT  56.075 39.456 56.147 39.474 ;
     RECT  56.111 68.22 56.147 68.238 ;
     RECT  56.075 73.161 56.147 73.179 ;
     RECT  56.075 75.708 56.147 75.726 ;
     RECT  56.047 85.806 56.147 85.824 ;
    LAYER M3 ;
     RECT  54.396 0.043 54.414 0.139 ;
     RECT  51.48 0.235 51.498 0.331 ;
     RECT  51.48 0.331 51.894 0.571 ;
     RECT  50.94 0.571 51.894 0.667 ;
     RECT  50.94 0.667 52.254 0.955 ;
     RECT  50.292 0.955 52.254 1.051 ;
     RECT  56.016 0.859 56.034 1.291 ;
     RECT  54.396 0.139 54.738 1.675 ;
     RECT  54.396 1.675 55.026 1.771 ;
     RECT  53.244 0.427 53.262 1.831 ;
     RECT  54.108 1.771 55.026 1.915 ;
     RECT  48.78 1.921 48.798 1.957 ;
     RECT  48.78 1.957 48.942 1.993 ;
     RECT  48.78 1.993 49.194 2.029 ;
     RECT  53.244 1.831 53.334 2.029 ;
     RECT  54.072 1.915 55.026 2.029 ;
     RECT  48.78 2.029 49.41 2.101 ;
     RECT  50.292 1.051 52.434 2.101 ;
     RECT  56.016 1.291 56.07 2.107 ;
     RECT  45.108 1.993 45.126 2.143 ;
     RECT  46.404 2.101 46.422 2.143 ;
     RECT  47.844 2.101 52.434 2.191 ;
     RECT  53.244 2.029 55.026 2.191 ;
     RECT  47.844 2.191 55.026 2.263 ;
     RECT  55.98 2.107 56.07 2.263 ;
     RECT  33.876 2.065 33.894 2.293 ;
     RECT  45.108 2.143 46.422 2.293 ;
     RECT  18.615 2.143 18.705 2.299 ;
     RECT  33.408 2.293 33.894 2.299 ;
     RECT  43.2 2.029 43.218 2.299 ;
     RECT  45.108 2.293 46.782 2.299 ;
     RECT  21.06 2.299 21.078 2.335 ;
     RECT  33.408 2.299 33.966 2.335 ;
     RECT  34.815 2.143 34.905 2.335 ;
     RECT  36.324 2.299 36.342 2.335 ;
     RECT  37.764 2.299 37.782 2.335 ;
     RECT  42.84 2.299 43.218 2.335 ;
     RECT  44.172 2.293 44.19 2.335 ;
     RECT  45.108 2.299 46.854 2.335 ;
     RECT  47.844 2.263 56.07 2.335 ;
     RECT  20.592 2.335 21.078 2.371 ;
     RECT  32.292 2.101 32.31 2.371 ;
     RECT  36.252 2.335 36.342 2.371 ;
     RECT  38.772 2.299 38.898 2.371 ;
     RECT  41.364 2.347 41.382 2.371 ;
     RECT  42.84 2.335 43.254 2.371 ;
     RECT  44.064 2.335 56.07 2.371 ;
     RECT  2.415 2.143 2.505 2.413 ;
     RECT  7.815 2.143 7.905 2.413 ;
     RECT  13.215 2.143 13.305 2.413 ;
     RECT  24.015 2.143 24.105 2.413 ;
     RECT  29.415 2.143 29.505 2.413 ;
     RECT  40.215 2.143 40.305 2.413 ;
     RECT  18.615 2.299 19.386 2.461 ;
     RECT  20.196 2.371 21.078 2.461 ;
     RECT  31.86 2.371 32.31 2.461 ;
     RECT  40.215 2.413 40.497 2.461 ;
     RECT  39.888 2.461 40.497 2.491 ;
     RECT  41.292 2.371 41.382 2.491 ;
     RECT  18.615 2.461 21.078 2.497 ;
     RECT  31.86 2.461 32.526 2.497 ;
     RECT  33.408 2.335 35.514 2.497 ;
     RECT  36.252 2.371 36.954 2.497 ;
     RECT  37.728 2.335 37.782 2.497 ;
     RECT  42.84 2.371 56.07 2.525 ;
     RECT  18.615 2.497 21.474 2.533 ;
     RECT  22.428 2.335 22.446 2.533 ;
     RECT  17.1 2.371 17.118 2.569 ;
     RECT  25.344 2.533 25.362 2.569 ;
     RECT  38.772 2.371 38.934 2.569 ;
     RECT  24.015 2.413 24.297 2.605 ;
     RECT  28.332 2.497 28.35 2.605 ;
     RECT  31.86 2.497 37.782 2.605 ;
     RECT  42.84 2.525 55.35 2.605 ;
     RECT  16.92 2.569 17.118 2.641 ;
     RECT  28.116 2.605 28.35 2.641 ;
     RECT  29.415 2.413 29.697 2.641 ;
     RECT  38.772 2.569 39.006 2.641 ;
     RECT  39.888 2.491 41.382 2.641 ;
     RECT  13.215 2.413 13.497 2.731 ;
     RECT  18.615 2.533 22.446 2.731 ;
     RECT  25.2 2.569 25.83 2.731 ;
     RECT  31.716 2.605 37.782 2.731 ;
     RECT  38.664 2.641 41.382 2.731 ;
     RECT  18.615 2.731 22.518 2.767 ;
     RECT  23.292 2.605 24.297 2.767 ;
     RECT  25.2 2.731 26.046 2.767 ;
     RECT  13.104 2.731 13.497 2.803 ;
     RECT  14.364 2.605 14.382 2.803 ;
     RECT  15.372 2.767 15.39 2.803 ;
     RECT  16.308 2.641 17.118 2.803 ;
     RECT  31.716 2.731 37.818 2.803 ;
     RECT  38.664 2.731 41.418 2.803 ;
     RECT  27.108 2.803 27.126 2.839 ;
     RECT  28.116 2.641 29.697 2.839 ;
     RECT  23.292 2.767 26.046 2.869 ;
     RECT  7.815 2.413 8.097 2.875 ;
     RECT  10.008 2.839 10.026 2.875 ;
     RECT  10.836 2.731 11.466 2.875 ;
     RECT  42.372 2.605 55.35 2.903 ;
     RECT  6.912 2.839 6.93 2.911 ;
     RECT  7.815 2.875 8.154 2.911 ;
     RECT  10.008 2.875 11.466 2.911 ;
     RECT  12.348 2.767 12.366 2.911 ;
     RECT  13.104 2.803 14.382 2.911 ;
     RECT  15.372 2.803 17.154 2.911 ;
     RECT  18.504 2.767 22.518 2.911 ;
     RECT  23.292 2.869 26.118 2.911 ;
     RECT  30.78 2.299 30.798 2.911 ;
     RECT  31.68 2.803 41.562 2.911 ;
     RECT  6.66 2.911 6.93 3.001 ;
     RECT  9.72 2.911 11.466 3.001 ;
     RECT  12.348 2.911 14.382 3.001 ;
     RECT  15.372 2.911 17.694 3.001 ;
     RECT  18.504 2.911 26.118 3.001 ;
     RECT  27.108 2.839 29.697 3.001 ;
     RECT  30.564 2.911 30.798 3.001 ;
     RECT  5.004 2.911 5.022 3.037 ;
     RECT  6.624 3.001 6.93 3.037 ;
     RECT  7.815 2.911 8.622 3.037 ;
     RECT  9.54 3.001 11.466 3.037 ;
     RECT  27.108 3.001 30.834 3.073 ;
     RECT  5.004 3.037 6.93 3.109 ;
     RECT  7.776 3.037 11.466 3.109 ;
     RECT  12.348 3.001 26.118 3.109 ;
     RECT  26.856 3.073 30.834 3.109 ;
     RECT  31.68 2.911 41.67 3.109 ;
     RECT  4.86 3.109 6.93 3.145 ;
     RECT  7.776 3.109 26.118 3.145 ;
     RECT  4.86 3.145 26.118 3.181 ;
     RECT  26.856 3.109 41.67 3.181 ;
     RECT  42.444 2.903 55.35 3.307 ;
     RECT  4.572 3.181 41.67 3.379 ;
     RECT  42.444 3.307 55.386 3.547 ;
     RECT  4.356 3.379 41.67 3.613 ;
     RECT  3.96 3.613 41.67 3.691 ;
     RECT  42.444 3.547 56.07 3.691 ;
     RECT  3.96 3.691 56.07 3.839 ;
     RECT  4.068 3.839 55.386 3.875 ;
     RECT  4.284 3.875 55.386 4.019 ;
     RECT  27.648 4.019 55.386 4.397 ;
     RECT  4.284 4.019 26.802 4.765 ;
     RECT  4.068 4.765 26.802 4.801 ;
     RECT  27.648 4.397 55.278 4.801 ;
     RECT  4.068 4.801 55.278 5.305 ;
     RECT  3.996 5.305 55.278 5.611 ;
     RECT  3.924 5.611 55.278 6.043 ;
     RECT  2.415 2.413 2.697 6.115 ;
     RECT  2.415 6.115 2.97 6.151 ;
     RECT  3.924 6.043 55.314 6.151 ;
     RECT  2.415 6.151 55.314 6.691 ;
     RECT  56.052 4.795 56.07 6.691 ;
     RECT  2.415 6.691 56.07 7.889 ;
     RECT  2.415 7.889 55.35 7.901 ;
     RECT  2.415 7.901 55.278 8.045 ;
     RECT  55.224 8.045 55.278 9.019 ;
     RECT  2.415 8.045 54.234 9.121 ;
     RECT  55.188 9.019 55.278 9.121 ;
     RECT  56.052 9.112 56.07 9.121 ;
     RECT  56.052 9.121 56.142 9.149 ;
     RECT  2.415 9.121 55.278 9.517 ;
     RECT  2.415 9.517 55.386 9.677 ;
     RECT  55.188 9.677 55.386 9.689 ;
     RECT  55.26 9.689 55.386 9.887 ;
     RECT  55.296 9.887 55.386 10.027 ;
     RECT  56.124 9.149 56.142 10.027 ;
     RECT  55.296 10.027 56.142 10.637 ;
     RECT  55.296 10.637 55.386 10.829 ;
     RECT  55.296 10.829 55.314 10.891 ;
     RECT  2.415 9.677 54.162 10.939 ;
     RECT  55.26 10.891 55.314 10.939 ;
     RECT  2.415 10.939 55.314 11.549 ;
     RECT  56.124 10.637 56.142 12.043 ;
     RECT  56.052 12.043 56.142 12.209 ;
     RECT  2.415 11.549 54.198 12.461 ;
     RECT  55.188 11.549 55.314 12.763 ;
     RECT  55.152 12.763 55.314 12.955 ;
     RECT  56.052 12.209 56.07 12.955 ;
     RECT  2.415 12.461 54.09 13.369 ;
     RECT  55.152 12.955 56.07 13.369 ;
     RECT  2.415 13.369 56.07 13.397 ;
     RECT  2.415 13.397 55.314 13.421 ;
     RECT  2.415 13.421 53.874 13.945 ;
     RECT  2.376 13.945 53.874 14.251 ;
     RECT  54.612 13.421 55.314 14.251 ;
     RECT  2.376 14.251 55.314 14.621 ;
     RECT  2.376 14.621 53.874 14.683 ;
     RECT  54.684 14.621 55.314 14.765 ;
     RECT  56.052 13.397 56.07 15.017 ;
     RECT  2.304 14.683 53.874 15.449 ;
     RECT  54.684 14.765 55.278 15.565 ;
     RECT  54.684 15.565 55.314 16.069 ;
     RECT  56.052 15.739 56.07 16.069 ;
     RECT  2.304 15.449 53.658 16.186 ;
     RECT  54.684 16.069 56.07 16.186 ;
     RECT  2.304 16.186 56.07 16.214 ;
     RECT  2.304 16.214 55.35 16.987 ;
     RECT  2.304 16.987 56.07 17.213 ;
     RECT  2.304 17.213 55.314 18.235 ;
     RECT  56.052 17.213 56.07 18.235 ;
     RECT  2.304 18.235 56.07 18.365 ;
     RECT  2.304 18.365 55.278 19.471 ;
     RECT  56.016 18.365 56.07 19.471 ;
     RECT  2.304 19.471 56.07 19.607 ;
     RECT  2.304 19.607 54.09 19.769 ;
     RECT  55.152 19.607 56.07 19.877 ;
     RECT  55.152 19.877 56.034 19.949 ;
     RECT  2.34 19.769 54.09 20.491 ;
     RECT  55.152 19.949 55.35 20.683 ;
     RECT  2.34 20.491 54.162 20.731 ;
     RECT  55.152 20.683 56.07 20.731 ;
     RECT  2.34 20.731 56.07 20.957 ;
     RECT  55.152 20.957 56.07 21.659 ;
     RECT  2.34 20.957 54.198 22.081 ;
     RECT  55.152 21.659 55.386 22.081 ;
     RECT  2.34 22.081 55.386 22.235 ;
     RECT  2.376 22.235 55.386 22.589 ;
     RECT  2.376 22.589 55.314 22.739 ;
     RECT  2.415 22.739 55.314 23.707 ;
     RECT  56.052 23.611 56.07 23.707 ;
     RECT  2.415 23.707 56.07 23.837 ;
     RECT  56.016 23.837 56.07 23.963 ;
     RECT  56.016 23.963 56.034 23.999 ;
     RECT  2.415 23.837 55.278 24.979 ;
     RECT  2.415 24.979 55.314 25.277 ;
     RECT  56.052 25.339 56.07 25.979 ;
     RECT  2.415 25.277 55.278 25.997 ;
     RECT  55.188 25.997 55.278 26.131 ;
     RECT  55.188 26.131 55.314 26.333 ;
     RECT  2.415 25.997 54.162 26.525 ;
     RECT  2.415 26.525 54.126 26.779 ;
     RECT  2.304 26.779 54.126 27.095 ;
     RECT  2.415 27.095 54.126 27.248 ;
     RECT  55.188 26.333 55.278 27.301 ;
     RECT  54.72 27.301 55.278 27.677 ;
     RECT  55.224 27.677 55.278 28.219 ;
     RECT  55.224 28.219 55.314 28.453 ;
     RECT  54.792 28.453 55.314 28.489 ;
     RECT  54.72 28.489 55.314 28.651 ;
     RECT  56.052 28.267 56.07 28.651 ;
     RECT  54.72 28.651 56.07 29.363 ;
     RECT  2.415 27.248 53.91 29.467 ;
     RECT  54.72 29.363 56.034 29.467 ;
     RECT  2.415 29.467 56.034 29.669 ;
     RECT  2.415 29.669 55.314 30.451 ;
     RECT  2.415 30.451 55.998 30.523 ;
     RECT  2.415 30.523 56.034 31.147 ;
     RECT  2.415 31.147 56.07 31.225 ;
     RECT  2.34 31.225 56.07 31.373 ;
     RECT  2.34 31.373 55.278 32.189 ;
     RECT  55.188 32.189 55.278 32.587 ;
     RECT  56.016 31.373 56.07 32.587 ;
     RECT  55.188 32.587 56.07 32.909 ;
     RECT  2.34 32.189 54.414 32.923 ;
     RECT  55.188 32.909 55.278 32.923 ;
     RECT  2.34 32.923 55.278 33.313 ;
     RECT  2.304 33.313 55.278 34.027 ;
     RECT  56.052 32.909 56.07 34.079 ;
     RECT  2.304 34.027 55.314 35.069 ;
     RECT  56.052 35.371 56.07 35.401 ;
     RECT  56.052 35.401 56.142 35.899 ;
     RECT  2.304 35.069 55.278 36.091 ;
     RECT  56.016 35.899 56.142 36.091 ;
     RECT  2.304 36.091 56.142 36.689 ;
     RECT  2.304 36.689 55.206 36.923 ;
     RECT  2.304 36.923 55.062 37.771 ;
     RECT  55.944 36.689 56.142 37.771 ;
     RECT  2.304 37.771 56.142 39.245 ;
     RECT  56.016 39.245 56.142 39.479 ;
     RECT  2.304 39.245 55.062 40.123 ;
     RECT  2.304 40.123 55.278 40.261 ;
     RECT  2.268 40.261 55.278 40.397 ;
     RECT  2.304 40.397 54.198 40.433 ;
     RECT  55.224 40.397 55.278 40.459 ;
     RECT  56.016 39.479 56.07 40.459 ;
     RECT  2.304 40.433 54.162 41.179 ;
     RECT  2.304 41.179 54.234 41.309 ;
     RECT  55.224 40.459 56.07 41.563 ;
     RECT  55.188 41.563 56.07 41.783 ;
     RECT  55.188 41.783 55.206 41.803 ;
     RECT  54.648 41.803 55.206 42.053 ;
     RECT  54.648 42.053 55.17 42.089 ;
     RECT  2.304 41.309 53.874 42.091 ;
     RECT  54.648 42.089 54.702 42.091 ;
     RECT  55.98 41.783 56.07 42.461 ;
     RECT  56.052 42.461 56.07 42.863 ;
     RECT  2.304 42.091 54.702 43.141 ;
     RECT  2.232 43.141 54.702 43.303 ;
     RECT  2.232 43.303 54.738 43.435 ;
     RECT  2.232 43.435 55.278 43.709 ;
     RECT  2.232 43.709 54.738 44.587 ;
     RECT  2.232 44.587 55.278 44.753 ;
     RECT  56.052 44.251 56.07 44.987 ;
     RECT  2.232 44.753 54.81 45.023 ;
     RECT  2.304 45.023 54.81 45.931 ;
     RECT  2.304 45.931 55.278 46.381 ;
     RECT  56.052 46.219 56.07 46.381 ;
     RECT  2.304 46.381 56.07 46.769 ;
     RECT  2.34 46.769 56.07 46.877 ;
     RECT  56.052 46.877 56.07 47.453 ;
     RECT  2.34 46.877 55.314 47.551 ;
     RECT  2.268 47.551 55.314 47.837 ;
     RECT  2.268 47.837 54.738 48.271 ;
     RECT  2.16 48.271 54.738 48.659 ;
     RECT  56.052 48.187 56.07 48.731 ;
     RECT  54.576 48.659 54.738 48.856 ;
     RECT  2.16 48.659 53.766 48.929 ;
     RECT  56.052 49.531 56.07 49.577 ;
     RECT  2.16 48.929 53.694 49.723 ;
     RECT  54.576 48.856 55.278 49.723 ;
     RECT  2.16 49.723 55.278 49.811 ;
     RECT  56.052 50.779 56.07 51.211 ;
     RECT  56.016 51.211 56.07 51.737 ;
     RECT  56.052 51.737 56.07 52.007 ;
     RECT  2.16 49.811 54.774 52.051 ;
     RECT  2.16 52.051 55.314 53.393 ;
     RECT  54.684 53.393 55.314 53.671 ;
     RECT  54.684 53.671 55.35 53.905 ;
     RECT  54.684 53.905 55.422 53.995 ;
     RECT  54.684 53.995 56.07 54.131 ;
     RECT  54.684 54.131 55.422 54.203 ;
     RECT  2.16 53.393 53.766 54.373 ;
     RECT  54.684 54.203 55.35 54.373 ;
     RECT  2.16 54.373 55.35 54.749 ;
     RECT  2.16 54.749 55.314 54.845 ;
     RECT  2.16 54.845 55.278 56.641 ;
     RECT  2.16 56.641 55.314 57.595 ;
     RECT  56.052 56.587 56.07 57.595 ;
     RECT  2.16 57.595 56.07 57.725 ;
     RECT  55.98 57.725 56.07 58.721 ;
     RECT  2.16 57.725 54.81 58.801 ;
     RECT  56.052 58.721 56.07 59.837 ;
     RECT  2.16 58.801 55.314 60.313 ;
     RECT  2.16 60.313 55.386 60.853 ;
     RECT  2.16 60.853 55.422 61.735 ;
     RECT  2.16 61.735 55.998 62.155 ;
     RECT  2.16 62.155 56.07 63.197 ;
     RECT  2.16 63.197 55.35 64.027 ;
     RECT  2.16 64.027 56.07 64.786 ;
     RECT  0.108 64.327 0.126 64.829 ;
     RECT  2.16 64.786 56.106 66.029 ;
     RECT  55.944 66.029 56.106 66.749 ;
     RECT  2.16 66.029 55.17 66.865 ;
     RECT  55.944 66.749 56.07 66.865 ;
     RECT  2.16 66.865 56.07 68.215 ;
     RECT  2.16 68.215 56.142 69.763 ;
     RECT  1.944 69.763 56.142 73.111 ;
     RECT  1.836 73.111 56.142 73.184 ;
     RECT  1.836 73.184 56.07 73.337 ;
     RECT  1.836 73.337 56.034 74.353 ;
     RECT  1.836 74.353 56.106 75.703 ;
     RECT  1.836 75.703 56.142 78.241 ;
     RECT  1.764 78.241 56.142 78.637 ;
     RECT  1.692 78.637 56.142 79.987 ;
     RECT  1.548 79.987 56.142 80.527 ;
     RECT  1.188 80.527 56.142 83.101 ;
     RECT  1.152 83.101 56.142 85.829 ;
     RECT  1.152 85.829 56.07 85.853 ;
     RECT  1.152 85.853 55.386 86.285 ;
     RECT  1.152 86.285 55.062 86.381 ;
    LAYER M4 ;
     RECT  1.621 82.512 1.765 82.536 ;
     RECT  1.333 80.544 2.149 80.568 ;
     RECT  1.285 75.216 2.252 75.24 ;
     RECT  2.245 78.72 2.257 78.744 ;
     RECT  2.149 79.728 2.257 80.568 ;
     RECT  2.221 77.424 2.285 77.448 ;
     RECT  2.285 35.856 2.293 35.88 ;
     RECT  2.252 44.88 2.293 44.904 ;
     RECT  0.133 47.424 2.293 47.448 ;
     RECT  2.041 73.056 2.293 73.08 ;
     RECT  2.252 74.544 2.293 75.24 ;
     RECT  2.285 77.424 2.293 77.544 ;
     RECT  2.257 78.72 2.293 80.568 ;
     RECT  2.293 37.056 2.329 37.08 ;
     RECT  2.293 40.848 2.329 40.872 ;
     RECT  2.293 77.28 2.329 80.568 ;
     RECT  1.765 82.032 2.329 82.536 ;
     RECT  2.293 30.864 2.365 31.8 ;
     RECT  2.293 44.88 2.365 45.72 ;
     RECT  2.293 50.64 2.365 50.664 ;
     RECT  2.293 83.568 2.365 83.592 ;
     RECT  2.293 38.784 2.401 39.672 ;
     RECT  2.329 40.656 2.401 40.872 ;
     RECT  2.285 43.296 2.401 43.32 ;
     RECT  2.293 52.128 2.401 52.152 ;
     RECT  2.293 65.232 2.401 65.256 ;
     RECT  2.293 26.784 2.408 26.808 ;
     RECT  2.293 29.04 2.408 29.064 ;
     RECT  2.365 30.864 2.408 32.328 ;
     RECT  2.293 34.992 2.408 35.88 ;
     RECT  2.329 36.864 2.408 37.08 ;
     RECT  2.401 38.784 2.408 40.872 ;
     RECT  2.401 43.296 2.408 43.848 ;
     RECT  2.365 44.88 2.408 45.816 ;
     RECT  2.293 47.04 2.408 47.448 ;
     RECT  2.365 49.776 2.408 50.664 ;
     RECT  2.401 51.936 2.408 52.152 ;
     RECT  2.401 53.28 2.408 53.304 ;
     RECT  2.293 55.152 2.408 55.176 ;
     RECT  2.293 57.6 2.408 57.624 ;
     RECT  2.401 60.384 2.408 60.408 ;
     RECT  2.401 64.944 2.408 65.256 ;
     RECT  2.221 68.352 2.408 68.376 ;
     RECT  2.365 71.472 2.408 71.496 ;
     RECT  2.293 72.672 2.408 75.24 ;
     RECT  2.329 77.28 2.408 82.536 ;
     RECT  2.365 83.568 2.408 83.64 ;
     RECT  2.408 2.148 2.512 84.252 ;
     RECT  2.533 86.112 2.581 86.136 ;
     RECT  2.512 2.418 2.704 84.252 ;
     RECT  2.581 86.112 2.725 86.232 ;
     RECT  2.704 62.448 2.765 84.252 ;
     RECT  2.704 16.656 2.819 21.432 ;
     RECT  2.704 54.336 2.819 58.152 ;
     RECT  2.819 16.656 2.86 21.336 ;
     RECT  2.704 29.184 2.867 30.888 ;
     RECT  2.704 60.384 2.867 61.224 ;
     RECT  2.725 86.112 2.867 86.328 ;
     RECT  2.765 62.544 2.908 84.252 ;
     RECT  2.908 66.096 2.915 84.252 ;
     RECT  2.915 66.096 2.945 82.776 ;
     RECT  2.704 6.24 2.963 9.384 ;
     RECT  2.704 32.304 2.963 37.512 ;
     RECT  2.963 6.24 3.025 8.52 ;
     RECT  2.704 51.072 3.097 53.304 ;
     RECT  2.867 86.304 3.155 86.328 ;
     RECT  2.704 59.28 3.203 59.304 ;
     RECT  2.915 83.808 3.205 84.252 ;
     RECT  2.945 66.096 3.233 82.68 ;
     RECT  3.233 66.096 3.341 82.104 ;
     RECT  2.963 34.752 3.347 37.512 ;
     RECT  3.025 6.816 3.349 8.52 ;
     RECT  2.86 16.656 3.413 20.616 ;
     RECT  2.819 56.832 3.443 58.152 ;
     RECT  2.704 12.528 3.493 12.552 ;
     RECT  2.704 13.536 3.685 14.424 ;
     RECT  2.704 38.784 3.685 42.168 ;
     RECT  2.867 60.96 3.685 61.224 ;
     RECT  2.963 32.304 3.692 33.624 ;
     RECT  3.205 83.808 3.733 84.36 ;
     RECT  3.347 36.768 3.761 37.512 ;
     RECT  2.704 25.488 3.769 27.912 ;
     RECT  2.867 29.184 3.769 30.6 ;
     RECT  2.704 43.152 3.769 50.04 ;
     RECT  3.692 9.504 3.779 9.528 ;
     RECT  3.692 32.16 3.779 33.624 ;
     RECT  2.819 54.336 3.788 55.848 ;
     RECT  3.443 56.832 3.788 57.672 ;
     RECT  3.685 13.536 3.805 14.808 ;
     RECT  3.769 43.152 3.809 50.424 ;
     RECT  3.349 6.864 3.827 8.52 ;
     RECT  3.761 36.768 3.877 37.608 ;
     RECT  3.685 38.736 3.877 42.168 ;
     RECT  3.769 25.488 3.884 30.6 ;
     RECT  3.877 36.768 3.913 42.168 ;
     RECT  3.809 43.152 3.913 44.088 ;
     RECT  3.733 83.808 3.923 84.984 ;
     RECT  2.908 62.544 3.925 64.968 ;
     RECT  3.341 66.096 3.925 82.056 ;
     RECT  3.805 13.056 3.953 14.808 ;
     RECT  3.925 62.544 3.953 82.056 ;
     RECT  3.953 67.824 3.961 82.056 ;
     RECT  3.413 16.752 3.971 20.616 ;
     RECT  3.788 54.336 3.971 57.672 ;
     RECT  3.884 25.488 3.985 30.984 ;
     RECT  3.985 24.96 4.057 30.984 ;
     RECT  3.953 13.44 4.061 14.808 ;
     RECT  3.097 51.648 4.093 53.304 ;
     RECT  3.971 54.336 4.093 55.32 ;
     RECT  3.953 62.544 4.097 66.696 ;
     RECT  3.685 60.96 4.129 61.368 ;
     RECT  4.129 22.752 4.165 22.776 ;
     RECT  4.129 60.96 4.165 61.512 ;
     RECT  4.097 62.544 4.165 65.112 ;
     RECT  3.769 59.328 4.193 59.784 ;
     RECT  3.923 83.808 4.211 84.408 ;
     RECT  3.779 32.592 4.237 33.624 ;
     RECT  3.347 34.752 4.237 35.544 ;
     RECT  4.093 51.648 4.241 55.32 ;
     RECT  4.193 59.28 4.277 59.784 ;
     RECT  4.061 13.536 4.309 14.808 ;
     RECT  3.809 45.12 4.316 50.424 ;
     RECT  4.241 51.648 4.316 55.128 ;
     RECT  3.961 67.92 4.337 82.056 ;
     RECT  4.268 8.88 4.355 8.904 ;
     RECT  3.829 10.752 4.357 10.776 ;
     RECT  3.971 17.664 4.385 20.616 ;
     RECT  4.057 24.096 4.421 30.984 ;
     RECT  4.337 67.92 4.421 82.152 ;
     RECT  4.237 32.592 4.46 35.544 ;
     RECT  3.913 36.768 4.46 44.088 ;
     RECT  4.165 21.984 4.493 22.776 ;
     RECT  4.165 60.96 4.493 65.112 ;
     RECT  4.421 67.92 4.493 81.576 ;
     RECT  4.46 32.592 4.499 44.088 ;
     RECT  4.277 59.328 4.501 59.784 ;
     RECT  4.493 60.96 4.501 61.656 ;
     RECT  4.493 68.112 4.547 81.576 ;
     RECT  4.385 17.856 4.597 20.616 ;
     RECT  4.211 83.808 4.597 83.832 ;
     RECT  4.421 26.496 4.643 30.984 ;
     RECT  4.097 66.096 4.643 66.696 ;
     RECT  4.357 10.752 4.673 11.4 ;
     RECT  4.597 17.856 4.673 20.664 ;
     RECT  4.643 26.784 4.741 30.984 ;
     RECT  4.499 40.32 4.837 44.088 ;
     RECT  4.316 45.12 4.837 55.128 ;
     RECT  4.673 17.952 4.921 20.664 ;
     RECT  4.597 83.232 4.921 83.832 ;
     RECT  4.813 9.936 4.931 10.344 ;
     RECT  4.309 13.536 4.931 14.856 ;
     RECT  4.421 24.096 4.931 25.512 ;
     RECT  4.741 85.488 4.931 85.512 ;
     RECT  3.971 56.448 4.957 57.672 ;
     RECT  4.741 26.784 4.979 31.656 ;
     RECT  4.493 22.752 4.993 22.776 ;
     RECT  4.921 82.656 5.005 83.832 ;
     RECT  4.94 12.528 5.027 12.552 ;
     RECT  4.673 11.376 5.029 11.4 ;
     RECT  4.931 24.096 5.036 24.408 ;
     RECT  4.931 14.784 5.105 14.856 ;
     RECT  4.993 22.752 5.123 22.968 ;
     RECT  5.036 24.048 5.123 24.408 ;
     RECT  5.123 22.752 5.141 22.776 ;
     RECT  5.029 11.376 5.213 11.976 ;
     RECT  4.643 66.432 5.245 66.696 ;
     RECT  5.105 14.784 5.357 14.808 ;
     RECT  4.547 69.504 5.363 81.576 ;
     RECT  4.957 3.6 5.389 3.624 ;
     RECT  4.921 17.952 5.393 21.528 ;
     RECT  5.245 66.432 5.393 66.792 ;
     RECT  5.389 5.136 5.425 5.16 ;
     RECT  4.957 56.448 5.461 57.816 ;
     RECT  4.501 59.328 5.461 61.656 ;
     RECT  5.065 13.296 5.465 13.32 ;
     RECT  4.499 32.88 5.497 39.24 ;
     RECT  4.837 40.32 5.497 55.128 ;
     RECT  5.393 19.536 5.501 21.528 ;
     RECT  4.489 16.32 5.533 16.344 ;
     RECT  5.453 86.256 5.537 86.28 ;
     RECT  5.497 32.88 5.557 55.128 ;
     RECT  5.461 56.448 5.557 61.656 ;
     RECT  4.493 62.736 5.557 65.112 ;
     RECT  5.557 32.88 5.569 55.464 ;
     RECT  5.389 3.6 5.605 4.056 ;
     RECT  5.569 32.352 5.605 55.464 ;
     RECT  5.557 56.448 5.605 65.112 ;
     RECT  5.393 66.432 5.605 66.744 ;
     RECT  5.005 83.136 5.645 83.832 ;
     RECT  5.363 69.504 5.653 80.424 ;
     RECT  5.533 15.936 5.677 16.344 ;
     RECT  5.501 19.584 5.701 21.528 ;
     RECT  4.931 25.488 5.713 25.512 ;
     RECT  4.979 26.784 5.713 31.32 ;
     RECT  5.125 84.96 5.717 84.984 ;
     RECT  5.645 83.808 5.749 83.832 ;
     RECT  5.653 69.408 5.789 80.424 ;
     RECT  5.713 25.488 5.825 31.32 ;
     RECT  5.363 81.552 5.845 81.576 ;
     RECT  5.425 5.136 5.857 5.256 ;
     RECT  3.827 6.864 5.857 7.416 ;
     RECT  4.931 10.032 5.939 10.344 ;
     RECT  5.857 5.136 5.965 7.416 ;
     RECT  5.123 24.096 5.989 24.408 ;
     RECT  5.825 25.488 5.989 30.936 ;
     RECT  5.677 15.792 5.996 16.344 ;
     RECT  5.605 32.352 6.035 66.744 ;
     RECT  5.213 11.808 6.041 11.976 ;
     RECT  5.749 83.808 6.077 84.408 ;
     RECT  6.077 83.808 6.149 84.36 ;
     RECT  5.605 3.504 6.217 4.056 ;
     RECT  5.996 15.792 6.221 16.536 ;
     RECT  5.845 81.552 6.229 82.152 ;
     RECT  5.701 19.584 6.277 22.2 ;
     RECT  5.393 17.952 6.289 18.504 ;
     RECT  6.277 19.584 6.329 23.016 ;
     RECT  5.965 5.088 6.401 7.416 ;
     RECT  5.789 69.504 6.421 80.424 ;
     RECT  6.229 81.552 6.421 82.728 ;
     RECT  4.547 68.112 6.433 68.376 ;
     RECT  6.428 11.376 6.515 11.4 ;
     RECT  6.289 17.856 6.545 18.504 ;
     RECT  5.989 24.096 6.545 30.936 ;
     RECT  6.329 22.992 6.659 23.016 ;
     RECT  6.545 24.096 6.668 27.672 ;
     RECT  6.221 15.792 6.689 16.008 ;
     RECT  6.329 19.584 6.689 21.672 ;
     RECT  6.668 23.184 6.755 27.672 ;
     RECT  6.401 6.864 6.757 7.416 ;
     RECT  6.421 85.488 6.797 85.512 ;
     RECT  6.545 17.856 6.812 18.216 ;
     RECT  6.217 3.456 6.829 4.056 ;
     RECT  6.401 5.088 6.829 5.496 ;
     RECT  6.757 6.864 6.829 7.464 ;
     RECT  6.812 17.616 6.829 18.216 ;
     RECT  6.035 51.552 6.829 66.744 ;
     RECT  6.149 83.808 6.833 84.168 ;
     RECT  6.421 69.504 6.853 82.728 ;
     RECT  6.833 83.808 6.853 84.12 ;
     RECT  5.939 10.32 6.901 10.344 ;
     RECT  6.433 67.776 6.901 68.376 ;
     RECT  6.853 69.504 6.901 84.12 ;
     RECT  6.901 9.888 6.973 10.344 ;
     RECT  6.035 32.352 7.007 50.136 ;
     RECT  7.007 32.016 7.037 50.136 ;
     RECT  6.829 51.552 7.037 66.792 ;
     RECT  7.037 32.016 7.093 66.792 ;
     RECT  6.901 67.776 7.093 84.12 ;
     RECT  7.081 13.632 7.153 13.656 ;
     RECT  6.545 28.752 7.285 30.936 ;
     RECT  7.093 32.016 7.285 84.12 ;
     RECT  7.045 86.208 7.409 86.28 ;
     RECT  6.86 12.528 7.477 12.552 ;
     RECT  7.153 13.632 7.477 14.232 ;
     RECT  6.689 19.68 7.477 21.672 ;
     RECT  6.755 23.328 7.573 27.672 ;
     RECT  7.285 28.752 7.573 84.12 ;
     RECT  6.829 3.456 7.585 5.496 ;
     RECT  7.477 12.528 7.585 14.232 ;
     RECT  6.973 9.888 7.621 11.256 ;
     RECT  7.585 12.528 7.669 14.808 ;
     RECT  6.689 15.888 7.669 16.008 ;
     RECT  7.409 86.208 7.763 86.232 ;
     RECT  7.585 3.408 7.808 5.496 ;
     RECT  6.829 6.864 7.808 7.992 ;
     RECT  7.621 9.504 7.808 11.256 ;
     RECT  7.669 12.528 7.808 16.008 ;
     RECT  6.829 17.136 7.808 18.216 ;
     RECT  7.477 19.68 7.808 22.104 ;
     RECT  7.573 23.328 7.808 84.12 ;
     RECT  7.808 2.148 7.912 84.252 ;
     RECT  7.912 2.418 8.005 84.252 ;
     RECT  8.005 2.418 8.104 85.08 ;
     RECT  8.104 3.456 8.201 5.304 ;
     RECT  8.104 22.608 8.201 85.08 ;
     RECT  8.104 16.32 8.243 21.576 ;
     RECT  8.201 22.608 8.243 84.36 ;
     RECT  8.243 16.32 8.245 21.48 ;
     RECT  8.245 17.952 8.273 21.48 ;
     RECT  8.243 22.8 8.483 84.36 ;
     RECT  8.483 22.8 8.669 80.904 ;
     RECT  8.483 82.08 8.705 84.36 ;
     RECT  8.629 86.256 8.713 86.28 ;
     RECT  8.104 13.392 8.819 14.376 ;
     RECT  8.104 6.864 8.857 11.4 ;
     RECT  8.705 82.128 8.867 84.36 ;
     RECT  8.867 82.128 8.921 82.776 ;
     RECT  8.921 82.176 8.993 82.776 ;
     RECT  8.953 85.488 9.037 85.512 ;
     RECT  8.201 5.088 9.065 5.304 ;
     RECT  8.857 9.216 9.097 11.4 ;
     RECT  8.669 22.8 9.203 42.312 ;
     RECT  8.273 17.952 9.209 21.288 ;
     RECT  8.201 3.456 9.245 3.96 ;
     RECT  9.209 17.952 9.263 18.84 ;
     RECT  8.993 82.608 9.325 82.776 ;
     RECT  8.669 43.344 9.353 80.904 ;
     RECT  9.065 5.232 9.425 5.304 ;
     RECT  9.209 20.016 9.452 21.288 ;
     RECT  8.245 16.32 9.457 16.536 ;
     RECT  9.457 15.84 9.493 16.536 ;
     RECT  9.263 17.568 9.493 18.84 ;
     RECT  9.493 15.84 9.497 18.84 ;
     RECT  8.819 13.392 9.529 14.232 ;
     RECT  9.203 23.808 9.641 42.312 ;
     RECT  9.497 15.84 9.692 18.792 ;
     RECT  8.857 6.864 9.713 8.04 ;
     RECT  9.452 20.016 9.733 21.624 ;
     RECT  9.203 22.8 9.733 22.824 ;
     RECT  9.097 9.216 9.821 11.544 ;
     RECT  9.529 13.056 9.961 14.232 ;
     RECT  9.692 15.648 9.961 18.792 ;
     RECT  9.353 69.984 9.997 80.904 ;
     RECT  9.961 13.056 10.019 18.792 ;
     RECT  9.997 69.984 10.069 81.528 ;
     RECT  9.325 82.608 10.069 82.68 ;
     RECT  9.245 3.84 10.141 3.96 ;
     RECT  9.733 20.016 10.181 22.824 ;
     RECT  10.181 22.176 10.22 22.824 ;
     RECT  9.641 23.808 10.22 25.752 ;
     RECT  10.069 69.984 10.259 82.68 ;
     RECT  10.019 13.056 10.397 16.536 ;
     RECT  10.22 22.176 10.403 25.752 ;
     RECT  10.403 23.856 10.433 25.752 ;
     RECT  9.821 9.216 10.537 11.208 ;
     RECT  10.141 3.84 10.645 4.488 ;
     RECT  10.433 24.384 10.645 25.752 ;
     RECT  9.641 26.736 10.645 42.312 ;
     RECT  9.353 43.344 10.645 68.904 ;
     RECT  9.713 6.864 10.681 7.752 ;
     RECT  10.537 8.784 10.681 11.208 ;
     RECT  10.259 69.984 10.693 80.952 ;
     RECT  10.181 20.016 10.732 21.144 ;
     RECT  10.397 13.056 10.739 14.232 ;
     RECT  10.645 24.384 10.787 68.904 ;
     RECT  10.259 82.08 10.793 82.68 ;
     RECT  10.403 22.176 10.829 22.824 ;
     RECT  10.829 22.32 10.835 22.824 ;
     RECT  8.867 83.808 10.853 84.36 ;
     RECT  10.693 69.936 10.861 80.952 ;
     RECT  10.739 13.056 10.885 13.608 ;
     RECT  10.793 82.608 10.897 82.68 ;
     RECT  10.897 82.608 10.937 82.728 ;
     RECT  10.019 17.952 10.969 18.792 ;
     RECT  10.732 20.016 10.969 20.616 ;
     RECT  10.885 12.48 11.009 13.608 ;
     RECT  10.397 15.408 11.036 16.536 ;
     RECT  10.969 17.952 11.036 20.616 ;
     RECT  9.961 5.472 11.077 5.496 ;
     RECT  10.681 6.864 11.077 11.208 ;
     RECT  10.787 24.384 11.117 68.376 ;
     RECT  11.077 5.472 11.297 11.208 ;
     RECT  10.645 3.312 11.333 4.488 ;
     RECT  11.009 13.344 11.363 13.608 ;
     RECT  11.036 15.408 11.365 20.616 ;
     RECT  10.861 69.552 11.365 80.952 ;
     RECT  11.297 9.84 11.473 11.208 ;
     RECT  10.853 83.808 11.509 84.936 ;
     RECT  11.363 13.392 11.549 13.608 ;
     RECT  11.473 9.84 11.605 11.496 ;
     RECT  11.333 3.36 11.617 4.488 ;
     RECT  11.297 5.472 11.617 8.088 ;
     RECT  11.117 24.384 11.621 68.136 ;
     RECT  11.509 83.808 11.693 85.512 ;
     RECT  11.365 69.552 11.699 81.48 ;
     RECT  11.617 3.36 11.801 8.088 ;
     RECT  11.801 6.288 11.837 8.088 ;
     RECT  11.365 14.832 11.869 20.616 ;
     RECT  11.549 13.584 11.905 13.608 ;
     RECT  11.869 14.832 11.905 20.856 ;
     RECT  11.693 83.808 11.917 84.936 ;
     RECT  10.937 82.704 11.941 82.728 ;
     RECT  11.917 83.808 11.941 84.408 ;
     RECT  11.621 24.384 12.085 27.336 ;
     RECT  11.941 82.704 12.085 84.408 ;
     RECT  11.801 3.36 12.131 5.064 ;
     RECT  11.905 13.584 12.188 20.856 ;
     RECT  11.605 9.84 12.229 12.024 ;
     RECT  11.699 69.696 12.257 81.48 ;
     RECT  12.085 82.56 12.257 84.408 ;
     RECT  12.085 23.808 12.325 27.336 ;
     RECT  11.621 28.512 12.332 68.136 ;
     RECT  10.835 22.32 12.373 22.488 ;
     RECT  12.325 23.712 12.373 27.336 ;
     RECT  12.373 22.32 12.409 27.336 ;
     RECT  12.229 9.84 12.481 12.072 ;
     RECT  12.188 13.584 12.517 21.288 ;
     RECT  12.409 22.272 12.517 27.336 ;
     RECT  12.517 13.344 12.589 27.336 ;
     RECT  12.481 9.744 12.625 12.072 ;
     RECT  12.332 28.512 12.805 68.712 ;
     RECT  12.257 69.696 12.805 84.408 ;
     RECT  12.805 28.512 12.877 84.408 ;
     RECT  12.877 28.464 13.141 84.408 ;
     RECT  12.337 2.832 13.208 2.856 ;
     RECT  12.131 4.128 13.208 5.064 ;
     RECT  11.837 6.288 13.208 7.752 ;
     RECT  12.625 9.072 13.208 12.072 ;
     RECT  12.589 13.344 13.208 27.384 ;
     RECT  13.141 28.464 13.208 84.936 ;
     RECT  13.208 2.148 13.312 84.936 ;
     RECT  13.312 2.418 13.504 84.936 ;
     RECT  13.504 46.896 13.601 82.824 ;
     RECT  13.504 2.832 13.619 7.992 ;
     RECT  13.601 46.896 13.667 82.728 ;
     RECT  13.504 83.808 13.813 84.936 ;
     RECT  13.619 3.168 13.859 7.992 ;
     RECT  13.813 83.808 14.177 85.032 ;
     RECT  13.859 3.168 14.243 3.432 ;
     RECT  14.177 84.192 14.461 85.032 ;
     RECT  13.504 9.072 14.501 45.768 ;
     RECT  14.501 9.072 14.531 28.536 ;
     RECT  13.667 82.656 14.627 82.728 ;
     RECT  14.531 9.072 14.645 18.216 ;
     RECT  13.667 46.896 14.857 81.528 ;
     RECT  13.859 4.56 14.965 7.992 ;
     RECT  14.645 9.072 14.965 13.08 ;
     RECT  14.461 84.192 14.965 85.512 ;
     RECT  14.857 46.848 15.001 81.528 ;
     RECT  14.965 84.192 15.005 86.232 ;
     RECT  14.501 29.568 15.157 45.768 ;
     RECT  15.001 46.752 15.157 81.528 ;
     RECT  15.005 86.208 15.203 86.232 ;
     RECT  14.243 3.264 15.217 3.432 ;
     RECT  14.965 4.56 15.217 13.08 ;
     RECT  14.531 19.296 15.293 28.536 ;
     RECT  15.217 3.264 15.317 13.08 ;
     RECT  15.317 2.832 15.401 13.08 ;
     RECT  15.293 23.952 15.493 28.536 ;
     RECT  15.157 29.568 15.493 81.528 ;
     RECT  15.401 3.264 15.509 13.08 ;
     RECT  14.645 14.16 15.577 18.216 ;
     RECT  15.293 19.296 15.577 22.488 ;
     RECT  15.509 3.312 15.613 13.08 ;
     RECT  15.577 14.16 15.613 22.488 ;
     RECT  15.613 3.312 15.617 22.488 ;
     RECT  15.493 23.952 15.725 81.528 ;
     RECT  15.617 5.52 15.761 22.488 ;
     RECT  15.677 86.256 15.761 86.28 ;
     RECT  15.005 84.192 15.793 84.984 ;
     RECT  15.725 24.384 15.833 81.528 ;
     RECT  15.833 28.608 15.941 81.528 ;
     RECT  15.941 28.608 15.971 81 ;
     RECT  14.627 82.656 15.973 82.68 ;
     RECT  15.617 3.312 16.129 4.536 ;
     RECT  15.973 82.08 16.157 82.68 ;
     RECT  15.761 9.024 16.163 22.488 ;
     RECT  16.163 22.464 16.333 22.488 ;
     RECT  16.129 3.312 16.373 3.384 ;
     RECT  15.793 83.808 16.508 84.984 ;
     RECT  16.157 82.656 16.513 82.68 ;
     RECT  16.508 83.664 16.513 84.984 ;
     RECT  16.333 22.464 16.517 23.16 ;
     RECT  16.513 82.656 16.547 84.984 ;
     RECT  16.547 84.96 16.585 84.984 ;
     RECT  16.129 4.368 16.621 4.536 ;
     RECT  15.761 5.52 16.621 7.992 ;
     RECT  16.621 4.368 16.661 7.992 ;
     RECT  16.373 3.312 16.697 3.336 ;
     RECT  16.547 82.656 16.769 83.784 ;
     RECT  16.585 84.96 16.787 85.56 ;
     RECT  15.833 24.384 16.837 27.528 ;
     RECT  16.661 4.416 16.841 7.992 ;
     RECT  16.841 4.608 16.981 7.992 ;
     RECT  16.163 9.024 16.981 21.144 ;
     RECT  15.971 28.944 17.009 81 ;
     RECT  16.517 22.464 17.021 22.92 ;
     RECT  16.981 2.832 17.065 2.856 ;
     RECT  17.009 28.944 17.077 81.528 ;
     RECT  17.077 28.896 17.093 81.528 ;
     RECT  17.021 22.464 17.221 22.632 ;
     RECT  16.981 4.608 17.305 21.144 ;
     RECT  17.221 22.176 17.305 22.632 ;
     RECT  16.769 82.656 17.305 83.256 ;
     RECT  16.787 84.96 17.315 85.512 ;
     RECT  17.305 82.464 17.389 83.256 ;
     RECT  17.093 28.896 17.485 81.48 ;
     RECT  17.315 84.96 17.585 84.984 ;
     RECT  17.305 4.608 17.597 22.632 ;
     RECT  16.837 24.384 17.701 27.672 ;
     RECT  17.701 24.288 17.881 27.672 ;
     RECT  17.585 84.336 17.939 84.984 ;
     RECT  17.389 82.656 17.948 83.256 ;
     RECT  17.939 84.336 17.948 84.36 ;
     RECT  17.845 3.12 18.025 3.144 ;
     RECT  17.597 4.608 18.025 13.656 ;
     RECT  17.597 14.688 18.092 22.632 ;
     RECT  17.881 24.192 18.092 27.672 ;
     RECT  17.485 28.752 18.181 81.48 ;
     RECT  18.181 28.704 18.241 81.48 ;
     RECT  18.241 28.704 18.373 81.672 ;
     RECT  17.948 82.656 18.373 84.36 ;
     RECT  17.909 86.208 18.421 86.232 ;
     RECT  18.025 3.12 18.469 13.656 ;
     RECT  18.421 86.208 18.493 86.28 ;
     RECT  18.092 14.688 18.529 27.672 ;
     RECT  18.373 28.704 18.529 84.36 ;
     RECT  18.469 2.784 18.608 13.656 ;
     RECT  18.529 14.688 18.608 84.36 ;
     RECT  18.493 85.488 18.611 86.28 ;
     RECT  18.608 2.148 18.712 84.36 ;
     RECT  18.611 86.256 18.755 86.28 ;
     RECT  18.712 2.418 18.904 84.36 ;
     RECT  18.904 2.544 18.965 84.36 ;
     RECT  18.965 2.544 19.043 5.64 ;
     RECT  18.965 6.672 19.141 84.36 ;
     RECT  19.141 6.672 19.187 84.936 ;
     RECT  19.043 2.544 19.283 4.248 ;
     RECT  19.043 5.232 19.325 5.64 ;
     RECT  19.283 3.36 19.397 4.248 ;
     RECT  19.187 14.688 19.523 84.936 ;
     RECT  19.523 22.176 19.715 84.936 ;
     RECT  19.715 22.464 19.717 84.936 ;
     RECT  19.717 22.464 19.753 85.512 ;
     RECT  19.523 14.688 19.793 21.144 ;
     RECT  19.753 22.464 19.907 85.608 ;
     RECT  19.907 22.464 19.937 83.976 ;
     RECT  19.397 3.408 20.293 4.248 ;
     RECT  19.325 5.52 20.293 5.64 ;
     RECT  19.187 6.672 20.293 13.656 ;
     RECT  19.907 84.96 20.293 85.608 ;
     RECT  20.293 84.96 20.435 86.28 ;
     RECT  19.937 22.464 20.476 83.832 ;
     RECT  20.293 5.52 20.509 13.656 ;
     RECT  20.476 22.464 20.549 82.104 ;
     RECT  20.293 3.408 20.675 4.296 ;
     RECT  20.509 5.28 20.675 13.656 ;
     RECT  20.435 84.96 20.723 85.56 ;
     RECT  19.793 14.784 20.725 21.144 ;
     RECT  20.549 22.464 20.725 81.624 ;
     RECT  20.476 83.184 21.02 83.832 ;
     RECT  20.675 5.472 21.061 13.656 ;
     RECT  20.725 14.784 21.061 81.624 ;
     RECT  20.675 3.408 21.085 4.248 ;
     RECT  21.02 83.184 21.107 83.928 ;
     RECT  20.723 84.96 21.109 84.984 ;
     RECT  21.061 5.472 21.197 81.624 ;
     RECT  21.197 8.16 21.203 81.624 ;
     RECT  21.203 8.16 21.233 22.488 ;
     RECT  21.085 2.832 21.305 4.248 ;
     RECT  21.109 84.912 21.437 84.984 ;
     RECT  21.107 83.184 21.445 83.256 ;
     RECT  21.437 84.336 21.521 84.984 ;
     RECT  21.445 82.608 21.665 83.256 ;
     RECT  21.203 23.664 21.673 81.624 ;
     RECT  21.521 84.96 21.701 84.984 ;
     RECT  21.665 82.656 22.069 83.256 ;
     RECT  21.733 85.488 22.097 85.512 ;
     RECT  21.305 3.264 22.129 4.248 ;
     RECT  21.197 5.472 22.129 7.176 ;
     RECT  22.129 3.264 22.309 7.176 ;
     RECT  22.309 2.832 22.403 7.176 ;
     RECT  22.403 3.024 22.489 7.176 ;
     RECT  21.233 8.208 22.489 22.488 ;
     RECT  21.673 23.664 22.565 81.528 ;
     RECT  22.069 82.656 22.693 83.88 ;
     RECT  22.565 28.992 22.745 81.528 ;
     RECT  22.957 84.96 23.075 84.984 ;
     RECT  22.489 3.024 23.112 22.488 ;
     RECT  22.565 23.664 23.112 27.912 ;
     RECT  22.693 82.656 23.425 83.976 ;
     RECT  23.425 82.656 23.699 84.408 ;
     RECT  23.112 3.024 23.713 27.912 ;
     RECT  22.745 28.992 23.713 81.48 ;
     RECT  23.713 3.024 23.821 81.48 ;
     RECT  23.821 2.832 23.929 81.48 ;
     RECT  23.699 82.656 23.929 84.36 ;
     RECT  23.929 2.832 24.008 84.36 ;
     RECT  24.008 2.148 24.112 84.36 ;
     RECT  23.857 85.488 24.229 85.512 ;
     RECT  24.112 2.418 24.304 84.36 ;
     RECT  24.229 85.488 24.419 86.232 ;
     RECT  24.304 3.024 24.467 84.36 ;
     RECT  24.419 85.488 24.697 85.512 ;
     RECT  24.467 3.024 24.761 82.776 ;
     RECT  24.467 83.808 24.908 84.36 ;
     RECT  24.761 3.072 25.235 82.776 ;
     RECT  24.908 83.808 25.337 84.984 ;
     RECT  25.441 86.208 25.571 86.232 ;
     RECT  25.235 28.896 25.585 82.776 ;
     RECT  25.337 83.808 25.585 83.928 ;
     RECT  25.585 28.896 25.859 83.928 ;
     RECT  25.235 3.072 26.089 27.912 ;
     RECT  25.859 28.896 26.237 82.728 ;
     RECT  26.089 2.88 26.243 27.912 ;
     RECT  26.243 3.216 26.435 27.912 ;
     RECT  25.337 84.96 26.485 84.984 ;
     RECT  26.485 84.96 26.581 85.512 ;
     RECT  25.859 83.808 26.597 83.928 ;
     RECT  26.597 83.808 26.633 83.832 ;
     RECT  26.581 84.96 26.737 86.232 ;
     RECT  26.737 84.912 26.771 86.232 ;
     RECT  26.237 28.944 26.953 82.728 ;
     RECT  26.953 28.944 26.993 83.256 ;
     RECT  26.771 84.912 27.011 85.56 ;
     RECT  27.011 85.488 27.203 85.56 ;
     RECT  27.203 85.536 27.395 85.56 ;
     RECT  26.993 29.616 27.749 83.256 ;
     RECT  26.435 3.216 27.781 27.816 ;
     RECT  27.749 83.232 27.923 83.256 ;
     RECT  27.781 3.216 28.321 28.536 ;
     RECT  28.412 84.96 28.465 84.984 ;
     RECT  28.321 2.832 28.537 28.536 ;
     RECT  27.749 29.616 28.537 82.104 ;
     RECT  27.925 83.808 28.789 83.832 ;
     RECT  28.465 84.96 28.925 85.512 ;
     RECT  28.537 2.832 28.981 82.104 ;
     RECT  28.789 83.808 29.077 83.976 ;
     RECT  28.925 84.96 29.077 86.28 ;
     RECT  28.981 2.832 29.125 82.632 ;
     RECT  29.077 83.808 29.261 86.28 ;
     RECT  29.261 83.808 29.267 84.936 ;
     RECT  29.261 86.208 29.363 86.28 ;
     RECT  29.125 2.832 29.408 82.68 ;
     RECT  29.267 83.808 29.408 84.408 ;
     RECT  29.408 2.148 29.459 84.408 ;
     RECT  29.459 2.148 29.512 84.36 ;
     RECT  29.512 2.418 29.704 84.36 ;
     RECT  29.363 86.208 29.891 86.232 ;
     RECT  29.704 3.024 29.981 84.36 ;
     RECT  29.981 29.376 30.179 84.36 ;
     RECT  30.179 83.808 30.557 84.36 ;
     RECT  30.557 83.808 30.563 83.928 ;
     RECT  29.981 3.024 31.004 28.248 ;
     RECT  30.179 29.376 31.004 82.68 ;
     RECT  31.004 3.024 31.189 82.68 ;
     RECT  30.997 86.256 31.333 86.28 ;
     RECT  30.563 83.808 31.597 83.832 ;
     RECT  31.189 3.024 31.777 82.728 ;
     RECT  31.777 2.976 32.209 82.728 ;
     RECT  32.209 2.976 32.245 82.776 ;
     RECT  31.597 83.808 32.293 83.928 ;
     RECT  32.293 83.808 32.317 84.36 ;
     RECT  31.333 85.488 32.317 86.28 ;
     RECT  32.245 2.736 32.341 82.776 ;
     RECT  32.341 2.496 32.389 82.776 ;
     RECT  32.317 83.808 32.389 86.28 ;
     RECT  32.389 2.496 32.435 86.28 ;
     RECT  32.435 2.496 32.465 86.232 ;
     RECT  32.465 84.96 32.531 86.232 ;
     RECT  32.531 85.584 32.717 86.232 ;
     RECT  32.465 2.496 33.049 83.832 ;
     RECT  33.049 2.496 33.397 83.256 ;
     RECT  32.717 86.112 33.509 86.232 ;
     RECT  33.509 86.112 33.635 86.136 ;
     RECT  33.692 84.912 33.779 84.936 ;
     RECT  33.397 2.304 34.213 83.256 ;
     RECT  34.213 2.304 34.808 83.832 ;
     RECT  33.937 84.96 34.808 85.512 ;
     RECT  34.808 2.148 34.837 85.512 ;
     RECT  34.837 2.148 34.912 86.088 ;
     RECT  34.912 2.418 35.077 86.088 ;
     RECT  35.077 2.418 35.104 86.184 ;
     RECT  35.104 2.592 35.245 86.184 ;
     RECT  35.245 84.336 35.273 86.184 ;
     RECT  35.273 85.488 35.324 86.184 ;
     RECT  35.324 85.488 35.411 86.328 ;
     RECT  35.411 85.488 35.555 85.56 ;
     RECT  35.555 85.536 36.083 85.56 ;
     RECT  35.245 2.592 36.277 83.256 ;
     RECT  35.273 84.336 36.277 84.36 ;
     RECT  36.277 2.4 36.533 84.36 ;
     RECT  36.533 2.592 36.709 84.36 ;
     RECT  36.709 2.592 36.851 84.936 ;
     RECT  36.469 86.16 36.908 86.232 ;
     RECT  36.908 86.16 36.995 86.328 ;
     RECT  36.851 2.592 37.217 84.36 ;
     RECT  36.995 86.16 37.321 86.232 ;
     RECT  37.217 2.592 37.715 83.832 ;
     RECT  37.715 28.464 37.757 83.832 ;
     RECT  37.321 85.488 38.099 86.232 ;
     RECT  37.757 29.76 38.341 83.832 ;
     RECT  38.341 29.76 38.473 84.408 ;
     RECT  37.715 2.592 38.78 27.48 ;
     RECT  37.757 28.464 38.78 28.776 ;
     RECT  38.78 2.592 38.833 28.776 ;
     RECT  38.473 29.76 38.867 84.504 ;
     RECT  38.833 2.352 39.265 28.776 ;
     RECT  38.867 29.76 39.265 84.216 ;
     RECT  38.099 85.488 39.541 85.512 ;
     RECT  39.265 2.352 39.949 84.216 ;
     RECT  39.541 85.488 40.169 86.232 ;
     RECT  39.949 2.352 40.208 84.408 ;
     RECT  40.208 2.148 40.307 84.408 ;
     RECT  40.307 2.148 40.312 84.36 ;
     RECT  40.312 2.352 40.429 84.36 ;
     RECT  40.429 2.352 40.504 83.982 ;
     RECT  40.597 86.256 40.889 86.28 ;
     RECT  40.504 2.352 41.393 83.784 ;
     RECT  41.221 86.208 41.393 86.232 ;
     RECT  41.393 2.592 41.525 83.784 ;
     RECT  41.317 84.96 41.525 84.984 ;
     RECT  41.525 2.592 41.789 84.984 ;
     RECT  41.789 2.592 42.301 84.12 ;
     RECT  42.301 83.808 42.757 84.12 ;
     RECT  42.181 85.488 43.004 85.512 ;
     RECT  43.004 85.488 43.091 86.328 ;
     RECT  42.757 83.808 43.109 84.36 ;
     RECT  43.091 85.488 43.109 86.232 ;
     RECT  42.301 2.592 43.153 82.824 ;
     RECT  43.153 2.352 43.429 82.824 ;
     RECT  43.109 83.808 43.429 86.232 ;
     RECT  43.429 2.352 44.053 86.232 ;
     RECT  44.053 2.352 44.147 86.28 ;
     RECT  44.147 2.352 44.161 85.512 ;
     RECT  44.161 2.304 44.345 85.512 ;
     RECT  44.345 31.92 44.483 85.512 ;
     RECT  44.483 85.488 44.993 85.512 ;
     RECT  44.483 31.92 45.173 84.408 ;
     RECT  44.345 2.304 45.349 30.792 ;
     RECT  45.173 31.92 45.349 84.252 ;
     RECT  45.349 2.304 45.608 84.252 ;
     RECT  45.608 2.148 45.712 84.252 ;
     RECT  45.733 86.016 46.019 86.232 ;
     RECT  46.019 86.016 46.115 86.136 ;
     RECT  45.712 2.304 46.141 84.252 ;
     RECT  46.115 86.112 46.163 86.136 ;
     RECT  46.141 2.304 46.793 84.408 ;
     RECT  46.793 2.352 46.825 84.408 ;
     RECT  46.825 2.352 47.077 84.984 ;
     RECT  47.077 2.352 47.171 85.512 ;
     RECT  47.171 32.112 47.693 85.512 ;
     RECT  47.693 32.112 47.837 84.36 ;
     RECT  47.171 2.352 47.909 31.128 ;
     RECT  47.909 2.496 48.165 31.128 ;
     RECT  47.837 32.112 48.165 83.88 ;
     RECT  47.693 85.488 48.325 85.512 ;
     RECT  48.165 2.496 48.809 83.88 ;
     RECT  48.325 85.488 49.333 86.232 ;
     RECT  49.333 85.488 49.417 86.28 ;
     RECT  49.417 84.96 49.597 86.28 ;
     RECT  48.809 2.592 49.957 83.88 ;
     RECT  49.597 84.864 49.957 86.28 ;
     RECT  49.957 2.592 50.012 86.28 ;
     RECT  50.012 2.592 50.099 86.328 ;
     RECT  50.281 0.96 50.389 0.984 ;
     RECT  50.099 2.592 50.573 86.28 ;
     RECT  50.389 0.96 50.713 1.416 ;
     RECT  50.573 2.592 50.713 86.232 ;
     RECT  50.713 0.96 50.929 86.232 ;
     RECT  50.929 0.576 51.365 86.232 ;
     RECT  51.365 0.576 51.469 33.288 ;
     RECT  51.365 34.464 51.644 86.232 ;
     RECT  51.644 34.464 51.731 86.328 ;
     RECT  51.469 0.24 51.977 33.288 ;
     RECT  51.731 34.464 51.977 86.28 ;
     RECT  51.977 34.464 52.013 50.568 ;
     RECT  51.977 5.136 52.085 33.288 ;
     RECT  52.085 5.184 52.157 33.288 ;
     RECT  51.977 85.2 52.163 86.28 ;
     RECT  52.013 41.904 52.301 50.568 ;
     RECT  51.977 51.984 52.481 84.168 ;
     RECT  52.157 5.184 52.547 33.096 ;
     RECT  52.013 34.464 52.589 40.632 ;
     RECT  52.547 24.624 52.625 33.096 ;
     RECT  52.589 34.656 52.625 40.632 ;
     RECT  52.481 55.92 52.661 84.168 ;
     RECT  52.547 5.184 52.697 23.304 ;
     RECT  52.301 41.952 52.733 50.568 ;
     RECT  52.481 51.984 52.913 54.936 ;
     RECT  52.697 5.184 52.949 17.4 ;
     RECT  52.661 58.56 52.985 84.168 ;
     RECT  52.949 5.184 53.021 16.392 ;
     RECT  52.733 42.144 53.021 50.568 ;
     RECT  53.021 5.184 53.053 10.632 ;
     RECT  52.949 17.376 53.057 17.4 ;
     RECT  52.163 85.2 53.171 86.232 ;
     RECT  52.985 61.728 53.269 84.168 ;
     RECT  53.171 85.2 53.269 86.136 ;
     RECT  51.977 0.24 53.413 4.008 ;
     RECT  53.053 5.088 53.413 10.632 ;
     RECT  53.021 46.032 53.449 50.568 ;
     RECT  52.913 51.984 53.449 52.248 ;
     RECT  52.625 34.8 53.521 40.632 ;
     RECT  52.913 53.28 53.557 54.936 ;
     RECT  52.661 55.92 53.557 57.576 ;
     RECT  52.697 18.672 53.593 23.304 ;
     RECT  52.625 24.624 53.593 32.28 ;
     RECT  53.521 34.8 53.917 40.968 ;
     RECT  53.665 17.52 54.061 17.544 ;
     RECT  53.593 18.672 54.061 32.52 ;
     RECT  54.061 17.52 54.097 32.52 ;
     RECT  53.917 34.272 54.097 40.968 ;
     RECT  53.449 46.032 54.097 52.248 ;
     RECT  53.557 53.28 54.097 57.576 ;
     RECT  52.985 58.56 54.097 60.648 ;
     RECT  53.021 42.144 54.133 45 ;
     RECT  54.097 46.032 54.133 60.648 ;
     RECT  53.269 61.728 54.133 86.136 ;
     RECT  53.021 11.616 54.169 16.392 ;
     RECT  54.097 17.52 54.169 40.968 ;
     RECT  54.169 11.616 54.205 40.968 ;
     RECT  54.133 42.096 54.205 86.136 ;
     RECT  53.413 0.24 54.385 10.632 ;
     RECT  54.385 0.048 54.673 10.632 ;
     RECT  54.205 11.616 54.673 86.136 ;
     RECT  54.673 0.048 55.033 86.136 ;
     RECT  55.033 0.048 56.124 86.376 ;
    LAYER M5 ;
     RECT  2.4 2.137 2.52 2.151 ;
     RECT  7.8 2.137 7.92 2.151 ;
     RECT  13.2 2.137 13.32 2.151 ;
     RECT  18.6 2.137 18.72 2.151 ;
     RECT  24 2.137 24.12 2.151 ;
     RECT  29.4 2.137 29.52 2.151 ;
     RECT  34.8 2.137 34.92 2.151 ;
     RECT  40.2 2.137 40.32 2.151 ;
     RECT  45.6 2.137 45.72 2.151 ;
     RECT  51 2.137 51.12 2.151 ;
     RECT  45.6 2.151 45.912 2.389 ;
     RECT  18.6 2.151 18.912 2.533 ;
     RECT  51 2.151 51.312 2.533 ;
     RECT  51 2.533 51.528 2.725 ;
     RECT  18.6 2.533 19.272 2.773 ;
     RECT  41.76 2.725 41.784 2.773 ;
     RECT  44.88 2.389 45.912 2.773 ;
     RECT  13.2 2.151 13.512 2.821 ;
     RECT  24 2.151 24.312 2.821 ;
     RECT  29.4 2.151 29.712 2.821 ;
     RECT  34.8 2.151 35.112 2.821 ;
     RECT  41.76 2.773 42.36 2.821 ;
     RECT  51 2.725 51.864 2.821 ;
     RECT  50.256 2.821 51.864 2.915 ;
     RECT  44.88 2.773 46.44 3.013 ;
     RECT  48 2.821 48.024 3.013 ;
     RECT  16.992 2.821 17.016 3.109 ;
     RECT  18.48 2.773 19.272 3.109 ;
     RECT  12.384 2.821 13.608 3.157 ;
     RECT  26.208 2.869 26.232 3.301 ;
     RECT  37.152 2.821 37.176 3.301 ;
     RECT  12.384 3.157 14.232 3.349 ;
     RECT  23.904 2.821 24.312 3.349 ;
     RECT  44.88 3.013 48.024 3.349 ;
     RECT  15.36 2.821 15.384 3.397 ;
     RECT  16.992 3.109 19.272 3.397 ;
     RECT  23.904 3.349 24.696 3.397 ;
     RECT  25.92 3.301 26.232 3.397 ;
     RECT  41.568 2.821 43.272 3.397 ;
     RECT  44.832 3.349 48.024 3.397 ;
     RECT  22.368 2.821 22.392 3.445 ;
     RECT  38.688 2.677 38.712 3.877 ;
     RECT  22.368 3.445 22.488 3.925 ;
     RECT  23.904 3.397 26.232 3.925 ;
     RECT  33.456 2.821 33.48 3.925 ;
     RECT  37.152 3.301 37.32 3.925 ;
     RECT  38.688 3.877 38.76 3.925 ;
     RECT  40.2 2.151 40.512 3.925 ;
     RECT  28.176 3.445 28.2 4.117 ;
     RECT  31.152 3.925 31.176 4.261 ;
     RECT  34.8 2.821 35.544 4.261 ;
     RECT  30.912 4.261 31.176 4.453 ;
     RECT  32.352 2.485 32.376 4.453 ;
     RECT  33.408 3.925 33.48 4.453 ;
     RECT  34.8 4.261 35.784 4.453 ;
     RECT  37.152 3.925 38.76 4.453 ;
     RECT  30.912 4.453 32.376 4.501 ;
     RECT  33.408 4.453 38.76 4.501 ;
     RECT  39.936 3.925 40.512 4.501 ;
     RECT  41.568 3.397 48.024 4.501 ;
     RECT  50.256 2.915 51.312 4.789 ;
     RECT  27.456 4.117 28.2 4.933 ;
     RECT  29.184 2.821 29.712 4.933 ;
     RECT  22.368 3.925 26.232 5.077 ;
     RECT  54.384 2.581 54.408 5.555 ;
     RECT  15.36 3.397 19.272 5.605 ;
     RECT  30.912 4.501 38.76 5.605 ;
     RECT  39.936 4.501 48.024 5.605 ;
     RECT  27.456 4.933 29.712 5.653 ;
     RECT  30.912 5.605 48.024 5.653 ;
     RECT  50.112 4.789 51.312 5.701 ;
     RECT  27.456 5.653 48.024 5.893 ;
     RECT  49.872 5.701 51.312 5.893 ;
     RECT  2.4 2.151 2.712 6.229 ;
     RECT  12.096 3.349 14.232 6.229 ;
     RECT  27.456 5.893 51.312 6.757 ;
     RECT  2.4 6.229 3 6.805 ;
     RECT  7.8 2.151 8.112 6.853 ;
     RECT  15.36 5.605 19.608 6.853 ;
     RECT  6.96 6.853 8.112 6.995 ;
     RECT  7.8 6.995 8.112 7.285 ;
     RECT  2.4 6.805 3.336 7.381 ;
     RECT  11.472 6.229 14.232 7.381 ;
     RECT  15.264 6.853 19.608 7.381 ;
     RECT  11.472 7.381 19.608 7.909 ;
     RECT  20.64 4.261 20.664 7.909 ;
     RECT  7.8 7.285 8.808 8.291 ;
     RECT  11.472 7.909 20.664 8.579 ;
     RECT  2.4 7.381 3.96 8.869 ;
     RECT  2.4 8.869 4.344 9.925 ;
     RECT  11.472 8.579 19.8 9.925 ;
     RECT  2.4 9.925 4.92 10.309 ;
     RECT  5.904 10.021 5.928 10.309 ;
     RECT  7.8 8.291 8.112 10.357 ;
     RECT  2.4 10.309 5.928 11.365 ;
     RECT  11.472 9.925 20.712 12.469 ;
     RECT  2.4 11.365 6.504 12.517 ;
     RECT  7.8 10.357 8.376 12.517 ;
     RECT  22.368 5.077 26.28 12.517 ;
     RECT  27.312 6.757 51.312 12.517 ;
     RECT  22.368 12.517 51.312 12.997 ;
     RECT  22.32 12.997 51.312 13.045 ;
     RECT  2.4 12.517 8.376 13.381 ;
     RECT  9.552 13.045 9.576 13.381 ;
     RECT  2.4 13.381 9.768 14.005 ;
     RECT  10.896 12.469 20.712 14.005 ;
     RECT  2.4 14.005 20.712 14.149 ;
     RECT  21.984 13.045 51.312 14.149 ;
     RECT  2.4 14.149 51.312 16.117 ;
     RECT  54.672 16.309 54.696 17.459 ;
     RECT  2.4 16.117 51.432 17.699 ;
     RECT  2.4 17.699 51.312 22.549 ;
     RECT  52.512 23.653 52.536 24.181 ;
     RECT  2.4 22.549 51.432 26.485 ;
     RECT  2.4 26.485 51.48 26.771 ;
     RECT  2.4 26.771 51.432 29.029 ;
     RECT  52.464 24.181 52.536 29.317 ;
     RECT  2.304 29.029 51.432 30.085 ;
     RECT  52.464 29.317 53.208 30.085 ;
     RECT  2.304 30.085 53.208 40.883 ;
     RECT  2.4 40.883 53.208 43.045 ;
     RECT  2.4 43.045 53.832 43.285 ;
     RECT  2.304 43.285 53.832 47.075 ;
     RECT  0.144 21.589 0.168 47.459 ;
     RECT  2.4 47.075 53.832 50.629 ;
     RECT  2.304 50.629 53.832 57.635 ;
     RECT  2.4 57.635 53.832 62.821 ;
     RECT  55.968 62.677 55.992 62.963 ;
     RECT  2.4 62.821 54.744 64.933 ;
     RECT  2.4 64.933 54.984 65.221 ;
     RECT  2.304 65.221 54.984 66.613 ;
     RECT  2.304 66.613 55.032 73.477 ;
     RECT  1.296 75.205 1.32 78.709 ;
     RECT  2.304 73.477 55.08 78.709 ;
     RECT  1.296 78.709 55.08 79.811 ;
     RECT  1.296 79.811 54.984 80.963 ;
     RECT  1.296 80.963 10.872 81.635 ;
     RECT  11.904 80.963 54.984 82.069 ;
     RECT  4.368 81.635 10.872 82.163 ;
     RECT  4.512 82.163 10.872 82.643 ;
     RECT  11.904 82.069 55.032 82.643 ;
     RECT  4.512 82.643 10.104 82.691 ;
     RECT  11.904 82.643 20.52 82.691 ;
     RECT  21.504 82.643 55.032 82.691 ;
     RECT  4.512 82.691 9.672 82.739 ;
     RECT  11.904 82.691 13.608 82.739 ;
     RECT  14.592 82.691 15.048 82.739 ;
     RECT  31.2 82.691 55.032 82.739 ;
     RECT  21.504 82.691 30.168 82.787 ;
     RECT  1.296 81.635 3.144 83.797 ;
     RECT  4.512 82.739 5.544 83.797 ;
     RECT  6.864 82.739 9.672 83.797 ;
     RECT  11.952 82.739 13.608 83.797 ;
     RECT  14.976 82.739 15.048 83.797 ;
     RECT  16.08 82.691 20.52 83.797 ;
     RECT  21.504 82.787 24.456 83.797 ;
     RECT  25.536 82.787 30.168 83.797 ;
     RECT  31.536 82.739 55.032 83.797 ;
     RECT  1.296 83.797 13.992 84.181 ;
     RECT  14.976 83.797 55.032 84.181 ;
     RECT  1.296 84.181 55.032 86.352 ;
     RECT  38.712 2.677 40.2 3.877 ;
     RECT  40.512 2.725 41.76 2.821 ;
     RECT  17.016 2.821 18.48 3.109 ;
     RECT  22.392 2.821 23.904 3.445 ;
     RECT  32.376 2.821 33.456 3.925 ;
     RECT  33.48 2.821 34.8 4.453 ;
     RECT  37.176 2.821 38.688 3.301 ;
     RECT  40.512 2.821 41.568 4.501 ;
     RECT  14.232 3.157 15.36 6.853 ;
     RECT  37.32 3.301 38.688 3.925 ;
     RECT  24.696 3.349 25.92 3.397 ;
     RECT  22.488 3.445 23.904 3.925 ;
     RECT  28.2 3.445 29.184 4.933 ;
     RECT  38.76 3.877 40.2 3.925 ;
     RECT  29.712 3.925 31.152 4.261 ;
     RECT  31.176 3.925 32.352 4.453 ;
     RECT  32.376 3.925 33.408 4.501 ;
     RECT  38.76 3.925 39.936 5.605 ;
     RECT  26.232 4.117 27.456 5.077 ;
     RECT  19.272 4.261 20.64 5.605 ;
     RECT  29.712 4.261 30.912 5.653 ;
     RECT  35.784 4.261 37.152 4.453 ;
     RECT  26.28 5.077 27.456 6.757 ;
     RECT  19.608 5.605 20.64 7.909 ;
     RECT  26.28 6.757 27.312 12.517 ;
     RECT  14.232 6.853 15.264 7.381 ;
     RECT  19.8 8.579 20.664 9.925 ;
     RECT  4.92 10.021 5.904 10.309 ;
     RECT  6.504 11.365 7.8 12.517 ;
     RECT  8.376 13.045 9.552 13.381 ;
     RECT  9.576 13.045 10.896 13.381 ;
     RECT  20.712 13.045 21.984 14.149 ;
     RECT  9.768 13.381 10.896 14.005 ;
     RECT  51.432 23.653 52.512 24.181 ;
     RECT  51.432 24.181 52.464 26.485 ;
     RECT  51.48 26.485 52.464 26.771 ;
     RECT  51.432 26.771 52.464 30.085 ;
     RECT  54.744 62.821 55.968 62.963 ;
     RECT  1.32 75.205 2.304 78.709 ;
     RECT  10.872 80.963 11.904 82.643 ;
     RECT  3.144 81.635 4.368 82.163 ;
     RECT  3.144 82.163 4.512 83.797 ;
     RECT  10.104 82.643 11.904 82.691 ;
     RECT  20.52 82.643 21.504 83.797 ;
     RECT  9.672 82.691 11.904 82.739 ;
     RECT  13.608 82.691 14.592 82.739 ;
     RECT  15.048 82.691 16.08 83.797 ;
     RECT  30.168 82.691 31.2 82.739 ;
     RECT  5.544 82.739 6.864 83.797 ;
     RECT  9.672 82.739 11.952 83.797 ;
     RECT  13.608 82.739 14.976 83.797 ;
     RECT  30.168 82.739 31.536 83.797 ;
     RECT  24.456 82.787 25.536 83.797 ;
     RECT  13.992 83.797 14.976 84.181 ;
  END
END ot_hgi_b2_dma_serial
END LIBRARY
